VERSION 5.8 ;
BUSBITCHARS "[]" ;
DIVIDERCHAR "/" ;
UNITS
    DATABASE MICRONS 1000 ;
END UNITS

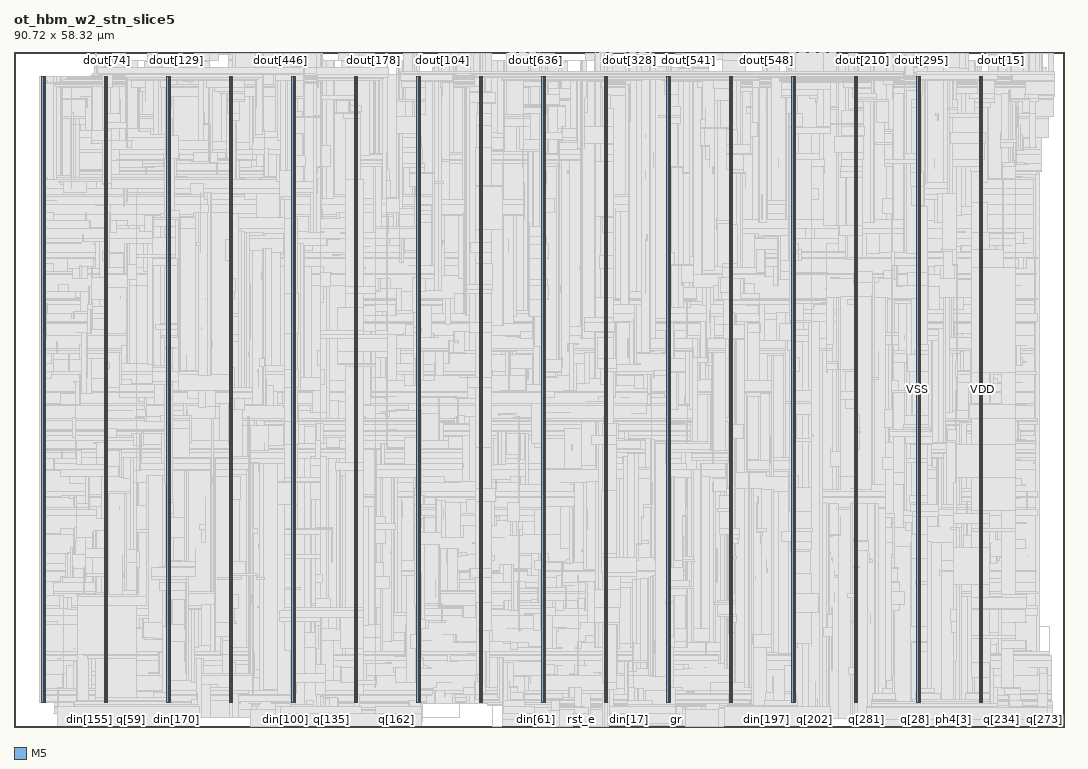
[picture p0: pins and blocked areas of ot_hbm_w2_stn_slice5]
MACRO ot_hbm_w2_stn_slice5
  FOREIGN ot_hbm_w2_stn_slice5 0 0 ;
  CLASS BLOCK ;
  SIZE 90.72 BY 58.32 ;
  PIN clk
    DIRECTION INPUT ;
    USE SIGNAL ;
    PORT
      LAYER M5 ;
        RECT  51.408 0 51.432 0.084 ;
    END
  END clk
  PIN din[0]
    DIRECTION INPUT ;
    USE SIGNAL ;
    PORT
      LAYER M5 ;
        RECT  51.504 0 51.528 0.084 ;
    END
  END din[0]
  PIN din[100]
    DIRECTION INPUT ;
    USE SIGNAL ;
    PORT
      LAYER M5 ;
        RECT  23.472 0 23.496 0.084 ;
    END
  END din[100]
  PIN din[101]
    DIRECTION INPUT ;
    USE SIGNAL ;
    PORT
      LAYER M5 ;
        RECT  23.568 0 23.592 0.084 ;
    END
  END din[101]
  PIN din[102]
    DIRECTION INPUT ;
    USE SIGNAL ;
    PORT
      LAYER M5 ;
        RECT  23.664 0 23.688 0.084 ;
    END
  END din[102]
  PIN din[103]
    DIRECTION INPUT ;
    USE SIGNAL ;
    PORT
      LAYER M5 ;
        RECT  23.76 0 23.784 0.084 ;
    END
  END din[103]
  PIN din[104]
    DIRECTION INPUT ;
    USE SIGNAL ;
    PORT
      LAYER M5 ;
        RECT  23.856 0 23.88 0.084 ;
    END
  END din[104]
  PIN din[105]
    DIRECTION INPUT ;
    USE SIGNAL ;
    PORT
      LAYER M5 ;
        RECT  23.952 0 23.976 0.084 ;
    END
  END din[105]
  PIN din[106]
    DIRECTION INPUT ;
    USE SIGNAL ;
    PORT
      LAYER M5 ;
        RECT  24.048 0 24.072 0.084 ;
    END
  END din[106]
  PIN din[107]
    DIRECTION INPUT ;
    USE SIGNAL ;
    PORT
      LAYER M5 ;
        RECT  24.144 0 24.168 0.084 ;
    END
  END din[107]
  PIN din[108]
    DIRECTION INPUT ;
    USE SIGNAL ;
    PORT
      LAYER M5 ;
        RECT  24.24 0 24.264 0.084 ;
    END
  END din[108]
  PIN din[109]
    DIRECTION INPUT ;
    USE SIGNAL ;
    PORT
      LAYER M5 ;
        RECT  24.336 0 24.36 0.084 ;
    END
  END din[109]
  PIN din[10]
    DIRECTION INPUT ;
    USE SIGNAL ;
    PORT
      LAYER M5 ;
        RECT  52.464 0 52.488 0.084 ;
    END
  END din[10]
  PIN din[110]
    DIRECTION INPUT ;
    USE SIGNAL ;
    PORT
      LAYER M5 ;
        RECT  24.432 0 24.456 0.084 ;
    END
  END din[110]
  PIN din[111]
    DIRECTION INPUT ;
    USE SIGNAL ;
    PORT
      LAYER M5 ;
        RECT  24.528 0 24.552 0.084 ;
    END
  END din[111]
  PIN din[112]
    DIRECTION INPUT ;
    USE SIGNAL ;
    PORT
      LAYER M5 ;
        RECT  24.624 0 24.648 0.084 ;
    END
  END din[112]
  PIN din[113]
    DIRECTION INPUT ;
    USE SIGNAL ;
    PORT
      LAYER M5 ;
        RECT  24.72 0 24.744 0.084 ;
    END
  END din[113]
  PIN din[114]
    DIRECTION INPUT ;
    USE SIGNAL ;
    PORT
      LAYER M5 ;
        RECT  24.816 0 24.84 0.084 ;
    END
  END din[114]
  PIN din[115]
    DIRECTION INPUT ;
    USE SIGNAL ;
    PORT
      LAYER M5 ;
        RECT  24.912 0 24.936 0.084 ;
    END
  END din[115]
  PIN din[116]
    DIRECTION INPUT ;
    USE SIGNAL ;
    PORT
      LAYER M5 ;
        RECT  25.008 0 25.032 0.084 ;
    END
  END din[116]
  PIN din[117]
    DIRECTION INPUT ;
    USE SIGNAL ;
    PORT
      LAYER M5 ;
        RECT  25.104 0 25.128 0.084 ;
    END
  END din[117]
  PIN din[118]
    DIRECTION INPUT ;
    USE SIGNAL ;
    PORT
      LAYER M5 ;
        RECT  25.2 0 25.224 0.084 ;
    END
  END din[118]
  PIN din[119]
    DIRECTION INPUT ;
    USE SIGNAL ;
    PORT
      LAYER M5 ;
        RECT  25.296 0 25.32 0.084 ;
    END
  END din[119]
  PIN din[11]
    DIRECTION INPUT ;
    USE SIGNAL ;
    PORT
      LAYER M5 ;
        RECT  52.56 0 52.584 0.084 ;
    END
  END din[11]
  PIN din[120]
    DIRECTION INPUT ;
    USE SIGNAL ;
    PORT
      LAYER M5 ;
        RECT  25.392 0 25.416 0.084 ;
    END
  END din[120]
  PIN din[121]
    DIRECTION INPUT ;
    USE SIGNAL ;
    PORT
      LAYER M5 ;
        RECT  25.488 0 25.512 0.084 ;
    END
  END din[121]
  PIN din[122]
    DIRECTION INPUT ;
    USE SIGNAL ;
    PORT
      LAYER M5 ;
        RECT  25.584 0 25.608 0.084 ;
    END
  END din[122]
  PIN din[123]
    DIRECTION INPUT ;
    USE SIGNAL ;
    PORT
      LAYER M5 ;
        RECT  25.68 0 25.704 0.084 ;
    END
  END din[123]
  PIN din[124]
    DIRECTION INPUT ;
    USE SIGNAL ;
    PORT
      LAYER M5 ;
        RECT  25.776 0 25.8 0.084 ;
    END
  END din[124]
  PIN din[125]
    DIRECTION INPUT ;
    USE SIGNAL ;
    PORT
      LAYER M5 ;
        RECT  25.872 0 25.896 0.084 ;
    END
  END din[125]
  PIN din[126]
    DIRECTION INPUT ;
    USE SIGNAL ;
    PORT
      LAYER M5 ;
        RECT  25.968 0 25.992 0.084 ;
    END
  END din[126]
  PIN din[127]
    DIRECTION INPUT ;
    USE SIGNAL ;
    PORT
      LAYER M5 ;
        RECT  3.792 0 3.816 0.084 ;
    END
  END din[127]
  PIN din[128]
    DIRECTION INPUT ;
    USE SIGNAL ;
    PORT
      LAYER M5 ;
        RECT  3.888 0 3.912 0.084 ;
    END
  END din[128]
  PIN din[129]
    DIRECTION INPUT ;
    USE SIGNAL ;
    PORT
      LAYER M5 ;
        RECT  3.984 0 4.008 0.084 ;
    END
  END din[129]
  PIN din[12]
    DIRECTION INPUT ;
    USE SIGNAL ;
    PORT
      LAYER M5 ;
        RECT  52.656 0 52.68 0.084 ;
    END
  END din[12]
  PIN din[130]
    DIRECTION INPUT ;
    USE SIGNAL ;
    PORT
      LAYER M5 ;
        RECT  4.08 0 4.104 0.084 ;
    END
  END din[130]
  PIN din[131]
    DIRECTION INPUT ;
    USE SIGNAL ;
    PORT
      LAYER M5 ;
        RECT  4.176 0 4.2 0.084 ;
    END
  END din[131]
  PIN din[132]
    DIRECTION INPUT ;
    USE SIGNAL ;
    PORT
      LAYER M5 ;
        RECT  4.272 0 4.296 0.084 ;
    END
  END din[132]
  PIN din[133]
    DIRECTION INPUT ;
    USE SIGNAL ;
    PORT
      LAYER M5 ;
        RECT  4.368 0 4.392 0.084 ;
    END
  END din[133]
  PIN din[134]
    DIRECTION INPUT ;
    USE SIGNAL ;
    PORT
      LAYER M5 ;
        RECT  4.464 0 4.488 0.084 ;
    END
  END din[134]
  PIN din[135]
    DIRECTION INPUT ;
    USE SIGNAL ;
    PORT
      LAYER M5 ;
        RECT  4.56 0 4.584 0.084 ;
    END
  END din[135]
  PIN din[136]
    DIRECTION INPUT ;
    USE SIGNAL ;
    PORT
      LAYER M5 ;
        RECT  4.656 0 4.68 0.084 ;
    END
  END din[136]
  PIN din[137]
    DIRECTION INPUT ;
    USE SIGNAL ;
    PORT
      LAYER M5 ;
        RECT  4.752 0 4.776 0.084 ;
    END
  END din[137]
  PIN din[138]
    DIRECTION INPUT ;
    USE SIGNAL ;
    PORT
      LAYER M5 ;
        RECT  4.848 0 4.872 0.084 ;
    END
  END din[138]
  PIN din[139]
    DIRECTION INPUT ;
    USE SIGNAL ;
    PORT
      LAYER M5 ;
        RECT  4.944 0 4.968 0.084 ;
    END
  END din[139]
  PIN din[13]
    DIRECTION INPUT ;
    USE SIGNAL ;
    PORT
      LAYER M5 ;
        RECT  52.752 0 52.776 0.084 ;
    END
  END din[13]
  PIN din[140]
    DIRECTION INPUT ;
    USE SIGNAL ;
    PORT
      LAYER M5 ;
        RECT  5.04 0 5.064 0.084 ;
    END
  END din[140]
  PIN din[141]
    DIRECTION INPUT ;
    USE SIGNAL ;
    PORT
      LAYER M5 ;
        RECT  5.136 0 5.16 0.084 ;
    END
  END din[141]
  PIN din[142]
    DIRECTION INPUT ;
    USE SIGNAL ;
    PORT
      LAYER M5 ;
        RECT  5.232 0 5.256 0.084 ;
    END
  END din[142]
  PIN din[143]
    DIRECTION INPUT ;
    USE SIGNAL ;
    PORT
      LAYER M5 ;
        RECT  5.328 0 5.352 0.084 ;
    END
  END din[143]
  PIN din[144]
    DIRECTION INPUT ;
    USE SIGNAL ;
    PORT
      LAYER M5 ;
        RECT  5.424 0 5.448 0.084 ;
    END
  END din[144]
  PIN din[145]
    DIRECTION INPUT ;
    USE SIGNAL ;
    PORT
      LAYER M5 ;
        RECT  5.52 0 5.544 0.084 ;
    END
  END din[145]
  PIN din[146]
    DIRECTION INPUT ;
    USE SIGNAL ;
    PORT
      LAYER M5 ;
        RECT  5.616 0 5.64 0.084 ;
    END
  END din[146]
  PIN din[147]
    DIRECTION INPUT ;
    USE SIGNAL ;
    PORT
      LAYER M5 ;
        RECT  5.712 0 5.736 0.084 ;
    END
  END din[147]
  PIN din[148]
    DIRECTION INPUT ;
    USE SIGNAL ;
    PORT
      LAYER M5 ;
        RECT  5.808 0 5.832 0.084 ;
    END
  END din[148]
  PIN din[149]
    DIRECTION INPUT ;
    USE SIGNAL ;
    PORT
      LAYER M5 ;
        RECT  5.904 0 5.928 0.084 ;
    END
  END din[149]
  PIN din[14]
    DIRECTION INPUT ;
    USE SIGNAL ;
    PORT
      LAYER M5 ;
        RECT  52.848 0 52.872 0.084 ;
    END
  END din[14]
  PIN din[150]
    DIRECTION INPUT ;
    USE SIGNAL ;
    PORT
      LAYER M5 ;
        RECT  6 0 6.024 0.084 ;
    END
  END din[150]
  PIN din[151]
    DIRECTION INPUT ;
    USE SIGNAL ;
    PORT
      LAYER M5 ;
        RECT  6.096 0 6.12 0.084 ;
    END
  END din[151]
  PIN din[152]
    DIRECTION INPUT ;
    USE SIGNAL ;
    PORT
      LAYER M5 ;
        RECT  6.192 0 6.216 0.084 ;
    END
  END din[152]
  PIN din[153]
    DIRECTION INPUT ;
    USE SIGNAL ;
    PORT
      LAYER M5 ;
        RECT  6.288 0 6.312 0.084 ;
    END
  END din[153]
  PIN din[154]
    DIRECTION INPUT ;
    USE SIGNAL ;
    PORT
      LAYER M5 ;
        RECT  6.384 0 6.408 0.084 ;
    END
  END din[154]
  PIN din[155]
    DIRECTION INPUT ;
    USE SIGNAL ;
    PORT
      LAYER M5 ;
        RECT  6.48 0 6.504 0.084 ;
    END
  END din[155]
  PIN din[156]
    DIRECTION INPUT ;
    USE SIGNAL ;
    PORT
      LAYER M5 ;
        RECT  6.576 0 6.6 0.084 ;
    END
  END din[156]
  PIN din[157]
    DIRECTION INPUT ;
    USE SIGNAL ;
    PORT
      LAYER M5 ;
        RECT  6.672 0 6.696 0.084 ;
    END
  END din[157]
  PIN din[158]
    DIRECTION INPUT ;
    USE SIGNAL ;
    PORT
      LAYER M5 ;
        RECT  6.768 0 6.792 0.084 ;
    END
  END din[158]
  PIN din[159]
    DIRECTION INPUT ;
    USE SIGNAL ;
    PORT
      LAYER M5 ;
        RECT  13.008 0 13.032 0.084 ;
    END
  END din[159]
  PIN din[15]
    DIRECTION INPUT ;
    USE SIGNAL ;
    PORT
      LAYER M5 ;
        RECT  52.944 0 52.968 0.084 ;
    END
  END din[15]
  PIN din[160]
    DIRECTION INPUT ;
    USE SIGNAL ;
    PORT
      LAYER M5 ;
        RECT  13.104 0 13.128 0.084 ;
    END
  END din[160]
  PIN din[161]
    DIRECTION INPUT ;
    USE SIGNAL ;
    PORT
      LAYER M5 ;
        RECT  13.2 0 13.224 0.084 ;
    END
  END din[161]
  PIN din[162]
    DIRECTION INPUT ;
    USE SIGNAL ;
    PORT
      LAYER M5 ;
        RECT  13.296 0 13.32 0.084 ;
    END
  END din[162]
  PIN din[163]
    DIRECTION INPUT ;
    USE SIGNAL ;
    PORT
      LAYER M5 ;
        RECT  13.392 0 13.416 0.084 ;
    END
  END din[163]
  PIN din[164]
    DIRECTION INPUT ;
    USE SIGNAL ;
    PORT
      LAYER M5 ;
        RECT  13.488 0 13.512 0.084 ;
    END
  END din[164]
  PIN din[165]
    DIRECTION INPUT ;
    USE SIGNAL ;
    PORT
      LAYER M5 ;
        RECT  13.584 0 13.608 0.084 ;
    END
  END din[165]
  PIN din[166]
    DIRECTION INPUT ;
    USE SIGNAL ;
    PORT
      LAYER M5 ;
        RECT  13.68 0 13.704 0.084 ;
    END
  END din[166]
  PIN din[167]
    DIRECTION INPUT ;
    USE SIGNAL ;
    PORT
      LAYER M5 ;
        RECT  13.776 0 13.8 0.084 ;
    END
  END din[167]
  PIN din[168]
    DIRECTION INPUT ;
    USE SIGNAL ;
    PORT
      LAYER M5 ;
        RECT  13.872 0 13.896 0.084 ;
    END
  END din[168]
  PIN din[169]
    DIRECTION INPUT ;
    USE SIGNAL ;
    PORT
      LAYER M5 ;
        RECT  13.968 0 13.992 0.084 ;
    END
  END din[169]
  PIN din[16]
    DIRECTION INPUT ;
    USE SIGNAL ;
    PORT
      LAYER M5 ;
        RECT  53.04 0 53.064 0.084 ;
    END
  END din[16]
  PIN din[170]
    DIRECTION INPUT ;
    USE SIGNAL ;
    PORT
      LAYER M5 ;
        RECT  14.064 0 14.088 0.084 ;
    END
  END din[170]
  PIN din[171]
    DIRECTION INPUT ;
    USE SIGNAL ;
    PORT
      LAYER M5 ;
        RECT  14.16 0 14.184 0.084 ;
    END
  END din[171]
  PIN din[172]
    DIRECTION INPUT ;
    USE SIGNAL ;
    PORT
      LAYER M5 ;
        RECT  14.256 0 14.28 0.084 ;
    END
  END din[172]
  PIN din[173]
    DIRECTION INPUT ;
    USE SIGNAL ;
    PORT
      LAYER M5 ;
        RECT  14.352 0 14.376 0.084 ;
    END
  END din[173]
  PIN din[174]
    DIRECTION INPUT ;
    USE SIGNAL ;
    PORT
      LAYER M5 ;
        RECT  14.448 0 14.472 0.084 ;
    END
  END din[174]
  PIN din[175]
    DIRECTION INPUT ;
    USE SIGNAL ;
    PORT
      LAYER M5 ;
        RECT  14.544 0 14.568 0.084 ;
    END
  END din[175]
  PIN din[176]
    DIRECTION INPUT ;
    USE SIGNAL ;
    PORT
      LAYER M5 ;
        RECT  14.64 0 14.664 0.084 ;
    END
  END din[176]
  PIN din[177]
    DIRECTION INPUT ;
    USE SIGNAL ;
    PORT
      LAYER M5 ;
        RECT  14.736 0 14.76 0.084 ;
    END
  END din[177]
  PIN din[178]
    DIRECTION INPUT ;
    USE SIGNAL ;
    PORT
      LAYER M5 ;
        RECT  14.832 0 14.856 0.084 ;
    END
  END din[178]
  PIN din[179]
    DIRECTION INPUT ;
    USE SIGNAL ;
    PORT
      LAYER M5 ;
        RECT  14.928 0 14.952 0.084 ;
    END
  END din[179]
  PIN din[17]
    DIRECTION INPUT ;
    USE SIGNAL ;
    PORT
      LAYER M5 ;
        RECT  53.136 0 53.16 0.084 ;
    END
  END din[17]
  PIN din[180]
    DIRECTION INPUT ;
    USE SIGNAL ;
    PORT
      LAYER M5 ;
        RECT  15.024 0 15.048 0.084 ;
    END
  END din[180]
  PIN din[181]
    DIRECTION INPUT ;
    USE SIGNAL ;
    PORT
      LAYER M5 ;
        RECT  15.12 0 15.144 0.084 ;
    END
  END din[181]
  PIN din[182]
    DIRECTION INPUT ;
    USE SIGNAL ;
    PORT
      LAYER M5 ;
        RECT  15.216 0 15.24 0.084 ;
    END
  END din[182]
  PIN din[183]
    DIRECTION INPUT ;
    USE SIGNAL ;
    PORT
      LAYER M5 ;
        RECT  15.312 0 15.336 0.084 ;
    END
  END din[183]
  PIN din[184]
    DIRECTION INPUT ;
    USE SIGNAL ;
    PORT
      LAYER M5 ;
        RECT  15.408 0 15.432 0.084 ;
    END
  END din[184]
  PIN din[185]
    DIRECTION INPUT ;
    USE SIGNAL ;
    PORT
      LAYER M5 ;
        RECT  15.504 0 15.528 0.084 ;
    END
  END din[185]
  PIN din[186]
    DIRECTION INPUT ;
    USE SIGNAL ;
    PORT
      LAYER M5 ;
        RECT  15.6 0 15.624 0.084 ;
    END
  END din[186]
  PIN din[187]
    DIRECTION INPUT ;
    USE SIGNAL ;
    PORT
      LAYER M5 ;
        RECT  15.696 0 15.72 0.084 ;
    END
  END din[187]
  PIN din[188]
    DIRECTION INPUT ;
    USE SIGNAL ;
    PORT
      LAYER M5 ;
        RECT  15.792 0 15.816 0.084 ;
    END
  END din[188]
  PIN din[189]
    DIRECTION INPUT ;
    USE SIGNAL ;
    PORT
      LAYER M5 ;
        RECT  15.888 0 15.912 0.084 ;
    END
  END din[189]
  PIN din[18]
    DIRECTION INPUT ;
    USE SIGNAL ;
    PORT
      LAYER M5 ;
        RECT  53.232 0 53.256 0.084 ;
    END
  END din[18]
  PIN din[190]
    DIRECTION INPUT ;
    USE SIGNAL ;
    PORT
      LAYER M5 ;
        RECT  15.984 0 16.008 0.084 ;
    END
  END din[190]
  PIN din[191]
    DIRECTION INPUT ;
    USE SIGNAL ;
    PORT
      LAYER M5 ;
        RECT  64.464 0 64.488 0.084 ;
    END
  END din[191]
  PIN din[192]
    DIRECTION INPUT ;
    USE SIGNAL ;
    PORT
      LAYER M5 ;
        RECT  64.56 0 64.584 0.084 ;
    END
  END din[192]
  PIN din[193]
    DIRECTION INPUT ;
    USE SIGNAL ;
    PORT
      LAYER M5 ;
        RECT  64.656 0 64.68 0.084 ;
    END
  END din[193]
  PIN din[194]
    DIRECTION INPUT ;
    USE SIGNAL ;
    PORT
      LAYER M5 ;
        RECT  64.752 0 64.776 0.084 ;
    END
  END din[194]
  PIN din[195]
    DIRECTION INPUT ;
    USE SIGNAL ;
    PORT
      LAYER M5 ;
        RECT  64.848 0 64.872 0.084 ;
    END
  END din[195]
  PIN din[196]
    DIRECTION INPUT ;
    USE SIGNAL ;
    PORT
      LAYER M5 ;
        RECT  64.944 0 64.968 0.084 ;
    END
  END din[196]
  PIN din[197]
    DIRECTION INPUT ;
    USE SIGNAL ;
    PORT
      LAYER M5 ;
        RECT  65.04 0 65.064 0.084 ;
    END
  END din[197]
  PIN din[198]
    DIRECTION INPUT ;
    USE SIGNAL ;
    PORT
      LAYER M5 ;
        RECT  65.136 0 65.16 0.084 ;
    END
  END din[198]
  PIN din[199]
    DIRECTION INPUT ;
    USE SIGNAL ;
    PORT
      LAYER M5 ;
        RECT  65.232 0 65.256 0.084 ;
    END
  END din[199]
  PIN din[19]
    DIRECTION INPUT ;
    USE SIGNAL ;
    PORT
      LAYER M5 ;
        RECT  53.328 0 53.352 0.084 ;
    END
  END din[19]
  PIN din[1]
    DIRECTION INPUT ;
    USE SIGNAL ;
    PORT
      LAYER M5 ;
        RECT  51.6 0 51.624 0.084 ;
    END
  END din[1]
  PIN din[200]
    DIRECTION INPUT ;
    USE SIGNAL ;
    PORT
      LAYER M5 ;
        RECT  65.328 0 65.352 0.084 ;
    END
  END din[200]
  PIN din[201]
    DIRECTION INPUT ;
    USE SIGNAL ;
    PORT
      LAYER M5 ;
        RECT  65.424 0 65.448 0.084 ;
    END
  END din[201]
  PIN din[202]
    DIRECTION INPUT ;
    USE SIGNAL ;
    PORT
      LAYER M5 ;
        RECT  65.52 0 65.544 0.084 ;
    END
  END din[202]
  PIN din[203]
    DIRECTION INPUT ;
    USE SIGNAL ;
    PORT
      LAYER M5 ;
        RECT  65.616 0 65.64 0.084 ;
    END
  END din[203]
  PIN din[204]
    DIRECTION INPUT ;
    USE SIGNAL ;
    PORT
      LAYER M5 ;
        RECT  65.712 0 65.736 0.084 ;
    END
  END din[204]
  PIN din[205]
    DIRECTION INPUT ;
    USE SIGNAL ;
    PORT
      LAYER M5 ;
        RECT  65.808 0 65.832 0.084 ;
    END
  END din[205]
  PIN din[206]
    DIRECTION INPUT ;
    USE SIGNAL ;
    PORT
      LAYER M5 ;
        RECT  65.904 0 65.928 0.084 ;
    END
  END din[206]
  PIN din[207]
    DIRECTION INPUT ;
    USE SIGNAL ;
    PORT
      LAYER M5 ;
        RECT  66 0 66.024 0.084 ;
    END
  END din[207]
  PIN din[208]
    DIRECTION INPUT ;
    USE SIGNAL ;
    PORT
      LAYER M5 ;
        RECT  66.096 0 66.12 0.084 ;
    END
  END din[208]
  PIN din[209]
    DIRECTION INPUT ;
    USE SIGNAL ;
    PORT
      LAYER M5 ;
        RECT  66.192 0 66.216 0.084 ;
    END
  END din[209]
  PIN din[20]
    DIRECTION INPUT ;
    USE SIGNAL ;
    PORT
      LAYER M5 ;
        RECT  53.424 0 53.448 0.084 ;
    END
  END din[20]
  PIN din[210]
    DIRECTION INPUT ;
    USE SIGNAL ;
    PORT
      LAYER M5 ;
        RECT  66.288 0 66.312 0.084 ;
    END
  END din[210]
  PIN din[211]
    DIRECTION INPUT ;
    USE SIGNAL ;
    PORT
      LAYER M5 ;
        RECT  66.384 0 66.408 0.084 ;
    END
  END din[211]
  PIN din[212]
    DIRECTION INPUT ;
    USE SIGNAL ;
    PORT
      LAYER M5 ;
        RECT  66.48 0 66.504 0.084 ;
    END
  END din[212]
  PIN din[213]
    DIRECTION INPUT ;
    USE SIGNAL ;
    PORT
      LAYER M5 ;
        RECT  66.576 0 66.6 0.084 ;
    END
  END din[213]
  PIN din[214]
    DIRECTION INPUT ;
    USE SIGNAL ;
    PORT
      LAYER M5 ;
        RECT  66.672 0 66.696 0.084 ;
    END
  END din[214]
  PIN din[215]
    DIRECTION INPUT ;
    USE SIGNAL ;
    PORT
      LAYER M5 ;
        RECT  66.768 0 66.792 0.084 ;
    END
  END din[215]
  PIN din[216]
    DIRECTION INPUT ;
    USE SIGNAL ;
    PORT
      LAYER M5 ;
        RECT  66.864 0 66.888 0.084 ;
    END
  END din[216]
  PIN din[217]
    DIRECTION INPUT ;
    USE SIGNAL ;
    PORT
      LAYER M5 ;
        RECT  66.96 0 66.984 0.084 ;
    END
  END din[217]
  PIN din[218]
    DIRECTION INPUT ;
    USE SIGNAL ;
    PORT
      LAYER M5 ;
        RECT  67.056 0 67.08 0.084 ;
    END
  END din[218]
  PIN din[219]
    DIRECTION INPUT ;
    USE SIGNAL ;
    PORT
      LAYER M5 ;
        RECT  67.152 0 67.176 0.084 ;
    END
  END din[219]
  PIN din[21]
    DIRECTION INPUT ;
    USE SIGNAL ;
    PORT
      LAYER M5 ;
        RECT  53.52 0 53.544 0.084 ;
    END
  END din[21]
  PIN din[220]
    DIRECTION INPUT ;
    USE SIGNAL ;
    PORT
      LAYER M5 ;
        RECT  67.248 0 67.272 0.084 ;
    END
  END din[220]
  PIN din[221]
    DIRECTION INPUT ;
    USE SIGNAL ;
    PORT
      LAYER M5 ;
        RECT  67.344 0 67.368 0.084 ;
    END
  END din[221]
  PIN din[222]
    DIRECTION INPUT ;
    USE SIGNAL ;
    PORT
      LAYER M5 ;
        RECT  67.44 0 67.464 0.084 ;
    END
  END din[222]
  PIN din[223]
    DIRECTION INPUT ;
    USE SIGNAL ;
    PORT
      LAYER M5 ;
        RECT  61.392 0 61.416 0.084 ;
    END
  END din[223]
  PIN din[224]
    DIRECTION INPUT ;
    USE SIGNAL ;
    PORT
      LAYER M5 ;
        RECT  61.488 0 61.512 0.084 ;
    END
  END din[224]
  PIN din[225]
    DIRECTION INPUT ;
    USE SIGNAL ;
    PORT
      LAYER M5 ;
        RECT  61.584 0 61.608 0.084 ;
    END
  END din[225]
  PIN din[226]
    DIRECTION INPUT ;
    USE SIGNAL ;
    PORT
      LAYER M5 ;
        RECT  61.68 0 61.704 0.084 ;
    END
  END din[226]
  PIN din[227]
    DIRECTION INPUT ;
    USE SIGNAL ;
    PORT
      LAYER M5 ;
        RECT  61.776 0 61.8 0.084 ;
    END
  END din[227]
  PIN din[228]
    DIRECTION INPUT ;
    USE SIGNAL ;
    PORT
      LAYER M5 ;
        RECT  61.872 0 61.896 0.084 ;
    END
  END din[228]
  PIN din[229]
    DIRECTION INPUT ;
    USE SIGNAL ;
    PORT
      LAYER M5 ;
        RECT  61.968 0 61.992 0.084 ;
    END
  END din[229]
  PIN din[22]
    DIRECTION INPUT ;
    USE SIGNAL ;
    PORT
      LAYER M5 ;
        RECT  53.616 0 53.64 0.084 ;
    END
  END din[22]
  PIN din[230]
    DIRECTION INPUT ;
    USE SIGNAL ;
    PORT
      LAYER M5 ;
        RECT  62.064 0 62.088 0.084 ;
    END
  END din[230]
  PIN din[231]
    DIRECTION INPUT ;
    USE SIGNAL ;
    PORT
      LAYER M5 ;
        RECT  62.16 0 62.184 0.084 ;
    END
  END din[231]
  PIN din[232]
    DIRECTION INPUT ;
    USE SIGNAL ;
    PORT
      LAYER M5 ;
        RECT  62.256 0 62.28 0.084 ;
    END
  END din[232]
  PIN din[233]
    DIRECTION INPUT ;
    USE SIGNAL ;
    PORT
      LAYER M5 ;
        RECT  62.352 0 62.376 0.084 ;
    END
  END din[233]
  PIN din[234]
    DIRECTION INPUT ;
    USE SIGNAL ;
    PORT
      LAYER M5 ;
        RECT  62.448 0 62.472 0.084 ;
    END
  END din[234]
  PIN din[235]
    DIRECTION INPUT ;
    USE SIGNAL ;
    PORT
      LAYER M5 ;
        RECT  62.544 0 62.568 0.084 ;
    END
  END din[235]
  PIN din[236]
    DIRECTION INPUT ;
    USE SIGNAL ;
    PORT
      LAYER M5 ;
        RECT  62.64 0 62.664 0.084 ;
    END
  END din[236]
  PIN din[237]
    DIRECTION INPUT ;
    USE SIGNAL ;
    PORT
      LAYER M5 ;
        RECT  62.736 0 62.76 0.084 ;
    END
  END din[237]
  PIN din[238]
    DIRECTION INPUT ;
    USE SIGNAL ;
    PORT
      LAYER M5 ;
        RECT  62.832 0 62.856 0.084 ;
    END
  END din[238]
  PIN din[239]
    DIRECTION INPUT ;
    USE SIGNAL ;
    PORT
      LAYER M5 ;
        RECT  62.928 0 62.952 0.084 ;
    END
  END din[239]
  PIN din[23]
    DIRECTION INPUT ;
    USE SIGNAL ;
    PORT
      LAYER M5 ;
        RECT  53.712 0 53.736 0.084 ;
    END
  END din[23]
  PIN din[240]
    DIRECTION INPUT ;
    USE SIGNAL ;
    PORT
      LAYER M5 ;
        RECT  63.024 0 63.048 0.084 ;
    END
  END din[240]
  PIN din[241]
    DIRECTION INPUT ;
    USE SIGNAL ;
    PORT
      LAYER M5 ;
        RECT  63.12 0 63.144 0.084 ;
    END
  END din[241]
  PIN din[242]
    DIRECTION INPUT ;
    USE SIGNAL ;
    PORT
      LAYER M5 ;
        RECT  63.216 0 63.24 0.084 ;
    END
  END din[242]
  PIN din[243]
    DIRECTION INPUT ;
    USE SIGNAL ;
    PORT
      LAYER M5 ;
        RECT  63.312 0 63.336 0.084 ;
    END
  END din[243]
  PIN din[244]
    DIRECTION INPUT ;
    USE SIGNAL ;
    PORT
      LAYER M5 ;
        RECT  63.408 0 63.432 0.084 ;
    END
  END din[244]
  PIN din[245]
    DIRECTION INPUT ;
    USE SIGNAL ;
    PORT
      LAYER M5 ;
        RECT  63.504 0 63.528 0.084 ;
    END
  END din[245]
  PIN din[246]
    DIRECTION INPUT ;
    USE SIGNAL ;
    PORT
      LAYER M5 ;
        RECT  63.6 0 63.624 0.084 ;
    END
  END din[246]
  PIN din[247]
    DIRECTION INPUT ;
    USE SIGNAL ;
    PORT
      LAYER M5 ;
        RECT  63.696 0 63.72 0.084 ;
    END
  END din[247]
  PIN din[248]
    DIRECTION INPUT ;
    USE SIGNAL ;
    PORT
      LAYER M5 ;
        RECT  63.792 0 63.816 0.084 ;
    END
  END din[248]
  PIN din[249]
    DIRECTION INPUT ;
    USE SIGNAL ;
    PORT
      LAYER M5 ;
        RECT  63.888 0 63.912 0.084 ;
    END
  END din[249]
  PIN din[24]
    DIRECTION INPUT ;
    USE SIGNAL ;
    PORT
      LAYER M5 ;
        RECT  53.808 0 53.832 0.084 ;
    END
  END din[24]
  PIN din[250]
    DIRECTION INPUT ;
    USE SIGNAL ;
    PORT
      LAYER M5 ;
        RECT  63.984 0 64.008 0.084 ;
    END
  END din[250]
  PIN din[251]
    DIRECTION INPUT ;
    USE SIGNAL ;
    PORT
      LAYER M5 ;
        RECT  64.08 0 64.104 0.084 ;
    END
  END din[251]
  PIN din[252]
    DIRECTION INPUT ;
    USE SIGNAL ;
    PORT
      LAYER M5 ;
        RECT  64.176 0 64.2 0.084 ;
    END
  END din[252]
  PIN din[253]
    DIRECTION INPUT ;
    USE SIGNAL ;
    PORT
      LAYER M5 ;
        RECT  64.272 0 64.296 0.084 ;
    END
  END din[253]
  PIN din[254]
    DIRECTION INPUT ;
    USE SIGNAL ;
    PORT
      LAYER M5 ;
        RECT  64.368 0 64.392 0.084 ;
    END
  END din[254]
  PIN din[255]
    DIRECTION INPUT ;
    USE SIGNAL ;
    PORT
      LAYER M5 ;
        RECT  54.48 0 54.504 0.084 ;
    END
  END din[255]
  PIN din[256]
    DIRECTION INPUT ;
    USE SIGNAL ;
    PORT
      LAYER M5 ;
        RECT  54.576 0 54.6 0.084 ;
    END
  END din[256]
  PIN din[257]
    DIRECTION INPUT ;
    USE SIGNAL ;
    PORT
      LAYER M5 ;
        RECT  54.672 0 54.696 0.084 ;
    END
  END din[257]
  PIN din[258]
    DIRECTION INPUT ;
    USE SIGNAL ;
    PORT
      LAYER M5 ;
        RECT  54.768 0 54.792 0.084 ;
    END
  END din[258]
  PIN din[259]
    DIRECTION INPUT ;
    USE SIGNAL ;
    PORT
      LAYER M5 ;
        RECT  54.864 0 54.888 0.084 ;
    END
  END din[259]
  PIN din[25]
    DIRECTION INPUT ;
    USE SIGNAL ;
    PORT
      LAYER M5 ;
        RECT  53.904 0 53.928 0.084 ;
    END
  END din[25]
  PIN din[260]
    DIRECTION INPUT ;
    USE SIGNAL ;
    PORT
      LAYER M5 ;
        RECT  54.96 0 54.984 0.084 ;
    END
  END din[260]
  PIN din[261]
    DIRECTION INPUT ;
    USE SIGNAL ;
    PORT
      LAYER M5 ;
        RECT  55.056 0 55.08 0.084 ;
    END
  END din[261]
  PIN din[262]
    DIRECTION INPUT ;
    USE SIGNAL ;
    PORT
      LAYER M5 ;
        RECT  55.152 0 55.176 0.084 ;
    END
  END din[262]
  PIN din[263]
    DIRECTION INPUT ;
    USE SIGNAL ;
    PORT
      LAYER M5 ;
        RECT  55.248 0 55.272 0.084 ;
    END
  END din[263]
  PIN din[264]
    DIRECTION INPUT ;
    USE SIGNAL ;
    PORT
      LAYER M5 ;
        RECT  55.344 0 55.368 0.084 ;
    END
  END din[264]
  PIN din[265]
    DIRECTION INPUT ;
    USE SIGNAL ;
    PORT
      LAYER M5 ;
        RECT  55.44 0 55.464 0.084 ;
    END
  END din[265]
  PIN din[266]
    DIRECTION INPUT ;
    USE SIGNAL ;
    PORT
      LAYER M5 ;
        RECT  55.536 0 55.56 0.084 ;
    END
  END din[266]
  PIN din[267]
    DIRECTION INPUT ;
    USE SIGNAL ;
    PORT
      LAYER M5 ;
        RECT  55.632 0 55.656 0.084 ;
    END
  END din[267]
  PIN din[268]
    DIRECTION INPUT ;
    USE SIGNAL ;
    PORT
      LAYER M5 ;
        RECT  55.728 0 55.752 0.084 ;
    END
  END din[268]
  PIN din[269]
    DIRECTION INPUT ;
    USE SIGNAL ;
    PORT
      LAYER M5 ;
        RECT  55.824 0 55.848 0.084 ;
    END
  END din[269]
  PIN din[26]
    DIRECTION INPUT ;
    USE SIGNAL ;
    PORT
      LAYER M5 ;
        RECT  54 0 54.024 0.084 ;
    END
  END din[26]
  PIN din[270]
    DIRECTION INPUT ;
    USE SIGNAL ;
    PORT
      LAYER M5 ;
        RECT  55.92 0 55.944 0.084 ;
    END
  END din[270]
  PIN din[271]
    DIRECTION INPUT ;
    USE SIGNAL ;
    PORT
      LAYER M5 ;
        RECT  56.016 0 56.04 0.084 ;
    END
  END din[271]
  PIN din[272]
    DIRECTION INPUT ;
    USE SIGNAL ;
    PORT
      LAYER M5 ;
        RECT  56.112 0 56.136 0.084 ;
    END
  END din[272]
  PIN din[273]
    DIRECTION INPUT ;
    USE SIGNAL ;
    PORT
      LAYER M5 ;
        RECT  56.208 0 56.232 0.084 ;
    END
  END din[273]
  PIN din[274]
    DIRECTION INPUT ;
    USE SIGNAL ;
    PORT
      LAYER M5 ;
        RECT  56.304 0 56.328 0.084 ;
    END
  END din[274]
  PIN din[275]
    DIRECTION INPUT ;
    USE SIGNAL ;
    PORT
      LAYER M5 ;
        RECT  56.4 0 56.424 0.084 ;
    END
  END din[275]
  PIN din[276]
    DIRECTION INPUT ;
    USE SIGNAL ;
    PORT
      LAYER M5 ;
        RECT  56.496 0 56.52 0.084 ;
    END
  END din[276]
  PIN din[277]
    DIRECTION INPUT ;
    USE SIGNAL ;
    PORT
      LAYER M5 ;
        RECT  56.592 0 56.616 0.084 ;
    END
  END din[277]
  PIN din[278]
    DIRECTION INPUT ;
    USE SIGNAL ;
    PORT
      LAYER M5 ;
        RECT  56.688 0 56.712 0.084 ;
    END
  END din[278]
  PIN din[279]
    DIRECTION INPUT ;
    USE SIGNAL ;
    PORT
      LAYER M5 ;
        RECT  56.784 0 56.808 0.084 ;
    END
  END din[279]
  PIN din[27]
    DIRECTION INPUT ;
    USE SIGNAL ;
    PORT
      LAYER M5 ;
        RECT  54.096 0 54.12 0.084 ;
    END
  END din[27]
  PIN din[28]
    DIRECTION INPUT ;
    USE SIGNAL ;
    PORT
      LAYER M5 ;
        RECT  54.192 0 54.216 0.084 ;
    END
  END din[28]
  PIN din[29]
    DIRECTION INPUT ;
    USE SIGNAL ;
    PORT
      LAYER M5 ;
        RECT  54.288 0 54.312 0.084 ;
    END
  END din[29]
  PIN din[2]
    DIRECTION INPUT ;
    USE SIGNAL ;
    PORT
      LAYER M5 ;
        RECT  51.696 0 51.72 0.084 ;
    END
  END din[2]
  PIN din[30]
    DIRECTION INPUT ;
    USE SIGNAL ;
    PORT
      LAYER M5 ;
        RECT  54.384 0 54.408 0.084 ;
    END
  END din[30]
  PIN din[31]
    DIRECTION INPUT ;
    USE SIGNAL ;
    PORT
      LAYER M5 ;
        RECT  42.192 0 42.216 0.084 ;
    END
  END din[31]
  PIN din[32]
    DIRECTION INPUT ;
    USE SIGNAL ;
    PORT
      LAYER M5 ;
        RECT  42.288 0 42.312 0.084 ;
    END
  END din[32]
  PIN din[33]
    DIRECTION INPUT ;
    USE SIGNAL ;
    PORT
      LAYER M5 ;
        RECT  42.384 0 42.408 0.084 ;
    END
  END din[33]
  PIN din[34]
    DIRECTION INPUT ;
    USE SIGNAL ;
    PORT
      LAYER M5 ;
        RECT  42.48 0 42.504 0.084 ;
    END
  END din[34]
  PIN din[35]
    DIRECTION INPUT ;
    USE SIGNAL ;
    PORT
      LAYER M5 ;
        RECT  42.576 0 42.6 0.084 ;
    END
  END din[35]
  PIN din[36]
    DIRECTION INPUT ;
    USE SIGNAL ;
    PORT
      LAYER M5 ;
        RECT  42.672 0 42.696 0.084 ;
    END
  END din[36]
  PIN din[37]
    DIRECTION INPUT ;
    USE SIGNAL ;
    PORT
      LAYER M5 ;
        RECT  42.768 0 42.792 0.084 ;
    END
  END din[37]
  PIN din[38]
    DIRECTION INPUT ;
    USE SIGNAL ;
    PORT
      LAYER M5 ;
        RECT  42.864 0 42.888 0.084 ;
    END
  END din[38]
  PIN din[39]
    DIRECTION INPUT ;
    USE SIGNAL ;
    PORT
      LAYER M5 ;
        RECT  42.96 0 42.984 0.084 ;
    END
  END din[39]
  PIN din[3]
    DIRECTION INPUT ;
    USE SIGNAL ;
    PORT
      LAYER M5 ;
        RECT  51.792 0 51.816 0.084 ;
    END
  END din[3]
  PIN din[40]
    DIRECTION INPUT ;
    USE SIGNAL ;
    PORT
      LAYER M5 ;
        RECT  43.056 0 43.08 0.084 ;
    END
  END din[40]
  PIN din[41]
    DIRECTION INPUT ;
    USE SIGNAL ;
    PORT
      LAYER M5 ;
        RECT  43.152 0 43.176 0.084 ;
    END
  END din[41]
  PIN din[42]
    DIRECTION INPUT ;
    USE SIGNAL ;
    PORT
      LAYER M5 ;
        RECT  43.248 0 43.272 0.084 ;
    END
  END din[42]
  PIN din[43]
    DIRECTION INPUT ;
    USE SIGNAL ;
    PORT
      LAYER M5 ;
        RECT  43.344 0 43.368 0.084 ;
    END
  END din[43]
  PIN din[44]
    DIRECTION INPUT ;
    USE SIGNAL ;
    PORT
      LAYER M5 ;
        RECT  43.44 0 43.464 0.084 ;
    END
  END din[44]
  PIN din[45]
    DIRECTION INPUT ;
    USE SIGNAL ;
    PORT
      LAYER M5 ;
        RECT  43.536 0 43.56 0.084 ;
    END
  END din[45]
  PIN din[46]
    DIRECTION INPUT ;
    USE SIGNAL ;
    PORT
      LAYER M5 ;
        RECT  43.632 0 43.656 0.084 ;
    END
  END din[46]
  PIN din[47]
    DIRECTION INPUT ;
    USE SIGNAL ;
    PORT
      LAYER M5 ;
        RECT  43.728 0 43.752 0.084 ;
    END
  END din[47]
  PIN din[48]
    DIRECTION INPUT ;
    USE SIGNAL ;
    PORT
      LAYER M5 ;
        RECT  43.824 0 43.848 0.084 ;
    END
  END din[48]
  PIN din[49]
    DIRECTION INPUT ;
    USE SIGNAL ;
    PORT
      LAYER M5 ;
        RECT  43.92 0 43.944 0.084 ;
    END
  END din[49]
  PIN din[4]
    DIRECTION INPUT ;
    USE SIGNAL ;
    PORT
      LAYER M5 ;
        RECT  51.888 0 51.912 0.084 ;
    END
  END din[4]
  PIN din[50]
    DIRECTION INPUT ;
    USE SIGNAL ;
    PORT
      LAYER M5 ;
        RECT  44.016 0 44.04 0.084 ;
    END
  END din[50]
  PIN din[51]
    DIRECTION INPUT ;
    USE SIGNAL ;
    PORT
      LAYER M5 ;
        RECT  44.112 0 44.136 0.084 ;
    END
  END din[51]
  PIN din[52]
    DIRECTION INPUT ;
    USE SIGNAL ;
    PORT
      LAYER M5 ;
        RECT  44.208 0 44.232 0.084 ;
    END
  END din[52]
  PIN din[53]
    DIRECTION INPUT ;
    USE SIGNAL ;
    PORT
      LAYER M5 ;
        RECT  44.304 0 44.328 0.084 ;
    END
  END din[53]
  PIN din[54]
    DIRECTION INPUT ;
    USE SIGNAL ;
    PORT
      LAYER M5 ;
        RECT  44.4 0 44.424 0.084 ;
    END
  END din[54]
  PIN din[55]
    DIRECTION INPUT ;
    USE SIGNAL ;
    PORT
      LAYER M5 ;
        RECT  44.496 0 44.52 0.084 ;
    END
  END din[55]
  PIN din[56]
    DIRECTION INPUT ;
    USE SIGNAL ;
    PORT
      LAYER M5 ;
        RECT  44.592 0 44.616 0.084 ;
    END
  END din[56]
  PIN din[57]
    DIRECTION INPUT ;
    USE SIGNAL ;
    PORT
      LAYER M5 ;
        RECT  44.688 0 44.712 0.084 ;
    END
  END din[57]
  PIN din[58]
    DIRECTION INPUT ;
    USE SIGNAL ;
    PORT
      LAYER M5 ;
        RECT  44.784 0 44.808 0.084 ;
    END
  END din[58]
  PIN din[59]
    DIRECTION INPUT ;
    USE SIGNAL ;
    PORT
      LAYER M5 ;
        RECT  44.88 0 44.904 0.084 ;
    END
  END din[59]
  PIN din[5]
    DIRECTION INPUT ;
    USE SIGNAL ;
    PORT
      LAYER M5 ;
        RECT  51.984 0 52.008 0.084 ;
    END
  END din[5]
  PIN din[60]
    DIRECTION INPUT ;
    USE SIGNAL ;
    PORT
      LAYER M5 ;
        RECT  44.976 0 45 0.084 ;
    END
  END din[60]
  PIN din[61]
    DIRECTION INPUT ;
    USE SIGNAL ;
    PORT
      LAYER M5 ;
        RECT  45.072 0 45.096 0.084 ;
    END
  END din[61]
  PIN din[62]
    DIRECTION INPUT ;
    USE SIGNAL ;
    PORT
      LAYER M5 ;
        RECT  45.168 0 45.192 0.084 ;
    END
  END din[62]
  PIN din[63]
    DIRECTION INPUT ;
    USE SIGNAL ;
    PORT
      LAYER M5 ;
        RECT  6.864 0 6.888 0.084 ;
    END
  END din[63]
  PIN din[64]
    DIRECTION INPUT ;
    USE SIGNAL ;
    PORT
      LAYER M5 ;
        RECT  6.96 0 6.984 0.084 ;
    END
  END din[64]
  PIN din[65]
    DIRECTION INPUT ;
    USE SIGNAL ;
    PORT
      LAYER M5 ;
        RECT  7.056 0 7.08 0.084 ;
    END
  END din[65]
  PIN din[66]
    DIRECTION INPUT ;
    USE SIGNAL ;
    PORT
      LAYER M5 ;
        RECT  7.152 0 7.176 0.084 ;
    END
  END din[66]
  PIN din[67]
    DIRECTION INPUT ;
    USE SIGNAL ;
    PORT
      LAYER M5 ;
        RECT  7.248 0 7.272 0.084 ;
    END
  END din[67]
  PIN din[68]
    DIRECTION INPUT ;
    USE SIGNAL ;
    PORT
      LAYER M5 ;
        RECT  7.344 0 7.368 0.084 ;
    END
  END din[68]
  PIN din[69]
    DIRECTION INPUT ;
    USE SIGNAL ;
    PORT
      LAYER M5 ;
        RECT  7.44 0 7.464 0.084 ;
    END
  END din[69]
  PIN din[6]
    DIRECTION INPUT ;
    USE SIGNAL ;
    PORT
      LAYER M5 ;
        RECT  52.08 0 52.104 0.084 ;
    END
  END din[6]
  PIN din[70]
    DIRECTION INPUT ;
    USE SIGNAL ;
    PORT
      LAYER M5 ;
        RECT  7.536 0 7.56 0.084 ;
    END
  END din[70]
  PIN din[71]
    DIRECTION INPUT ;
    USE SIGNAL ;
    PORT
      LAYER M5 ;
        RECT  7.632 0 7.656 0.084 ;
    END
  END din[71]
  PIN din[72]
    DIRECTION INPUT ;
    USE SIGNAL ;
    PORT
      LAYER M5 ;
        RECT  7.728 0 7.752 0.084 ;
    END
  END din[72]
  PIN din[73]
    DIRECTION INPUT ;
    USE SIGNAL ;
    PORT
      LAYER M5 ;
        RECT  7.824 0 7.848 0.084 ;
    END
  END din[73]
  PIN din[74]
    DIRECTION INPUT ;
    USE SIGNAL ;
    PORT
      LAYER M5 ;
        RECT  7.92 0 7.944 0.084 ;
    END
  END din[74]
  PIN din[75]
    DIRECTION INPUT ;
    USE SIGNAL ;
    PORT
      LAYER M5 ;
        RECT  8.016 0 8.04 0.084 ;
    END
  END din[75]
  PIN din[76]
    DIRECTION INPUT ;
    USE SIGNAL ;
    PORT
      LAYER M5 ;
        RECT  8.112 0 8.136 0.084 ;
    END
  END din[76]
  PIN din[77]
    DIRECTION INPUT ;
    USE SIGNAL ;
    PORT
      LAYER M5 ;
        RECT  8.208 0 8.232 0.084 ;
    END
  END din[77]
  PIN din[78]
    DIRECTION INPUT ;
    USE SIGNAL ;
    PORT
      LAYER M5 ;
        RECT  8.304 0 8.328 0.084 ;
    END
  END din[78]
  PIN din[79]
    DIRECTION INPUT ;
    USE SIGNAL ;
    PORT
      LAYER M5 ;
        RECT  8.4 0 8.424 0.084 ;
    END
  END din[79]
  PIN din[7]
    DIRECTION INPUT ;
    USE SIGNAL ;
    PORT
      LAYER M5 ;
        RECT  52.176 0 52.2 0.084 ;
    END
  END din[7]
  PIN din[80]
    DIRECTION INPUT ;
    USE SIGNAL ;
    PORT
      LAYER M5 ;
        RECT  8.496 0 8.52 0.084 ;
    END
  END din[80]
  PIN din[81]
    DIRECTION INPUT ;
    USE SIGNAL ;
    PORT
      LAYER M5 ;
        RECT  8.592 0 8.616 0.084 ;
    END
  END din[81]
  PIN din[82]
    DIRECTION INPUT ;
    USE SIGNAL ;
    PORT
      LAYER M5 ;
        RECT  8.688 0 8.712 0.084 ;
    END
  END din[82]
  PIN din[83]
    DIRECTION INPUT ;
    USE SIGNAL ;
    PORT
      LAYER M5 ;
        RECT  8.784 0 8.808 0.084 ;
    END
  END din[83]
  PIN din[84]
    DIRECTION INPUT ;
    USE SIGNAL ;
    PORT
      LAYER M5 ;
        RECT  8.88 0 8.904 0.084 ;
    END
  END din[84]
  PIN din[85]
    DIRECTION INPUT ;
    USE SIGNAL ;
    PORT
      LAYER M5 ;
        RECT  8.976 0 9 0.084 ;
    END
  END din[85]
  PIN din[86]
    DIRECTION INPUT ;
    USE SIGNAL ;
    PORT
      LAYER M5 ;
        RECT  9.072 0 9.096 0.084 ;
    END
  END din[86]
  PIN din[87]
    DIRECTION INPUT ;
    USE SIGNAL ;
    PORT
      LAYER M5 ;
        RECT  9.168 0 9.192 0.084 ;
    END
  END din[87]
  PIN din[88]
    DIRECTION INPUT ;
    USE SIGNAL ;
    PORT
      LAYER M5 ;
        RECT  9.264 0 9.288 0.084 ;
    END
  END din[88]
  PIN din[89]
    DIRECTION INPUT ;
    USE SIGNAL ;
    PORT
      LAYER M5 ;
        RECT  9.36 0 9.384 0.084 ;
    END
  END din[89]
  PIN din[8]
    DIRECTION INPUT ;
    USE SIGNAL ;
    PORT
      LAYER M5 ;
        RECT  52.272 0 52.296 0.084 ;
    END
  END din[8]
  PIN din[90]
    DIRECTION INPUT ;
    USE SIGNAL ;
    PORT
      LAYER M5 ;
        RECT  9.456 0 9.48 0.084 ;
    END
  END din[90]
  PIN din[91]
    DIRECTION INPUT ;
    USE SIGNAL ;
    PORT
      LAYER M5 ;
        RECT  9.552 0 9.576 0.084 ;
    END
  END din[91]
  PIN din[92]
    DIRECTION INPUT ;
    USE SIGNAL ;
    PORT
      LAYER M5 ;
        RECT  9.648 0 9.672 0.084 ;
    END
  END din[92]
  PIN din[93]
    DIRECTION INPUT ;
    USE SIGNAL ;
    PORT
      LAYER M5 ;
        RECT  9.744 0 9.768 0.084 ;
    END
  END din[93]
  PIN din[94]
    DIRECTION INPUT ;
    USE SIGNAL ;
    PORT
      LAYER M5 ;
        RECT  9.84 0 9.864 0.084 ;
    END
  END din[94]
  PIN din[95]
    DIRECTION INPUT ;
    USE SIGNAL ;
    PORT
      LAYER M5 ;
        RECT  22.992 0 23.016 0.084 ;
    END
  END din[95]
  PIN din[96]
    DIRECTION INPUT ;
    USE SIGNAL ;
    PORT
      LAYER M5 ;
        RECT  23.088 0 23.112 0.084 ;
    END
  END din[96]
  PIN din[97]
    DIRECTION INPUT ;
    USE SIGNAL ;
    PORT
      LAYER M5 ;
        RECT  23.184 0 23.208 0.084 ;
    END
  END din[97]
  PIN din[98]
    DIRECTION INPUT ;
    USE SIGNAL ;
    PORT
      LAYER M5 ;
        RECT  23.28 0 23.304 0.084 ;
    END
  END din[98]
  PIN din[99]
    DIRECTION INPUT ;
    USE SIGNAL ;
    PORT
      LAYER M5 ;
        RECT  23.376 0 23.4 0.084 ;
    END
  END din[99]
  PIN din[9]
    DIRECTION INPUT ;
    USE SIGNAL ;
    PORT
      LAYER M5 ;
        RECT  52.368 0 52.392 0.084 ;
    END
  END din[9]
  PIN dout[0]
    DIRECTION OUTPUT ;
    USE SIGNAL ;
    PORT
      LAYER M5 ;
        RECT  83.856 58.236 83.88 58.32 ;
    END
  END dout[0]
  PIN dout[100]
    DIRECTION OUTPUT ;
    USE SIGNAL ;
    PORT
      LAYER M5 ;
        RECT  36.624 58.236 36.648 58.32 ;
    END
  END dout[100]
  PIN dout[101]
    DIRECTION OUTPUT ;
    USE SIGNAL ;
    PORT
      LAYER M5 ;
        RECT  36.72 58.236 36.744 58.32 ;
    END
  END dout[101]
  PIN dout[102]
    DIRECTION OUTPUT ;
    USE SIGNAL ;
    PORT
      LAYER M5 ;
        RECT  36.816 58.236 36.84 58.32 ;
    END
  END dout[102]
  PIN dout[103]
    DIRECTION OUTPUT ;
    USE SIGNAL ;
    PORT
      LAYER M5 ;
        RECT  36.912 58.236 36.936 58.32 ;
    END
  END dout[103]
  PIN dout[104]
    DIRECTION OUTPUT ;
    USE SIGNAL ;
    PORT
      LAYER M5 ;
        RECT  37.008 58.236 37.032 58.32 ;
    END
  END dout[104]
  PIN dout[105]
    DIRECTION OUTPUT ;
    USE SIGNAL ;
    PORT
      LAYER M5 ;
        RECT  37.104 58.236 37.128 58.32 ;
    END
  END dout[105]
  PIN dout[106]
    DIRECTION OUTPUT ;
    USE SIGNAL ;
    PORT
      LAYER M5 ;
        RECT  37.2 58.236 37.224 58.32 ;
    END
  END dout[106]
  PIN dout[107]
    DIRECTION OUTPUT ;
    USE SIGNAL ;
    PORT
      LAYER M5 ;
        RECT  37.296 58.236 37.32 58.32 ;
    END
  END dout[107]
  PIN dout[108]
    DIRECTION OUTPUT ;
    USE SIGNAL ;
    PORT
      LAYER M5 ;
        RECT  37.392 58.236 37.416 58.32 ;
    END
  END dout[108]
  PIN dout[109]
    DIRECTION OUTPUT ;
    USE SIGNAL ;
    PORT
      LAYER M5 ;
        RECT  37.488 58.236 37.512 58.32 ;
    END
  END dout[109]
  PIN dout[10]
    DIRECTION OUTPUT ;
    USE SIGNAL ;
    PORT
      LAYER M5 ;
        RECT  84.816 58.236 84.84 58.32 ;
    END
  END dout[10]
  PIN dout[110]
    DIRECTION OUTPUT ;
    USE SIGNAL ;
    PORT
      LAYER M5 ;
        RECT  37.584 58.236 37.608 58.32 ;
    END
  END dout[110]
  PIN dout[111]
    DIRECTION OUTPUT ;
    USE SIGNAL ;
    PORT
      LAYER M5 ;
        RECT  37.68 58.236 37.704 58.32 ;
    END
  END dout[111]
  PIN dout[112]
    DIRECTION OUTPUT ;
    USE SIGNAL ;
    PORT
      LAYER M5 ;
        RECT  37.776 58.236 37.8 58.32 ;
    END
  END dout[112]
  PIN dout[113]
    DIRECTION OUTPUT ;
    USE SIGNAL ;
    PORT
      LAYER M5 ;
        RECT  37.872 58.236 37.896 58.32 ;
    END
  END dout[113]
  PIN dout[114]
    DIRECTION OUTPUT ;
    USE SIGNAL ;
    PORT
      LAYER M5 ;
        RECT  37.968 58.236 37.992 58.32 ;
    END
  END dout[114]
  PIN dout[115]
    DIRECTION OUTPUT ;
    USE SIGNAL ;
    PORT
      LAYER M5 ;
        RECT  38.064 58.236 38.088 58.32 ;
    END
  END dout[115]
  PIN dout[116]
    DIRECTION OUTPUT ;
    USE SIGNAL ;
    PORT
      LAYER M5 ;
        RECT  38.16 58.236 38.184 58.32 ;
    END
  END dout[116]
  PIN dout[117]
    DIRECTION OUTPUT ;
    USE SIGNAL ;
    PORT
      LAYER M5 ;
        RECT  38.256 58.236 38.28 58.32 ;
    END
  END dout[117]
  PIN dout[118]
    DIRECTION OUTPUT ;
    USE SIGNAL ;
    PORT
      LAYER M5 ;
        RECT  38.352 58.236 38.376 58.32 ;
    END
  END dout[118]
  PIN dout[119]
    DIRECTION OUTPUT ;
    USE SIGNAL ;
    PORT
      LAYER M5 ;
        RECT  38.448 58.236 38.472 58.32 ;
    END
  END dout[119]
  PIN dout[11]
    DIRECTION OUTPUT ;
    USE SIGNAL ;
    PORT
      LAYER M5 ;
        RECT  84.912 58.236 84.936 58.32 ;
    END
  END dout[11]
  PIN dout[120]
    DIRECTION OUTPUT ;
    USE SIGNAL ;
    PORT
      LAYER M5 ;
        RECT  38.544 58.236 38.568 58.32 ;
    END
  END dout[120]
  PIN dout[121]
    DIRECTION OUTPUT ;
    USE SIGNAL ;
    PORT
      LAYER M5 ;
        RECT  38.64 58.236 38.664 58.32 ;
    END
  END dout[121]
  PIN dout[122]
    DIRECTION OUTPUT ;
    USE SIGNAL ;
    PORT
      LAYER M5 ;
        RECT  38.736 58.236 38.76 58.32 ;
    END
  END dout[122]
  PIN dout[123]
    DIRECTION OUTPUT ;
    USE SIGNAL ;
    PORT
      LAYER M5 ;
        RECT  38.832 58.236 38.856 58.32 ;
    END
  END dout[123]
  PIN dout[124]
    DIRECTION OUTPUT ;
    USE SIGNAL ;
    PORT
      LAYER M5 ;
        RECT  38.928 58.236 38.952 58.32 ;
    END
  END dout[124]
  PIN dout[125]
    DIRECTION OUTPUT ;
    USE SIGNAL ;
    PORT
      LAYER M5 ;
        RECT  39.024 58.236 39.048 58.32 ;
    END
  END dout[125]
  PIN dout[126]
    DIRECTION OUTPUT ;
    USE SIGNAL ;
    PORT
      LAYER M5 ;
        RECT  39.12 58.236 39.144 58.32 ;
    END
  END dout[126]
  PIN dout[127]
    DIRECTION OUTPUT ;
    USE SIGNAL ;
    PORT
      LAYER M5 ;
        RECT  39.216 58.236 39.24 58.32 ;
    END
  END dout[127]
  PIN dout[128]
    DIRECTION OUTPUT ;
    USE SIGNAL ;
    PORT
      LAYER M5 ;
        RECT  13.968 58.236 13.992 58.32 ;
    END
  END dout[128]
  PIN dout[129]
    DIRECTION OUTPUT ;
    USE SIGNAL ;
    PORT
      LAYER M5 ;
        RECT  14.064 58.236 14.088 58.32 ;
    END
  END dout[129]
  PIN dout[12]
    DIRECTION OUTPUT ;
    USE SIGNAL ;
    PORT
      LAYER M5 ;
        RECT  85.008 58.236 85.032 58.32 ;
    END
  END dout[12]
  PIN dout[130]
    DIRECTION OUTPUT ;
    USE SIGNAL ;
    PORT
      LAYER M5 ;
        RECT  14.16 58.236 14.184 58.32 ;
    END
  END dout[130]
  PIN dout[131]
    DIRECTION OUTPUT ;
    USE SIGNAL ;
    PORT
      LAYER M5 ;
        RECT  14.256 58.236 14.28 58.32 ;
    END
  END dout[131]
  PIN dout[132]
    DIRECTION OUTPUT ;
    USE SIGNAL ;
    PORT
      LAYER M5 ;
        RECT  14.352 58.236 14.376 58.32 ;
    END
  END dout[132]
  PIN dout[133]
    DIRECTION OUTPUT ;
    USE SIGNAL ;
    PORT
      LAYER M5 ;
        RECT  14.448 58.236 14.472 58.32 ;
    END
  END dout[133]
  PIN dout[134]
    DIRECTION OUTPUT ;
    USE SIGNAL ;
    PORT
      LAYER M5 ;
        RECT  14.544 58.236 14.568 58.32 ;
    END
  END dout[134]
  PIN dout[135]
    DIRECTION OUTPUT ;
    USE SIGNAL ;
    PORT
      LAYER M5 ;
        RECT  14.64 58.236 14.664 58.32 ;
    END
  END dout[135]
  PIN dout[136]
    DIRECTION OUTPUT ;
    USE SIGNAL ;
    PORT
      LAYER M5 ;
        RECT  14.736 58.236 14.76 58.32 ;
    END
  END dout[136]
  PIN dout[137]
    DIRECTION OUTPUT ;
    USE SIGNAL ;
    PORT
      LAYER M5 ;
        RECT  14.832 58.236 14.856 58.32 ;
    END
  END dout[137]
  PIN dout[138]
    DIRECTION OUTPUT ;
    USE SIGNAL ;
    PORT
      LAYER M5 ;
        RECT  14.928 58.236 14.952 58.32 ;
    END
  END dout[138]
  PIN dout[139]
    DIRECTION OUTPUT ;
    USE SIGNAL ;
    PORT
      LAYER M5 ;
        RECT  15.024 58.236 15.048 58.32 ;
    END
  END dout[139]
  PIN dout[13]
    DIRECTION OUTPUT ;
    USE SIGNAL ;
    PORT
      LAYER M5 ;
        RECT  85.104 58.236 85.128 58.32 ;
    END
  END dout[13]
  PIN dout[140]
    DIRECTION OUTPUT ;
    USE SIGNAL ;
    PORT
      LAYER M5 ;
        RECT  15.12 58.236 15.144 58.32 ;
    END
  END dout[140]
  PIN dout[141]
    DIRECTION OUTPUT ;
    USE SIGNAL ;
    PORT
      LAYER M5 ;
        RECT  15.216 58.236 15.24 58.32 ;
    END
  END dout[141]
  PIN dout[142]
    DIRECTION OUTPUT ;
    USE SIGNAL ;
    PORT
      LAYER M5 ;
        RECT  15.312 58.236 15.336 58.32 ;
    END
  END dout[142]
  PIN dout[143]
    DIRECTION OUTPUT ;
    USE SIGNAL ;
    PORT
      LAYER M5 ;
        RECT  15.408 58.236 15.432 58.32 ;
    END
  END dout[143]
  PIN dout[144]
    DIRECTION OUTPUT ;
    USE SIGNAL ;
    PORT
      LAYER M5 ;
        RECT  15.504 58.236 15.528 58.32 ;
    END
  END dout[144]
  PIN dout[145]
    DIRECTION OUTPUT ;
    USE SIGNAL ;
    PORT
      LAYER M5 ;
        RECT  15.6 58.236 15.624 58.32 ;
    END
  END dout[145]
  PIN dout[146]
    DIRECTION OUTPUT ;
    USE SIGNAL ;
    PORT
      LAYER M5 ;
        RECT  15.696 58.236 15.72 58.32 ;
    END
  END dout[146]
  PIN dout[147]
    DIRECTION OUTPUT ;
    USE SIGNAL ;
    PORT
      LAYER M5 ;
        RECT  15.792 58.236 15.816 58.32 ;
    END
  END dout[147]
  PIN dout[148]
    DIRECTION OUTPUT ;
    USE SIGNAL ;
    PORT
      LAYER M5 ;
        RECT  15.888 58.236 15.912 58.32 ;
    END
  END dout[148]
  PIN dout[149]
    DIRECTION OUTPUT ;
    USE SIGNAL ;
    PORT
      LAYER M5 ;
        RECT  15.984 58.236 16.008 58.32 ;
    END
  END dout[149]
  PIN dout[14]
    DIRECTION OUTPUT ;
    USE SIGNAL ;
    PORT
      LAYER M5 ;
        RECT  85.2 58.236 85.224 58.32 ;
    END
  END dout[14]
  PIN dout[150]
    DIRECTION OUTPUT ;
    USE SIGNAL ;
    PORT
      LAYER M5 ;
        RECT  16.08 58.236 16.104 58.32 ;
    END
  END dout[150]
  PIN dout[151]
    DIRECTION OUTPUT ;
    USE SIGNAL ;
    PORT
      LAYER M5 ;
        RECT  16.176 58.236 16.2 58.32 ;
    END
  END dout[151]
  PIN dout[152]
    DIRECTION OUTPUT ;
    USE SIGNAL ;
    PORT
      LAYER M5 ;
        RECT  16.272 58.236 16.296 58.32 ;
    END
  END dout[152]
  PIN dout[153]
    DIRECTION OUTPUT ;
    USE SIGNAL ;
    PORT
      LAYER M5 ;
        RECT  16.368 58.236 16.392 58.32 ;
    END
  END dout[153]
  PIN dout[154]
    DIRECTION OUTPUT ;
    USE SIGNAL ;
    PORT
      LAYER M5 ;
        RECT  16.464 58.236 16.488 58.32 ;
    END
  END dout[154]
  PIN dout[155]
    DIRECTION OUTPUT ;
    USE SIGNAL ;
    PORT
      LAYER M5 ;
        RECT  16.56 58.236 16.584 58.32 ;
    END
  END dout[155]
  PIN dout[156]
    DIRECTION OUTPUT ;
    USE SIGNAL ;
    PORT
      LAYER M5 ;
        RECT  16.656 58.236 16.68 58.32 ;
    END
  END dout[156]
  PIN dout[157]
    DIRECTION OUTPUT ;
    USE SIGNAL ;
    PORT
      LAYER M5 ;
        RECT  16.752 58.236 16.776 58.32 ;
    END
  END dout[157]
  PIN dout[158]
    DIRECTION OUTPUT ;
    USE SIGNAL ;
    PORT
      LAYER M5 ;
        RECT  16.848 58.236 16.872 58.32 ;
    END
  END dout[158]
  PIN dout[159]
    DIRECTION OUTPUT ;
    USE SIGNAL ;
    PORT
      LAYER M5 ;
        RECT  16.944 58.236 16.968 58.32 ;
    END
  END dout[159]
  PIN dout[15]
    DIRECTION OUTPUT ;
    USE SIGNAL ;
    PORT
      LAYER M5 ;
        RECT  85.296 58.236 85.32 58.32 ;
    END
  END dout[15]
  PIN dout[160]
    DIRECTION OUTPUT ;
    USE SIGNAL ;
    PORT
      LAYER M5 ;
        RECT  29.328 58.236 29.352 58.32 ;
    END
  END dout[160]
  PIN dout[161]
    DIRECTION OUTPUT ;
    USE SIGNAL ;
    PORT
      LAYER M5 ;
        RECT  29.424 58.236 29.448 58.32 ;
    END
  END dout[161]
  PIN dout[162]
    DIRECTION OUTPUT ;
    USE SIGNAL ;
    PORT
      LAYER M5 ;
        RECT  29.52 58.236 29.544 58.32 ;
    END
  END dout[162]
  PIN dout[163]
    DIRECTION OUTPUT ;
    USE SIGNAL ;
    PORT
      LAYER M5 ;
        RECT  29.616 58.236 29.64 58.32 ;
    END
  END dout[163]
  PIN dout[164]
    DIRECTION OUTPUT ;
    USE SIGNAL ;
    PORT
      LAYER M5 ;
        RECT  29.712 58.236 29.736 58.32 ;
    END
  END dout[164]
  PIN dout[165]
    DIRECTION OUTPUT ;
    USE SIGNAL ;
    PORT
      LAYER M5 ;
        RECT  29.808 58.236 29.832 58.32 ;
    END
  END dout[165]
  PIN dout[166]
    DIRECTION OUTPUT ;
    USE SIGNAL ;
    PORT
      LAYER M5 ;
        RECT  29.904 58.236 29.928 58.32 ;
    END
  END dout[166]
  PIN dout[167]
    DIRECTION OUTPUT ;
    USE SIGNAL ;
    PORT
      LAYER M5 ;
        RECT  30 58.236 30.024 58.32 ;
    END
  END dout[167]
  PIN dout[168]
    DIRECTION OUTPUT ;
    USE SIGNAL ;
    PORT
      LAYER M5 ;
        RECT  30.096 58.236 30.12 58.32 ;
    END
  END dout[168]
  PIN dout[169]
    DIRECTION OUTPUT ;
    USE SIGNAL ;
    PORT
      LAYER M5 ;
        RECT  30.192 58.236 30.216 58.32 ;
    END
  END dout[169]
  PIN dout[16]
    DIRECTION OUTPUT ;
    USE SIGNAL ;
    PORT
      LAYER M5 ;
        RECT  85.392 58.236 85.416 58.32 ;
    END
  END dout[16]
  PIN dout[170]
    DIRECTION OUTPUT ;
    USE SIGNAL ;
    PORT
      LAYER M5 ;
        RECT  30.288 58.236 30.312 58.32 ;
    END
  END dout[170]
  PIN dout[171]
    DIRECTION OUTPUT ;
    USE SIGNAL ;
    PORT
      LAYER M5 ;
        RECT  30.384 58.236 30.408 58.32 ;
    END
  END dout[171]
  PIN dout[172]
    DIRECTION OUTPUT ;
    USE SIGNAL ;
    PORT
      LAYER M5 ;
        RECT  30.48 58.236 30.504 58.32 ;
    END
  END dout[172]
  PIN dout[173]
    DIRECTION OUTPUT ;
    USE SIGNAL ;
    PORT
      LAYER M5 ;
        RECT  30.576 58.236 30.6 58.32 ;
    END
  END dout[173]
  PIN dout[174]
    DIRECTION OUTPUT ;
    USE SIGNAL ;
    PORT
      LAYER M5 ;
        RECT  30.672 58.236 30.696 58.32 ;
    END
  END dout[174]
  PIN dout[175]
    DIRECTION OUTPUT ;
    USE SIGNAL ;
    PORT
      LAYER M5 ;
        RECT  30.768 58.236 30.792 58.32 ;
    END
  END dout[175]
  PIN dout[176]
    DIRECTION OUTPUT ;
    USE SIGNAL ;
    PORT
      LAYER M5 ;
        RECT  30.864 58.236 30.888 58.32 ;
    END
  END dout[176]
  PIN dout[177]
    DIRECTION OUTPUT ;
    USE SIGNAL ;
    PORT
      LAYER M5 ;
        RECT  30.96 58.236 30.984 58.32 ;
    END
  END dout[177]
  PIN dout[178]
    DIRECTION OUTPUT ;
    USE SIGNAL ;
    PORT
      LAYER M5 ;
        RECT  31.056 58.236 31.08 58.32 ;
    END
  END dout[178]
  PIN dout[179]
    DIRECTION OUTPUT ;
    USE SIGNAL ;
    PORT
      LAYER M5 ;
        RECT  31.152 58.236 31.176 58.32 ;
    END
  END dout[179]
  PIN dout[17]
    DIRECTION OUTPUT ;
    USE SIGNAL ;
    PORT
      LAYER M5 ;
        RECT  85.488 58.236 85.512 58.32 ;
    END
  END dout[17]
  PIN dout[180]
    DIRECTION OUTPUT ;
    USE SIGNAL ;
    PORT
      LAYER M5 ;
        RECT  31.248 58.236 31.272 58.32 ;
    END
  END dout[180]
  PIN dout[181]
    DIRECTION OUTPUT ;
    USE SIGNAL ;
    PORT
      LAYER M5 ;
        RECT  31.344 58.236 31.368 58.32 ;
    END
  END dout[181]
  PIN dout[182]
    DIRECTION OUTPUT ;
    USE SIGNAL ;
    PORT
      LAYER M5 ;
        RECT  31.44 58.236 31.464 58.32 ;
    END
  END dout[182]
  PIN dout[183]
    DIRECTION OUTPUT ;
    USE SIGNAL ;
    PORT
      LAYER M5 ;
        RECT  31.536 58.236 31.56 58.32 ;
    END
  END dout[183]
  PIN dout[184]
    DIRECTION OUTPUT ;
    USE SIGNAL ;
    PORT
      LAYER M5 ;
        RECT  31.632 58.236 31.656 58.32 ;
    END
  END dout[184]
  PIN dout[185]
    DIRECTION OUTPUT ;
    USE SIGNAL ;
    PORT
      LAYER M5 ;
        RECT  31.728 58.236 31.752 58.32 ;
    END
  END dout[185]
  PIN dout[186]
    DIRECTION OUTPUT ;
    USE SIGNAL ;
    PORT
      LAYER M5 ;
        RECT  31.824 58.236 31.848 58.32 ;
    END
  END dout[186]
  PIN dout[187]
    DIRECTION OUTPUT ;
    USE SIGNAL ;
    PORT
      LAYER M5 ;
        RECT  31.92 58.236 31.944 58.32 ;
    END
  END dout[187]
  PIN dout[188]
    DIRECTION OUTPUT ;
    USE SIGNAL ;
    PORT
      LAYER M5 ;
        RECT  32.016 58.236 32.04 58.32 ;
    END
  END dout[188]
  PIN dout[189]
    DIRECTION OUTPUT ;
    USE SIGNAL ;
    PORT
      LAYER M5 ;
        RECT  32.112 58.236 32.136 58.32 ;
    END
  END dout[189]
  PIN dout[18]
    DIRECTION OUTPUT ;
    USE SIGNAL ;
    PORT
      LAYER M5 ;
        RECT  85.584 58.236 85.608 58.32 ;
    END
  END dout[18]
  PIN dout[190]
    DIRECTION OUTPUT ;
    USE SIGNAL ;
    PORT
      LAYER M5 ;
        RECT  32.208 58.236 32.232 58.32 ;
    END
  END dout[190]
  PIN dout[191]
    DIRECTION OUTPUT ;
    USE SIGNAL ;
    PORT
      LAYER M5 ;
        RECT  32.304 58.236 32.328 58.32 ;
    END
  END dout[191]
  PIN dout[192]
    DIRECTION OUTPUT ;
    USE SIGNAL ;
    PORT
      LAYER M5 ;
        RECT  71.568 58.236 71.592 58.32 ;
    END
  END dout[192]
  PIN dout[193]
    DIRECTION OUTPUT ;
    USE SIGNAL ;
    PORT
      LAYER M5 ;
        RECT  71.664 58.236 71.688 58.32 ;
    END
  END dout[193]
  PIN dout[194]
    DIRECTION OUTPUT ;
    USE SIGNAL ;
    PORT
      LAYER M5 ;
        RECT  71.76 58.236 71.784 58.32 ;
    END
  END dout[194]
  PIN dout[195]
    DIRECTION OUTPUT ;
    USE SIGNAL ;
    PORT
      LAYER M5 ;
        RECT  71.856 58.236 71.88 58.32 ;
    END
  END dout[195]
  PIN dout[196]
    DIRECTION OUTPUT ;
    USE SIGNAL ;
    PORT
      LAYER M5 ;
        RECT  71.952 58.236 71.976 58.32 ;
    END
  END dout[196]
  PIN dout[197]
    DIRECTION OUTPUT ;
    USE SIGNAL ;
    PORT
      LAYER M5 ;
        RECT  72.048 58.236 72.072 58.32 ;
    END
  END dout[197]
  PIN dout[198]
    DIRECTION OUTPUT ;
    USE SIGNAL ;
    PORT
      LAYER M5 ;
        RECT  72.144 58.236 72.168 58.32 ;
    END
  END dout[198]
  PIN dout[199]
    DIRECTION OUTPUT ;
    USE SIGNAL ;
    PORT
      LAYER M5 ;
        RECT  72.24 58.236 72.264 58.32 ;
    END
  END dout[199]
  PIN dout[19]
    DIRECTION OUTPUT ;
    USE SIGNAL ;
    PORT
      LAYER M5 ;
        RECT  85.68 58.236 85.704 58.32 ;
    END
  END dout[19]
  PIN dout[1]
    DIRECTION OUTPUT ;
    USE SIGNAL ;
    PORT
      LAYER M5 ;
        RECT  83.952 58.236 83.976 58.32 ;
    END
  END dout[1]
  PIN dout[200]
    DIRECTION OUTPUT ;
    USE SIGNAL ;
    PORT
      LAYER M5 ;
        RECT  72.336 58.236 72.36 58.32 ;
    END
  END dout[200]
  PIN dout[201]
    DIRECTION OUTPUT ;
    USE SIGNAL ;
    PORT
      LAYER M5 ;
        RECT  72.432 58.236 72.456 58.32 ;
    END
  END dout[201]
  PIN dout[202]
    DIRECTION OUTPUT ;
    USE SIGNAL ;
    PORT
      LAYER M5 ;
        RECT  72.528 58.236 72.552 58.32 ;
    END
  END dout[202]
  PIN dout[203]
    DIRECTION OUTPUT ;
    USE SIGNAL ;
    PORT
      LAYER M5 ;
        RECT  72.624 58.236 72.648 58.32 ;
    END
  END dout[203]
  PIN dout[204]
    DIRECTION OUTPUT ;
    USE SIGNAL ;
    PORT
      LAYER M5 ;
        RECT  72.72 58.236 72.744 58.32 ;
    END
  END dout[204]
  PIN dout[205]
    DIRECTION OUTPUT ;
    USE SIGNAL ;
    PORT
      LAYER M5 ;
        RECT  72.816 58.236 72.84 58.32 ;
    END
  END dout[205]
  PIN dout[206]
    DIRECTION OUTPUT ;
    USE SIGNAL ;
    PORT
      LAYER M5 ;
        RECT  72.912 58.236 72.936 58.32 ;
    END
  END dout[206]
  PIN dout[207]
    DIRECTION OUTPUT ;
    USE SIGNAL ;
    PORT
      LAYER M5 ;
        RECT  73.008 58.236 73.032 58.32 ;
    END
  END dout[207]
  PIN dout[208]
    DIRECTION OUTPUT ;
    USE SIGNAL ;
    PORT
      LAYER M5 ;
        RECT  73.104 58.236 73.128 58.32 ;
    END
  END dout[208]
  PIN dout[209]
    DIRECTION OUTPUT ;
    USE SIGNAL ;
    PORT
      LAYER M5 ;
        RECT  73.2 58.236 73.224 58.32 ;
    END
  END dout[209]
  PIN dout[20]
    DIRECTION OUTPUT ;
    USE SIGNAL ;
    PORT
      LAYER M5 ;
        RECT  85.776 58.236 85.8 58.32 ;
    END
  END dout[20]
  PIN dout[210]
    DIRECTION OUTPUT ;
    USE SIGNAL ;
    PORT
      LAYER M5 ;
        RECT  73.296 58.236 73.32 58.32 ;
    END
  END dout[210]
  PIN dout[211]
    DIRECTION OUTPUT ;
    USE SIGNAL ;
    PORT
      LAYER M5 ;
        RECT  73.392 58.236 73.416 58.32 ;
    END
  END dout[211]
  PIN dout[212]
    DIRECTION OUTPUT ;
    USE SIGNAL ;
    PORT
      LAYER M5 ;
        RECT  73.488 58.236 73.512 58.32 ;
    END
  END dout[212]
  PIN dout[213]
    DIRECTION OUTPUT ;
    USE SIGNAL ;
    PORT
      LAYER M5 ;
        RECT  73.584 58.236 73.608 58.32 ;
    END
  END dout[213]
  PIN dout[214]
    DIRECTION OUTPUT ;
    USE SIGNAL ;
    PORT
      LAYER M5 ;
        RECT  73.68 58.236 73.704 58.32 ;
    END
  END dout[214]
  PIN dout[215]
    DIRECTION OUTPUT ;
    USE SIGNAL ;
    PORT
      LAYER M5 ;
        RECT  73.776 58.236 73.8 58.32 ;
    END
  END dout[215]
  PIN dout[216]
    DIRECTION OUTPUT ;
    USE SIGNAL ;
    PORT
      LAYER M5 ;
        RECT  73.872 58.236 73.896 58.32 ;
    END
  END dout[216]
  PIN dout[217]
    DIRECTION OUTPUT ;
    USE SIGNAL ;
    PORT
      LAYER M5 ;
        RECT  73.968 58.236 73.992 58.32 ;
    END
  END dout[217]
  PIN dout[218]
    DIRECTION OUTPUT ;
    USE SIGNAL ;
    PORT
      LAYER M5 ;
        RECT  74.064 58.236 74.088 58.32 ;
    END
  END dout[218]
  PIN dout[219]
    DIRECTION OUTPUT ;
    USE SIGNAL ;
    PORT
      LAYER M5 ;
        RECT  74.16 58.236 74.184 58.32 ;
    END
  END dout[219]
  PIN dout[21]
    DIRECTION OUTPUT ;
    USE SIGNAL ;
    PORT
      LAYER M5 ;
        RECT  85.872 58.236 85.896 58.32 ;
    END
  END dout[21]
  PIN dout[220]
    DIRECTION OUTPUT ;
    USE SIGNAL ;
    PORT
      LAYER M5 ;
        RECT  74.256 58.236 74.28 58.32 ;
    END
  END dout[220]
  PIN dout[221]
    DIRECTION OUTPUT ;
    USE SIGNAL ;
    PORT
      LAYER M5 ;
        RECT  74.352 58.236 74.376 58.32 ;
    END
  END dout[221]
  PIN dout[222]
    DIRECTION OUTPUT ;
    USE SIGNAL ;
    PORT
      LAYER M5 ;
        RECT  74.448 58.236 74.472 58.32 ;
    END
  END dout[222]
  PIN dout[223]
    DIRECTION OUTPUT ;
    USE SIGNAL ;
    PORT
      LAYER M5 ;
        RECT  74.544 58.236 74.568 58.32 ;
    END
  END dout[223]
  PIN dout[224]
    DIRECTION OUTPUT ;
    USE SIGNAL ;
    PORT
      LAYER M5 ;
        RECT  80.784 58.236 80.808 58.32 ;
    END
  END dout[224]
  PIN dout[225]
    DIRECTION OUTPUT ;
    USE SIGNAL ;
    PORT
      LAYER M5 ;
        RECT  80.88 58.236 80.904 58.32 ;
    END
  END dout[225]
  PIN dout[226]
    DIRECTION OUTPUT ;
    USE SIGNAL ;
    PORT
      LAYER M5 ;
        RECT  80.976 58.236 81 58.32 ;
    END
  END dout[226]
  PIN dout[227]
    DIRECTION OUTPUT ;
    USE SIGNAL ;
    PORT
      LAYER M5 ;
        RECT  81.072 58.236 81.096 58.32 ;
    END
  END dout[227]
  PIN dout[228]
    DIRECTION OUTPUT ;
    USE SIGNAL ;
    PORT
      LAYER M5 ;
        RECT  81.168 58.236 81.192 58.32 ;
    END
  END dout[228]
  PIN dout[229]
    DIRECTION OUTPUT ;
    USE SIGNAL ;
    PORT
      LAYER M5 ;
        RECT  81.264 58.236 81.288 58.32 ;
    END
  END dout[229]
  PIN dout[22]
    DIRECTION OUTPUT ;
    USE SIGNAL ;
    PORT
      LAYER M5 ;
        RECT  85.968 58.236 85.992 58.32 ;
    END
  END dout[22]
  PIN dout[230]
    DIRECTION OUTPUT ;
    USE SIGNAL ;
    PORT
      LAYER M5 ;
        RECT  81.36 58.236 81.384 58.32 ;
    END
  END dout[230]
  PIN dout[231]
    DIRECTION OUTPUT ;
    USE SIGNAL ;
    PORT
      LAYER M5 ;
        RECT  81.456 58.236 81.48 58.32 ;
    END
  END dout[231]
  PIN dout[232]
    DIRECTION OUTPUT ;
    USE SIGNAL ;
    PORT
      LAYER M5 ;
        RECT  81.552 58.236 81.576 58.32 ;
    END
  END dout[232]
  PIN dout[233]
    DIRECTION OUTPUT ;
    USE SIGNAL ;
    PORT
      LAYER M5 ;
        RECT  81.648 58.236 81.672 58.32 ;
    END
  END dout[233]
  PIN dout[234]
    DIRECTION OUTPUT ;
    USE SIGNAL ;
    PORT
      LAYER M5 ;
        RECT  81.744 58.236 81.768 58.32 ;
    END
  END dout[234]
  PIN dout[235]
    DIRECTION OUTPUT ;
    USE SIGNAL ;
    PORT
      LAYER M5 ;
        RECT  81.84 58.236 81.864 58.32 ;
    END
  END dout[235]
  PIN dout[236]
    DIRECTION OUTPUT ;
    USE SIGNAL ;
    PORT
      LAYER M5 ;
        RECT  81.936 58.236 81.96 58.32 ;
    END
  END dout[236]
  PIN dout[237]
    DIRECTION OUTPUT ;
    USE SIGNAL ;
    PORT
      LAYER M5 ;
        RECT  82.032 58.236 82.056 58.32 ;
    END
  END dout[237]
  PIN dout[238]
    DIRECTION OUTPUT ;
    USE SIGNAL ;
    PORT
      LAYER M5 ;
        RECT  82.128 58.236 82.152 58.32 ;
    END
  END dout[238]
  PIN dout[239]
    DIRECTION OUTPUT ;
    USE SIGNAL ;
    PORT
      LAYER M5 ;
        RECT  82.224 58.236 82.248 58.32 ;
    END
  END dout[239]
  PIN dout[23]
    DIRECTION OUTPUT ;
    USE SIGNAL ;
    PORT
      LAYER M5 ;
        RECT  86.064 58.236 86.088 58.32 ;
    END
  END dout[23]
  PIN dout[240]
    DIRECTION OUTPUT ;
    USE SIGNAL ;
    PORT
      LAYER M5 ;
        RECT  82.32 58.236 82.344 58.32 ;
    END
  END dout[240]
  PIN dout[241]
    DIRECTION OUTPUT ;
    USE SIGNAL ;
    PORT
      LAYER M5 ;
        RECT  82.416 58.236 82.44 58.32 ;
    END
  END dout[241]
  PIN dout[242]
    DIRECTION OUTPUT ;
    USE SIGNAL ;
    PORT
      LAYER M5 ;
        RECT  82.512 58.236 82.536 58.32 ;
    END
  END dout[242]
  PIN dout[243]
    DIRECTION OUTPUT ;
    USE SIGNAL ;
    PORT
      LAYER M5 ;
        RECT  82.608 58.236 82.632 58.32 ;
    END
  END dout[243]
  PIN dout[244]
    DIRECTION OUTPUT ;
    USE SIGNAL ;
    PORT
      LAYER M5 ;
        RECT  82.704 58.236 82.728 58.32 ;
    END
  END dout[244]
  PIN dout[245]
    DIRECTION OUTPUT ;
    USE SIGNAL ;
    PORT
      LAYER M5 ;
        RECT  82.8 58.236 82.824 58.32 ;
    END
  END dout[245]
  PIN dout[246]
    DIRECTION OUTPUT ;
    USE SIGNAL ;
    PORT
      LAYER M5 ;
        RECT  82.896 58.236 82.92 58.32 ;
    END
  END dout[246]
  PIN dout[247]
    DIRECTION OUTPUT ;
    USE SIGNAL ;
    PORT
      LAYER M5 ;
        RECT  82.992 58.236 83.016 58.32 ;
    END
  END dout[247]
  PIN dout[248]
    DIRECTION OUTPUT ;
    USE SIGNAL ;
    PORT
      LAYER M5 ;
        RECT  83.088 58.236 83.112 58.32 ;
    END
  END dout[248]
  PIN dout[249]
    DIRECTION OUTPUT ;
    USE SIGNAL ;
    PORT
      LAYER M5 ;
        RECT  83.184 58.236 83.208 58.32 ;
    END
  END dout[249]
  PIN dout[24]
    DIRECTION OUTPUT ;
    USE SIGNAL ;
    PORT
      LAYER M5 ;
        RECT  86.16 58.236 86.184 58.32 ;
    END
  END dout[24]
  PIN dout[250]
    DIRECTION OUTPUT ;
    USE SIGNAL ;
    PORT
      LAYER M5 ;
        RECT  83.28 58.236 83.304 58.32 ;
    END
  END dout[250]
  PIN dout[251]
    DIRECTION OUTPUT ;
    USE SIGNAL ;
    PORT
      LAYER M5 ;
        RECT  83.376 58.236 83.4 58.32 ;
    END
  END dout[251]
  PIN dout[252]
    DIRECTION OUTPUT ;
    USE SIGNAL ;
    PORT
      LAYER M5 ;
        RECT  83.472 58.236 83.496 58.32 ;
    END
  END dout[252]
  PIN dout[253]
    DIRECTION OUTPUT ;
    USE SIGNAL ;
    PORT
      LAYER M5 ;
        RECT  83.568 58.236 83.592 58.32 ;
    END
  END dout[253]
  PIN dout[254]
    DIRECTION OUTPUT ;
    USE SIGNAL ;
    PORT
      LAYER M5 ;
        RECT  83.664 58.236 83.688 58.32 ;
    END
  END dout[254]
  PIN dout[255]
    DIRECTION OUTPUT ;
    USE SIGNAL ;
    PORT
      LAYER M5 ;
        RECT  83.76 58.236 83.784 58.32 ;
    END
  END dout[255]
  PIN dout[256]
    DIRECTION OUTPUT ;
    USE SIGNAL ;
    PORT
      LAYER M5 ;
        RECT  86.928 58.236 86.952 58.32 ;
    END
  END dout[256]
  PIN dout[257]
    DIRECTION OUTPUT ;
    USE SIGNAL ;
    PORT
      LAYER M5 ;
        RECT  87.024 58.236 87.048 58.32 ;
    END
  END dout[257]
  PIN dout[258]
    DIRECTION OUTPUT ;
    USE SIGNAL ;
    PORT
      LAYER M5 ;
        RECT  87.12 58.236 87.144 58.32 ;
    END
  END dout[258]
  PIN dout[259]
    DIRECTION OUTPUT ;
    USE SIGNAL ;
    PORT
      LAYER M5 ;
        RECT  87.216 58.236 87.24 58.32 ;
    END
  END dout[259]
  PIN dout[25]
    DIRECTION OUTPUT ;
    USE SIGNAL ;
    PORT
      LAYER M5 ;
        RECT  86.256 58.236 86.28 58.32 ;
    END
  END dout[25]
  PIN dout[260]
    DIRECTION OUTPUT ;
    USE SIGNAL ;
    PORT
      LAYER M5 ;
        RECT  87.312 58.236 87.336 58.32 ;
    END
  END dout[260]
  PIN dout[261]
    DIRECTION OUTPUT ;
    USE SIGNAL ;
    PORT
      LAYER M5 ;
        RECT  87.408 58.236 87.432 58.32 ;
    END
  END dout[261]
  PIN dout[262]
    DIRECTION OUTPUT ;
    USE SIGNAL ;
    PORT
      LAYER M5 ;
        RECT  87.504 58.236 87.528 58.32 ;
    END
  END dout[262]
  PIN dout[263]
    DIRECTION OUTPUT ;
    USE SIGNAL ;
    PORT
      LAYER M5 ;
        RECT  87.6 58.236 87.624 58.32 ;
    END
  END dout[263]
  PIN dout[264]
    DIRECTION OUTPUT ;
    USE SIGNAL ;
    PORT
      LAYER M5 ;
        RECT  87.696 58.236 87.72 58.32 ;
    END
  END dout[264]
  PIN dout[265]
    DIRECTION OUTPUT ;
    USE SIGNAL ;
    PORT
      LAYER M5 ;
        RECT  87.792 58.236 87.816 58.32 ;
    END
  END dout[265]
  PIN dout[266]
    DIRECTION OUTPUT ;
    USE SIGNAL ;
    PORT
      LAYER M5 ;
        RECT  87.888 58.236 87.912 58.32 ;
    END
  END dout[266]
  PIN dout[267]
    DIRECTION OUTPUT ;
    USE SIGNAL ;
    PORT
      LAYER M5 ;
        RECT  87.984 58.236 88.008 58.32 ;
    END
  END dout[267]
  PIN dout[268]
    DIRECTION OUTPUT ;
    USE SIGNAL ;
    PORT
      LAYER M5 ;
        RECT  88.08 58.236 88.104 58.32 ;
    END
  END dout[268]
  PIN dout[269]
    DIRECTION OUTPUT ;
    USE SIGNAL ;
    PORT
      LAYER M5 ;
        RECT  88.176 58.236 88.2 58.32 ;
    END
  END dout[269]
  PIN dout[26]
    DIRECTION OUTPUT ;
    USE SIGNAL ;
    PORT
      LAYER M5 ;
        RECT  86.352 58.236 86.376 58.32 ;
    END
  END dout[26]
  PIN dout[270]
    DIRECTION OUTPUT ;
    USE SIGNAL ;
    PORT
      LAYER M5 ;
        RECT  88.272 58.236 88.296 58.32 ;
    END
  END dout[270]
  PIN dout[271]
    DIRECTION OUTPUT ;
    USE SIGNAL ;
    PORT
      LAYER M5 ;
        RECT  88.368 58.236 88.392 58.32 ;
    END
  END dout[271]
  PIN dout[272]
    DIRECTION OUTPUT ;
    USE SIGNAL ;
    PORT
      LAYER M5 ;
        RECT  88.464 58.236 88.488 58.32 ;
    END
  END dout[272]
  PIN dout[273]
    DIRECTION OUTPUT ;
    USE SIGNAL ;
    PORT
      LAYER M5 ;
        RECT  88.56 58.236 88.584 58.32 ;
    END
  END dout[273]
  PIN dout[274]
    DIRECTION OUTPUT ;
    USE SIGNAL ;
    PORT
      LAYER M5 ;
        RECT  88.656 58.236 88.68 58.32 ;
    END
  END dout[274]
  PIN dout[275]
    DIRECTION OUTPUT ;
    USE SIGNAL ;
    PORT
      LAYER M5 ;
        RECT  88.752 58.236 88.776 58.32 ;
    END
  END dout[275]
  PIN dout[276]
    DIRECTION OUTPUT ;
    USE SIGNAL ;
    PORT
      LAYER M5 ;
        RECT  88.848 58.236 88.872 58.32 ;
    END
  END dout[276]
  PIN dout[277]
    DIRECTION OUTPUT ;
    USE SIGNAL ;
    PORT
      LAYER M5 ;
        RECT  88.944 58.236 88.968 58.32 ;
    END
  END dout[277]
  PIN dout[278]
    DIRECTION OUTPUT ;
    USE SIGNAL ;
    PORT
      LAYER M5 ;
        RECT  89.04 58.236 89.064 58.32 ;
    END
  END dout[278]
  PIN dout[279]
    DIRECTION OUTPUT ;
    USE SIGNAL ;
    PORT
      LAYER M5 ;
        RECT  89.136 58.236 89.16 58.32 ;
    END
  END dout[279]
  PIN dout[27]
    DIRECTION OUTPUT ;
    USE SIGNAL ;
    PORT
      LAYER M5 ;
        RECT  86.448 58.236 86.472 58.32 ;
    END
  END dout[27]
  PIN dout[280]
    DIRECTION OUTPUT ;
    USE SIGNAL ;
    PORT
      LAYER M5 ;
        RECT  89.232 58.236 89.256 58.32 ;
    END
  END dout[280]
  PIN dout[281]
    DIRECTION OUTPUT ;
    USE SIGNAL ;
    PORT
      LAYER M5 ;
        RECT  89.328 58.236 89.352 58.32 ;
    END
  END dout[281]
  PIN dout[282]
    DIRECTION OUTPUT ;
    USE SIGNAL ;
    PORT
      LAYER M5 ;
        RECT  89.424 58.236 89.448 58.32 ;
    END
  END dout[282]
  PIN dout[283]
    DIRECTION OUTPUT ;
    USE SIGNAL ;
    PORT
      LAYER M5 ;
        RECT  89.52 58.236 89.544 58.32 ;
    END
  END dout[283]
  PIN dout[284]
    DIRECTION OUTPUT ;
    USE SIGNAL ;
    PORT
      LAYER M5 ;
        RECT  89.616 58.236 89.64 58.32 ;
    END
  END dout[284]
  PIN dout[285]
    DIRECTION OUTPUT ;
    USE SIGNAL ;
    PORT
      LAYER M5 ;
        RECT  89.712 58.236 89.736 58.32 ;
    END
  END dout[285]
  PIN dout[286]
    DIRECTION OUTPUT ;
    USE SIGNAL ;
    PORT
      LAYER M5 ;
        RECT  89.808 58.236 89.832 58.32 ;
    END
  END dout[286]
  PIN dout[287]
    DIRECTION OUTPUT ;
    USE SIGNAL ;
    PORT
      LAYER M5 ;
        RECT  89.904 58.236 89.928 58.32 ;
    END
  END dout[287]
  PIN dout[288]
    DIRECTION OUTPUT ;
    USE SIGNAL ;
    PORT
      LAYER M5 ;
        RECT  77.712 58.236 77.736 58.32 ;
    END
  END dout[288]
  PIN dout[289]
    DIRECTION OUTPUT ;
    USE SIGNAL ;
    PORT
      LAYER M5 ;
        RECT  77.808 58.236 77.832 58.32 ;
    END
  END dout[289]
  PIN dout[28]
    DIRECTION OUTPUT ;
    USE SIGNAL ;
    PORT
      LAYER M5 ;
        RECT  86.544 58.236 86.568 58.32 ;
    END
  END dout[28]
  PIN dout[290]
    DIRECTION OUTPUT ;
    USE SIGNAL ;
    PORT
      LAYER M5 ;
        RECT  77.904 58.236 77.928 58.32 ;
    END
  END dout[290]
  PIN dout[291]
    DIRECTION OUTPUT ;
    USE SIGNAL ;
    PORT
      LAYER M5 ;
        RECT  78 58.236 78.024 58.32 ;
    END
  END dout[291]
  PIN dout[292]
    DIRECTION OUTPUT ;
    USE SIGNAL ;
    PORT
      LAYER M5 ;
        RECT  78.096 58.236 78.12 58.32 ;
    END
  END dout[292]
  PIN dout[293]
    DIRECTION OUTPUT ;
    USE SIGNAL ;
    PORT
      LAYER M5 ;
        RECT  78.192 58.236 78.216 58.32 ;
    END
  END dout[293]
  PIN dout[294]
    DIRECTION OUTPUT ;
    USE SIGNAL ;
    PORT
      LAYER M5 ;
        RECT  78.288 58.236 78.312 58.32 ;
    END
  END dout[294]
  PIN dout[295]
    DIRECTION OUTPUT ;
    USE SIGNAL ;
    PORT
      LAYER M5 ;
        RECT  78.384 58.236 78.408 58.32 ;
    END
  END dout[295]
  PIN dout[296]
    DIRECTION OUTPUT ;
    USE SIGNAL ;
    PORT
      LAYER M5 ;
        RECT  78.48 58.236 78.504 58.32 ;
    END
  END dout[296]
  PIN dout[297]
    DIRECTION OUTPUT ;
    USE SIGNAL ;
    PORT
      LAYER M5 ;
        RECT  78.576 58.236 78.6 58.32 ;
    END
  END dout[297]
  PIN dout[298]
    DIRECTION OUTPUT ;
    USE SIGNAL ;
    PORT
      LAYER M5 ;
        RECT  78.672 58.236 78.696 58.32 ;
    END
  END dout[298]
  PIN dout[299]
    DIRECTION OUTPUT ;
    USE SIGNAL ;
    PORT
      LAYER M5 ;
        RECT  78.768 58.236 78.792 58.32 ;
    END
  END dout[299]
  PIN dout[29]
    DIRECTION OUTPUT ;
    USE SIGNAL ;
    PORT
      LAYER M5 ;
        RECT  86.64 58.236 86.664 58.32 ;
    END
  END dout[29]
  PIN dout[2]
    DIRECTION OUTPUT ;
    USE SIGNAL ;
    PORT
      LAYER M5 ;
        RECT  84.048 58.236 84.072 58.32 ;
    END
  END dout[2]
  PIN dout[300]
    DIRECTION OUTPUT ;
    USE SIGNAL ;
    PORT
      LAYER M5 ;
        RECT  78.864 58.236 78.888 58.32 ;
    END
  END dout[300]
  PIN dout[301]
    DIRECTION OUTPUT ;
    USE SIGNAL ;
    PORT
      LAYER M5 ;
        RECT  78.96 58.236 78.984 58.32 ;
    END
  END dout[301]
  PIN dout[302]
    DIRECTION OUTPUT ;
    USE SIGNAL ;
    PORT
      LAYER M5 ;
        RECT  79.056 58.236 79.08 58.32 ;
    END
  END dout[302]
  PIN dout[303]
    DIRECTION OUTPUT ;
    USE SIGNAL ;
    PORT
      LAYER M5 ;
        RECT  79.152 58.236 79.176 58.32 ;
    END
  END dout[303]
  PIN dout[304]
    DIRECTION OUTPUT ;
    USE SIGNAL ;
    PORT
      LAYER M5 ;
        RECT  79.248 58.236 79.272 58.32 ;
    END
  END dout[304]
  PIN dout[305]
    DIRECTION OUTPUT ;
    USE SIGNAL ;
    PORT
      LAYER M5 ;
        RECT  79.344 58.236 79.368 58.32 ;
    END
  END dout[305]
  PIN dout[306]
    DIRECTION OUTPUT ;
    USE SIGNAL ;
    PORT
      LAYER M5 ;
        RECT  79.44 58.236 79.464 58.32 ;
    END
  END dout[306]
  PIN dout[307]
    DIRECTION OUTPUT ;
    USE SIGNAL ;
    PORT
      LAYER M5 ;
        RECT  79.536 58.236 79.56 58.32 ;
    END
  END dout[307]
  PIN dout[308]
    DIRECTION OUTPUT ;
    USE SIGNAL ;
    PORT
      LAYER M5 ;
        RECT  79.632 58.236 79.656 58.32 ;
    END
  END dout[308]
  PIN dout[309]
    DIRECTION OUTPUT ;
    USE SIGNAL ;
    PORT
      LAYER M5 ;
        RECT  79.728 58.236 79.752 58.32 ;
    END
  END dout[309]
  PIN dout[30]
    DIRECTION OUTPUT ;
    USE SIGNAL ;
    PORT
      LAYER M5 ;
        RECT  86.736 58.236 86.76 58.32 ;
    END
  END dout[30]
  PIN dout[310]
    DIRECTION OUTPUT ;
    USE SIGNAL ;
    PORT
      LAYER M5 ;
        RECT  79.824 58.236 79.848 58.32 ;
    END
  END dout[310]
  PIN dout[311]
    DIRECTION OUTPUT ;
    USE SIGNAL ;
    PORT
      LAYER M5 ;
        RECT  79.92 58.236 79.944 58.32 ;
    END
  END dout[311]
  PIN dout[312]
    DIRECTION OUTPUT ;
    USE SIGNAL ;
    PORT
      LAYER M5 ;
        RECT  80.016 58.236 80.04 58.32 ;
    END
  END dout[312]
  PIN dout[313]
    DIRECTION OUTPUT ;
    USE SIGNAL ;
    PORT
      LAYER M5 ;
        RECT  80.112 58.236 80.136 58.32 ;
    END
  END dout[313]
  PIN dout[314]
    DIRECTION OUTPUT ;
    USE SIGNAL ;
    PORT
      LAYER M5 ;
        RECT  80.208 58.236 80.232 58.32 ;
    END
  END dout[314]
  PIN dout[315]
    DIRECTION OUTPUT ;
    USE SIGNAL ;
    PORT
      LAYER M5 ;
        RECT  80.304 58.236 80.328 58.32 ;
    END
  END dout[315]
  PIN dout[316]
    DIRECTION OUTPUT ;
    USE SIGNAL ;
    PORT
      LAYER M5 ;
        RECT  80.4 58.236 80.424 58.32 ;
    END
  END dout[316]
  PIN dout[317]
    DIRECTION OUTPUT ;
    USE SIGNAL ;
    PORT
      LAYER M5 ;
        RECT  80.496 58.236 80.52 58.32 ;
    END
  END dout[317]
  PIN dout[318]
    DIRECTION OUTPUT ;
    USE SIGNAL ;
    PORT
      LAYER M5 ;
        RECT  80.592 58.236 80.616 58.32 ;
    END
  END dout[318]
  PIN dout[319]
    DIRECTION OUTPUT ;
    USE SIGNAL ;
    PORT
      LAYER M5 ;
        RECT  80.688 58.236 80.712 58.32 ;
    END
  END dout[319]
  PIN dout[31]
    DIRECTION OUTPUT ;
    USE SIGNAL ;
    PORT
      LAYER M5 ;
        RECT  86.832 58.236 86.856 58.32 ;
    END
  END dout[31]
  PIN dout[320]
    DIRECTION OUTPUT ;
    USE SIGNAL ;
    PORT
      LAYER M5 ;
        RECT  52.368 58.236 52.392 58.32 ;
    END
  END dout[320]
  PIN dout[321]
    DIRECTION OUTPUT ;
    USE SIGNAL ;
    PORT
      LAYER M5 ;
        RECT  52.464 58.236 52.488 58.32 ;
    END
  END dout[321]
  PIN dout[322]
    DIRECTION OUTPUT ;
    USE SIGNAL ;
    PORT
      LAYER M5 ;
        RECT  52.56 58.236 52.584 58.32 ;
    END
  END dout[322]
  PIN dout[323]
    DIRECTION OUTPUT ;
    USE SIGNAL ;
    PORT
      LAYER M5 ;
        RECT  52.656 58.236 52.68 58.32 ;
    END
  END dout[323]
  PIN dout[324]
    DIRECTION OUTPUT ;
    USE SIGNAL ;
    PORT
      LAYER M5 ;
        RECT  52.752 58.236 52.776 58.32 ;
    END
  END dout[324]
  PIN dout[325]
    DIRECTION OUTPUT ;
    USE SIGNAL ;
    PORT
      LAYER M5 ;
        RECT  52.848 58.236 52.872 58.32 ;
    END
  END dout[325]
  PIN dout[326]
    DIRECTION OUTPUT ;
    USE SIGNAL ;
    PORT
      LAYER M5 ;
        RECT  52.944 58.236 52.968 58.32 ;
    END
  END dout[326]
  PIN dout[327]
    DIRECTION OUTPUT ;
    USE SIGNAL ;
    PORT
      LAYER M5 ;
        RECT  53.04 58.236 53.064 58.32 ;
    END
  END dout[327]
  PIN dout[328]
    DIRECTION OUTPUT ;
    USE SIGNAL ;
    PORT
      LAYER M5 ;
        RECT  53.136 58.236 53.16 58.32 ;
    END
  END dout[328]
  PIN dout[329]
    DIRECTION OUTPUT ;
    USE SIGNAL ;
    PORT
      LAYER M5 ;
        RECT  53.232 58.236 53.256 58.32 ;
    END
  END dout[329]
  PIN dout[32]
    DIRECTION OUTPUT ;
    USE SIGNAL ;
    PORT
      LAYER M5 ;
        RECT  74.64 58.236 74.664 58.32 ;
    END
  END dout[32]
  PIN dout[330]
    DIRECTION OUTPUT ;
    USE SIGNAL ;
    PORT
      LAYER M5 ;
        RECT  53.328 58.236 53.352 58.32 ;
    END
  END dout[330]
  PIN dout[331]
    DIRECTION OUTPUT ;
    USE SIGNAL ;
    PORT
      LAYER M5 ;
        RECT  53.424 58.236 53.448 58.32 ;
    END
  END dout[331]
  PIN dout[332]
    DIRECTION OUTPUT ;
    USE SIGNAL ;
    PORT
      LAYER M5 ;
        RECT  53.52 58.236 53.544 58.32 ;
    END
  END dout[332]
  PIN dout[333]
    DIRECTION OUTPUT ;
    USE SIGNAL ;
    PORT
      LAYER M5 ;
        RECT  53.616 58.236 53.64 58.32 ;
    END
  END dout[333]
  PIN dout[334]
    DIRECTION OUTPUT ;
    USE SIGNAL ;
    PORT
      LAYER M5 ;
        RECT  53.712 58.236 53.736 58.32 ;
    END
  END dout[334]
  PIN dout[335]
    DIRECTION OUTPUT ;
    USE SIGNAL ;
    PORT
      LAYER M5 ;
        RECT  53.808 58.236 53.832 58.32 ;
    END
  END dout[335]
  PIN dout[336]
    DIRECTION OUTPUT ;
    USE SIGNAL ;
    PORT
      LAYER M5 ;
        RECT  53.904 58.236 53.928 58.32 ;
    END
  END dout[336]
  PIN dout[337]
    DIRECTION OUTPUT ;
    USE SIGNAL ;
    PORT
      LAYER M5 ;
        RECT  54 58.236 54.024 58.32 ;
    END
  END dout[337]
  PIN dout[338]
    DIRECTION OUTPUT ;
    USE SIGNAL ;
    PORT
      LAYER M5 ;
        RECT  54.096 58.236 54.12 58.32 ;
    END
  END dout[338]
  PIN dout[339]
    DIRECTION OUTPUT ;
    USE SIGNAL ;
    PORT
      LAYER M5 ;
        RECT  54.192 58.236 54.216 58.32 ;
    END
  END dout[339]
  PIN dout[33]
    DIRECTION OUTPUT ;
    USE SIGNAL ;
    PORT
      LAYER M5 ;
        RECT  74.736 58.236 74.76 58.32 ;
    END
  END dout[33]
  PIN dout[340]
    DIRECTION OUTPUT ;
    USE SIGNAL ;
    PORT
      LAYER M5 ;
        RECT  54.288 58.236 54.312 58.32 ;
    END
  END dout[340]
  PIN dout[341]
    DIRECTION OUTPUT ;
    USE SIGNAL ;
    PORT
      LAYER M5 ;
        RECT  54.384 58.236 54.408 58.32 ;
    END
  END dout[341]
  PIN dout[342]
    DIRECTION OUTPUT ;
    USE SIGNAL ;
    PORT
      LAYER M5 ;
        RECT  54.48 58.236 54.504 58.32 ;
    END
  END dout[342]
  PIN dout[343]
    DIRECTION OUTPUT ;
    USE SIGNAL ;
    PORT
      LAYER M5 ;
        RECT  54.576 58.236 54.6 58.32 ;
    END
  END dout[343]
  PIN dout[344]
    DIRECTION OUTPUT ;
    USE SIGNAL ;
    PORT
      LAYER M5 ;
        RECT  54.672 58.236 54.696 58.32 ;
    END
  END dout[344]
  PIN dout[345]
    DIRECTION OUTPUT ;
    USE SIGNAL ;
    PORT
      LAYER M5 ;
        RECT  54.768 58.236 54.792 58.32 ;
    END
  END dout[345]
  PIN dout[346]
    DIRECTION OUTPUT ;
    USE SIGNAL ;
    PORT
      LAYER M5 ;
        RECT  54.864 58.236 54.888 58.32 ;
    END
  END dout[346]
  PIN dout[347]
    DIRECTION OUTPUT ;
    USE SIGNAL ;
    PORT
      LAYER M5 ;
        RECT  54.96 58.236 54.984 58.32 ;
    END
  END dout[347]
  PIN dout[348]
    DIRECTION OUTPUT ;
    USE SIGNAL ;
    PORT
      LAYER M5 ;
        RECT  55.056 58.236 55.08 58.32 ;
    END
  END dout[348]
  PIN dout[349]
    DIRECTION OUTPUT ;
    USE SIGNAL ;
    PORT
      LAYER M5 ;
        RECT  55.152 58.236 55.176 58.32 ;
    END
  END dout[349]
  PIN dout[34]
    DIRECTION OUTPUT ;
    USE SIGNAL ;
    PORT
      LAYER M5 ;
        RECT  74.832 58.236 74.856 58.32 ;
    END
  END dout[34]
  PIN dout[350]
    DIRECTION OUTPUT ;
    USE SIGNAL ;
    PORT
      LAYER M5 ;
        RECT  55.248 58.236 55.272 58.32 ;
    END
  END dout[350]
  PIN dout[351]
    DIRECTION OUTPUT ;
    USE SIGNAL ;
    PORT
      LAYER M5 ;
        RECT  55.344 58.236 55.368 58.32 ;
    END
  END dout[351]
  PIN dout[352]
    DIRECTION OUTPUT ;
    USE SIGNAL ;
    PORT
      LAYER M5 ;
        RECT  10.128 58.236 10.152 58.32 ;
    END
  END dout[352]
  PIN dout[353]
    DIRECTION OUTPUT ;
    USE SIGNAL ;
    PORT
      LAYER M5 ;
        RECT  10.224 58.236 10.248 58.32 ;
    END
  END dout[353]
  PIN dout[354]
    DIRECTION OUTPUT ;
    USE SIGNAL ;
    PORT
      LAYER M5 ;
        RECT  10.32 58.236 10.344 58.32 ;
    END
  END dout[354]
  PIN dout[355]
    DIRECTION OUTPUT ;
    USE SIGNAL ;
    PORT
      LAYER M5 ;
        RECT  10.416 58.236 10.44 58.32 ;
    END
  END dout[355]
  PIN dout[356]
    DIRECTION OUTPUT ;
    USE SIGNAL ;
    PORT
      LAYER M5 ;
        RECT  10.512 58.236 10.536 58.32 ;
    END
  END dout[356]
  PIN dout[357]
    DIRECTION OUTPUT ;
    USE SIGNAL ;
    PORT
      LAYER M5 ;
        RECT  10.608 58.236 10.632 58.32 ;
    END
  END dout[357]
  PIN dout[358]
    DIRECTION OUTPUT ;
    USE SIGNAL ;
    PORT
      LAYER M5 ;
        RECT  10.704 58.236 10.728 58.32 ;
    END
  END dout[358]
  PIN dout[359]
    DIRECTION OUTPUT ;
    USE SIGNAL ;
    PORT
      LAYER M5 ;
        RECT  10.8 58.236 10.824 58.32 ;
    END
  END dout[359]
  PIN dout[35]
    DIRECTION OUTPUT ;
    USE SIGNAL ;
    PORT
      LAYER M5 ;
        RECT  74.928 58.236 74.952 58.32 ;
    END
  END dout[35]
  PIN dout[360]
    DIRECTION OUTPUT ;
    USE SIGNAL ;
    PORT
      LAYER M5 ;
        RECT  10.896 58.236 10.92 58.32 ;
    END
  END dout[360]
  PIN dout[361]
    DIRECTION OUTPUT ;
    USE SIGNAL ;
    PORT
      LAYER M5 ;
        RECT  10.992 58.236 11.016 58.32 ;
    END
  END dout[361]
  PIN dout[362]
    DIRECTION OUTPUT ;
    USE SIGNAL ;
    PORT
      LAYER M5 ;
        RECT  11.088 58.236 11.112 58.32 ;
    END
  END dout[362]
  PIN dout[363]
    DIRECTION OUTPUT ;
    USE SIGNAL ;
    PORT
      LAYER M5 ;
        RECT  11.184 58.236 11.208 58.32 ;
    END
  END dout[363]
  PIN dout[364]
    DIRECTION OUTPUT ;
    USE SIGNAL ;
    PORT
      LAYER M5 ;
        RECT  11.28 58.236 11.304 58.32 ;
    END
  END dout[364]
  PIN dout[365]
    DIRECTION OUTPUT ;
    USE SIGNAL ;
    PORT
      LAYER M5 ;
        RECT  11.376 58.236 11.4 58.32 ;
    END
  END dout[365]
  PIN dout[366]
    DIRECTION OUTPUT ;
    USE SIGNAL ;
    PORT
      LAYER M5 ;
        RECT  11.472 58.236 11.496 58.32 ;
    END
  END dout[366]
  PIN dout[367]
    DIRECTION OUTPUT ;
    USE SIGNAL ;
    PORT
      LAYER M5 ;
        RECT  11.568 58.236 11.592 58.32 ;
    END
  END dout[367]
  PIN dout[368]
    DIRECTION OUTPUT ;
    USE SIGNAL ;
    PORT
      LAYER M5 ;
        RECT  11.664 58.236 11.688 58.32 ;
    END
  END dout[368]
  PIN dout[369]
    DIRECTION OUTPUT ;
    USE SIGNAL ;
    PORT
      LAYER M5 ;
        RECT  11.76 58.236 11.784 58.32 ;
    END
  END dout[369]
  PIN dout[36]
    DIRECTION OUTPUT ;
    USE SIGNAL ;
    PORT
      LAYER M5 ;
        RECT  75.024 58.236 75.048 58.32 ;
    END
  END dout[36]
  PIN dout[370]
    DIRECTION OUTPUT ;
    USE SIGNAL ;
    PORT
      LAYER M5 ;
        RECT  11.856 58.236 11.88 58.32 ;
    END
  END dout[370]
  PIN dout[371]
    DIRECTION OUTPUT ;
    USE SIGNAL ;
    PORT
      LAYER M5 ;
        RECT  11.952 58.236 11.976 58.32 ;
    END
  END dout[371]
  PIN dout[372]
    DIRECTION OUTPUT ;
    USE SIGNAL ;
    PORT
      LAYER M5 ;
        RECT  12.048 58.236 12.072 58.32 ;
    END
  END dout[372]
  PIN dout[373]
    DIRECTION OUTPUT ;
    USE SIGNAL ;
    PORT
      LAYER M5 ;
        RECT  12.144 58.236 12.168 58.32 ;
    END
  END dout[373]
  PIN dout[374]
    DIRECTION OUTPUT ;
    USE SIGNAL ;
    PORT
      LAYER M5 ;
        RECT  12.24 58.236 12.264 58.32 ;
    END
  END dout[374]
  PIN dout[375]
    DIRECTION OUTPUT ;
    USE SIGNAL ;
    PORT
      LAYER M5 ;
        RECT  12.336 58.236 12.36 58.32 ;
    END
  END dout[375]
  PIN dout[376]
    DIRECTION OUTPUT ;
    USE SIGNAL ;
    PORT
      LAYER M5 ;
        RECT  12.432 58.236 12.456 58.32 ;
    END
  END dout[376]
  PIN dout[377]
    DIRECTION OUTPUT ;
    USE SIGNAL ;
    PORT
      LAYER M5 ;
        RECT  12.528 58.236 12.552 58.32 ;
    END
  END dout[377]
  PIN dout[378]
    DIRECTION OUTPUT ;
    USE SIGNAL ;
    PORT
      LAYER M5 ;
        RECT  12.624 58.236 12.648 58.32 ;
    END
  END dout[378]
  PIN dout[379]
    DIRECTION OUTPUT ;
    USE SIGNAL ;
    PORT
      LAYER M5 ;
        RECT  12.72 58.236 12.744 58.32 ;
    END
  END dout[379]
  PIN dout[37]
    DIRECTION OUTPUT ;
    USE SIGNAL ;
    PORT
      LAYER M5 ;
        RECT  75.12 58.236 75.144 58.32 ;
    END
  END dout[37]
  PIN dout[380]
    DIRECTION OUTPUT ;
    USE SIGNAL ;
    PORT
      LAYER M5 ;
        RECT  12.816 58.236 12.84 58.32 ;
    END
  END dout[380]
  PIN dout[381]
    DIRECTION OUTPUT ;
    USE SIGNAL ;
    PORT
      LAYER M5 ;
        RECT  12.912 58.236 12.936 58.32 ;
    END
  END dout[381]
  PIN dout[382]
    DIRECTION OUTPUT ;
    USE SIGNAL ;
    PORT
      LAYER M5 ;
        RECT  13.008 58.236 13.032 58.32 ;
    END
  END dout[382]
  PIN dout[383]
    DIRECTION OUTPUT ;
    USE SIGNAL ;
    PORT
      LAYER M5 ;
        RECT  13.104 58.236 13.128 58.32 ;
    END
  END dout[383]
  PIN dout[384]
    DIRECTION OUTPUT ;
    USE SIGNAL ;
    PORT
      LAYER M5 ;
        RECT  26.256 58.236 26.28 58.32 ;
    END
  END dout[384]
  PIN dout[385]
    DIRECTION OUTPUT ;
    USE SIGNAL ;
    PORT
      LAYER M5 ;
        RECT  26.352 58.236 26.376 58.32 ;
    END
  END dout[385]
  PIN dout[386]
    DIRECTION OUTPUT ;
    USE SIGNAL ;
    PORT
      LAYER M5 ;
        RECT  26.448 58.236 26.472 58.32 ;
    END
  END dout[386]
  PIN dout[387]
    DIRECTION OUTPUT ;
    USE SIGNAL ;
    PORT
      LAYER M5 ;
        RECT  26.544 58.236 26.568 58.32 ;
    END
  END dout[387]
  PIN dout[388]
    DIRECTION OUTPUT ;
    USE SIGNAL ;
    PORT
      LAYER M5 ;
        RECT  26.64 58.236 26.664 58.32 ;
    END
  END dout[388]
  PIN dout[389]
    DIRECTION OUTPUT ;
    USE SIGNAL ;
    PORT
      LAYER M5 ;
        RECT  26.736 58.236 26.76 58.32 ;
    END
  END dout[389]
  PIN dout[38]
    DIRECTION OUTPUT ;
    USE SIGNAL ;
    PORT
      LAYER M5 ;
        RECT  75.216 58.236 75.24 58.32 ;
    END
  END dout[38]
  PIN dout[390]
    DIRECTION OUTPUT ;
    USE SIGNAL ;
    PORT
      LAYER M5 ;
        RECT  26.832 58.236 26.856 58.32 ;
    END
  END dout[390]
  PIN dout[391]
    DIRECTION OUTPUT ;
    USE SIGNAL ;
    PORT
      LAYER M5 ;
        RECT  26.928 58.236 26.952 58.32 ;
    END
  END dout[391]
  PIN dout[392]
    DIRECTION OUTPUT ;
    USE SIGNAL ;
    PORT
      LAYER M5 ;
        RECT  27.024 58.236 27.048 58.32 ;
    END
  END dout[392]
  PIN dout[393]
    DIRECTION OUTPUT ;
    USE SIGNAL ;
    PORT
      LAYER M5 ;
        RECT  27.12 58.236 27.144 58.32 ;
    END
  END dout[393]
  PIN dout[394]
    DIRECTION OUTPUT ;
    USE SIGNAL ;
    PORT
      LAYER M5 ;
        RECT  27.216 58.236 27.24 58.32 ;
    END
  END dout[394]
  PIN dout[395]
    DIRECTION OUTPUT ;
    USE SIGNAL ;
    PORT
      LAYER M5 ;
        RECT  27.312 58.236 27.336 58.32 ;
    END
  END dout[395]
  PIN dout[396]
    DIRECTION OUTPUT ;
    USE SIGNAL ;
    PORT
      LAYER M5 ;
        RECT  27.408 58.236 27.432 58.32 ;
    END
  END dout[396]
  PIN dout[397]
    DIRECTION OUTPUT ;
    USE SIGNAL ;
    PORT
      LAYER M5 ;
        RECT  27.504 58.236 27.528 58.32 ;
    END
  END dout[397]
  PIN dout[398]
    DIRECTION OUTPUT ;
    USE SIGNAL ;
    PORT
      LAYER M5 ;
        RECT  27.6 58.236 27.624 58.32 ;
    END
  END dout[398]
  PIN dout[399]
    DIRECTION OUTPUT ;
    USE SIGNAL ;
    PORT
      LAYER M5 ;
        RECT  27.696 58.236 27.72 58.32 ;
    END
  END dout[399]
  PIN dout[39]
    DIRECTION OUTPUT ;
    USE SIGNAL ;
    PORT
      LAYER M5 ;
        RECT  75.312 58.236 75.336 58.32 ;
    END
  END dout[39]
  PIN dout[3]
    DIRECTION OUTPUT ;
    USE SIGNAL ;
    PORT
      LAYER M5 ;
        RECT  84.144 58.236 84.168 58.32 ;
    END
  END dout[3]
  PIN dout[400]
    DIRECTION OUTPUT ;
    USE SIGNAL ;
    PORT
      LAYER M5 ;
        RECT  27.792 58.236 27.816 58.32 ;
    END
  END dout[400]
  PIN dout[401]
    DIRECTION OUTPUT ;
    USE SIGNAL ;
    PORT
      LAYER M5 ;
        RECT  27.888 58.236 27.912 58.32 ;
    END
  END dout[401]
  PIN dout[402]
    DIRECTION OUTPUT ;
    USE SIGNAL ;
    PORT
      LAYER M5 ;
        RECT  27.984 58.236 28.008 58.32 ;
    END
  END dout[402]
  PIN dout[403]
    DIRECTION OUTPUT ;
    USE SIGNAL ;
    PORT
      LAYER M5 ;
        RECT  28.08 58.236 28.104 58.32 ;
    END
  END dout[403]
  PIN dout[404]
    DIRECTION OUTPUT ;
    USE SIGNAL ;
    PORT
      LAYER M5 ;
        RECT  28.176 58.236 28.2 58.32 ;
    END
  END dout[404]
  PIN dout[405]
    DIRECTION OUTPUT ;
    USE SIGNAL ;
    PORT
      LAYER M5 ;
        RECT  28.272 58.236 28.296 58.32 ;
    END
  END dout[405]
  PIN dout[406]
    DIRECTION OUTPUT ;
    USE SIGNAL ;
    PORT
      LAYER M5 ;
        RECT  28.368 58.236 28.392 58.32 ;
    END
  END dout[406]
  PIN dout[407]
    DIRECTION OUTPUT ;
    USE SIGNAL ;
    PORT
      LAYER M5 ;
        RECT  28.464 58.236 28.488 58.32 ;
    END
  END dout[407]
  PIN dout[408]
    DIRECTION OUTPUT ;
    USE SIGNAL ;
    PORT
      LAYER M5 ;
        RECT  28.56 58.236 28.584 58.32 ;
    END
  END dout[408]
  PIN dout[409]
    DIRECTION OUTPUT ;
    USE SIGNAL ;
    PORT
      LAYER M5 ;
        RECT  28.656 58.236 28.68 58.32 ;
    END
  END dout[409]
  PIN dout[40]
    DIRECTION OUTPUT ;
    USE SIGNAL ;
    PORT
      LAYER M5 ;
        RECT  75.408 58.236 75.432 58.32 ;
    END
  END dout[40]
  PIN dout[410]
    DIRECTION OUTPUT ;
    USE SIGNAL ;
    PORT
      LAYER M5 ;
        RECT  28.752 58.236 28.776 58.32 ;
    END
  END dout[410]
  PIN dout[411]
    DIRECTION OUTPUT ;
    USE SIGNAL ;
    PORT
      LAYER M5 ;
        RECT  28.848 58.236 28.872 58.32 ;
    END
  END dout[411]
  PIN dout[412]
    DIRECTION OUTPUT ;
    USE SIGNAL ;
    PORT
      LAYER M5 ;
        RECT  28.944 58.236 28.968 58.32 ;
    END
  END dout[412]
  PIN dout[413]
    DIRECTION OUTPUT ;
    USE SIGNAL ;
    PORT
      LAYER M5 ;
        RECT  29.04 58.236 29.064 58.32 ;
    END
  END dout[413]
  PIN dout[414]
    DIRECTION OUTPUT ;
    USE SIGNAL ;
    PORT
      LAYER M5 ;
        RECT  29.136 58.236 29.16 58.32 ;
    END
  END dout[414]
  PIN dout[415]
    DIRECTION OUTPUT ;
    USE SIGNAL ;
    PORT
      LAYER M5 ;
        RECT  29.232 58.236 29.256 58.32 ;
    END
  END dout[415]
  PIN dout[416]
    DIRECTION OUTPUT ;
    USE SIGNAL ;
    PORT
      LAYER M5 ;
        RECT  20.112 58.236 20.136 58.32 ;
    END
  END dout[416]
  PIN dout[417]
    DIRECTION OUTPUT ;
    USE SIGNAL ;
    PORT
      LAYER M5 ;
        RECT  20.208 58.236 20.232 58.32 ;
    END
  END dout[417]
  PIN dout[418]
    DIRECTION OUTPUT ;
    USE SIGNAL ;
    PORT
      LAYER M5 ;
        RECT  20.304 58.236 20.328 58.32 ;
    END
  END dout[418]
  PIN dout[419]
    DIRECTION OUTPUT ;
    USE SIGNAL ;
    PORT
      LAYER M5 ;
        RECT  20.4 58.236 20.424 58.32 ;
    END
  END dout[419]
  PIN dout[41]
    DIRECTION OUTPUT ;
    USE SIGNAL ;
    PORT
      LAYER M5 ;
        RECT  75.504 58.236 75.528 58.32 ;
    END
  END dout[41]
  PIN dout[420]
    DIRECTION OUTPUT ;
    USE SIGNAL ;
    PORT
      LAYER M5 ;
        RECT  20.496 58.236 20.52 58.32 ;
    END
  END dout[420]
  PIN dout[421]
    DIRECTION OUTPUT ;
    USE SIGNAL ;
    PORT
      LAYER M5 ;
        RECT  20.592 58.236 20.616 58.32 ;
    END
  END dout[421]
  PIN dout[422]
    DIRECTION OUTPUT ;
    USE SIGNAL ;
    PORT
      LAYER M5 ;
        RECT  20.688 58.236 20.712 58.32 ;
    END
  END dout[422]
  PIN dout[423]
    DIRECTION OUTPUT ;
    USE SIGNAL ;
    PORT
      LAYER M5 ;
        RECT  20.784 58.236 20.808 58.32 ;
    END
  END dout[423]
  PIN dout[424]
    DIRECTION OUTPUT ;
    USE SIGNAL ;
    PORT
      LAYER M5 ;
        RECT  20.88 58.236 20.904 58.32 ;
    END
  END dout[424]
  PIN dout[425]
    DIRECTION OUTPUT ;
    USE SIGNAL ;
    PORT
      LAYER M5 ;
        RECT  20.976 58.236 21 58.32 ;
    END
  END dout[425]
  PIN dout[426]
    DIRECTION OUTPUT ;
    USE SIGNAL ;
    PORT
      LAYER M5 ;
        RECT  21.072 58.236 21.096 58.32 ;
    END
  END dout[426]
  PIN dout[427]
    DIRECTION OUTPUT ;
    USE SIGNAL ;
    PORT
      LAYER M5 ;
        RECT  21.168 58.236 21.192 58.32 ;
    END
  END dout[427]
  PIN dout[428]
    DIRECTION OUTPUT ;
    USE SIGNAL ;
    PORT
      LAYER M5 ;
        RECT  21.264 58.236 21.288 58.32 ;
    END
  END dout[428]
  PIN dout[429]
    DIRECTION OUTPUT ;
    USE SIGNAL ;
    PORT
      LAYER M5 ;
        RECT  21.36 58.236 21.384 58.32 ;
    END
  END dout[429]
  PIN dout[42]
    DIRECTION OUTPUT ;
    USE SIGNAL ;
    PORT
      LAYER M5 ;
        RECT  75.6 58.236 75.624 58.32 ;
    END
  END dout[42]
  PIN dout[430]
    DIRECTION OUTPUT ;
    USE SIGNAL ;
    PORT
      LAYER M5 ;
        RECT  21.456 58.236 21.48 58.32 ;
    END
  END dout[430]
  PIN dout[431]
    DIRECTION OUTPUT ;
    USE SIGNAL ;
    PORT
      LAYER M5 ;
        RECT  21.552 58.236 21.576 58.32 ;
    END
  END dout[431]
  PIN dout[432]
    DIRECTION OUTPUT ;
    USE SIGNAL ;
    PORT
      LAYER M5 ;
        RECT  21.648 58.236 21.672 58.32 ;
    END
  END dout[432]
  PIN dout[433]
    DIRECTION OUTPUT ;
    USE SIGNAL ;
    PORT
      LAYER M5 ;
        RECT  21.744 58.236 21.768 58.32 ;
    END
  END dout[433]
  PIN dout[434]
    DIRECTION OUTPUT ;
    USE SIGNAL ;
    PORT
      LAYER M5 ;
        RECT  21.84 58.236 21.864 58.32 ;
    END
  END dout[434]
  PIN dout[435]
    DIRECTION OUTPUT ;
    USE SIGNAL ;
    PORT
      LAYER M5 ;
        RECT  21.936 58.236 21.96 58.32 ;
    END
  END dout[435]
  PIN dout[436]
    DIRECTION OUTPUT ;
    USE SIGNAL ;
    PORT
      LAYER M5 ;
        RECT  22.032 58.236 22.056 58.32 ;
    END
  END dout[436]
  PIN dout[437]
    DIRECTION OUTPUT ;
    USE SIGNAL ;
    PORT
      LAYER M5 ;
        RECT  22.128 58.236 22.152 58.32 ;
    END
  END dout[437]
  PIN dout[438]
    DIRECTION OUTPUT ;
    USE SIGNAL ;
    PORT
      LAYER M5 ;
        RECT  22.224 58.236 22.248 58.32 ;
    END
  END dout[438]
  PIN dout[439]
    DIRECTION OUTPUT ;
    USE SIGNAL ;
    PORT
      LAYER M5 ;
        RECT  22.32 58.236 22.344 58.32 ;
    END
  END dout[439]
  PIN dout[43]
    DIRECTION OUTPUT ;
    USE SIGNAL ;
    PORT
      LAYER M5 ;
        RECT  75.696 58.236 75.72 58.32 ;
    END
  END dout[43]
  PIN dout[440]
    DIRECTION OUTPUT ;
    USE SIGNAL ;
    PORT
      LAYER M5 ;
        RECT  22.416 58.236 22.44 58.32 ;
    END
  END dout[440]
  PIN dout[441]
    DIRECTION OUTPUT ;
    USE SIGNAL ;
    PORT
      LAYER M5 ;
        RECT  22.512 58.236 22.536 58.32 ;
    END
  END dout[441]
  PIN dout[442]
    DIRECTION OUTPUT ;
    USE SIGNAL ;
    PORT
      LAYER M5 ;
        RECT  22.608 58.236 22.632 58.32 ;
    END
  END dout[442]
  PIN dout[443]
    DIRECTION OUTPUT ;
    USE SIGNAL ;
    PORT
      LAYER M5 ;
        RECT  22.704 58.236 22.728 58.32 ;
    END
  END dout[443]
  PIN dout[444]
    DIRECTION OUTPUT ;
    USE SIGNAL ;
    PORT
      LAYER M5 ;
        RECT  22.8 58.236 22.824 58.32 ;
    END
  END dout[444]
  PIN dout[445]
    DIRECTION OUTPUT ;
    USE SIGNAL ;
    PORT
      LAYER M5 ;
        RECT  22.896 58.236 22.92 58.32 ;
    END
  END dout[445]
  PIN dout[446]
    DIRECTION OUTPUT ;
    USE SIGNAL ;
    PORT
      LAYER M5 ;
        RECT  22.992 58.236 23.016 58.32 ;
    END
  END dout[446]
  PIN dout[447]
    DIRECTION OUTPUT ;
    USE SIGNAL ;
    PORT
      LAYER M5 ;
        RECT  23.088 58.236 23.112 58.32 ;
    END
  END dout[447]
  PIN dout[448]
    DIRECTION OUTPUT ;
    USE SIGNAL ;
    PORT
      LAYER M5 ;
        RECT  39.312 58.236 39.336 58.32 ;
    END
  END dout[448]
  PIN dout[449]
    DIRECTION OUTPUT ;
    USE SIGNAL ;
    PORT
      LAYER M5 ;
        RECT  39.408 58.236 39.432 58.32 ;
    END
  END dout[449]
  PIN dout[44]
    DIRECTION OUTPUT ;
    USE SIGNAL ;
    PORT
      LAYER M5 ;
        RECT  75.792 58.236 75.816 58.32 ;
    END
  END dout[44]
  PIN dout[450]
    DIRECTION OUTPUT ;
    USE SIGNAL ;
    PORT
      LAYER M5 ;
        RECT  39.504 58.236 39.528 58.32 ;
    END
  END dout[450]
  PIN dout[451]
    DIRECTION OUTPUT ;
    USE SIGNAL ;
    PORT
      LAYER M5 ;
        RECT  39.6 58.236 39.624 58.32 ;
    END
  END dout[451]
  PIN dout[452]
    DIRECTION OUTPUT ;
    USE SIGNAL ;
    PORT
      LAYER M5 ;
        RECT  39.696 58.236 39.72 58.32 ;
    END
  END dout[452]
  PIN dout[453]
    DIRECTION OUTPUT ;
    USE SIGNAL ;
    PORT
      LAYER M5 ;
        RECT  39.792 58.236 39.816 58.32 ;
    END
  END dout[453]
  PIN dout[454]
    DIRECTION OUTPUT ;
    USE SIGNAL ;
    PORT
      LAYER M5 ;
        RECT  39.888 58.236 39.912 58.32 ;
    END
  END dout[454]
  PIN dout[455]
    DIRECTION OUTPUT ;
    USE SIGNAL ;
    PORT
      LAYER M5 ;
        RECT  39.984 58.236 40.008 58.32 ;
    END
  END dout[455]
  PIN dout[456]
    DIRECTION OUTPUT ;
    USE SIGNAL ;
    PORT
      LAYER M5 ;
        RECT  40.08 58.236 40.104 58.32 ;
    END
  END dout[456]
  PIN dout[457]
    DIRECTION OUTPUT ;
    USE SIGNAL ;
    PORT
      LAYER M5 ;
        RECT  40.176 58.236 40.2 58.32 ;
    END
  END dout[457]
  PIN dout[458]
    DIRECTION OUTPUT ;
    USE SIGNAL ;
    PORT
      LAYER M5 ;
        RECT  40.272 58.236 40.296 58.32 ;
    END
  END dout[458]
  PIN dout[459]
    DIRECTION OUTPUT ;
    USE SIGNAL ;
    PORT
      LAYER M5 ;
        RECT  40.368 58.236 40.392 58.32 ;
    END
  END dout[459]
  PIN dout[45]
    DIRECTION OUTPUT ;
    USE SIGNAL ;
    PORT
      LAYER M5 ;
        RECT  75.888 58.236 75.912 58.32 ;
    END
  END dout[45]
  PIN dout[460]
    DIRECTION OUTPUT ;
    USE SIGNAL ;
    PORT
      LAYER M5 ;
        RECT  40.464 58.236 40.488 58.32 ;
    END
  END dout[460]
  PIN dout[461]
    DIRECTION OUTPUT ;
    USE SIGNAL ;
    PORT
      LAYER M5 ;
        RECT  40.56 58.236 40.584 58.32 ;
    END
  END dout[461]
  PIN dout[462]
    DIRECTION OUTPUT ;
    USE SIGNAL ;
    PORT
      LAYER M5 ;
        RECT  40.656 58.236 40.68 58.32 ;
    END
  END dout[462]
  PIN dout[463]
    DIRECTION OUTPUT ;
    USE SIGNAL ;
    PORT
      LAYER M5 ;
        RECT  40.752 58.236 40.776 58.32 ;
    END
  END dout[463]
  PIN dout[464]
    DIRECTION OUTPUT ;
    USE SIGNAL ;
    PORT
      LAYER M5 ;
        RECT  40.848 58.236 40.872 58.32 ;
    END
  END dout[464]
  PIN dout[465]
    DIRECTION OUTPUT ;
    USE SIGNAL ;
    PORT
      LAYER M5 ;
        RECT  40.944 58.236 40.968 58.32 ;
    END
  END dout[465]
  PIN dout[466]
    DIRECTION OUTPUT ;
    USE SIGNAL ;
    PORT
      LAYER M5 ;
        RECT  41.04 58.236 41.064 58.32 ;
    END
  END dout[466]
  PIN dout[467]
    DIRECTION OUTPUT ;
    USE SIGNAL ;
    PORT
      LAYER M5 ;
        RECT  41.136 58.236 41.16 58.32 ;
    END
  END dout[467]
  PIN dout[468]
    DIRECTION OUTPUT ;
    USE SIGNAL ;
    PORT
      LAYER M5 ;
        RECT  41.232 58.236 41.256 58.32 ;
    END
  END dout[468]
  PIN dout[469]
    DIRECTION OUTPUT ;
    USE SIGNAL ;
    PORT
      LAYER M5 ;
        RECT  41.328 58.236 41.352 58.32 ;
    END
  END dout[469]
  PIN dout[46]
    DIRECTION OUTPUT ;
    USE SIGNAL ;
    PORT
      LAYER M5 ;
        RECT  75.984 58.236 76.008 58.32 ;
    END
  END dout[46]
  PIN dout[470]
    DIRECTION OUTPUT ;
    USE SIGNAL ;
    PORT
      LAYER M5 ;
        RECT  41.424 58.236 41.448 58.32 ;
    END
  END dout[470]
  PIN dout[471]
    DIRECTION OUTPUT ;
    USE SIGNAL ;
    PORT
      LAYER M5 ;
        RECT  41.52 58.236 41.544 58.32 ;
    END
  END dout[471]
  PIN dout[472]
    DIRECTION OUTPUT ;
    USE SIGNAL ;
    PORT
      LAYER M5 ;
        RECT  41.616 58.236 41.64 58.32 ;
    END
  END dout[472]
  PIN dout[473]
    DIRECTION OUTPUT ;
    USE SIGNAL ;
    PORT
      LAYER M5 ;
        RECT  41.712 58.236 41.736 58.32 ;
    END
  END dout[473]
  PIN dout[474]
    DIRECTION OUTPUT ;
    USE SIGNAL ;
    PORT
      LAYER M5 ;
        RECT  41.808 58.236 41.832 58.32 ;
    END
  END dout[474]
  PIN dout[475]
    DIRECTION OUTPUT ;
    USE SIGNAL ;
    PORT
      LAYER M5 ;
        RECT  41.904 58.236 41.928 58.32 ;
    END
  END dout[475]
  PIN dout[476]
    DIRECTION OUTPUT ;
    USE SIGNAL ;
    PORT
      LAYER M5 ;
        RECT  42 58.236 42.024 58.32 ;
    END
  END dout[476]
  PIN dout[477]
    DIRECTION OUTPUT ;
    USE SIGNAL ;
    PORT
      LAYER M5 ;
        RECT  42.096 58.236 42.12 58.32 ;
    END
  END dout[477]
  PIN dout[478]
    DIRECTION OUTPUT ;
    USE SIGNAL ;
    PORT
      LAYER M5 ;
        RECT  42.192 58.236 42.216 58.32 ;
    END
  END dout[478]
  PIN dout[479]
    DIRECTION OUTPUT ;
    USE SIGNAL ;
    PORT
      LAYER M5 ;
        RECT  42.288 58.236 42.312 58.32 ;
    END
  END dout[479]
  PIN dout[47]
    DIRECTION OUTPUT ;
    USE SIGNAL ;
    PORT
      LAYER M5 ;
        RECT  76.08 58.236 76.104 58.32 ;
    END
  END dout[47]
  PIN dout[480]
    DIRECTION OUTPUT ;
    USE SIGNAL ;
    PORT
      LAYER M5 ;
        RECT  61.584 58.236 61.608 58.32 ;
    END
  END dout[480]
  PIN dout[481]
    DIRECTION OUTPUT ;
    USE SIGNAL ;
    PORT
      LAYER M5 ;
        RECT  61.68 58.236 61.704 58.32 ;
    END
  END dout[481]
  PIN dout[482]
    DIRECTION OUTPUT ;
    USE SIGNAL ;
    PORT
      LAYER M5 ;
        RECT  61.776 58.236 61.8 58.32 ;
    END
  END dout[482]
  PIN dout[483]
    DIRECTION OUTPUT ;
    USE SIGNAL ;
    PORT
      LAYER M5 ;
        RECT  61.872 58.236 61.896 58.32 ;
    END
  END dout[483]
  PIN dout[484]
    DIRECTION OUTPUT ;
    USE SIGNAL ;
    PORT
      LAYER M5 ;
        RECT  61.968 58.236 61.992 58.32 ;
    END
  END dout[484]
  PIN dout[485]
    DIRECTION OUTPUT ;
    USE SIGNAL ;
    PORT
      LAYER M5 ;
        RECT  62.064 58.236 62.088 58.32 ;
    END
  END dout[485]
  PIN dout[486]
    DIRECTION OUTPUT ;
    USE SIGNAL ;
    PORT
      LAYER M5 ;
        RECT  62.16 58.236 62.184 58.32 ;
    END
  END dout[486]
  PIN dout[487]
    DIRECTION OUTPUT ;
    USE SIGNAL ;
    PORT
      LAYER M5 ;
        RECT  62.256 58.236 62.28 58.32 ;
    END
  END dout[487]
  PIN dout[488]
    DIRECTION OUTPUT ;
    USE SIGNAL ;
    PORT
      LAYER M5 ;
        RECT  62.352 58.236 62.376 58.32 ;
    END
  END dout[488]
  PIN dout[489]
    DIRECTION OUTPUT ;
    USE SIGNAL ;
    PORT
      LAYER M5 ;
        RECT  62.448 58.236 62.472 58.32 ;
    END
  END dout[489]
  PIN dout[48]
    DIRECTION OUTPUT ;
    USE SIGNAL ;
    PORT
      LAYER M5 ;
        RECT  76.176 58.236 76.2 58.32 ;
    END
  END dout[48]
  PIN dout[490]
    DIRECTION OUTPUT ;
    USE SIGNAL ;
    PORT
      LAYER M5 ;
        RECT  62.544 58.236 62.568 58.32 ;
    END
  END dout[490]
  PIN dout[491]
    DIRECTION OUTPUT ;
    USE SIGNAL ;
    PORT
      LAYER M5 ;
        RECT  62.64 58.236 62.664 58.32 ;
    END
  END dout[491]
  PIN dout[492]
    DIRECTION OUTPUT ;
    USE SIGNAL ;
    PORT
      LAYER M5 ;
        RECT  62.736 58.236 62.76 58.32 ;
    END
  END dout[492]
  PIN dout[493]
    DIRECTION OUTPUT ;
    USE SIGNAL ;
    PORT
      LAYER M5 ;
        RECT  62.832 58.236 62.856 58.32 ;
    END
  END dout[493]
  PIN dout[494]
    DIRECTION OUTPUT ;
    USE SIGNAL ;
    PORT
      LAYER M5 ;
        RECT  62.928 58.236 62.952 58.32 ;
    END
  END dout[494]
  PIN dout[495]
    DIRECTION OUTPUT ;
    USE SIGNAL ;
    PORT
      LAYER M5 ;
        RECT  63.024 58.236 63.048 58.32 ;
    END
  END dout[495]
  PIN dout[496]
    DIRECTION OUTPUT ;
    USE SIGNAL ;
    PORT
      LAYER M5 ;
        RECT  63.12 58.236 63.144 58.32 ;
    END
  END dout[496]
  PIN dout[497]
    DIRECTION OUTPUT ;
    USE SIGNAL ;
    PORT
      LAYER M5 ;
        RECT  63.216 58.236 63.24 58.32 ;
    END
  END dout[497]
  PIN dout[498]
    DIRECTION OUTPUT ;
    USE SIGNAL ;
    PORT
      LAYER M5 ;
        RECT  63.312 58.236 63.336 58.32 ;
    END
  END dout[498]
  PIN dout[499]
    DIRECTION OUTPUT ;
    USE SIGNAL ;
    PORT
      LAYER M5 ;
        RECT  63.408 58.236 63.432 58.32 ;
    END
  END dout[499]
  PIN dout[49]
    DIRECTION OUTPUT ;
    USE SIGNAL ;
    PORT
      LAYER M5 ;
        RECT  76.272 58.236 76.296 58.32 ;
    END
  END dout[49]
  PIN dout[4]
    DIRECTION OUTPUT ;
    USE SIGNAL ;
    PORT
      LAYER M5 ;
        RECT  84.24 58.236 84.264 58.32 ;
    END
  END dout[4]
  PIN dout[500]
    DIRECTION OUTPUT ;
    USE SIGNAL ;
    PORT
      LAYER M5 ;
        RECT  63.504 58.236 63.528 58.32 ;
    END
  END dout[500]
  PIN dout[501]
    DIRECTION OUTPUT ;
    USE SIGNAL ;
    PORT
      LAYER M5 ;
        RECT  63.6 58.236 63.624 58.32 ;
    END
  END dout[501]
  PIN dout[502]
    DIRECTION OUTPUT ;
    USE SIGNAL ;
    PORT
      LAYER M5 ;
        RECT  63.696 58.236 63.72 58.32 ;
    END
  END dout[502]
  PIN dout[503]
    DIRECTION OUTPUT ;
    USE SIGNAL ;
    PORT
      LAYER M5 ;
        RECT  63.792 58.236 63.816 58.32 ;
    END
  END dout[503]
  PIN dout[504]
    DIRECTION OUTPUT ;
    USE SIGNAL ;
    PORT
      LAYER M5 ;
        RECT  63.888 58.236 63.912 58.32 ;
    END
  END dout[504]
  PIN dout[505]
    DIRECTION OUTPUT ;
    USE SIGNAL ;
    PORT
      LAYER M5 ;
        RECT  63.984 58.236 64.008 58.32 ;
    END
  END dout[505]
  PIN dout[506]
    DIRECTION OUTPUT ;
    USE SIGNAL ;
    PORT
      LAYER M5 ;
        RECT  64.08 58.236 64.104 58.32 ;
    END
  END dout[506]
  PIN dout[507]
    DIRECTION OUTPUT ;
    USE SIGNAL ;
    PORT
      LAYER M5 ;
        RECT  64.176 58.236 64.2 58.32 ;
    END
  END dout[507]
  PIN dout[508]
    DIRECTION OUTPUT ;
    USE SIGNAL ;
    PORT
      LAYER M5 ;
        RECT  64.272 58.236 64.296 58.32 ;
    END
  END dout[508]
  PIN dout[509]
    DIRECTION OUTPUT ;
    USE SIGNAL ;
    PORT
      LAYER M5 ;
        RECT  64.368 58.236 64.392 58.32 ;
    END
  END dout[509]
  PIN dout[50]
    DIRECTION OUTPUT ;
    USE SIGNAL ;
    PORT
      LAYER M5 ;
        RECT  76.368 58.236 76.392 58.32 ;
    END
  END dout[50]
  PIN dout[510]
    DIRECTION OUTPUT ;
    USE SIGNAL ;
    PORT
      LAYER M5 ;
        RECT  64.464 58.236 64.488 58.32 ;
    END
  END dout[510]
  PIN dout[511]
    DIRECTION OUTPUT ;
    USE SIGNAL ;
    PORT
      LAYER M5 ;
        RECT  64.56 58.236 64.584 58.32 ;
    END
  END dout[511]
  PIN dout[512]
    DIRECTION OUTPUT ;
    USE SIGNAL ;
    PORT
      LAYER M5 ;
        RECT  55.44 58.236 55.464 58.32 ;
    END
  END dout[512]
  PIN dout[513]
    DIRECTION OUTPUT ;
    USE SIGNAL ;
    PORT
      LAYER M5 ;
        RECT  55.536 58.236 55.56 58.32 ;
    END
  END dout[513]
  PIN dout[514]
    DIRECTION OUTPUT ;
    USE SIGNAL ;
    PORT
      LAYER M5 ;
        RECT  55.632 58.236 55.656 58.32 ;
    END
  END dout[514]
  PIN dout[515]
    DIRECTION OUTPUT ;
    USE SIGNAL ;
    PORT
      LAYER M5 ;
        RECT  55.728 58.236 55.752 58.32 ;
    END
  END dout[515]
  PIN dout[516]
    DIRECTION OUTPUT ;
    USE SIGNAL ;
    PORT
      LAYER M5 ;
        RECT  55.824 58.236 55.848 58.32 ;
    END
  END dout[516]
  PIN dout[517]
    DIRECTION OUTPUT ;
    USE SIGNAL ;
    PORT
      LAYER M5 ;
        RECT  55.92 58.236 55.944 58.32 ;
    END
  END dout[517]
  PIN dout[518]
    DIRECTION OUTPUT ;
    USE SIGNAL ;
    PORT
      LAYER M5 ;
        RECT  56.016 58.236 56.04 58.32 ;
    END
  END dout[518]
  PIN dout[519]
    DIRECTION OUTPUT ;
    USE SIGNAL ;
    PORT
      LAYER M5 ;
        RECT  56.112 58.236 56.136 58.32 ;
    END
  END dout[519]
  PIN dout[51]
    DIRECTION OUTPUT ;
    USE SIGNAL ;
    PORT
      LAYER M5 ;
        RECT  76.464 58.236 76.488 58.32 ;
    END
  END dout[51]
  PIN dout[520]
    DIRECTION OUTPUT ;
    USE SIGNAL ;
    PORT
      LAYER M5 ;
        RECT  56.208 58.236 56.232 58.32 ;
    END
  END dout[520]
  PIN dout[521]
    DIRECTION OUTPUT ;
    USE SIGNAL ;
    PORT
      LAYER M5 ;
        RECT  56.304 58.236 56.328 58.32 ;
    END
  END dout[521]
  PIN dout[522]
    DIRECTION OUTPUT ;
    USE SIGNAL ;
    PORT
      LAYER M5 ;
        RECT  56.4 58.236 56.424 58.32 ;
    END
  END dout[522]
  PIN dout[523]
    DIRECTION OUTPUT ;
    USE SIGNAL ;
    PORT
      LAYER M5 ;
        RECT  56.496 58.236 56.52 58.32 ;
    END
  END dout[523]
  PIN dout[524]
    DIRECTION OUTPUT ;
    USE SIGNAL ;
    PORT
      LAYER M5 ;
        RECT  56.592 58.236 56.616 58.32 ;
    END
  END dout[524]
  PIN dout[525]
    DIRECTION OUTPUT ;
    USE SIGNAL ;
    PORT
      LAYER M5 ;
        RECT  56.688 58.236 56.712 58.32 ;
    END
  END dout[525]
  PIN dout[526]
    DIRECTION OUTPUT ;
    USE SIGNAL ;
    PORT
      LAYER M5 ;
        RECT  56.784 58.236 56.808 58.32 ;
    END
  END dout[526]
  PIN dout[527]
    DIRECTION OUTPUT ;
    USE SIGNAL ;
    PORT
      LAYER M5 ;
        RECT  56.88 58.236 56.904 58.32 ;
    END
  END dout[527]
  PIN dout[528]
    DIRECTION OUTPUT ;
    USE SIGNAL ;
    PORT
      LAYER M5 ;
        RECT  56.976 58.236 57 58.32 ;
    END
  END dout[528]
  PIN dout[529]
    DIRECTION OUTPUT ;
    USE SIGNAL ;
    PORT
      LAYER M5 ;
        RECT  57.072 58.236 57.096 58.32 ;
    END
  END dout[529]
  PIN dout[52]
    DIRECTION OUTPUT ;
    USE SIGNAL ;
    PORT
      LAYER M5 ;
        RECT  76.56 58.236 76.584 58.32 ;
    END
  END dout[52]
  PIN dout[530]
    DIRECTION OUTPUT ;
    USE SIGNAL ;
    PORT
      LAYER M5 ;
        RECT  57.168 58.236 57.192 58.32 ;
    END
  END dout[530]
  PIN dout[531]
    DIRECTION OUTPUT ;
    USE SIGNAL ;
    PORT
      LAYER M5 ;
        RECT  57.264 58.236 57.288 58.32 ;
    END
  END dout[531]
  PIN dout[532]
    DIRECTION OUTPUT ;
    USE SIGNAL ;
    PORT
      LAYER M5 ;
        RECT  57.36 58.236 57.384 58.32 ;
    END
  END dout[532]
  PIN dout[533]
    DIRECTION OUTPUT ;
    USE SIGNAL ;
    PORT
      LAYER M5 ;
        RECT  57.456 58.236 57.48 58.32 ;
    END
  END dout[533]
  PIN dout[534]
    DIRECTION OUTPUT ;
    USE SIGNAL ;
    PORT
      LAYER M5 ;
        RECT  57.552 58.236 57.576 58.32 ;
    END
  END dout[534]
  PIN dout[535]
    DIRECTION OUTPUT ;
    USE SIGNAL ;
    PORT
      LAYER M5 ;
        RECT  57.648 58.236 57.672 58.32 ;
    END
  END dout[535]
  PIN dout[536]
    DIRECTION OUTPUT ;
    USE SIGNAL ;
    PORT
      LAYER M5 ;
        RECT  57.744 58.236 57.768 58.32 ;
    END
  END dout[536]
  PIN dout[537]
    DIRECTION OUTPUT ;
    USE SIGNAL ;
    PORT
      LAYER M5 ;
        RECT  57.84 58.236 57.864 58.32 ;
    END
  END dout[537]
  PIN dout[538]
    DIRECTION OUTPUT ;
    USE SIGNAL ;
    PORT
      LAYER M5 ;
        RECT  57.936 58.236 57.96 58.32 ;
    END
  END dout[538]
  PIN dout[539]
    DIRECTION OUTPUT ;
    USE SIGNAL ;
    PORT
      LAYER M5 ;
        RECT  58.032 58.236 58.056 58.32 ;
    END
  END dout[539]
  PIN dout[53]
    DIRECTION OUTPUT ;
    USE SIGNAL ;
    PORT
      LAYER M5 ;
        RECT  76.656 58.236 76.68 58.32 ;
    END
  END dout[53]
  PIN dout[540]
    DIRECTION OUTPUT ;
    USE SIGNAL ;
    PORT
      LAYER M5 ;
        RECT  58.128 58.236 58.152 58.32 ;
    END
  END dout[540]
  PIN dout[541]
    DIRECTION OUTPUT ;
    USE SIGNAL ;
    PORT
      LAYER M5 ;
        RECT  58.224 58.236 58.248 58.32 ;
    END
  END dout[541]
  PIN dout[542]
    DIRECTION OUTPUT ;
    USE SIGNAL ;
    PORT
      LAYER M5 ;
        RECT  58.32 58.236 58.344 58.32 ;
    END
  END dout[542]
  PIN dout[543]
    DIRECTION OUTPUT ;
    USE SIGNAL ;
    PORT
      LAYER M5 ;
        RECT  58.416 58.236 58.44 58.32 ;
    END
  END dout[543]
  PIN dout[544]
    DIRECTION OUTPUT ;
    USE SIGNAL ;
    PORT
      LAYER M5 ;
        RECT  64.656 58.236 64.68 58.32 ;
    END
  END dout[544]
  PIN dout[545]
    DIRECTION OUTPUT ;
    USE SIGNAL ;
    PORT
      LAYER M5 ;
        RECT  64.752 58.236 64.776 58.32 ;
    END
  END dout[545]
  PIN dout[546]
    DIRECTION OUTPUT ;
    USE SIGNAL ;
    PORT
      LAYER M5 ;
        RECT  64.848 58.236 64.872 58.32 ;
    END
  END dout[546]
  PIN dout[547]
    DIRECTION OUTPUT ;
    USE SIGNAL ;
    PORT
      LAYER M5 ;
        RECT  64.944 58.236 64.968 58.32 ;
    END
  END dout[547]
  PIN dout[548]
    DIRECTION OUTPUT ;
    USE SIGNAL ;
    PORT
      LAYER M5 ;
        RECT  65.04 58.236 65.064 58.32 ;
    END
  END dout[548]
  PIN dout[549]
    DIRECTION OUTPUT ;
    USE SIGNAL ;
    PORT
      LAYER M5 ;
        RECT  65.136 58.236 65.16 58.32 ;
    END
  END dout[549]
  PIN dout[54]
    DIRECTION OUTPUT ;
    USE SIGNAL ;
    PORT
      LAYER M5 ;
        RECT  76.752 58.236 76.776 58.32 ;
    END
  END dout[54]
  PIN dout[550]
    DIRECTION OUTPUT ;
    USE SIGNAL ;
    PORT
      LAYER M5 ;
        RECT  65.232 58.236 65.256 58.32 ;
    END
  END dout[550]
  PIN dout[551]
    DIRECTION OUTPUT ;
    USE SIGNAL ;
    PORT
      LAYER M5 ;
        RECT  65.328 58.236 65.352 58.32 ;
    END
  END dout[551]
  PIN dout[552]
    DIRECTION OUTPUT ;
    USE SIGNAL ;
    PORT
      LAYER M5 ;
        RECT  65.424 58.236 65.448 58.32 ;
    END
  END dout[552]
  PIN dout[553]
    DIRECTION OUTPUT ;
    USE SIGNAL ;
    PORT
      LAYER M5 ;
        RECT  65.52 58.236 65.544 58.32 ;
    END
  END dout[553]
  PIN dout[554]
    DIRECTION OUTPUT ;
    USE SIGNAL ;
    PORT
      LAYER M5 ;
        RECT  65.616 58.236 65.64 58.32 ;
    END
  END dout[554]
  PIN dout[555]
    DIRECTION OUTPUT ;
    USE SIGNAL ;
    PORT
      LAYER M5 ;
        RECT  65.712 58.236 65.736 58.32 ;
    END
  END dout[555]
  PIN dout[556]
    DIRECTION OUTPUT ;
    USE SIGNAL ;
    PORT
      LAYER M5 ;
        RECT  65.808 58.236 65.832 58.32 ;
    END
  END dout[556]
  PIN dout[557]
    DIRECTION OUTPUT ;
    USE SIGNAL ;
    PORT
      LAYER M5 ;
        RECT  65.904 58.236 65.928 58.32 ;
    END
  END dout[557]
  PIN dout[558]
    DIRECTION OUTPUT ;
    USE SIGNAL ;
    PORT
      LAYER M5 ;
        RECT  66 58.236 66.024 58.32 ;
    END
  END dout[558]
  PIN dout[559]
    DIRECTION OUTPUT ;
    USE SIGNAL ;
    PORT
      LAYER M5 ;
        RECT  66.096 58.236 66.12 58.32 ;
    END
  END dout[559]
  PIN dout[55]
    DIRECTION OUTPUT ;
    USE SIGNAL ;
    PORT
      LAYER M5 ;
        RECT  76.848 58.236 76.872 58.32 ;
    END
  END dout[55]
  PIN dout[560]
    DIRECTION OUTPUT ;
    USE SIGNAL ;
    PORT
      LAYER M5 ;
        RECT  66.192 58.236 66.216 58.32 ;
    END
  END dout[560]
  PIN dout[561]
    DIRECTION OUTPUT ;
    USE SIGNAL ;
    PORT
      LAYER M5 ;
        RECT  66.288 58.236 66.312 58.32 ;
    END
  END dout[561]
  PIN dout[562]
    DIRECTION OUTPUT ;
    USE SIGNAL ;
    PORT
      LAYER M5 ;
        RECT  66.384 58.236 66.408 58.32 ;
    END
  END dout[562]
  PIN dout[563]
    DIRECTION OUTPUT ;
    USE SIGNAL ;
    PORT
      LAYER M5 ;
        RECT  66.48 58.236 66.504 58.32 ;
    END
  END dout[563]
  PIN dout[564]
    DIRECTION OUTPUT ;
    USE SIGNAL ;
    PORT
      LAYER M5 ;
        RECT  66.576 58.236 66.6 58.32 ;
    END
  END dout[564]
  PIN dout[565]
    DIRECTION OUTPUT ;
    USE SIGNAL ;
    PORT
      LAYER M5 ;
        RECT  66.672 58.236 66.696 58.32 ;
    END
  END dout[565]
  PIN dout[566]
    DIRECTION OUTPUT ;
    USE SIGNAL ;
    PORT
      LAYER M5 ;
        RECT  66.768 58.236 66.792 58.32 ;
    END
  END dout[566]
  PIN dout[567]
    DIRECTION OUTPUT ;
    USE SIGNAL ;
    PORT
      LAYER M5 ;
        RECT  66.864 58.236 66.888 58.32 ;
    END
  END dout[567]
  PIN dout[568]
    DIRECTION OUTPUT ;
    USE SIGNAL ;
    PORT
      LAYER M5 ;
        RECT  66.96 58.236 66.984 58.32 ;
    END
  END dout[568]
  PIN dout[569]
    DIRECTION OUTPUT ;
    USE SIGNAL ;
    PORT
      LAYER M5 ;
        RECT  67.056 58.236 67.08 58.32 ;
    END
  END dout[569]
  PIN dout[56]
    DIRECTION OUTPUT ;
    USE SIGNAL ;
    PORT
      LAYER M5 ;
        RECT  76.944 58.236 76.968 58.32 ;
    END
  END dout[56]
  PIN dout[570]
    DIRECTION OUTPUT ;
    USE SIGNAL ;
    PORT
      LAYER M5 ;
        RECT  67.152 58.236 67.176 58.32 ;
    END
  END dout[570]
  PIN dout[571]
    DIRECTION OUTPUT ;
    USE SIGNAL ;
    PORT
      LAYER M5 ;
        RECT  67.248 58.236 67.272 58.32 ;
    END
  END dout[571]
  PIN dout[572]
    DIRECTION OUTPUT ;
    USE SIGNAL ;
    PORT
      LAYER M5 ;
        RECT  67.344 58.236 67.368 58.32 ;
    END
  END dout[572]
  PIN dout[573]
    DIRECTION OUTPUT ;
    USE SIGNAL ;
    PORT
      LAYER M5 ;
        RECT  67.44 58.236 67.464 58.32 ;
    END
  END dout[573]
  PIN dout[574]
    DIRECTION OUTPUT ;
    USE SIGNAL ;
    PORT
      LAYER M5 ;
        RECT  67.536 58.236 67.56 58.32 ;
    END
  END dout[574]
  PIN dout[575]
    DIRECTION OUTPUT ;
    USE SIGNAL ;
    PORT
      LAYER M5 ;
        RECT  67.632 58.236 67.656 58.32 ;
    END
  END dout[575]
  PIN dout[576]
    DIRECTION OUTPUT ;
    USE SIGNAL ;
    PORT
      LAYER M5 ;
        RECT  58.512 58.236 58.536 58.32 ;
    END
  END dout[576]
  PIN dout[577]
    DIRECTION OUTPUT ;
    USE SIGNAL ;
    PORT
      LAYER M5 ;
        RECT  58.608 58.236 58.632 58.32 ;
    END
  END dout[577]
  PIN dout[578]
    DIRECTION OUTPUT ;
    USE SIGNAL ;
    PORT
      LAYER M5 ;
        RECT  58.704 58.236 58.728 58.32 ;
    END
  END dout[578]
  PIN dout[579]
    DIRECTION OUTPUT ;
    USE SIGNAL ;
    PORT
      LAYER M5 ;
        RECT  58.8 58.236 58.824 58.32 ;
    END
  END dout[579]
  PIN dout[57]
    DIRECTION OUTPUT ;
    USE SIGNAL ;
    PORT
      LAYER M5 ;
        RECT  77.04 58.236 77.064 58.32 ;
    END
  END dout[57]
  PIN dout[580]
    DIRECTION OUTPUT ;
    USE SIGNAL ;
    PORT
      LAYER M5 ;
        RECT  58.896 58.236 58.92 58.32 ;
    END
  END dout[580]
  PIN dout[581]
    DIRECTION OUTPUT ;
    USE SIGNAL ;
    PORT
      LAYER M5 ;
        RECT  58.992 58.236 59.016 58.32 ;
    END
  END dout[581]
  PIN dout[582]
    DIRECTION OUTPUT ;
    USE SIGNAL ;
    PORT
      LAYER M5 ;
        RECT  59.088 58.236 59.112 58.32 ;
    END
  END dout[582]
  PIN dout[583]
    DIRECTION OUTPUT ;
    USE SIGNAL ;
    PORT
      LAYER M5 ;
        RECT  59.184 58.236 59.208 58.32 ;
    END
  END dout[583]
  PIN dout[584]
    DIRECTION OUTPUT ;
    USE SIGNAL ;
    PORT
      LAYER M5 ;
        RECT  59.28 58.236 59.304 58.32 ;
    END
  END dout[584]
  PIN dout[585]
    DIRECTION OUTPUT ;
    USE SIGNAL ;
    PORT
      LAYER M5 ;
        RECT  59.376 58.236 59.4 58.32 ;
    END
  END dout[585]
  PIN dout[586]
    DIRECTION OUTPUT ;
    USE SIGNAL ;
    PORT
      LAYER M5 ;
        RECT  59.472 58.236 59.496 58.32 ;
    END
  END dout[586]
  PIN dout[587]
    DIRECTION OUTPUT ;
    USE SIGNAL ;
    PORT
      LAYER M5 ;
        RECT  59.568 58.236 59.592 58.32 ;
    END
  END dout[587]
  PIN dout[588]
    DIRECTION OUTPUT ;
    USE SIGNAL ;
    PORT
      LAYER M5 ;
        RECT  59.664 58.236 59.688 58.32 ;
    END
  END dout[588]
  PIN dout[589]
    DIRECTION OUTPUT ;
    USE SIGNAL ;
    PORT
      LAYER M5 ;
        RECT  59.76 58.236 59.784 58.32 ;
    END
  END dout[589]
  PIN dout[58]
    DIRECTION OUTPUT ;
    USE SIGNAL ;
    PORT
      LAYER M5 ;
        RECT  77.136 58.236 77.16 58.32 ;
    END
  END dout[58]
  PIN dout[590]
    DIRECTION OUTPUT ;
    USE SIGNAL ;
    PORT
      LAYER M5 ;
        RECT  59.856 58.236 59.88 58.32 ;
    END
  END dout[590]
  PIN dout[591]
    DIRECTION OUTPUT ;
    USE SIGNAL ;
    PORT
      LAYER M5 ;
        RECT  59.952 58.236 59.976 58.32 ;
    END
  END dout[591]
  PIN dout[592]
    DIRECTION OUTPUT ;
    USE SIGNAL ;
    PORT
      LAYER M5 ;
        RECT  60.048 58.236 60.072 58.32 ;
    END
  END dout[592]
  PIN dout[593]
    DIRECTION OUTPUT ;
    USE SIGNAL ;
    PORT
      LAYER M5 ;
        RECT  60.144 58.236 60.168 58.32 ;
    END
  END dout[593]
  PIN dout[594]
    DIRECTION OUTPUT ;
    USE SIGNAL ;
    PORT
      LAYER M5 ;
        RECT  60.24 58.236 60.264 58.32 ;
    END
  END dout[594]
  PIN dout[595]
    DIRECTION OUTPUT ;
    USE SIGNAL ;
    PORT
      LAYER M5 ;
        RECT  60.336 58.236 60.36 58.32 ;
    END
  END dout[595]
  PIN dout[596]
    DIRECTION OUTPUT ;
    USE SIGNAL ;
    PORT
      LAYER M5 ;
        RECT  60.432 58.236 60.456 58.32 ;
    END
  END dout[596]
  PIN dout[597]
    DIRECTION OUTPUT ;
    USE SIGNAL ;
    PORT
      LAYER M5 ;
        RECT  60.528 58.236 60.552 58.32 ;
    END
  END dout[597]
  PIN dout[598]
    DIRECTION OUTPUT ;
    USE SIGNAL ;
    PORT
      LAYER M5 ;
        RECT  60.624 58.236 60.648 58.32 ;
    END
  END dout[598]
  PIN dout[599]
    DIRECTION OUTPUT ;
    USE SIGNAL ;
    PORT
      LAYER M5 ;
        RECT  60.72 58.236 60.744 58.32 ;
    END
  END dout[599]
  PIN dout[59]
    DIRECTION OUTPUT ;
    USE SIGNAL ;
    PORT
      LAYER M5 ;
        RECT  77.232 58.236 77.256 58.32 ;
    END
  END dout[59]
  PIN dout[5]
    DIRECTION OUTPUT ;
    USE SIGNAL ;
    PORT
      LAYER M5 ;
        RECT  84.336 58.236 84.36 58.32 ;
    END
  END dout[5]
  PIN dout[600]
    DIRECTION OUTPUT ;
    USE SIGNAL ;
    PORT
      LAYER M5 ;
        RECT  60.816 58.236 60.84 58.32 ;
    END
  END dout[600]
  PIN dout[601]
    DIRECTION OUTPUT ;
    USE SIGNAL ;
    PORT
      LAYER M5 ;
        RECT  60.912 58.236 60.936 58.32 ;
    END
  END dout[601]
  PIN dout[602]
    DIRECTION OUTPUT ;
    USE SIGNAL ;
    PORT
      LAYER M5 ;
        RECT  61.008 58.236 61.032 58.32 ;
    END
  END dout[602]
  PIN dout[603]
    DIRECTION OUTPUT ;
    USE SIGNAL ;
    PORT
      LAYER M5 ;
        RECT  61.104 58.236 61.128 58.32 ;
    END
  END dout[603]
  PIN dout[604]
    DIRECTION OUTPUT ;
    USE SIGNAL ;
    PORT
      LAYER M5 ;
        RECT  61.2 58.236 61.224 58.32 ;
    END
  END dout[604]
  PIN dout[605]
    DIRECTION OUTPUT ;
    USE SIGNAL ;
    PORT
      LAYER M5 ;
        RECT  61.296 58.236 61.32 58.32 ;
    END
  END dout[605]
  PIN dout[606]
    DIRECTION OUTPUT ;
    USE SIGNAL ;
    PORT
      LAYER M5 ;
        RECT  61.392 58.236 61.416 58.32 ;
    END
  END dout[606]
  PIN dout[607]
    DIRECTION OUTPUT ;
    USE SIGNAL ;
    PORT
      LAYER M5 ;
        RECT  61.488 58.236 61.512 58.32 ;
    END
  END dout[607]
  PIN dout[608]
    DIRECTION OUTPUT ;
    USE SIGNAL ;
    PORT
      LAYER M5 ;
        RECT  42.384 58.236 42.408 58.32 ;
    END
  END dout[608]
  PIN dout[609]
    DIRECTION OUTPUT ;
    USE SIGNAL ;
    PORT
      LAYER M5 ;
        RECT  42.48 58.236 42.504 58.32 ;
    END
  END dout[609]
  PIN dout[60]
    DIRECTION OUTPUT ;
    USE SIGNAL ;
    PORT
      LAYER M5 ;
        RECT  77.328 58.236 77.352 58.32 ;
    END
  END dout[60]
  PIN dout[610]
    DIRECTION OUTPUT ;
    USE SIGNAL ;
    PORT
      LAYER M5 ;
        RECT  42.576 58.236 42.6 58.32 ;
    END
  END dout[610]
  PIN dout[611]
    DIRECTION OUTPUT ;
    USE SIGNAL ;
    PORT
      LAYER M5 ;
        RECT  42.672 58.236 42.696 58.32 ;
    END
  END dout[611]
  PIN dout[612]
    DIRECTION OUTPUT ;
    USE SIGNAL ;
    PORT
      LAYER M5 ;
        RECT  42.768 58.236 42.792 58.32 ;
    END
  END dout[612]
  PIN dout[613]
    DIRECTION OUTPUT ;
    USE SIGNAL ;
    PORT
      LAYER M5 ;
        RECT  42.864 58.236 42.888 58.32 ;
    END
  END dout[613]
  PIN dout[614]
    DIRECTION OUTPUT ;
    USE SIGNAL ;
    PORT
      LAYER M5 ;
        RECT  42.96 58.236 42.984 58.32 ;
    END
  END dout[614]
  PIN dout[615]
    DIRECTION OUTPUT ;
    USE SIGNAL ;
    PORT
      LAYER M5 ;
        RECT  43.056 58.236 43.08 58.32 ;
    END
  END dout[615]
  PIN dout[616]
    DIRECTION OUTPUT ;
    USE SIGNAL ;
    PORT
      LAYER M5 ;
        RECT  43.152 58.236 43.176 58.32 ;
    END
  END dout[616]
  PIN dout[617]
    DIRECTION OUTPUT ;
    USE SIGNAL ;
    PORT
      LAYER M5 ;
        RECT  43.248 58.236 43.272 58.32 ;
    END
  END dout[617]
  PIN dout[618]
    DIRECTION OUTPUT ;
    USE SIGNAL ;
    PORT
      LAYER M5 ;
        RECT  43.344 58.236 43.368 58.32 ;
    END
  END dout[618]
  PIN dout[619]
    DIRECTION OUTPUT ;
    USE SIGNAL ;
    PORT
      LAYER M5 ;
        RECT  43.44 58.236 43.464 58.32 ;
    END
  END dout[619]
  PIN dout[61]
    DIRECTION OUTPUT ;
    USE SIGNAL ;
    PORT
      LAYER M5 ;
        RECT  77.424 58.236 77.448 58.32 ;
    END
  END dout[61]
  PIN dout[620]
    DIRECTION OUTPUT ;
    USE SIGNAL ;
    PORT
      LAYER M5 ;
        RECT  43.536 58.236 43.56 58.32 ;
    END
  END dout[620]
  PIN dout[621]
    DIRECTION OUTPUT ;
    USE SIGNAL ;
    PORT
      LAYER M5 ;
        RECT  43.632 58.236 43.656 58.32 ;
    END
  END dout[621]
  PIN dout[622]
    DIRECTION OUTPUT ;
    USE SIGNAL ;
    PORT
      LAYER M5 ;
        RECT  43.728 58.236 43.752 58.32 ;
    END
  END dout[622]
  PIN dout[623]
    DIRECTION OUTPUT ;
    USE SIGNAL ;
    PORT
      LAYER M5 ;
        RECT  43.824 58.236 43.848 58.32 ;
    END
  END dout[623]
  PIN dout[624]
    DIRECTION OUTPUT ;
    USE SIGNAL ;
    PORT
      LAYER M5 ;
        RECT  43.92 58.236 43.944 58.32 ;
    END
  END dout[624]
  PIN dout[625]
    DIRECTION OUTPUT ;
    USE SIGNAL ;
    PORT
      LAYER M5 ;
        RECT  44.016 58.236 44.04 58.32 ;
    END
  END dout[625]
  PIN dout[626]
    DIRECTION OUTPUT ;
    USE SIGNAL ;
    PORT
      LAYER M5 ;
        RECT  44.112 58.236 44.136 58.32 ;
    END
  END dout[626]
  PIN dout[627]
    DIRECTION OUTPUT ;
    USE SIGNAL ;
    PORT
      LAYER M5 ;
        RECT  44.208 58.236 44.232 58.32 ;
    END
  END dout[627]
  PIN dout[628]
    DIRECTION OUTPUT ;
    USE SIGNAL ;
    PORT
      LAYER M5 ;
        RECT  44.304 58.236 44.328 58.32 ;
    END
  END dout[628]
  PIN dout[629]
    DIRECTION OUTPUT ;
    USE SIGNAL ;
    PORT
      LAYER M5 ;
        RECT  44.4 58.236 44.424 58.32 ;
    END
  END dout[629]
  PIN dout[62]
    DIRECTION OUTPUT ;
    USE SIGNAL ;
    PORT
      LAYER M5 ;
        RECT  77.52 58.236 77.544 58.32 ;
    END
  END dout[62]
  PIN dout[630]
    DIRECTION OUTPUT ;
    USE SIGNAL ;
    PORT
      LAYER M5 ;
        RECT  44.496 58.236 44.52 58.32 ;
    END
  END dout[630]
  PIN dout[631]
    DIRECTION OUTPUT ;
    USE SIGNAL ;
    PORT
      LAYER M5 ;
        RECT  44.592 58.236 44.616 58.32 ;
    END
  END dout[631]
  PIN dout[632]
    DIRECTION OUTPUT ;
    USE SIGNAL ;
    PORT
      LAYER M5 ;
        RECT  44.688 58.236 44.712 58.32 ;
    END
  END dout[632]
  PIN dout[633]
    DIRECTION OUTPUT ;
    USE SIGNAL ;
    PORT
      LAYER M5 ;
        RECT  44.784 58.236 44.808 58.32 ;
    END
  END dout[633]
  PIN dout[634]
    DIRECTION OUTPUT ;
    USE SIGNAL ;
    PORT
      LAYER M5 ;
        RECT  44.88 58.236 44.904 58.32 ;
    END
  END dout[634]
  PIN dout[635]
    DIRECTION OUTPUT ;
    USE SIGNAL ;
    PORT
      LAYER M5 ;
        RECT  44.976 58.236 45 58.32 ;
    END
  END dout[635]
  PIN dout[636]
    DIRECTION OUTPUT ;
    USE SIGNAL ;
    PORT
      LAYER M5 ;
        RECT  45.072 58.236 45.096 58.32 ;
    END
  END dout[636]
  PIN dout[637]
    DIRECTION OUTPUT ;
    USE SIGNAL ;
    PORT
      LAYER M5 ;
        RECT  45.168 58.236 45.192 58.32 ;
    END
  END dout[637]
  PIN dout[638]
    DIRECTION OUTPUT ;
    USE SIGNAL ;
    PORT
      LAYER M5 ;
        RECT  45.264 58.236 45.288 58.32 ;
    END
  END dout[638]
  PIN dout[639]
    DIRECTION OUTPUT ;
    USE SIGNAL ;
    PORT
      LAYER M5 ;
        RECT  45.36 58.236 45.384 58.32 ;
    END
  END dout[639]
  PIN dout[63]
    DIRECTION OUTPUT ;
    USE SIGNAL ;
    PORT
      LAYER M5 ;
        RECT  77.616 58.236 77.64 58.32 ;
    END
  END dout[63]
  PIN dout[640]
    DIRECTION OUTPUT ;
    USE SIGNAL ;
    PORT
      LAYER M5 ;
        RECT  17.04 58.236 17.064 58.32 ;
    END
  END dout[640]
  PIN dout[641]
    DIRECTION OUTPUT ;
    USE SIGNAL ;
    PORT
      LAYER M5 ;
        RECT  17.136 58.236 17.16 58.32 ;
    END
  END dout[641]
  PIN dout[642]
    DIRECTION OUTPUT ;
    USE SIGNAL ;
    PORT
      LAYER M5 ;
        RECT  17.232 58.236 17.256 58.32 ;
    END
  END dout[642]
  PIN dout[643]
    DIRECTION OUTPUT ;
    USE SIGNAL ;
    PORT
      LAYER M5 ;
        RECT  17.328 58.236 17.352 58.32 ;
    END
  END dout[643]
  PIN dout[644]
    DIRECTION OUTPUT ;
    USE SIGNAL ;
    PORT
      LAYER M5 ;
        RECT  17.424 58.236 17.448 58.32 ;
    END
  END dout[644]
  PIN dout[645]
    DIRECTION OUTPUT ;
    USE SIGNAL ;
    PORT
      LAYER M5 ;
        RECT  17.52 58.236 17.544 58.32 ;
    END
  END dout[645]
  PIN dout[646]
    DIRECTION OUTPUT ;
    USE SIGNAL ;
    PORT
      LAYER M5 ;
        RECT  17.616 58.236 17.64 58.32 ;
    END
  END dout[646]
  PIN dout[647]
    DIRECTION OUTPUT ;
    USE SIGNAL ;
    PORT
      LAYER M5 ;
        RECT  17.712 58.236 17.736 58.32 ;
    END
  END dout[647]
  PIN dout[648]
    DIRECTION OUTPUT ;
    USE SIGNAL ;
    PORT
      LAYER M5 ;
        RECT  17.808 58.236 17.832 58.32 ;
    END
  END dout[648]
  PIN dout[649]
    DIRECTION OUTPUT ;
    USE SIGNAL ;
    PORT
      LAYER M5 ;
        RECT  17.904 58.236 17.928 58.32 ;
    END
  END dout[649]
  PIN dout[64]
    DIRECTION OUTPUT ;
    USE SIGNAL ;
    PORT
      LAYER M5 ;
        RECT  7.056 58.236 7.08 58.32 ;
    END
  END dout[64]
  PIN dout[650]
    DIRECTION OUTPUT ;
    USE SIGNAL ;
    PORT
      LAYER M5 ;
        RECT  18 58.236 18.024 58.32 ;
    END
  END dout[650]
  PIN dout[651]
    DIRECTION OUTPUT ;
    USE SIGNAL ;
    PORT
      LAYER M5 ;
        RECT  18.096 58.236 18.12 58.32 ;
    END
  END dout[651]
  PIN dout[652]
    DIRECTION OUTPUT ;
    USE SIGNAL ;
    PORT
      LAYER M5 ;
        RECT  18.192 58.236 18.216 58.32 ;
    END
  END dout[652]
  PIN dout[653]
    DIRECTION OUTPUT ;
    USE SIGNAL ;
    PORT
      LAYER M5 ;
        RECT  18.288 58.236 18.312 58.32 ;
    END
  END dout[653]
  PIN dout[654]
    DIRECTION OUTPUT ;
    USE SIGNAL ;
    PORT
      LAYER M5 ;
        RECT  18.384 58.236 18.408 58.32 ;
    END
  END dout[654]
  PIN dout[655]
    DIRECTION OUTPUT ;
    USE SIGNAL ;
    PORT
      LAYER M5 ;
        RECT  18.48 58.236 18.504 58.32 ;
    END
  END dout[655]
  PIN dout[656]
    DIRECTION OUTPUT ;
    USE SIGNAL ;
    PORT
      LAYER M5 ;
        RECT  18.576 58.236 18.6 58.32 ;
    END
  END dout[656]
  PIN dout[657]
    DIRECTION OUTPUT ;
    USE SIGNAL ;
    PORT
      LAYER M5 ;
        RECT  18.672 58.236 18.696 58.32 ;
    END
  END dout[657]
  PIN dout[658]
    DIRECTION OUTPUT ;
    USE SIGNAL ;
    PORT
      LAYER M5 ;
        RECT  18.768 58.236 18.792 58.32 ;
    END
  END dout[658]
  PIN dout[659]
    DIRECTION OUTPUT ;
    USE SIGNAL ;
    PORT
      LAYER M5 ;
        RECT  18.864 58.236 18.888 58.32 ;
    END
  END dout[659]
  PIN dout[65]
    DIRECTION OUTPUT ;
    USE SIGNAL ;
    PORT
      LAYER M5 ;
        RECT  7.152 58.236 7.176 58.32 ;
    END
  END dout[65]
  PIN dout[660]
    DIRECTION OUTPUT ;
    USE SIGNAL ;
    PORT
      LAYER M5 ;
        RECT  18.96 58.236 18.984 58.32 ;
    END
  END dout[660]
  PIN dout[661]
    DIRECTION OUTPUT ;
    USE SIGNAL ;
    PORT
      LAYER M5 ;
        RECT  19.056 58.236 19.08 58.32 ;
    END
  END dout[661]
  PIN dout[662]
    DIRECTION OUTPUT ;
    USE SIGNAL ;
    PORT
      LAYER M5 ;
        RECT  19.152 58.236 19.176 58.32 ;
    END
  END dout[662]
  PIN dout[663]
    DIRECTION OUTPUT ;
    USE SIGNAL ;
    PORT
      LAYER M5 ;
        RECT  19.248 58.236 19.272 58.32 ;
    END
  END dout[663]
  PIN dout[664]
    DIRECTION OUTPUT ;
    USE SIGNAL ;
    PORT
      LAYER M5 ;
        RECT  19.344 58.236 19.368 58.32 ;
    END
  END dout[664]
  PIN dout[665]
    DIRECTION OUTPUT ;
    USE SIGNAL ;
    PORT
      LAYER M5 ;
        RECT  19.44 58.236 19.464 58.32 ;
    END
  END dout[665]
  PIN dout[666]
    DIRECTION OUTPUT ;
    USE SIGNAL ;
    PORT
      LAYER M5 ;
        RECT  19.536 58.236 19.56 58.32 ;
    END
  END dout[666]
  PIN dout[667]
    DIRECTION OUTPUT ;
    USE SIGNAL ;
    PORT
      LAYER M5 ;
        RECT  19.632 58.236 19.656 58.32 ;
    END
  END dout[667]
  PIN dout[668]
    DIRECTION OUTPUT ;
    USE SIGNAL ;
    PORT
      LAYER M5 ;
        RECT  19.728 58.236 19.752 58.32 ;
    END
  END dout[668]
  PIN dout[669]
    DIRECTION OUTPUT ;
    USE SIGNAL ;
    PORT
      LAYER M5 ;
        RECT  19.824 58.236 19.848 58.32 ;
    END
  END dout[669]
  PIN dout[66]
    DIRECTION OUTPUT ;
    USE SIGNAL ;
    PORT
      LAYER M5 ;
        RECT  7.248 58.236 7.272 58.32 ;
    END
  END dout[66]
  PIN dout[670]
    DIRECTION OUTPUT ;
    USE SIGNAL ;
    PORT
      LAYER M5 ;
        RECT  19.92 58.236 19.944 58.32 ;
    END
  END dout[670]
  PIN dout[671]
    DIRECTION OUTPUT ;
    USE SIGNAL ;
    PORT
      LAYER M5 ;
        RECT  20.016 58.236 20.04 58.32 ;
    END
  END dout[671]
  PIN dout[672]
    DIRECTION OUTPUT ;
    USE SIGNAL ;
    PORT
      LAYER M5 ;
        RECT  23.184 58.236 23.208 58.32 ;
    END
  END dout[672]
  PIN dout[673]
    DIRECTION OUTPUT ;
    USE SIGNAL ;
    PORT
      LAYER M5 ;
        RECT  23.28 58.236 23.304 58.32 ;
    END
  END dout[673]
  PIN dout[674]
    DIRECTION OUTPUT ;
    USE SIGNAL ;
    PORT
      LAYER M5 ;
        RECT  23.376 58.236 23.4 58.32 ;
    END
  END dout[674]
  PIN dout[675]
    DIRECTION OUTPUT ;
    USE SIGNAL ;
    PORT
      LAYER M5 ;
        RECT  23.472 58.236 23.496 58.32 ;
    END
  END dout[675]
  PIN dout[676]
    DIRECTION OUTPUT ;
    USE SIGNAL ;
    PORT
      LAYER M5 ;
        RECT  23.568 58.236 23.592 58.32 ;
    END
  END dout[676]
  PIN dout[677]
    DIRECTION OUTPUT ;
    USE SIGNAL ;
    PORT
      LAYER M5 ;
        RECT  23.664 58.236 23.688 58.32 ;
    END
  END dout[677]
  PIN dout[678]
    DIRECTION OUTPUT ;
    USE SIGNAL ;
    PORT
      LAYER M5 ;
        RECT  23.76 58.236 23.784 58.32 ;
    END
  END dout[678]
  PIN dout[679]
    DIRECTION OUTPUT ;
    USE SIGNAL ;
    PORT
      LAYER M5 ;
        RECT  23.856 58.236 23.88 58.32 ;
    END
  END dout[679]
  PIN dout[67]
    DIRECTION OUTPUT ;
    USE SIGNAL ;
    PORT
      LAYER M5 ;
        RECT  7.344 58.236 7.368 58.32 ;
    END
  END dout[67]
  PIN dout[680]
    DIRECTION OUTPUT ;
    USE SIGNAL ;
    PORT
      LAYER M5 ;
        RECT  23.952 58.236 23.976 58.32 ;
    END
  END dout[680]
  PIN dout[681]
    DIRECTION OUTPUT ;
    USE SIGNAL ;
    PORT
      LAYER M5 ;
        RECT  24.048 58.236 24.072 58.32 ;
    END
  END dout[681]
  PIN dout[682]
    DIRECTION OUTPUT ;
    USE SIGNAL ;
    PORT
      LAYER M5 ;
        RECT  24.144 58.236 24.168 58.32 ;
    END
  END dout[682]
  PIN dout[683]
    DIRECTION OUTPUT ;
    USE SIGNAL ;
    PORT
      LAYER M5 ;
        RECT  24.24 58.236 24.264 58.32 ;
    END
  END dout[683]
  PIN dout[684]
    DIRECTION OUTPUT ;
    USE SIGNAL ;
    PORT
      LAYER M5 ;
        RECT  24.336 58.236 24.36 58.32 ;
    END
  END dout[684]
  PIN dout[685]
    DIRECTION OUTPUT ;
    USE SIGNAL ;
    PORT
      LAYER M5 ;
        RECT  24.432 58.236 24.456 58.32 ;
    END
  END dout[685]
  PIN dout[686]
    DIRECTION OUTPUT ;
    USE SIGNAL ;
    PORT
      LAYER M5 ;
        RECT  24.528 58.236 24.552 58.32 ;
    END
  END dout[686]
  PIN dout[687]
    DIRECTION OUTPUT ;
    USE SIGNAL ;
    PORT
      LAYER M5 ;
        RECT  24.624 58.236 24.648 58.32 ;
    END
  END dout[687]
  PIN dout[688]
    DIRECTION OUTPUT ;
    USE SIGNAL ;
    PORT
      LAYER M5 ;
        RECT  24.72 58.236 24.744 58.32 ;
    END
  END dout[688]
  PIN dout[689]
    DIRECTION OUTPUT ;
    USE SIGNAL ;
    PORT
      LAYER M5 ;
        RECT  24.816 58.236 24.84 58.32 ;
    END
  END dout[689]
  PIN dout[68]
    DIRECTION OUTPUT ;
    USE SIGNAL ;
    PORT
      LAYER M5 ;
        RECT  7.44 58.236 7.464 58.32 ;
    END
  END dout[68]
  PIN dout[690]
    DIRECTION OUTPUT ;
    USE SIGNAL ;
    PORT
      LAYER M5 ;
        RECT  24.912 58.236 24.936 58.32 ;
    END
  END dout[690]
  PIN dout[691]
    DIRECTION OUTPUT ;
    USE SIGNAL ;
    PORT
      LAYER M5 ;
        RECT  25.008 58.236 25.032 58.32 ;
    END
  END dout[691]
  PIN dout[692]
    DIRECTION OUTPUT ;
    USE SIGNAL ;
    PORT
      LAYER M5 ;
        RECT  25.104 58.236 25.128 58.32 ;
    END
  END dout[692]
  PIN dout[693]
    DIRECTION OUTPUT ;
    USE SIGNAL ;
    PORT
      LAYER M5 ;
        RECT  25.2 58.236 25.224 58.32 ;
    END
  END dout[693]
  PIN dout[694]
    DIRECTION OUTPUT ;
    USE SIGNAL ;
    PORT
      LAYER M5 ;
        RECT  25.296 58.236 25.32 58.32 ;
    END
  END dout[694]
  PIN dout[695]
    DIRECTION OUTPUT ;
    USE SIGNAL ;
    PORT
      LAYER M5 ;
        RECT  25.392 58.236 25.416 58.32 ;
    END
  END dout[695]
  PIN dout[696]
    DIRECTION OUTPUT ;
    USE SIGNAL ;
    PORT
      LAYER M5 ;
        RECT  25.488 58.236 25.512 58.32 ;
    END
  END dout[696]
  PIN dout[697]
    DIRECTION OUTPUT ;
    USE SIGNAL ;
    PORT
      LAYER M5 ;
        RECT  25.584 58.236 25.608 58.32 ;
    END
  END dout[697]
  PIN dout[698]
    DIRECTION OUTPUT ;
    USE SIGNAL ;
    PORT
      LAYER M5 ;
        RECT  25.68 58.236 25.704 58.32 ;
    END
  END dout[698]
  PIN dout[699]
    DIRECTION OUTPUT ;
    USE SIGNAL ;
    PORT
      LAYER M5 ;
        RECT  25.776 58.236 25.8 58.32 ;
    END
  END dout[699]
  PIN dout[69]
    DIRECTION OUTPUT ;
    USE SIGNAL ;
    PORT
      LAYER M5 ;
        RECT  7.536 58.236 7.56 58.32 ;
    END
  END dout[69]
  PIN dout[6]
    DIRECTION OUTPUT ;
    USE SIGNAL ;
    PORT
      LAYER M5 ;
        RECT  84.432 58.236 84.456 58.32 ;
    END
  END dout[6]
  PIN dout[700]
    DIRECTION OUTPUT ;
    USE SIGNAL ;
    PORT
      LAYER M5 ;
        RECT  25.872 58.236 25.896 58.32 ;
    END
  END dout[700]
  PIN dout[701]
    DIRECTION OUTPUT ;
    USE SIGNAL ;
    PORT
      LAYER M5 ;
        RECT  25.968 58.236 25.992 58.32 ;
    END
  END dout[701]
  PIN dout[702]
    DIRECTION OUTPUT ;
    USE SIGNAL ;
    PORT
      LAYER M5 ;
        RECT  26.064 58.236 26.088 58.32 ;
    END
  END dout[702]
  PIN dout[703]
    DIRECTION OUTPUT ;
    USE SIGNAL ;
    PORT
      LAYER M5 ;
        RECT  26.16 58.236 26.184 58.32 ;
    END
  END dout[703]
  PIN dout[704]
    DIRECTION OUTPUT ;
    USE SIGNAL ;
    PORT
      LAYER M5 ;
        RECT  33.168 58.236 33.192 58.32 ;
    END
  END dout[704]
  PIN dout[705]
    DIRECTION OUTPUT ;
    USE SIGNAL ;
    PORT
      LAYER M5 ;
        RECT  33.264 58.236 33.288 58.32 ;
    END
  END dout[705]
  PIN dout[706]
    DIRECTION OUTPUT ;
    USE SIGNAL ;
    PORT
      LAYER M5 ;
        RECT  33.36 58.236 33.384 58.32 ;
    END
  END dout[706]
  PIN dout[707]
    DIRECTION OUTPUT ;
    USE SIGNAL ;
    PORT
      LAYER M5 ;
        RECT  33.456 58.236 33.48 58.32 ;
    END
  END dout[707]
  PIN dout[708]
    DIRECTION OUTPUT ;
    USE SIGNAL ;
    PORT
      LAYER M5 ;
        RECT  33.552 58.236 33.576 58.32 ;
    END
  END dout[708]
  PIN dout[709]
    DIRECTION OUTPUT ;
    USE SIGNAL ;
    PORT
      LAYER M5 ;
        RECT  33.648 58.236 33.672 58.32 ;
    END
  END dout[709]
  PIN dout[70]
    DIRECTION OUTPUT ;
    USE SIGNAL ;
    PORT
      LAYER M5 ;
        RECT  7.632 58.236 7.656 58.32 ;
    END
  END dout[70]
  PIN dout[710]
    DIRECTION OUTPUT ;
    USE SIGNAL ;
    PORT
      LAYER M5 ;
        RECT  33.744 58.236 33.768 58.32 ;
    END
  END dout[710]
  PIN dout[711]
    DIRECTION OUTPUT ;
    USE SIGNAL ;
    PORT
      LAYER M5 ;
        RECT  33.84 58.236 33.864 58.32 ;
    END
  END dout[711]
  PIN dout[712]
    DIRECTION OUTPUT ;
    USE SIGNAL ;
    PORT
      LAYER M5 ;
        RECT  33.936 58.236 33.96 58.32 ;
    END
  END dout[712]
  PIN dout[713]
    DIRECTION OUTPUT ;
    USE SIGNAL ;
    PORT
      LAYER M5 ;
        RECT  34.032 58.236 34.056 58.32 ;
    END
  END dout[713]
  PIN dout[714]
    DIRECTION OUTPUT ;
    USE SIGNAL ;
    PORT
      LAYER M5 ;
        RECT  34.128 58.236 34.152 58.32 ;
    END
  END dout[714]
  PIN dout[715]
    DIRECTION OUTPUT ;
    USE SIGNAL ;
    PORT
      LAYER M5 ;
        RECT  34.224 58.236 34.248 58.32 ;
    END
  END dout[715]
  PIN dout[716]
    DIRECTION OUTPUT ;
    USE SIGNAL ;
    PORT
      LAYER M5 ;
        RECT  34.32 58.236 34.344 58.32 ;
    END
  END dout[716]
  PIN dout[717]
    DIRECTION OUTPUT ;
    USE SIGNAL ;
    PORT
      LAYER M5 ;
        RECT  34.416 58.236 34.44 58.32 ;
    END
  END dout[717]
  PIN dout[718]
    DIRECTION OUTPUT ;
    USE SIGNAL ;
    PORT
      LAYER M5 ;
        RECT  34.512 58.236 34.536 58.32 ;
    END
  END dout[718]
  PIN dout[719]
    DIRECTION OUTPUT ;
    USE SIGNAL ;
    PORT
      LAYER M5 ;
        RECT  34.608 58.236 34.632 58.32 ;
    END
  END dout[719]
  PIN dout[71]
    DIRECTION OUTPUT ;
    USE SIGNAL ;
    PORT
      LAYER M5 ;
        RECT  7.728 58.236 7.752 58.32 ;
    END
  END dout[71]
  PIN dout[720]
    DIRECTION OUTPUT ;
    USE SIGNAL ;
    PORT
      LAYER M5 ;
        RECT  34.704 58.236 34.728 58.32 ;
    END
  END dout[720]
  PIN dout[721]
    DIRECTION OUTPUT ;
    USE SIGNAL ;
    PORT
      LAYER M5 ;
        RECT  34.8 58.236 34.824 58.32 ;
    END
  END dout[721]
  PIN dout[722]
    DIRECTION OUTPUT ;
    USE SIGNAL ;
    PORT
      LAYER M5 ;
        RECT  34.896 58.236 34.92 58.32 ;
    END
  END dout[722]
  PIN dout[723]
    DIRECTION OUTPUT ;
    USE SIGNAL ;
    PORT
      LAYER M5 ;
        RECT  34.992 58.236 35.016 58.32 ;
    END
  END dout[723]
  PIN dout[724]
    DIRECTION OUTPUT ;
    USE SIGNAL ;
    PORT
      LAYER M5 ;
        RECT  35.088 58.236 35.112 58.32 ;
    END
  END dout[724]
  PIN dout[725]
    DIRECTION OUTPUT ;
    USE SIGNAL ;
    PORT
      LAYER M5 ;
        RECT  35.184 58.236 35.208 58.32 ;
    END
  END dout[725]
  PIN dout[726]
    DIRECTION OUTPUT ;
    USE SIGNAL ;
    PORT
      LAYER M5 ;
        RECT  35.28 58.236 35.304 58.32 ;
    END
  END dout[726]
  PIN dout[727]
    DIRECTION OUTPUT ;
    USE SIGNAL ;
    PORT
      LAYER M5 ;
        RECT  35.376 58.236 35.4 58.32 ;
    END
  END dout[727]
  PIN dout[728]
    DIRECTION OUTPUT ;
    USE SIGNAL ;
    PORT
      LAYER M5 ;
        RECT  35.472 58.236 35.496 58.32 ;
    END
  END dout[728]
  PIN dout[729]
    DIRECTION OUTPUT ;
    USE SIGNAL ;
    PORT
      LAYER M5 ;
        RECT  35.568 58.236 35.592 58.32 ;
    END
  END dout[729]
  PIN dout[72]
    DIRECTION OUTPUT ;
    USE SIGNAL ;
    PORT
      LAYER M5 ;
        RECT  7.824 58.236 7.848 58.32 ;
    END
  END dout[72]
  PIN dout[730]
    DIRECTION OUTPUT ;
    USE SIGNAL ;
    PORT
      LAYER M5 ;
        RECT  35.664 58.236 35.688 58.32 ;
    END
  END dout[730]
  PIN dout[731]
    DIRECTION OUTPUT ;
    USE SIGNAL ;
    PORT
      LAYER M5 ;
        RECT  35.76 58.236 35.784 58.32 ;
    END
  END dout[731]
  PIN dout[732]
    DIRECTION OUTPUT ;
    USE SIGNAL ;
    PORT
      LAYER M5 ;
        RECT  35.856 58.236 35.88 58.32 ;
    END
  END dout[732]
  PIN dout[733]
    DIRECTION OUTPUT ;
    USE SIGNAL ;
    PORT
      LAYER M5 ;
        RECT  35.952 58.236 35.976 58.32 ;
    END
  END dout[733]
  PIN dout[734]
    DIRECTION OUTPUT ;
    USE SIGNAL ;
    PORT
      LAYER M5 ;
        RECT  36.048 58.236 36.072 58.32 ;
    END
  END dout[734]
  PIN dout[735]
    DIRECTION OUTPUT ;
    USE SIGNAL ;
    PORT
      LAYER M5 ;
        RECT  36.144 58.236 36.168 58.32 ;
    END
  END dout[735]
  PIN dout[736]
    DIRECTION OUTPUT ;
    USE SIGNAL ;
    PORT
      LAYER M5 ;
        RECT  45.456 58.236 45.48 58.32 ;
    END
  END dout[736]
  PIN dout[737]
    DIRECTION OUTPUT ;
    USE SIGNAL ;
    PORT
      LAYER M5 ;
        RECT  45.552 58.236 45.576 58.32 ;
    END
  END dout[737]
  PIN dout[738]
    DIRECTION OUTPUT ;
    USE SIGNAL ;
    PORT
      LAYER M5 ;
        RECT  45.648 58.236 45.672 58.32 ;
    END
  END dout[738]
  PIN dout[739]
    DIRECTION OUTPUT ;
    USE SIGNAL ;
    PORT
      LAYER M5 ;
        RECT  45.744 58.236 45.768 58.32 ;
    END
  END dout[739]
  PIN dout[73]
    DIRECTION OUTPUT ;
    USE SIGNAL ;
    PORT
      LAYER M5 ;
        RECT  7.92 58.236 7.944 58.32 ;
    END
  END dout[73]
  PIN dout[740]
    DIRECTION OUTPUT ;
    USE SIGNAL ;
    PORT
      LAYER M5 ;
        RECT  45.84 58.236 45.864 58.32 ;
    END
  END dout[740]
  PIN dout[741]
    DIRECTION OUTPUT ;
    USE SIGNAL ;
    PORT
      LAYER M5 ;
        RECT  45.936 58.236 45.96 58.32 ;
    END
  END dout[741]
  PIN dout[742]
    DIRECTION OUTPUT ;
    USE SIGNAL ;
    PORT
      LAYER M5 ;
        RECT  46.032 58.236 46.056 58.32 ;
    END
  END dout[742]
  PIN dout[743]
    DIRECTION OUTPUT ;
    USE SIGNAL ;
    PORT
      LAYER M5 ;
        RECT  46.128 58.236 46.152 58.32 ;
    END
  END dout[743]
  PIN dout[744]
    DIRECTION OUTPUT ;
    USE SIGNAL ;
    PORT
      LAYER M5 ;
        RECT  46.224 58.236 46.248 58.32 ;
    END
  END dout[744]
  PIN dout[745]
    DIRECTION OUTPUT ;
    USE SIGNAL ;
    PORT
      LAYER M5 ;
        RECT  46.32 58.236 46.344 58.32 ;
    END
  END dout[745]
  PIN dout[746]
    DIRECTION OUTPUT ;
    USE SIGNAL ;
    PORT
      LAYER M5 ;
        RECT  46.416 58.236 46.44 58.32 ;
    END
  END dout[746]
  PIN dout[747]
    DIRECTION OUTPUT ;
    USE SIGNAL ;
    PORT
      LAYER M5 ;
        RECT  46.512 58.236 46.536 58.32 ;
    END
  END dout[747]
  PIN dout[748]
    DIRECTION OUTPUT ;
    USE SIGNAL ;
    PORT
      LAYER M5 ;
        RECT  46.608 58.236 46.632 58.32 ;
    END
  END dout[748]
  PIN dout[749]
    DIRECTION OUTPUT ;
    USE SIGNAL ;
    PORT
      LAYER M5 ;
        RECT  46.704 58.236 46.728 58.32 ;
    END
  END dout[749]
  PIN dout[74]
    DIRECTION OUTPUT ;
    USE SIGNAL ;
    PORT
      LAYER M5 ;
        RECT  8.016 58.236 8.04 58.32 ;
    END
  END dout[74]
  PIN dout[750]
    DIRECTION OUTPUT ;
    USE SIGNAL ;
    PORT
      LAYER M5 ;
        RECT  46.8 58.236 46.824 58.32 ;
    END
  END dout[750]
  PIN dout[751]
    DIRECTION OUTPUT ;
    USE SIGNAL ;
    PORT
      LAYER M5 ;
        RECT  46.896 58.236 46.92 58.32 ;
    END
  END dout[751]
  PIN dout[752]
    DIRECTION OUTPUT ;
    USE SIGNAL ;
    PORT
      LAYER M5 ;
        RECT  46.992 58.236 47.016 58.32 ;
    END
  END dout[752]
  PIN dout[753]
    DIRECTION OUTPUT ;
    USE SIGNAL ;
    PORT
      LAYER M5 ;
        RECT  47.088 58.236 47.112 58.32 ;
    END
  END dout[753]
  PIN dout[754]
    DIRECTION OUTPUT ;
    USE SIGNAL ;
    PORT
      LAYER M5 ;
        RECT  47.184 58.236 47.208 58.32 ;
    END
  END dout[754]
  PIN dout[755]
    DIRECTION OUTPUT ;
    USE SIGNAL ;
    PORT
      LAYER M5 ;
        RECT  47.28 58.236 47.304 58.32 ;
    END
  END dout[755]
  PIN dout[756]
    DIRECTION OUTPUT ;
    USE SIGNAL ;
    PORT
      LAYER M5 ;
        RECT  47.376 58.236 47.4 58.32 ;
    END
  END dout[756]
  PIN dout[757]
    DIRECTION OUTPUT ;
    USE SIGNAL ;
    PORT
      LAYER M5 ;
        RECT  47.472 58.236 47.496 58.32 ;
    END
  END dout[757]
  PIN dout[758]
    DIRECTION OUTPUT ;
    USE SIGNAL ;
    PORT
      LAYER M5 ;
        RECT  47.568 58.236 47.592 58.32 ;
    END
  END dout[758]
  PIN dout[759]
    DIRECTION OUTPUT ;
    USE SIGNAL ;
    PORT
      LAYER M5 ;
        RECT  47.664 58.236 47.688 58.32 ;
    END
  END dout[759]
  PIN dout[75]
    DIRECTION OUTPUT ;
    USE SIGNAL ;
    PORT
      LAYER M5 ;
        RECT  8.112 58.236 8.136 58.32 ;
    END
  END dout[75]
  PIN dout[760]
    DIRECTION OUTPUT ;
    USE SIGNAL ;
    PORT
      LAYER M5 ;
        RECT  47.76 58.236 47.784 58.32 ;
    END
  END dout[760]
  PIN dout[761]
    DIRECTION OUTPUT ;
    USE SIGNAL ;
    PORT
      LAYER M5 ;
        RECT  47.856 58.236 47.88 58.32 ;
    END
  END dout[761]
  PIN dout[762]
    DIRECTION OUTPUT ;
    USE SIGNAL ;
    PORT
      LAYER M5 ;
        RECT  47.952 58.236 47.976 58.32 ;
    END
  END dout[762]
  PIN dout[763]
    DIRECTION OUTPUT ;
    USE SIGNAL ;
    PORT
      LAYER M5 ;
        RECT  48.048 58.236 48.072 58.32 ;
    END
  END dout[763]
  PIN dout[764]
    DIRECTION OUTPUT ;
    USE SIGNAL ;
    PORT
      LAYER M5 ;
        RECT  48.144 58.236 48.168 58.32 ;
    END
  END dout[764]
  PIN dout[765]
    DIRECTION OUTPUT ;
    USE SIGNAL ;
    PORT
      LAYER M5 ;
        RECT  48.24 58.236 48.264 58.32 ;
    END
  END dout[765]
  PIN dout[766]
    DIRECTION OUTPUT ;
    USE SIGNAL ;
    PORT
      LAYER M5 ;
        RECT  48.336 58.236 48.36 58.32 ;
    END
  END dout[766]
  PIN dout[767]
    DIRECTION OUTPUT ;
    USE SIGNAL ;
    PORT
      LAYER M5 ;
        RECT  48.432 58.236 48.456 58.32 ;
    END
  END dout[767]
  PIN dout[768]
    DIRECTION OUTPUT ;
    USE SIGNAL ;
    PORT
      LAYER M5 ;
        RECT  67.728 58.236 67.752 58.32 ;
    END
  END dout[768]
  PIN dout[769]
    DIRECTION OUTPUT ;
    USE SIGNAL ;
    PORT
      LAYER M5 ;
        RECT  67.824 58.236 67.848 58.32 ;
    END
  END dout[769]
  PIN dout[76]
    DIRECTION OUTPUT ;
    USE SIGNAL ;
    PORT
      LAYER M5 ;
        RECT  8.208 58.236 8.232 58.32 ;
    END
  END dout[76]
  PIN dout[770]
    DIRECTION OUTPUT ;
    USE SIGNAL ;
    PORT
      LAYER M5 ;
        RECT  67.92 58.236 67.944 58.32 ;
    END
  END dout[770]
  PIN dout[771]
    DIRECTION OUTPUT ;
    USE SIGNAL ;
    PORT
      LAYER M5 ;
        RECT  68.016 58.236 68.04 58.32 ;
    END
  END dout[771]
  PIN dout[772]
    DIRECTION OUTPUT ;
    USE SIGNAL ;
    PORT
      LAYER M5 ;
        RECT  68.112 58.236 68.136 58.32 ;
    END
  END dout[772]
  PIN dout[773]
    DIRECTION OUTPUT ;
    USE SIGNAL ;
    PORT
      LAYER M5 ;
        RECT  68.208 58.236 68.232 58.32 ;
    END
  END dout[773]
  PIN dout[774]
    DIRECTION OUTPUT ;
    USE SIGNAL ;
    PORT
      LAYER M5 ;
        RECT  68.304 58.236 68.328 58.32 ;
    END
  END dout[774]
  PIN dout[775]
    DIRECTION OUTPUT ;
    USE SIGNAL ;
    PORT
      LAYER M5 ;
        RECT  68.4 58.236 68.424 58.32 ;
    END
  END dout[775]
  PIN dout[776]
    DIRECTION OUTPUT ;
    USE SIGNAL ;
    PORT
      LAYER M5 ;
        RECT  68.496 58.236 68.52 58.32 ;
    END
  END dout[776]
  PIN dout[777]
    DIRECTION OUTPUT ;
    USE SIGNAL ;
    PORT
      LAYER M5 ;
        RECT  68.592 58.236 68.616 58.32 ;
    END
  END dout[777]
  PIN dout[778]
    DIRECTION OUTPUT ;
    USE SIGNAL ;
    PORT
      LAYER M5 ;
        RECT  68.688 58.236 68.712 58.32 ;
    END
  END dout[778]
  PIN dout[779]
    DIRECTION OUTPUT ;
    USE SIGNAL ;
    PORT
      LAYER M5 ;
        RECT  68.784 58.236 68.808 58.32 ;
    END
  END dout[779]
  PIN dout[77]
    DIRECTION OUTPUT ;
    USE SIGNAL ;
    PORT
      LAYER M5 ;
        RECT  8.304 58.236 8.328 58.32 ;
    END
  END dout[77]
  PIN dout[780]
    DIRECTION OUTPUT ;
    USE SIGNAL ;
    PORT
      LAYER M5 ;
        RECT  68.88 58.236 68.904 58.32 ;
    END
  END dout[780]
  PIN dout[781]
    DIRECTION OUTPUT ;
    USE SIGNAL ;
    PORT
      LAYER M5 ;
        RECT  68.976 58.236 69 58.32 ;
    END
  END dout[781]
  PIN dout[782]
    DIRECTION OUTPUT ;
    USE SIGNAL ;
    PORT
      LAYER M5 ;
        RECT  69.072 58.236 69.096 58.32 ;
    END
  END dout[782]
  PIN dout[783]
    DIRECTION OUTPUT ;
    USE SIGNAL ;
    PORT
      LAYER M5 ;
        RECT  69.168 58.236 69.192 58.32 ;
    END
  END dout[783]
  PIN dout[784]
    DIRECTION OUTPUT ;
    USE SIGNAL ;
    PORT
      LAYER M5 ;
        RECT  69.264 58.236 69.288 58.32 ;
    END
  END dout[784]
  PIN dout[785]
    DIRECTION OUTPUT ;
    USE SIGNAL ;
    PORT
      LAYER M5 ;
        RECT  69.36 58.236 69.384 58.32 ;
    END
  END dout[785]
  PIN dout[786]
    DIRECTION OUTPUT ;
    USE SIGNAL ;
    PORT
      LAYER M5 ;
        RECT  69.456 58.236 69.48 58.32 ;
    END
  END dout[786]
  PIN dout[787]
    DIRECTION OUTPUT ;
    USE SIGNAL ;
    PORT
      LAYER M5 ;
        RECT  69.552 58.236 69.576 58.32 ;
    END
  END dout[787]
  PIN dout[788]
    DIRECTION OUTPUT ;
    USE SIGNAL ;
    PORT
      LAYER M5 ;
        RECT  69.648 58.236 69.672 58.32 ;
    END
  END dout[788]
  PIN dout[789]
    DIRECTION OUTPUT ;
    USE SIGNAL ;
    PORT
      LAYER M5 ;
        RECT  69.744 58.236 69.768 58.32 ;
    END
  END dout[789]
  PIN dout[78]
    DIRECTION OUTPUT ;
    USE SIGNAL ;
    PORT
      LAYER M5 ;
        RECT  8.4 58.236 8.424 58.32 ;
    END
  END dout[78]
  PIN dout[790]
    DIRECTION OUTPUT ;
    USE SIGNAL ;
    PORT
      LAYER M5 ;
        RECT  69.84 58.236 69.864 58.32 ;
    END
  END dout[790]
  PIN dout[791]
    DIRECTION OUTPUT ;
    USE SIGNAL ;
    PORT
      LAYER M5 ;
        RECT  69.936 58.236 69.96 58.32 ;
    END
  END dout[791]
  PIN dout[792]
    DIRECTION OUTPUT ;
    USE SIGNAL ;
    PORT
      LAYER M5 ;
        RECT  70.032 58.236 70.056 58.32 ;
    END
  END dout[792]
  PIN dout[793]
    DIRECTION OUTPUT ;
    USE SIGNAL ;
    PORT
      LAYER M5 ;
        RECT  70.128 58.236 70.152 58.32 ;
    END
  END dout[793]
  PIN dout[794]
    DIRECTION OUTPUT ;
    USE SIGNAL ;
    PORT
      LAYER M5 ;
        RECT  70.224 58.236 70.248 58.32 ;
    END
  END dout[794]
  PIN dout[795]
    DIRECTION OUTPUT ;
    USE SIGNAL ;
    PORT
      LAYER M5 ;
        RECT  70.32 58.236 70.344 58.32 ;
    END
  END dout[795]
  PIN dout[796]
    DIRECTION OUTPUT ;
    USE SIGNAL ;
    PORT
      LAYER M5 ;
        RECT  70.416 58.236 70.44 58.32 ;
    END
  END dout[796]
  PIN dout[797]
    DIRECTION OUTPUT ;
    USE SIGNAL ;
    PORT
      LAYER M5 ;
        RECT  70.512 58.236 70.536 58.32 ;
    END
  END dout[797]
  PIN dout[798]
    DIRECTION OUTPUT ;
    USE SIGNAL ;
    PORT
      LAYER M5 ;
        RECT  70.608 58.236 70.632 58.32 ;
    END
  END dout[798]
  PIN dout[799]
    DIRECTION OUTPUT ;
    USE SIGNAL ;
    PORT
      LAYER M5 ;
        RECT  70.704 58.236 70.728 58.32 ;
    END
  END dout[799]
  PIN dout[79]
    DIRECTION OUTPUT ;
    USE SIGNAL ;
    PORT
      LAYER M5 ;
        RECT  8.496 58.236 8.52 58.32 ;
    END
  END dout[79]
  PIN dout[7]
    DIRECTION OUTPUT ;
    USE SIGNAL ;
    PORT
      LAYER M5 ;
        RECT  84.528 58.236 84.552 58.32 ;
    END
  END dout[7]
  PIN dout[800]
    DIRECTION OUTPUT ;
    USE SIGNAL ;
    PORT
      LAYER M5 ;
        RECT  48.528 58.236 48.552 58.32 ;
    END
  END dout[800]
  PIN dout[801]
    DIRECTION OUTPUT ;
    USE SIGNAL ;
    PORT
      LAYER M5 ;
        RECT  48.624 58.236 48.648 58.32 ;
    END
  END dout[801]
  PIN dout[802]
    DIRECTION OUTPUT ;
    USE SIGNAL ;
    PORT
      LAYER M5 ;
        RECT  48.72 58.236 48.744 58.32 ;
    END
  END dout[802]
  PIN dout[803]
    DIRECTION OUTPUT ;
    USE SIGNAL ;
    PORT
      LAYER M5 ;
        RECT  48.816 58.236 48.84 58.32 ;
    END
  END dout[803]
  PIN dout[804]
    DIRECTION OUTPUT ;
    USE SIGNAL ;
    PORT
      LAYER M5 ;
        RECT  48.912 58.236 48.936 58.32 ;
    END
  END dout[804]
  PIN dout[805]
    DIRECTION OUTPUT ;
    USE SIGNAL ;
    PORT
      LAYER M5 ;
        RECT  49.008 58.236 49.032 58.32 ;
    END
  END dout[805]
  PIN dout[806]
    DIRECTION OUTPUT ;
    USE SIGNAL ;
    PORT
      LAYER M5 ;
        RECT  49.104 58.236 49.128 58.32 ;
    END
  END dout[806]
  PIN dout[807]
    DIRECTION OUTPUT ;
    USE SIGNAL ;
    PORT
      LAYER M5 ;
        RECT  49.2 58.236 49.224 58.32 ;
    END
  END dout[807]
  PIN dout[808]
    DIRECTION OUTPUT ;
    USE SIGNAL ;
    PORT
      LAYER M5 ;
        RECT  49.296 58.236 49.32 58.32 ;
    END
  END dout[808]
  PIN dout[809]
    DIRECTION OUTPUT ;
    USE SIGNAL ;
    PORT
      LAYER M5 ;
        RECT  49.392 58.236 49.416 58.32 ;
    END
  END dout[809]
  PIN dout[80]
    DIRECTION OUTPUT ;
    USE SIGNAL ;
    PORT
      LAYER M5 ;
        RECT  8.592 58.236 8.616 58.32 ;
    END
  END dout[80]
  PIN dout[810]
    DIRECTION OUTPUT ;
    USE SIGNAL ;
    PORT
      LAYER M5 ;
        RECT  49.488 58.236 49.512 58.32 ;
    END
  END dout[810]
  PIN dout[811]
    DIRECTION OUTPUT ;
    USE SIGNAL ;
    PORT
      LAYER M5 ;
        RECT  49.584 58.236 49.608 58.32 ;
    END
  END dout[811]
  PIN dout[812]
    DIRECTION OUTPUT ;
    USE SIGNAL ;
    PORT
      LAYER M5 ;
        RECT  49.68 58.236 49.704 58.32 ;
    END
  END dout[812]
  PIN dout[813]
    DIRECTION OUTPUT ;
    USE SIGNAL ;
    PORT
      LAYER M5 ;
        RECT  49.776 58.236 49.8 58.32 ;
    END
  END dout[813]
  PIN dout[814]
    DIRECTION OUTPUT ;
    USE SIGNAL ;
    PORT
      LAYER M5 ;
        RECT  49.872 58.236 49.896 58.32 ;
    END
  END dout[814]
  PIN dout[815]
    DIRECTION OUTPUT ;
    USE SIGNAL ;
    PORT
      LAYER M5 ;
        RECT  49.968 58.236 49.992 58.32 ;
    END
  END dout[815]
  PIN dout[816]
    DIRECTION OUTPUT ;
    USE SIGNAL ;
    PORT
      LAYER M5 ;
        RECT  50.064 58.236 50.088 58.32 ;
    END
  END dout[816]
  PIN dout[817]
    DIRECTION OUTPUT ;
    USE SIGNAL ;
    PORT
      LAYER M5 ;
        RECT  50.16 58.236 50.184 58.32 ;
    END
  END dout[817]
  PIN dout[818]
    DIRECTION OUTPUT ;
    USE SIGNAL ;
    PORT
      LAYER M5 ;
        RECT  50.256 58.236 50.28 58.32 ;
    END
  END dout[818]
  PIN dout[819]
    DIRECTION OUTPUT ;
    USE SIGNAL ;
    PORT
      LAYER M5 ;
        RECT  50.352 58.236 50.376 58.32 ;
    END
  END dout[819]
  PIN dout[81]
    DIRECTION OUTPUT ;
    USE SIGNAL ;
    PORT
      LAYER M5 ;
        RECT  8.688 58.236 8.712 58.32 ;
    END
  END dout[81]
  PIN dout[820]
    DIRECTION OUTPUT ;
    USE SIGNAL ;
    PORT
      LAYER M5 ;
        RECT  50.448 58.236 50.472 58.32 ;
    END
  END dout[820]
  PIN dout[821]
    DIRECTION OUTPUT ;
    USE SIGNAL ;
    PORT
      LAYER M5 ;
        RECT  50.544 58.236 50.568 58.32 ;
    END
  END dout[821]
  PIN dout[822]
    DIRECTION OUTPUT ;
    USE SIGNAL ;
    PORT
      LAYER M5 ;
        RECT  50.64 58.236 50.664 58.32 ;
    END
  END dout[822]
  PIN dout[823]
    DIRECTION OUTPUT ;
    USE SIGNAL ;
    PORT
      LAYER M5 ;
        RECT  50.736 58.236 50.76 58.32 ;
    END
  END dout[823]
  PIN dout[824]
    DIRECTION OUTPUT ;
    USE SIGNAL ;
    PORT
      LAYER M5 ;
        RECT  50.832 58.236 50.856 58.32 ;
    END
  END dout[824]
  PIN dout[825]
    DIRECTION OUTPUT ;
    USE SIGNAL ;
    PORT
      LAYER M5 ;
        RECT  50.928 58.236 50.952 58.32 ;
    END
  END dout[825]
  PIN dout[826]
    DIRECTION OUTPUT ;
    USE SIGNAL ;
    PORT
      LAYER M5 ;
        RECT  51.024 58.236 51.048 58.32 ;
    END
  END dout[826]
  PIN dout[827]
    DIRECTION OUTPUT ;
    USE SIGNAL ;
    PORT
      LAYER M5 ;
        RECT  51.12 58.236 51.144 58.32 ;
    END
  END dout[827]
  PIN dout[828]
    DIRECTION OUTPUT ;
    USE SIGNAL ;
    PORT
      LAYER M5 ;
        RECT  51.216 58.236 51.24 58.32 ;
    END
  END dout[828]
  PIN dout[829]
    DIRECTION OUTPUT ;
    USE SIGNAL ;
    PORT
      LAYER M5 ;
        RECT  51.312 58.236 51.336 58.32 ;
    END
  END dout[829]
  PIN dout[82]
    DIRECTION OUTPUT ;
    USE SIGNAL ;
    PORT
      LAYER M5 ;
        RECT  8.784 58.236 8.808 58.32 ;
    END
  END dout[82]
  PIN dout[830]
    DIRECTION OUTPUT ;
    USE SIGNAL ;
    PORT
      LAYER M5 ;
        RECT  51.408 58.236 51.432 58.32 ;
    END
  END dout[830]
  PIN dout[831]
    DIRECTION OUTPUT ;
    USE SIGNAL ;
    PORT
      LAYER M5 ;
        RECT  51.504 58.236 51.528 58.32 ;
    END
  END dout[831]
  PIN dout[832]
    DIRECTION OUTPUT ;
    USE SIGNAL ;
    PORT
      LAYER M5 ;
        RECT  70.8 58.236 70.824 58.32 ;
    END
  END dout[832]
  PIN dout[833]
    DIRECTION OUTPUT ;
    USE SIGNAL ;
    PORT
      LAYER M5 ;
        RECT  70.896 58.236 70.92 58.32 ;
    END
  END dout[833]
  PIN dout[834]
    DIRECTION OUTPUT ;
    USE SIGNAL ;
    PORT
      LAYER M5 ;
        RECT  70.992 58.236 71.016 58.32 ;
    END
  END dout[834]
  PIN dout[835]
    DIRECTION OUTPUT ;
    USE SIGNAL ;
    PORT
      LAYER M5 ;
        RECT  71.088 58.236 71.112 58.32 ;
    END
  END dout[835]
  PIN dout[836]
    DIRECTION OUTPUT ;
    USE SIGNAL ;
    PORT
      LAYER M5 ;
        RECT  71.184 58.236 71.208 58.32 ;
    END
  END dout[836]
  PIN dout[837]
    DIRECTION OUTPUT ;
    USE SIGNAL ;
    PORT
      LAYER M5 ;
        RECT  71.28 58.236 71.304 58.32 ;
    END
  END dout[837]
  PIN dout[838]
    DIRECTION OUTPUT ;
    USE SIGNAL ;
    PORT
      LAYER M5 ;
        RECT  71.376 58.236 71.4 58.32 ;
    END
  END dout[838]
  PIN dout[839]
    DIRECTION OUTPUT ;
    USE SIGNAL ;
    PORT
      LAYER M5 ;
        RECT  71.472 58.236 71.496 58.32 ;
    END
  END dout[839]
  PIN dout[83]
    DIRECTION OUTPUT ;
    USE SIGNAL ;
    PORT
      LAYER M5 ;
        RECT  8.88 58.236 8.904 58.32 ;
    END
  END dout[83]
  PIN dout[84]
    DIRECTION OUTPUT ;
    USE SIGNAL ;
    PORT
      LAYER M5 ;
        RECT  8.976 58.236 9 58.32 ;
    END
  END dout[84]
  PIN dout[85]
    DIRECTION OUTPUT ;
    USE SIGNAL ;
    PORT
      LAYER M5 ;
        RECT  9.072 58.236 9.096 58.32 ;
    END
  END dout[85]
  PIN dout[86]
    DIRECTION OUTPUT ;
    USE SIGNAL ;
    PORT
      LAYER M5 ;
        RECT  9.168 58.236 9.192 58.32 ;
    END
  END dout[86]
  PIN dout[87]
    DIRECTION OUTPUT ;
    USE SIGNAL ;
    PORT
      LAYER M5 ;
        RECT  9.264 58.236 9.288 58.32 ;
    END
  END dout[87]
  PIN dout[88]
    DIRECTION OUTPUT ;
    USE SIGNAL ;
    PORT
      LAYER M5 ;
        RECT  9.36 58.236 9.384 58.32 ;
    END
  END dout[88]
  PIN dout[89]
    DIRECTION OUTPUT ;
    USE SIGNAL ;
    PORT
      LAYER M5 ;
        RECT  9.456 58.236 9.48 58.32 ;
    END
  END dout[89]
  PIN dout[8]
    DIRECTION OUTPUT ;
    USE SIGNAL ;
    PORT
      LAYER M5 ;
        RECT  84.624 58.236 84.648 58.32 ;
    END
  END dout[8]
  PIN dout[90]
    DIRECTION OUTPUT ;
    USE SIGNAL ;
    PORT
      LAYER M5 ;
        RECT  9.552 58.236 9.576 58.32 ;
    END
  END dout[90]
  PIN dout[91]
    DIRECTION OUTPUT ;
    USE SIGNAL ;
    PORT
      LAYER M5 ;
        RECT  9.648 58.236 9.672 58.32 ;
    END
  END dout[91]
  PIN dout[92]
    DIRECTION OUTPUT ;
    USE SIGNAL ;
    PORT
      LAYER M5 ;
        RECT  9.744 58.236 9.768 58.32 ;
    END
  END dout[92]
  PIN dout[93]
    DIRECTION OUTPUT ;
    USE SIGNAL ;
    PORT
      LAYER M5 ;
        RECT  9.84 58.236 9.864 58.32 ;
    END
  END dout[93]
  PIN dout[94]
    DIRECTION OUTPUT ;
    USE SIGNAL ;
    PORT
      LAYER M5 ;
        RECT  9.936 58.236 9.96 58.32 ;
    END
  END dout[94]
  PIN dout[95]
    DIRECTION OUTPUT ;
    USE SIGNAL ;
    PORT
      LAYER M5 ;
        RECT  10.032 58.236 10.056 58.32 ;
    END
  END dout[95]
  PIN dout[96]
    DIRECTION OUTPUT ;
    USE SIGNAL ;
    PORT
      LAYER M5 ;
        RECT  36.24 58.236 36.264 58.32 ;
    END
  END dout[96]
  PIN dout[97]
    DIRECTION OUTPUT ;
    USE SIGNAL ;
    PORT
      LAYER M5 ;
        RECT  36.336 58.236 36.36 58.32 ;
    END
  END dout[97]
  PIN dout[98]
    DIRECTION OUTPUT ;
    USE SIGNAL ;
    PORT
      LAYER M5 ;
        RECT  36.432 58.236 36.456 58.32 ;
    END
  END dout[98]
  PIN dout[99]
    DIRECTION OUTPUT ;
    USE SIGNAL ;
    PORT
      LAYER M5 ;
        RECT  36.528 58.236 36.552 58.32 ;
    END
  END dout[99]
  PIN dout[9]
    DIRECTION OUTPUT ;
    USE SIGNAL ;
    PORT
      LAYER M5 ;
        RECT  84.72 58.236 84.744 58.32 ;
    END
  END dout[9]
  PIN go_check
    DIRECTION INPUT ;
    USE SIGNAL ;
    PORT
      LAYER M5 ;
        RECT  56.88 0 56.904 0.084 ;
    END
  END go_check
  PIN go_commit
    DIRECTION INPUT ;
    USE SIGNAL ;
    PORT
      LAYER M5 ;
        RECT  56.976 0 57 0.084 ;
    END
  END go_commit
  PIN go_repair
    DIRECTION INPUT ;
    USE SIGNAL ;
    PORT
      LAYER M5 ;
        RECT  57.072 0 57.096 0.084 ;
    END
  END go_repair
  PIN go_sel
    DIRECTION INPUT ;
    USE SIGNAL ;
    PORT
      LAYER M5 ;
        RECT  57.168 0 57.192 0.084 ;
    END
  END go_sel
  PIN gr
    DIRECTION INPUT ;
    USE SIGNAL ;
    PORT
      LAYER M5 ;
        RECT  57.264 0 57.288 0.084 ;
    END
  END gr
  PIN grc_o[0]
    DIRECTION OUTPUT ;
    USE SIGNAL ;
    PORT
      LAYER M5 ;
        RECT  57.36 0 57.384 0.084 ;
    END
  END grc_o[0]
  PIN grc_o[1]
    DIRECTION OUTPUT ;
    USE SIGNAL ;
    PORT
      LAYER M5 ;
        RECT  57.456 0 57.48 0.084 ;
    END
  END grc_o[1]
  PIN grc_o[2]
    DIRECTION OUTPUT ;
    USE SIGNAL ;
    PORT
      LAYER M5 ;
        RECT  80.592 0 80.616 0.084 ;
    END
  END grc_o[2]
  PIN grc_o[3]
    DIRECTION OUTPUT ;
    USE SIGNAL ;
    PORT
      LAYER M5 ;
        RECT  80.688 0 80.712 0.084 ;
    END
  END grc_o[3]
  PIN grc_o[4]
    DIRECTION OUTPUT ;
    USE SIGNAL ;
    PORT
      LAYER M5 ;
        RECT  80.784 0 80.808 0.084 ;
    END
  END grc_o[4]
  PIN ph4[0]
    DIRECTION INPUT ;
    USE SIGNAL ;
    PORT
      LAYER M5 ;
        RECT  80.88 0 80.904 0.084 ;
    END
  END ph4[0]
  PIN ph4[1]
    DIRECTION INPUT ;
    USE SIGNAL ;
    PORT
      LAYER M5 ;
        RECT  80.976 0 81 0.084 ;
    END
  END ph4[1]
  PIN ph4[2]
    DIRECTION INPUT ;
    USE SIGNAL ;
    PORT
      LAYER M5 ;
        RECT  81.072 0 81.096 0.084 ;
    END
  END ph4[2]
  PIN ph4[3]
    DIRECTION INPUT ;
    USE SIGNAL ;
    PORT
      LAYER M5 ;
        RECT  81.168 0 81.192 0.084 ;
    END
  END ph4[3]
  PIN q[0]
    DIRECTION OUTPUT ;
    USE SIGNAL ;
    PORT
      LAYER M5 ;
        RECT  81.264 0 81.288 0.084 ;
    END
  END q[0]
  PIN q[100]
    DIRECTION OUTPUT ;
    USE SIGNAL ;
    PORT
      LAYER M5 ;
        RECT  30.192 0 30.216 0.084 ;
    END
  END q[100]
  PIN q[101]
    DIRECTION OUTPUT ;
    USE SIGNAL ;
    PORT
      LAYER M5 ;
        RECT  30.288 0 30.312 0.084 ;
    END
  END q[101]
  PIN q[102]
    DIRECTION OUTPUT ;
    USE SIGNAL ;
    PORT
      LAYER M5 ;
        RECT  30.384 0 30.408 0.084 ;
    END
  END q[102]
  PIN q[103]
    DIRECTION OUTPUT ;
    USE SIGNAL ;
    PORT
      LAYER M5 ;
        RECT  30.48 0 30.504 0.084 ;
    END
  END q[103]
  PIN q[104]
    DIRECTION OUTPUT ;
    USE SIGNAL ;
    PORT
      LAYER M5 ;
        RECT  30.576 0 30.6 0.084 ;
    END
  END q[104]
  PIN q[105]
    DIRECTION OUTPUT ;
    USE SIGNAL ;
    PORT
      LAYER M5 ;
        RECT  30.672 0 30.696 0.084 ;
    END
  END q[105]
  PIN q[106]
    DIRECTION OUTPUT ;
    USE SIGNAL ;
    PORT
      LAYER M5 ;
        RECT  30.768 0 30.792 0.084 ;
    END
  END q[106]
  PIN q[107]
    DIRECTION OUTPUT ;
    USE SIGNAL ;
    PORT
      LAYER M5 ;
        RECT  30.864 0 30.888 0.084 ;
    END
  END q[107]
  PIN q[108]
    DIRECTION OUTPUT ;
    USE SIGNAL ;
    PORT
      LAYER M5 ;
        RECT  30.96 0 30.984 0.084 ;
    END
  END q[108]
  PIN q[109]
    DIRECTION OUTPUT ;
    USE SIGNAL ;
    PORT
      LAYER M5 ;
        RECT  31.056 0 31.08 0.084 ;
    END
  END q[109]
  PIN q[10]
    DIRECTION OUTPUT ;
    USE SIGNAL ;
    PORT
      LAYER M5 ;
        RECT  82.224 0 82.248 0.084 ;
    END
  END q[10]
  PIN q[110]
    DIRECTION OUTPUT ;
    USE SIGNAL ;
    PORT
      LAYER M5 ;
        RECT  31.152 0 31.176 0.084 ;
    END
  END q[110]
  PIN q[111]
    DIRECTION OUTPUT ;
    USE SIGNAL ;
    PORT
      LAYER M5 ;
        RECT  31.248 0 31.272 0.084 ;
    END
  END q[111]
  PIN q[112]
    DIRECTION OUTPUT ;
    USE SIGNAL ;
    PORT
      LAYER M5 ;
        RECT  31.344 0 31.368 0.084 ;
    END
  END q[112]
  PIN q[113]
    DIRECTION OUTPUT ;
    USE SIGNAL ;
    PORT
      LAYER M5 ;
        RECT  31.44 0 31.464 0.084 ;
    END
  END q[113]
  PIN q[114]
    DIRECTION OUTPUT ;
    USE SIGNAL ;
    PORT
      LAYER M5 ;
        RECT  31.536 0 31.56 0.084 ;
    END
  END q[114]
  PIN q[115]
    DIRECTION OUTPUT ;
    USE SIGNAL ;
    PORT
      LAYER M5 ;
        RECT  31.632 0 31.656 0.084 ;
    END
  END q[115]
  PIN q[116]
    DIRECTION OUTPUT ;
    USE SIGNAL ;
    PORT
      LAYER M5 ;
        RECT  31.728 0 31.752 0.084 ;
    END
  END q[116]
  PIN q[117]
    DIRECTION OUTPUT ;
    USE SIGNAL ;
    PORT
      LAYER M5 ;
        RECT  31.824 0 31.848 0.084 ;
    END
  END q[117]
  PIN q[118]
    DIRECTION OUTPUT ;
    USE SIGNAL ;
    PORT
      LAYER M5 ;
        RECT  31.92 0 31.944 0.084 ;
    END
  END q[118]
  PIN q[119]
    DIRECTION OUTPUT ;
    USE SIGNAL ;
    PORT
      LAYER M5 ;
        RECT  32.016 0 32.04 0.084 ;
    END
  END q[119]
  PIN q[11]
    DIRECTION OUTPUT ;
    USE SIGNAL ;
    PORT
      LAYER M5 ;
        RECT  82.32 0 82.344 0.084 ;
    END
  END q[11]
  PIN q[120]
    DIRECTION OUTPUT ;
    USE SIGNAL ;
    PORT
      LAYER M5 ;
        RECT  32.112 0 32.136 0.084 ;
    END
  END q[120]
  PIN q[121]
    DIRECTION OUTPUT ;
    USE SIGNAL ;
    PORT
      LAYER M5 ;
        RECT  26.064 0 26.088 0.084 ;
    END
  END q[121]
  PIN q[122]
    DIRECTION OUTPUT ;
    USE SIGNAL ;
    PORT
      LAYER M5 ;
        RECT  26.16 0 26.184 0.084 ;
    END
  END q[122]
  PIN q[123]
    DIRECTION OUTPUT ;
    USE SIGNAL ;
    PORT
      LAYER M5 ;
        RECT  26.256 0 26.28 0.084 ;
    END
  END q[123]
  PIN q[124]
    DIRECTION OUTPUT ;
    USE SIGNAL ;
    PORT
      LAYER M5 ;
        RECT  26.352 0 26.376 0.084 ;
    END
  END q[124]
  PIN q[125]
    DIRECTION OUTPUT ;
    USE SIGNAL ;
    PORT
      LAYER M5 ;
        RECT  26.448 0 26.472 0.084 ;
    END
  END q[125]
  PIN q[126]
    DIRECTION OUTPUT ;
    USE SIGNAL ;
    PORT
      LAYER M5 ;
        RECT  26.544 0 26.568 0.084 ;
    END
  END q[126]
  PIN q[127]
    DIRECTION OUTPUT ;
    USE SIGNAL ;
    PORT
      LAYER M5 ;
        RECT  26.64 0 26.664 0.084 ;
    END
  END q[127]
  PIN q[128]
    DIRECTION OUTPUT ;
    USE SIGNAL ;
    PORT
      LAYER M5 ;
        RECT  26.736 0 26.76 0.084 ;
    END
  END q[128]
  PIN q[129]
    DIRECTION OUTPUT ;
    USE SIGNAL ;
    PORT
      LAYER M5 ;
        RECT  26.832 0 26.856 0.084 ;
    END
  END q[129]
  PIN q[12]
    DIRECTION OUTPUT ;
    USE SIGNAL ;
    PORT
      LAYER M5 ;
        RECT  82.416 0 82.44 0.084 ;
    END
  END q[12]
  PIN q[130]
    DIRECTION OUTPUT ;
    USE SIGNAL ;
    PORT
      LAYER M5 ;
        RECT  26.928 0 26.952 0.084 ;
    END
  END q[130]
  PIN q[131]
    DIRECTION OUTPUT ;
    USE SIGNAL ;
    PORT
      LAYER M5 ;
        RECT  27.024 0 27.048 0.084 ;
    END
  END q[131]
  PIN q[132]
    DIRECTION OUTPUT ;
    USE SIGNAL ;
    PORT
      LAYER M5 ;
        RECT  27.12 0 27.144 0.084 ;
    END
  END q[132]
  PIN q[133]
    DIRECTION OUTPUT ;
    USE SIGNAL ;
    PORT
      LAYER M5 ;
        RECT  27.216 0 27.24 0.084 ;
    END
  END q[133]
  PIN q[134]
    DIRECTION OUTPUT ;
    USE SIGNAL ;
    PORT
      LAYER M5 ;
        RECT  27.312 0 27.336 0.084 ;
    END
  END q[134]
  PIN q[135]
    DIRECTION OUTPUT ;
    USE SIGNAL ;
    PORT
      LAYER M5 ;
        RECT  27.408 0 27.432 0.084 ;
    END
  END q[135]
  PIN q[136]
    DIRECTION OUTPUT ;
    USE SIGNAL ;
    PORT
      LAYER M5 ;
        RECT  27.504 0 27.528 0.084 ;
    END
  END q[136]
  PIN q[137]
    DIRECTION OUTPUT ;
    USE SIGNAL ;
    PORT
      LAYER M5 ;
        RECT  27.6 0 27.624 0.084 ;
    END
  END q[137]
  PIN q[138]
    DIRECTION OUTPUT ;
    USE SIGNAL ;
    PORT
      LAYER M5 ;
        RECT  27.696 0 27.72 0.084 ;
    END
  END q[138]
  PIN q[139]
    DIRECTION OUTPUT ;
    USE SIGNAL ;
    PORT
      LAYER M5 ;
        RECT  27.792 0 27.816 0.084 ;
    END
  END q[139]
  PIN q[13]
    DIRECTION OUTPUT ;
    USE SIGNAL ;
    PORT
      LAYER M5 ;
        RECT  82.512 0 82.536 0.084 ;
    END
  END q[13]
  PIN q[140]
    DIRECTION OUTPUT ;
    USE SIGNAL ;
    PORT
      LAYER M5 ;
        RECT  27.888 0 27.912 0.084 ;
    END
  END q[140]
  PIN q[141]
    DIRECTION OUTPUT ;
    USE SIGNAL ;
    PORT
      LAYER M5 ;
        RECT  27.984 0 28.008 0.084 ;
    END
  END q[141]
  PIN q[142]
    DIRECTION OUTPUT ;
    USE SIGNAL ;
    PORT
      LAYER M5 ;
        RECT  28.08 0 28.104 0.084 ;
    END
  END q[142]
  PIN q[143]
    DIRECTION OUTPUT ;
    USE SIGNAL ;
    PORT
      LAYER M5 ;
        RECT  28.176 0 28.2 0.084 ;
    END
  END q[143]
  PIN q[144]
    DIRECTION OUTPUT ;
    USE SIGNAL ;
    PORT
      LAYER M5 ;
        RECT  28.272 0 28.296 0.084 ;
    END
  END q[144]
  PIN q[145]
    DIRECTION OUTPUT ;
    USE SIGNAL ;
    PORT
      LAYER M5 ;
        RECT  28.368 0 28.392 0.084 ;
    END
  END q[145]
  PIN q[146]
    DIRECTION OUTPUT ;
    USE SIGNAL ;
    PORT
      LAYER M5 ;
        RECT  28.464 0 28.488 0.084 ;
    END
  END q[146]
  PIN q[147]
    DIRECTION OUTPUT ;
    USE SIGNAL ;
    PORT
      LAYER M5 ;
        RECT  28.56 0 28.584 0.084 ;
    END
  END q[147]
  PIN q[148]
    DIRECTION OUTPUT ;
    USE SIGNAL ;
    PORT
      LAYER M5 ;
        RECT  28.656 0 28.68 0.084 ;
    END
  END q[148]
  PIN q[149]
    DIRECTION OUTPUT ;
    USE SIGNAL ;
    PORT
      LAYER M5 ;
        RECT  28.752 0 28.776 0.084 ;
    END
  END q[149]
  PIN q[14]
    DIRECTION OUTPUT ;
    USE SIGNAL ;
    PORT
      LAYER M5 ;
        RECT  82.608 0 82.632 0.084 ;
    END
  END q[14]
  PIN q[150]
    DIRECTION OUTPUT ;
    USE SIGNAL ;
    PORT
      LAYER M5 ;
        RECT  28.848 0 28.872 0.084 ;
    END
  END q[150]
  PIN q[151]
    DIRECTION OUTPUT ;
    USE SIGNAL ;
    PORT
      LAYER M5 ;
        RECT  28.944 0 28.968 0.084 ;
    END
  END q[151]
  PIN q[152]
    DIRECTION OUTPUT ;
    USE SIGNAL ;
    PORT
      LAYER M5 ;
        RECT  29.04 0 29.064 0.084 ;
    END
  END q[152]
  PIN q[153]
    DIRECTION OUTPUT ;
    USE SIGNAL ;
    PORT
      LAYER M5 ;
        RECT  32.208 0 32.232 0.084 ;
    END
  END q[153]
  PIN q[154]
    DIRECTION OUTPUT ;
    USE SIGNAL ;
    PORT
      LAYER M5 ;
        RECT  32.304 0 32.328 0.084 ;
    END
  END q[154]
  PIN q[155]
    DIRECTION OUTPUT ;
    USE SIGNAL ;
    PORT
      LAYER M5 ;
        RECT  32.4 0 32.424 0.084 ;
    END
  END q[155]
  PIN q[156]
    DIRECTION OUTPUT ;
    USE SIGNAL ;
    PORT
      LAYER M5 ;
        RECT  32.496 0 32.52 0.084 ;
    END
  END q[156]
  PIN q[157]
    DIRECTION OUTPUT ;
    USE SIGNAL ;
    PORT
      LAYER M5 ;
        RECT  32.592 0 32.616 0.084 ;
    END
  END q[157]
  PIN q[158]
    DIRECTION OUTPUT ;
    USE SIGNAL ;
    PORT
      LAYER M5 ;
        RECT  32.688 0 32.712 0.084 ;
    END
  END q[158]
  PIN q[159]
    DIRECTION OUTPUT ;
    USE SIGNAL ;
    PORT
      LAYER M5 ;
        RECT  32.784 0 32.808 0.084 ;
    END
  END q[159]
  PIN q[15]
    DIRECTION OUTPUT ;
    USE SIGNAL ;
    PORT
      LAYER M5 ;
        RECT  82.704 0 82.728 0.084 ;
    END
  END q[15]
  PIN q[160]
    DIRECTION OUTPUT ;
    USE SIGNAL ;
    PORT
      LAYER M5 ;
        RECT  32.88 0 32.904 0.084 ;
    END
  END q[160]
  PIN q[161]
    DIRECTION OUTPUT ;
    USE SIGNAL ;
    PORT
      LAYER M5 ;
        RECT  32.976 0 33 0.084 ;
    END
  END q[161]
  PIN q[162]
    DIRECTION OUTPUT ;
    USE SIGNAL ;
    PORT
      LAYER M5 ;
        RECT  33.072 0 33.096 0.084 ;
    END
  END q[162]
  PIN q[163]
    DIRECTION OUTPUT ;
    USE SIGNAL ;
    PORT
      LAYER M5 ;
        RECT  33.168 0 33.192 0.084 ;
    END
  END q[163]
  PIN q[164]
    DIRECTION OUTPUT ;
    USE SIGNAL ;
    PORT
      LAYER M5 ;
        RECT  33.264 0 33.288 0.084 ;
    END
  END q[164]
  PIN q[165]
    DIRECTION OUTPUT ;
    USE SIGNAL ;
    PORT
      LAYER M5 ;
        RECT  33.36 0 33.384 0.084 ;
    END
  END q[165]
  PIN q[166]
    DIRECTION OUTPUT ;
    USE SIGNAL ;
    PORT
      LAYER M5 ;
        RECT  33.456 0 33.48 0.084 ;
    END
  END q[166]
  PIN q[167]
    DIRECTION OUTPUT ;
    USE SIGNAL ;
    PORT
      LAYER M5 ;
        RECT  33.552 0 33.576 0.084 ;
    END
  END q[167]
  PIN q[168]
    DIRECTION OUTPUT ;
    USE SIGNAL ;
    PORT
      LAYER M5 ;
        RECT  33.648 0 33.672 0.084 ;
    END
  END q[168]
  PIN q[169]
    DIRECTION OUTPUT ;
    USE SIGNAL ;
    PORT
      LAYER M5 ;
        RECT  33.744 0 33.768 0.084 ;
    END
  END q[169]
  PIN q[16]
    DIRECTION OUTPUT ;
    USE SIGNAL ;
    PORT
      LAYER M5 ;
        RECT  82.8 0 82.824 0.084 ;
    END
  END q[16]
  PIN q[170]
    DIRECTION OUTPUT ;
    USE SIGNAL ;
    PORT
      LAYER M5 ;
        RECT  33.84 0 33.864 0.084 ;
    END
  END q[170]
  PIN q[171]
    DIRECTION OUTPUT ;
    USE SIGNAL ;
    PORT
      LAYER M5 ;
        RECT  33.936 0 33.96 0.084 ;
    END
  END q[171]
  PIN q[172]
    DIRECTION OUTPUT ;
    USE SIGNAL ;
    PORT
      LAYER M5 ;
        RECT  34.032 0 34.056 0.084 ;
    END
  END q[172]
  PIN q[173]
    DIRECTION OUTPUT ;
    USE SIGNAL ;
    PORT
      LAYER M5 ;
        RECT  34.128 0 34.152 0.084 ;
    END
  END q[173]
  PIN q[174]
    DIRECTION OUTPUT ;
    USE SIGNAL ;
    PORT
      LAYER M5 ;
        RECT  34.224 0 34.248 0.084 ;
    END
  END q[174]
  PIN q[175]
    DIRECTION OUTPUT ;
    USE SIGNAL ;
    PORT
      LAYER M5 ;
        RECT  34.32 0 34.344 0.084 ;
    END
  END q[175]
  PIN q[176]
    DIRECTION OUTPUT ;
    USE SIGNAL ;
    PORT
      LAYER M5 ;
        RECT  34.416 0 34.44 0.084 ;
    END
  END q[176]
  PIN q[177]
    DIRECTION OUTPUT ;
    USE SIGNAL ;
    PORT
      LAYER M5 ;
        RECT  34.512 0 34.536 0.084 ;
    END
  END q[177]
  PIN q[178]
    DIRECTION OUTPUT ;
    USE SIGNAL ;
    PORT
      LAYER M5 ;
        RECT  34.608 0 34.632 0.084 ;
    END
  END q[178]
  PIN q[179]
    DIRECTION OUTPUT ;
    USE SIGNAL ;
    PORT
      LAYER M5 ;
        RECT  34.704 0 34.728 0.084 ;
    END
  END q[179]
  PIN q[17]
    DIRECTION OUTPUT ;
    USE SIGNAL ;
    PORT
      LAYER M5 ;
        RECT  82.896 0 82.92 0.084 ;
    END
  END q[17]
  PIN q[180]
    DIRECTION OUTPUT ;
    USE SIGNAL ;
    PORT
      LAYER M5 ;
        RECT  34.8 0 34.824 0.084 ;
    END
  END q[180]
  PIN q[181]
    DIRECTION OUTPUT ;
    USE SIGNAL ;
    PORT
      LAYER M5 ;
        RECT  34.896 0 34.92 0.084 ;
    END
  END q[181]
  PIN q[182]
    DIRECTION OUTPUT ;
    USE SIGNAL ;
    PORT
      LAYER M5 ;
        RECT  34.992 0 35.016 0.084 ;
    END
  END q[182]
  PIN q[183]
    DIRECTION OUTPUT ;
    USE SIGNAL ;
    PORT
      LAYER M5 ;
        RECT  35.088 0 35.112 0.084 ;
    END
  END q[183]
  PIN q[184]
    DIRECTION OUTPUT ;
    USE SIGNAL ;
    PORT
      LAYER M5 ;
        RECT  35.184 0 35.208 0.084 ;
    END
  END q[184]
  PIN q[185]
    DIRECTION OUTPUT ;
    USE SIGNAL ;
    PORT
      LAYER M5 ;
        RECT  67.536 0 67.56 0.084 ;
    END
  END q[185]
  PIN q[186]
    DIRECTION OUTPUT ;
    USE SIGNAL ;
    PORT
      LAYER M5 ;
        RECT  67.632 0 67.656 0.084 ;
    END
  END q[186]
  PIN q[187]
    DIRECTION OUTPUT ;
    USE SIGNAL ;
    PORT
      LAYER M5 ;
        RECT  67.728 0 67.752 0.084 ;
    END
  END q[187]
  PIN q[188]
    DIRECTION OUTPUT ;
    USE SIGNAL ;
    PORT
      LAYER M5 ;
        RECT  67.824 0 67.848 0.084 ;
    END
  END q[188]
  PIN q[189]
    DIRECTION OUTPUT ;
    USE SIGNAL ;
    PORT
      LAYER M5 ;
        RECT  67.92 0 67.944 0.084 ;
    END
  END q[189]
  PIN q[18]
    DIRECTION OUTPUT ;
    USE SIGNAL ;
    PORT
      LAYER M5 ;
        RECT  82.992 0 83.016 0.084 ;
    END
  END q[18]
  PIN q[190]
    DIRECTION OUTPUT ;
    USE SIGNAL ;
    PORT
      LAYER M5 ;
        RECT  68.016 0 68.04 0.084 ;
    END
  END q[190]
  PIN q[191]
    DIRECTION OUTPUT ;
    USE SIGNAL ;
    PORT
      LAYER M5 ;
        RECT  68.112 0 68.136 0.084 ;
    END
  END q[191]
  PIN q[192]
    DIRECTION OUTPUT ;
    USE SIGNAL ;
    PORT
      LAYER M5 ;
        RECT  68.208 0 68.232 0.084 ;
    END
  END q[192]
  PIN q[193]
    DIRECTION OUTPUT ;
    USE SIGNAL ;
    PORT
      LAYER M5 ;
        RECT  68.304 0 68.328 0.084 ;
    END
  END q[193]
  PIN q[194]
    DIRECTION OUTPUT ;
    USE SIGNAL ;
    PORT
      LAYER M5 ;
        RECT  68.4 0 68.424 0.084 ;
    END
  END q[194]
  PIN q[195]
    DIRECTION OUTPUT ;
    USE SIGNAL ;
    PORT
      LAYER M5 ;
        RECT  68.496 0 68.52 0.084 ;
    END
  END q[195]
  PIN q[196]
    DIRECTION OUTPUT ;
    USE SIGNAL ;
    PORT
      LAYER M5 ;
        RECT  68.592 0 68.616 0.084 ;
    END
  END q[196]
  PIN q[197]
    DIRECTION OUTPUT ;
    USE SIGNAL ;
    PORT
      LAYER M5 ;
        RECT  68.688 0 68.712 0.084 ;
    END
  END q[197]
  PIN q[198]
    DIRECTION OUTPUT ;
    USE SIGNAL ;
    PORT
      LAYER M5 ;
        RECT  68.784 0 68.808 0.084 ;
    END
  END q[198]
  PIN q[199]
    DIRECTION OUTPUT ;
    USE SIGNAL ;
    PORT
      LAYER M5 ;
        RECT  68.88 0 68.904 0.084 ;
    END
  END q[199]
  PIN q[19]
    DIRECTION OUTPUT ;
    USE SIGNAL ;
    PORT
      LAYER M5 ;
        RECT  83.088 0 83.112 0.084 ;
    END
  END q[19]
  PIN q[1]
    DIRECTION OUTPUT ;
    USE SIGNAL ;
    PORT
      LAYER M5 ;
        RECT  81.36 0 81.384 0.084 ;
    END
  END q[1]
  PIN q[200]
    DIRECTION OUTPUT ;
    USE SIGNAL ;
    PORT
      LAYER M5 ;
        RECT  68.976 0 69 0.084 ;
    END
  END q[200]
  PIN q[201]
    DIRECTION OUTPUT ;
    USE SIGNAL ;
    PORT
      LAYER M5 ;
        RECT  69.072 0 69.096 0.084 ;
    END
  END q[201]
  PIN q[202]
    DIRECTION OUTPUT ;
    USE SIGNAL ;
    PORT
      LAYER M5 ;
        RECT  69.168 0 69.192 0.084 ;
    END
  END q[202]
  PIN q[203]
    DIRECTION OUTPUT ;
    USE SIGNAL ;
    PORT
      LAYER M5 ;
        RECT  69.264 0 69.288 0.084 ;
    END
  END q[203]
  PIN q[204]
    DIRECTION OUTPUT ;
    USE SIGNAL ;
    PORT
      LAYER M5 ;
        RECT  69.36 0 69.384 0.084 ;
    END
  END q[204]
  PIN q[205]
    DIRECTION OUTPUT ;
    USE SIGNAL ;
    PORT
      LAYER M5 ;
        RECT  69.456 0 69.48 0.084 ;
    END
  END q[205]
  PIN q[206]
    DIRECTION OUTPUT ;
    USE SIGNAL ;
    PORT
      LAYER M5 ;
        RECT  69.552 0 69.576 0.084 ;
    END
  END q[206]
  PIN q[207]
    DIRECTION OUTPUT ;
    USE SIGNAL ;
    PORT
      LAYER M5 ;
        RECT  69.648 0 69.672 0.084 ;
    END
  END q[207]
  PIN q[208]
    DIRECTION OUTPUT ;
    USE SIGNAL ;
    PORT
      LAYER M5 ;
        RECT  69.744 0 69.768 0.084 ;
    END
  END q[208]
  PIN q[209]
    DIRECTION OUTPUT ;
    USE SIGNAL ;
    PORT
      LAYER M5 ;
        RECT  69.84 0 69.864 0.084 ;
    END
  END q[209]
  PIN q[20]
    DIRECTION OUTPUT ;
    USE SIGNAL ;
    PORT
      LAYER M5 ;
        RECT  83.184 0 83.208 0.084 ;
    END
  END q[20]
  PIN q[210]
    DIRECTION OUTPUT ;
    USE SIGNAL ;
    PORT
      LAYER M5 ;
        RECT  69.936 0 69.96 0.084 ;
    END
  END q[210]
  PIN q[211]
    DIRECTION OUTPUT ;
    USE SIGNAL ;
    PORT
      LAYER M5 ;
        RECT  70.032 0 70.056 0.084 ;
    END
  END q[211]
  PIN q[212]
    DIRECTION OUTPUT ;
    USE SIGNAL ;
    PORT
      LAYER M5 ;
        RECT  70.128 0 70.152 0.084 ;
    END
  END q[212]
  PIN q[213]
    DIRECTION OUTPUT ;
    USE SIGNAL ;
    PORT
      LAYER M5 ;
        RECT  70.224 0 70.248 0.084 ;
    END
  END q[213]
  PIN q[214]
    DIRECTION OUTPUT ;
    USE SIGNAL ;
    PORT
      LAYER M5 ;
        RECT  70.32 0 70.344 0.084 ;
    END
  END q[214]
  PIN q[215]
    DIRECTION OUTPUT ;
    USE SIGNAL ;
    PORT
      LAYER M5 ;
        RECT  70.416 0 70.44 0.084 ;
    END
  END q[215]
  PIN q[216]
    DIRECTION OUTPUT ;
    USE SIGNAL ;
    PORT
      LAYER M5 ;
        RECT  70.512 0 70.536 0.084 ;
    END
  END q[216]
  PIN q[217]
    DIRECTION OUTPUT ;
    USE SIGNAL ;
    PORT
      LAYER M5 ;
        RECT  83.664 0 83.688 0.084 ;
    END
  END q[217]
  PIN q[218]
    DIRECTION OUTPUT ;
    USE SIGNAL ;
    PORT
      LAYER M5 ;
        RECT  83.76 0 83.784 0.084 ;
    END
  END q[218]
  PIN q[219]
    DIRECTION OUTPUT ;
    USE SIGNAL ;
    PORT
      LAYER M5 ;
        RECT  83.856 0 83.88 0.084 ;
    END
  END q[219]
  PIN q[21]
    DIRECTION OUTPUT ;
    USE SIGNAL ;
    PORT
      LAYER M5 ;
        RECT  83.28 0 83.304 0.084 ;
    END
  END q[21]
  PIN q[220]
    DIRECTION OUTPUT ;
    USE SIGNAL ;
    PORT
      LAYER M5 ;
        RECT  83.952 0 83.976 0.084 ;
    END
  END q[220]
  PIN q[221]
    DIRECTION OUTPUT ;
    USE SIGNAL ;
    PORT
      LAYER M5 ;
        RECT  84.048 0 84.072 0.084 ;
    END
  END q[221]
  PIN q[222]
    DIRECTION OUTPUT ;
    USE SIGNAL ;
    PORT
      LAYER M5 ;
        RECT  84.144 0 84.168 0.084 ;
    END
  END q[222]
  PIN q[223]
    DIRECTION OUTPUT ;
    USE SIGNAL ;
    PORT
      LAYER M5 ;
        RECT  84.24 0 84.264 0.084 ;
    END
  END q[223]
  PIN q[224]
    DIRECTION OUTPUT ;
    USE SIGNAL ;
    PORT
      LAYER M5 ;
        RECT  84.336 0 84.36 0.084 ;
    END
  END q[224]
  PIN q[225]
    DIRECTION OUTPUT ;
    USE SIGNAL ;
    PORT
      LAYER M5 ;
        RECT  84.432 0 84.456 0.084 ;
    END
  END q[225]
  PIN q[226]
    DIRECTION OUTPUT ;
    USE SIGNAL ;
    PORT
      LAYER M5 ;
        RECT  84.528 0 84.552 0.084 ;
    END
  END q[226]
  PIN q[227]
    DIRECTION OUTPUT ;
    USE SIGNAL ;
    PORT
      LAYER M5 ;
        RECT  84.624 0 84.648 0.084 ;
    END
  END q[227]
  PIN q[228]
    DIRECTION OUTPUT ;
    USE SIGNAL ;
    PORT
      LAYER M5 ;
        RECT  84.72 0 84.744 0.084 ;
    END
  END q[228]
  PIN q[229]
    DIRECTION OUTPUT ;
    USE SIGNAL ;
    PORT
      LAYER M5 ;
        RECT  84.816 0 84.84 0.084 ;
    END
  END q[229]
  PIN q[22]
    DIRECTION OUTPUT ;
    USE SIGNAL ;
    PORT
      LAYER M5 ;
        RECT  83.376 0 83.4 0.084 ;
    END
  END q[22]
  PIN q[230]
    DIRECTION OUTPUT ;
    USE SIGNAL ;
    PORT
      LAYER M5 ;
        RECT  84.912 0 84.936 0.084 ;
    END
  END q[230]
  PIN q[231]
    DIRECTION OUTPUT ;
    USE SIGNAL ;
    PORT
      LAYER M5 ;
        RECT  85.008 0 85.032 0.084 ;
    END
  END q[231]
  PIN q[232]
    DIRECTION OUTPUT ;
    USE SIGNAL ;
    PORT
      LAYER M5 ;
        RECT  85.104 0 85.128 0.084 ;
    END
  END q[232]
  PIN q[233]
    DIRECTION OUTPUT ;
    USE SIGNAL ;
    PORT
      LAYER M5 ;
        RECT  85.2 0 85.224 0.084 ;
    END
  END q[233]
  PIN q[234]
    DIRECTION OUTPUT ;
    USE SIGNAL ;
    PORT
      LAYER M5 ;
        RECT  85.296 0 85.32 0.084 ;
    END
  END q[234]
  PIN q[235]
    DIRECTION OUTPUT ;
    USE SIGNAL ;
    PORT
      LAYER M5 ;
        RECT  85.392 0 85.416 0.084 ;
    END
  END q[235]
  PIN q[236]
    DIRECTION OUTPUT ;
    USE SIGNAL ;
    PORT
      LAYER M5 ;
        RECT  85.488 0 85.512 0.084 ;
    END
  END q[236]
  PIN q[237]
    DIRECTION OUTPUT ;
    USE SIGNAL ;
    PORT
      LAYER M5 ;
        RECT  85.584 0 85.608 0.084 ;
    END
  END q[237]
  PIN q[238]
    DIRECTION OUTPUT ;
    USE SIGNAL ;
    PORT
      LAYER M5 ;
        RECT  85.68 0 85.704 0.084 ;
    END
  END q[238]
  PIN q[239]
    DIRECTION OUTPUT ;
    USE SIGNAL ;
    PORT
      LAYER M5 ;
        RECT  85.776 0 85.8 0.084 ;
    END
  END q[239]
  PIN q[23]
    DIRECTION OUTPUT ;
    USE SIGNAL ;
    PORT
      LAYER M5 ;
        RECT  83.472 0 83.496 0.084 ;
    END
  END q[23]
  PIN q[240]
    DIRECTION OUTPUT ;
    USE SIGNAL ;
    PORT
      LAYER M5 ;
        RECT  85.872 0 85.896 0.084 ;
    END
  END q[240]
  PIN q[241]
    DIRECTION OUTPUT ;
    USE SIGNAL ;
    PORT
      LAYER M5 ;
        RECT  85.968 0 85.992 0.084 ;
    END
  END q[241]
  PIN q[242]
    DIRECTION OUTPUT ;
    USE SIGNAL ;
    PORT
      LAYER M5 ;
        RECT  86.064 0 86.088 0.084 ;
    END
  END q[242]
  PIN q[243]
    DIRECTION OUTPUT ;
    USE SIGNAL ;
    PORT
      LAYER M5 ;
        RECT  86.16 0 86.184 0.084 ;
    END
  END q[243]
  PIN q[244]
    DIRECTION OUTPUT ;
    USE SIGNAL ;
    PORT
      LAYER M5 ;
        RECT  86.256 0 86.28 0.084 ;
    END
  END q[244]
  PIN q[245]
    DIRECTION OUTPUT ;
    USE SIGNAL ;
    PORT
      LAYER M5 ;
        RECT  86.352 0 86.376 0.084 ;
    END
  END q[245]
  PIN q[246]
    DIRECTION OUTPUT ;
    USE SIGNAL ;
    PORT
      LAYER M5 ;
        RECT  86.448 0 86.472 0.084 ;
    END
  END q[246]
  PIN q[247]
    DIRECTION OUTPUT ;
    USE SIGNAL ;
    PORT
      LAYER M5 ;
        RECT  86.544 0 86.568 0.084 ;
    END
  END q[247]
  PIN q[248]
    DIRECTION OUTPUT ;
    USE SIGNAL ;
    PORT
      LAYER M5 ;
        RECT  86.64 0 86.664 0.084 ;
    END
  END q[248]
  PIN q[249]
    DIRECTION OUTPUT ;
    USE SIGNAL ;
    PORT
      LAYER M5 ;
        RECT  86.736 0 86.76 0.084 ;
    END
  END q[249]
  PIN q[24]
    DIRECTION OUTPUT ;
    USE SIGNAL ;
    PORT
      LAYER M5 ;
        RECT  83.568 0 83.592 0.084 ;
    END
  END q[24]
  PIN q[250]
    DIRECTION OUTPUT ;
    USE SIGNAL ;
    PORT
      LAYER M5 ;
        RECT  86.832 0 86.856 0.084 ;
    END
  END q[250]
  PIN q[251]
    DIRECTION OUTPUT ;
    USE SIGNAL ;
    PORT
      LAYER M5 ;
        RECT  86.928 0 86.952 0.084 ;
    END
  END q[251]
  PIN q[252]
    DIRECTION OUTPUT ;
    USE SIGNAL ;
    PORT
      LAYER M5 ;
        RECT  87.024 0 87.048 0.084 ;
    END
  END q[252]
  PIN q[253]
    DIRECTION OUTPUT ;
    USE SIGNAL ;
    PORT
      LAYER M5 ;
        RECT  87.12 0 87.144 0.084 ;
    END
  END q[253]
  PIN q[254]
    DIRECTION OUTPUT ;
    USE SIGNAL ;
    PORT
      LAYER M5 ;
        RECT  87.216 0 87.24 0.084 ;
    END
  END q[254]
  PIN q[255]
    DIRECTION OUTPUT ;
    USE SIGNAL ;
    PORT
      LAYER M5 ;
        RECT  87.312 0 87.336 0.084 ;
    END
  END q[255]
  PIN q[256]
    DIRECTION OUTPUT ;
    USE SIGNAL ;
    PORT
      LAYER M5 ;
        RECT  87.408 0 87.432 0.084 ;
    END
  END q[256]
  PIN q[257]
    DIRECTION OUTPUT ;
    USE SIGNAL ;
    PORT
      LAYER M5 ;
        RECT  87.504 0 87.528 0.084 ;
    END
  END q[257]
  PIN q[258]
    DIRECTION OUTPUT ;
    USE SIGNAL ;
    PORT
      LAYER M5 ;
        RECT  87.6 0 87.624 0.084 ;
    END
  END q[258]
  PIN q[259]
    DIRECTION OUTPUT ;
    USE SIGNAL ;
    PORT
      LAYER M5 ;
        RECT  87.696 0 87.72 0.084 ;
    END
  END q[259]
  PIN q[25]
    DIRECTION OUTPUT ;
    USE SIGNAL ;
    PORT
      LAYER M5 ;
        RECT  77.52 0 77.544 0.084 ;
    END
  END q[25]
  PIN q[260]
    DIRECTION OUTPUT ;
    USE SIGNAL ;
    PORT
      LAYER M5 ;
        RECT  87.792 0 87.816 0.084 ;
    END
  END q[260]
  PIN q[261]
    DIRECTION OUTPUT ;
    USE SIGNAL ;
    PORT
      LAYER M5 ;
        RECT  87.888 0 87.912 0.084 ;
    END
  END q[261]
  PIN q[262]
    DIRECTION OUTPUT ;
    USE SIGNAL ;
    PORT
      LAYER M5 ;
        RECT  87.984 0 88.008 0.084 ;
    END
  END q[262]
  PIN q[263]
    DIRECTION OUTPUT ;
    USE SIGNAL ;
    PORT
      LAYER M5 ;
        RECT  88.08 0 88.104 0.084 ;
    END
  END q[263]
  PIN q[264]
    DIRECTION OUTPUT ;
    USE SIGNAL ;
    PORT
      LAYER M5 ;
        RECT  88.176 0 88.2 0.084 ;
    END
  END q[264]
  PIN q[265]
    DIRECTION OUTPUT ;
    USE SIGNAL ;
    PORT
      LAYER M5 ;
        RECT  88.272 0 88.296 0.084 ;
    END
  END q[265]
  PIN q[266]
    DIRECTION OUTPUT ;
    USE SIGNAL ;
    PORT
      LAYER M5 ;
        RECT  88.368 0 88.392 0.084 ;
    END
  END q[266]
  PIN q[267]
    DIRECTION OUTPUT ;
    USE SIGNAL ;
    PORT
      LAYER M5 ;
        RECT  88.464 0 88.488 0.084 ;
    END
  END q[267]
  PIN q[268]
    DIRECTION OUTPUT ;
    USE SIGNAL ;
    PORT
      LAYER M5 ;
        RECT  88.56 0 88.584 0.084 ;
    END
  END q[268]
  PIN q[269]
    DIRECTION OUTPUT ;
    USE SIGNAL ;
    PORT
      LAYER M5 ;
        RECT  88.656 0 88.68 0.084 ;
    END
  END q[269]
  PIN q[26]
    DIRECTION OUTPUT ;
    USE SIGNAL ;
    PORT
      LAYER M5 ;
        RECT  77.616 0 77.64 0.084 ;
    END
  END q[26]
  PIN q[270]
    DIRECTION OUTPUT ;
    USE SIGNAL ;
    PORT
      LAYER M5 ;
        RECT  88.752 0 88.776 0.084 ;
    END
  END q[270]
  PIN q[271]
    DIRECTION OUTPUT ;
    USE SIGNAL ;
    PORT
      LAYER M5 ;
        RECT  88.848 0 88.872 0.084 ;
    END
  END q[271]
  PIN q[272]
    DIRECTION OUTPUT ;
    USE SIGNAL ;
    PORT
      LAYER M5 ;
        RECT  88.944 0 88.968 0.084 ;
    END
  END q[272]
  PIN q[273]
    DIRECTION OUTPUT ;
    USE SIGNAL ;
    PORT
      LAYER M5 ;
        RECT  89.04 0 89.064 0.084 ;
    END
  END q[273]
  PIN q[274]
    DIRECTION OUTPUT ;
    USE SIGNAL ;
    PORT
      LAYER M5 ;
        RECT  89.136 0 89.16 0.084 ;
    END
  END q[274]
  PIN q[275]
    DIRECTION OUTPUT ;
    USE SIGNAL ;
    PORT
      LAYER M5 ;
        RECT  89.232 0 89.256 0.084 ;
    END
  END q[275]
  PIN q[276]
    DIRECTION OUTPUT ;
    USE SIGNAL ;
    PORT
      LAYER M5 ;
        RECT  89.328 0 89.352 0.084 ;
    END
  END q[276]
  PIN q[277]
    DIRECTION OUTPUT ;
    USE SIGNAL ;
    PORT
      LAYER M5 ;
        RECT  89.424 0 89.448 0.084 ;
    END
  END q[277]
  PIN q[278]
    DIRECTION OUTPUT ;
    USE SIGNAL ;
    PORT
      LAYER M5 ;
        RECT  89.52 0 89.544 0.084 ;
    END
  END q[278]
  PIN q[279]
    DIRECTION OUTPUT ;
    USE SIGNAL ;
    PORT
      LAYER M5 ;
        RECT  89.616 0 89.64 0.084 ;
    END
  END q[279]
  PIN q[27]
    DIRECTION OUTPUT ;
    USE SIGNAL ;
    PORT
      LAYER M5 ;
        RECT  77.712 0 77.736 0.084 ;
    END
  END q[27]
  PIN q[280]
    DIRECTION OUTPUT ;
    USE SIGNAL ;
    PORT
      LAYER M5 ;
        RECT  89.712 0 89.736 0.084 ;
    END
  END q[280]
  PIN q[281]
    DIRECTION OUTPUT ;
    USE SIGNAL ;
    PORT
      LAYER M5 ;
        RECT  73.68 0 73.704 0.084 ;
    END
  END q[281]
  PIN q[282]
    DIRECTION OUTPUT ;
    USE SIGNAL ;
    PORT
      LAYER M5 ;
        RECT  73.776 0 73.8 0.084 ;
    END
  END q[282]
  PIN q[283]
    DIRECTION OUTPUT ;
    USE SIGNAL ;
    PORT
      LAYER M5 ;
        RECT  73.872 0 73.896 0.084 ;
    END
  END q[283]
  PIN q[284]
    DIRECTION OUTPUT ;
    USE SIGNAL ;
    PORT
      LAYER M5 ;
        RECT  73.968 0 73.992 0.084 ;
    END
  END q[284]
  PIN q[285]
    DIRECTION OUTPUT ;
    USE SIGNAL ;
    PORT
      LAYER M5 ;
        RECT  74.064 0 74.088 0.084 ;
    END
  END q[285]
  PIN q[286]
    DIRECTION OUTPUT ;
    USE SIGNAL ;
    PORT
      LAYER M5 ;
        RECT  74.16 0 74.184 0.084 ;
    END
  END q[286]
  PIN q[287]
    DIRECTION OUTPUT ;
    USE SIGNAL ;
    PORT
      LAYER M5 ;
        RECT  74.256 0 74.28 0.084 ;
    END
  END q[287]
  PIN q[288]
    DIRECTION OUTPUT ;
    USE SIGNAL ;
    PORT
      LAYER M5 ;
        RECT  74.352 0 74.376 0.084 ;
    END
  END q[288]
  PIN q[289]
    DIRECTION OUTPUT ;
    USE SIGNAL ;
    PORT
      LAYER M5 ;
        RECT  74.448 0 74.472 0.084 ;
    END
  END q[289]
  PIN q[28]
    DIRECTION OUTPUT ;
    USE SIGNAL ;
    PORT
      LAYER M5 ;
        RECT  77.808 0 77.832 0.084 ;
    END
  END q[28]
  PIN q[290]
    DIRECTION OUTPUT ;
    USE SIGNAL ;
    PORT
      LAYER M5 ;
        RECT  74.544 0 74.568 0.084 ;
    END
  END q[290]
  PIN q[291]
    DIRECTION OUTPUT ;
    USE SIGNAL ;
    PORT
      LAYER M5 ;
        RECT  74.64 0 74.664 0.084 ;
    END
  END q[291]
  PIN q[292]
    DIRECTION OUTPUT ;
    USE SIGNAL ;
    PORT
      LAYER M5 ;
        RECT  74.736 0 74.76 0.084 ;
    END
  END q[292]
  PIN q[293]
    DIRECTION OUTPUT ;
    USE SIGNAL ;
    PORT
      LAYER M5 ;
        RECT  74.832 0 74.856 0.084 ;
    END
  END q[293]
  PIN q[294]
    DIRECTION OUTPUT ;
    USE SIGNAL ;
    PORT
      LAYER M5 ;
        RECT  74.928 0 74.952 0.084 ;
    END
  END q[294]
  PIN q[295]
    DIRECTION OUTPUT ;
    USE SIGNAL ;
    PORT
      LAYER M5 ;
        RECT  75.024 0 75.048 0.084 ;
    END
  END q[295]
  PIN q[296]
    DIRECTION OUTPUT ;
    USE SIGNAL ;
    PORT
      LAYER M5 ;
        RECT  75.12 0 75.144 0.084 ;
    END
  END q[296]
  PIN q[297]
    DIRECTION OUTPUT ;
    USE SIGNAL ;
    PORT
      LAYER M5 ;
        RECT  75.216 0 75.24 0.084 ;
    END
  END q[297]
  PIN q[298]
    DIRECTION OUTPUT ;
    USE SIGNAL ;
    PORT
      LAYER M5 ;
        RECT  75.312 0 75.336 0.084 ;
    END
  END q[298]
  PIN q[299]
    DIRECTION OUTPUT ;
    USE SIGNAL ;
    PORT
      LAYER M5 ;
        RECT  75.408 0 75.432 0.084 ;
    END
  END q[299]
  PIN q[29]
    DIRECTION OUTPUT ;
    USE SIGNAL ;
    PORT
      LAYER M5 ;
        RECT  77.904 0 77.928 0.084 ;
    END
  END q[29]
  PIN q[2]
    DIRECTION OUTPUT ;
    USE SIGNAL ;
    PORT
      LAYER M5 ;
        RECT  81.456 0 81.48 0.084 ;
    END
  END q[2]
  PIN q[300]
    DIRECTION OUTPUT ;
    USE SIGNAL ;
    PORT
      LAYER M5 ;
        RECT  75.504 0 75.528 0.084 ;
    END
  END q[300]
  PIN q[301]
    DIRECTION OUTPUT ;
    USE SIGNAL ;
    PORT
      LAYER M5 ;
        RECT  75.6 0 75.624 0.084 ;
    END
  END q[301]
  PIN q[302]
    DIRECTION OUTPUT ;
    USE SIGNAL ;
    PORT
      LAYER M5 ;
        RECT  75.696 0 75.72 0.084 ;
    END
  END q[302]
  PIN q[303]
    DIRECTION OUTPUT ;
    USE SIGNAL ;
    PORT
      LAYER M5 ;
        RECT  75.792 0 75.816 0.084 ;
    END
  END q[303]
  PIN q[304]
    DIRECTION OUTPUT ;
    USE SIGNAL ;
    PORT
      LAYER M5 ;
        RECT  75.888 0 75.912 0.084 ;
    END
  END q[304]
  PIN q[305]
    DIRECTION OUTPUT ;
    USE SIGNAL ;
    PORT
      LAYER M5 ;
        RECT  75.984 0 76.008 0.084 ;
    END
  END q[305]
  PIN q[306]
    DIRECTION OUTPUT ;
    USE SIGNAL ;
    PORT
      LAYER M5 ;
        RECT  76.08 0 76.104 0.084 ;
    END
  END q[306]
  PIN q[307]
    DIRECTION OUTPUT ;
    USE SIGNAL ;
    PORT
      LAYER M5 ;
        RECT  76.176 0 76.2 0.084 ;
    END
  END q[307]
  PIN q[308]
    DIRECTION OUTPUT ;
    USE SIGNAL ;
    PORT
      LAYER M5 ;
        RECT  76.272 0 76.296 0.084 ;
    END
  END q[308]
  PIN q[309]
    DIRECTION OUTPUT ;
    USE SIGNAL ;
    PORT
      LAYER M5 ;
        RECT  76.368 0 76.392 0.084 ;
    END
  END q[309]
  PIN q[30]
    DIRECTION OUTPUT ;
    USE SIGNAL ;
    PORT
      LAYER M5 ;
        RECT  78 0 78.024 0.084 ;
    END
  END q[30]
  PIN q[310]
    DIRECTION OUTPUT ;
    USE SIGNAL ;
    PORT
      LAYER M5 ;
        RECT  76.464 0 76.488 0.084 ;
    END
  END q[310]
  PIN q[311]
    DIRECTION OUTPUT ;
    USE SIGNAL ;
    PORT
      LAYER M5 ;
        RECT  76.56 0 76.584 0.084 ;
    END
  END q[311]
  PIN q[312]
    DIRECTION OUTPUT ;
    USE SIGNAL ;
    PORT
      LAYER M5 ;
        RECT  76.656 0 76.68 0.084 ;
    END
  END q[312]
  PIN q[313]
    DIRECTION OUTPUT ;
    USE SIGNAL ;
    PORT
      LAYER M5 ;
        RECT  48.336 0 48.36 0.084 ;
    END
  END q[313]
  PIN q[314]
    DIRECTION OUTPUT ;
    USE SIGNAL ;
    PORT
      LAYER M5 ;
        RECT  48.432 0 48.456 0.084 ;
    END
  END q[314]
  PIN q[315]
    DIRECTION OUTPUT ;
    USE SIGNAL ;
    PORT
      LAYER M5 ;
        RECT  48.528 0 48.552 0.084 ;
    END
  END q[315]
  PIN q[316]
    DIRECTION OUTPUT ;
    USE SIGNAL ;
    PORT
      LAYER M5 ;
        RECT  48.624 0 48.648 0.084 ;
    END
  END q[316]
  PIN q[317]
    DIRECTION OUTPUT ;
    USE SIGNAL ;
    PORT
      LAYER M5 ;
        RECT  48.72 0 48.744 0.084 ;
    END
  END q[317]
  PIN q[318]
    DIRECTION OUTPUT ;
    USE SIGNAL ;
    PORT
      LAYER M5 ;
        RECT  48.816 0 48.84 0.084 ;
    END
  END q[318]
  PIN q[319]
    DIRECTION OUTPUT ;
    USE SIGNAL ;
    PORT
      LAYER M5 ;
        RECT  48.912 0 48.936 0.084 ;
    END
  END q[319]
  PIN q[31]
    DIRECTION OUTPUT ;
    USE SIGNAL ;
    PORT
      LAYER M5 ;
        RECT  78.096 0 78.12 0.084 ;
    END
  END q[31]
  PIN q[32]
    DIRECTION OUTPUT ;
    USE SIGNAL ;
    PORT
      LAYER M5 ;
        RECT  78.192 0 78.216 0.084 ;
    END
  END q[32]
  PIN q[33]
    DIRECTION OUTPUT ;
    USE SIGNAL ;
    PORT
      LAYER M5 ;
        RECT  78.288 0 78.312 0.084 ;
    END
  END q[33]
  PIN q[34]
    DIRECTION OUTPUT ;
    USE SIGNAL ;
    PORT
      LAYER M5 ;
        RECT  78.384 0 78.408 0.084 ;
    END
  END q[34]
  PIN q[35]
    DIRECTION OUTPUT ;
    USE SIGNAL ;
    PORT
      LAYER M5 ;
        RECT  78.48 0 78.504 0.084 ;
    END
  END q[35]
  PIN q[36]
    DIRECTION OUTPUT ;
    USE SIGNAL ;
    PORT
      LAYER M5 ;
        RECT  78.576 0 78.6 0.084 ;
    END
  END q[36]
  PIN q[37]
    DIRECTION OUTPUT ;
    USE SIGNAL ;
    PORT
      LAYER M5 ;
        RECT  78.672 0 78.696 0.084 ;
    END
  END q[37]
  PIN q[38]
    DIRECTION OUTPUT ;
    USE SIGNAL ;
    PORT
      LAYER M5 ;
        RECT  78.768 0 78.792 0.084 ;
    END
  END q[38]
  PIN q[39]
    DIRECTION OUTPUT ;
    USE SIGNAL ;
    PORT
      LAYER M5 ;
        RECT  78.864 0 78.888 0.084 ;
    END
  END q[39]
  PIN q[3]
    DIRECTION OUTPUT ;
    USE SIGNAL ;
    PORT
      LAYER M5 ;
        RECT  81.552 0 81.576 0.084 ;
    END
  END q[3]
  PIN q[40]
    DIRECTION OUTPUT ;
    USE SIGNAL ;
    PORT
      LAYER M5 ;
        RECT  78.96 0 78.984 0.084 ;
    END
  END q[40]
  PIN q[41]
    DIRECTION OUTPUT ;
    USE SIGNAL ;
    PORT
      LAYER M5 ;
        RECT  79.056 0 79.08 0.084 ;
    END
  END q[41]
  PIN q[42]
    DIRECTION OUTPUT ;
    USE SIGNAL ;
    PORT
      LAYER M5 ;
        RECT  79.152 0 79.176 0.084 ;
    END
  END q[42]
  PIN q[43]
    DIRECTION OUTPUT ;
    USE SIGNAL ;
    PORT
      LAYER M5 ;
        RECT  79.248 0 79.272 0.084 ;
    END
  END q[43]
  PIN q[44]
    DIRECTION OUTPUT ;
    USE SIGNAL ;
    PORT
      LAYER M5 ;
        RECT  79.344 0 79.368 0.084 ;
    END
  END q[44]
  PIN q[45]
    DIRECTION OUTPUT ;
    USE SIGNAL ;
    PORT
      LAYER M5 ;
        RECT  79.44 0 79.464 0.084 ;
    END
  END q[45]
  PIN q[46]
    DIRECTION OUTPUT ;
    USE SIGNAL ;
    PORT
      LAYER M5 ;
        RECT  79.536 0 79.56 0.084 ;
    END
  END q[46]
  PIN q[47]
    DIRECTION OUTPUT ;
    USE SIGNAL ;
    PORT
      LAYER M5 ;
        RECT  79.632 0 79.656 0.084 ;
    END
  END q[47]
  PIN q[48]
    DIRECTION OUTPUT ;
    USE SIGNAL ;
    PORT
      LAYER M5 ;
        RECT  79.728 0 79.752 0.084 ;
    END
  END q[48]
  PIN q[49]
    DIRECTION OUTPUT ;
    USE SIGNAL ;
    PORT
      LAYER M5 ;
        RECT  79.824 0 79.848 0.084 ;
    END
  END q[49]
  PIN q[4]
    DIRECTION OUTPUT ;
    USE SIGNAL ;
    PORT
      LAYER M5 ;
        RECT  81.648 0 81.672 0.084 ;
    END
  END q[4]
  PIN q[50]
    DIRECTION OUTPUT ;
    USE SIGNAL ;
    PORT
      LAYER M5 ;
        RECT  79.92 0 79.944 0.084 ;
    END
  END q[50]
  PIN q[51]
    DIRECTION OUTPUT ;
    USE SIGNAL ;
    PORT
      LAYER M5 ;
        RECT  80.016 0 80.04 0.084 ;
    END
  END q[51]
  PIN q[52]
    DIRECTION OUTPUT ;
    USE SIGNAL ;
    PORT
      LAYER M5 ;
        RECT  80.112 0 80.136 0.084 ;
    END
  END q[52]
  PIN q[53]
    DIRECTION OUTPUT ;
    USE SIGNAL ;
    PORT
      LAYER M5 ;
        RECT  80.208 0 80.232 0.084 ;
    END
  END q[53]
  PIN q[54]
    DIRECTION OUTPUT ;
    USE SIGNAL ;
    PORT
      LAYER M5 ;
        RECT  80.304 0 80.328 0.084 ;
    END
  END q[54]
  PIN q[55]
    DIRECTION OUTPUT ;
    USE SIGNAL ;
    PORT
      LAYER M5 ;
        RECT  80.4 0 80.424 0.084 ;
    END
  END q[55]
  PIN q[56]
    DIRECTION OUTPUT ;
    USE SIGNAL ;
    PORT
      LAYER M5 ;
        RECT  80.496 0 80.52 0.084 ;
    END
  END q[56]
  PIN q[57]
    DIRECTION OUTPUT ;
    USE SIGNAL ;
    PORT
      LAYER M5 ;
        RECT  9.936 0 9.96 0.084 ;
    END
  END q[57]
  PIN q[58]
    DIRECTION OUTPUT ;
    USE SIGNAL ;
    PORT
      LAYER M5 ;
        RECT  10.032 0 10.056 0.084 ;
    END
  END q[58]
  PIN q[59]
    DIRECTION OUTPUT ;
    USE SIGNAL ;
    PORT
      LAYER M5 ;
        RECT  10.128 0 10.152 0.084 ;
    END
  END q[59]
  PIN q[5]
    DIRECTION OUTPUT ;
    USE SIGNAL ;
    PORT
      LAYER M5 ;
        RECT  81.744 0 81.768 0.084 ;
    END
  END q[5]
  PIN q[60]
    DIRECTION OUTPUT ;
    USE SIGNAL ;
    PORT
      LAYER M5 ;
        RECT  10.224 0 10.248 0.084 ;
    END
  END q[60]
  PIN q[61]
    DIRECTION OUTPUT ;
    USE SIGNAL ;
    PORT
      LAYER M5 ;
        RECT  10.32 0 10.344 0.084 ;
    END
  END q[61]
  PIN q[62]
    DIRECTION OUTPUT ;
    USE SIGNAL ;
    PORT
      LAYER M5 ;
        RECT  10.416 0 10.44 0.084 ;
    END
  END q[62]
  PIN q[63]
    DIRECTION OUTPUT ;
    USE SIGNAL ;
    PORT
      LAYER M5 ;
        RECT  10.512 0 10.536 0.084 ;
    END
  END q[63]
  PIN q[64]
    DIRECTION OUTPUT ;
    USE SIGNAL ;
    PORT
      LAYER M5 ;
        RECT  10.608 0 10.632 0.084 ;
    END
  END q[64]
  PIN q[65]
    DIRECTION OUTPUT ;
    USE SIGNAL ;
    PORT
      LAYER M5 ;
        RECT  10.704 0 10.728 0.084 ;
    END
  END q[65]
  PIN q[66]
    DIRECTION OUTPUT ;
    USE SIGNAL ;
    PORT
      LAYER M5 ;
        RECT  10.8 0 10.824 0.084 ;
    END
  END q[66]
  PIN q[67]
    DIRECTION OUTPUT ;
    USE SIGNAL ;
    PORT
      LAYER M5 ;
        RECT  10.896 0 10.92 0.084 ;
    END
  END q[67]
  PIN q[68]
    DIRECTION OUTPUT ;
    USE SIGNAL ;
    PORT
      LAYER M5 ;
        RECT  10.992 0 11.016 0.084 ;
    END
  END q[68]
  PIN q[69]
    DIRECTION OUTPUT ;
    USE SIGNAL ;
    PORT
      LAYER M5 ;
        RECT  11.088 0 11.112 0.084 ;
    END
  END q[69]
  PIN q[6]
    DIRECTION OUTPUT ;
    USE SIGNAL ;
    PORT
      LAYER M5 ;
        RECT  81.84 0 81.864 0.084 ;
    END
  END q[6]
  PIN q[70]
    DIRECTION OUTPUT ;
    USE SIGNAL ;
    PORT
      LAYER M5 ;
        RECT  11.184 0 11.208 0.084 ;
    END
  END q[70]
  PIN q[71]
    DIRECTION OUTPUT ;
    USE SIGNAL ;
    PORT
      LAYER M5 ;
        RECT  11.28 0 11.304 0.084 ;
    END
  END q[71]
  PIN q[72]
    DIRECTION OUTPUT ;
    USE SIGNAL ;
    PORT
      LAYER M5 ;
        RECT  11.376 0 11.4 0.084 ;
    END
  END q[72]
  PIN q[73]
    DIRECTION OUTPUT ;
    USE SIGNAL ;
    PORT
      LAYER M5 ;
        RECT  11.472 0 11.496 0.084 ;
    END
  END q[73]
  PIN q[74]
    DIRECTION OUTPUT ;
    USE SIGNAL ;
    PORT
      LAYER M5 ;
        RECT  11.568 0 11.592 0.084 ;
    END
  END q[74]
  PIN q[75]
    DIRECTION OUTPUT ;
    USE SIGNAL ;
    PORT
      LAYER M5 ;
        RECT  11.664 0 11.688 0.084 ;
    END
  END q[75]
  PIN q[76]
    DIRECTION OUTPUT ;
    USE SIGNAL ;
    PORT
      LAYER M5 ;
        RECT  11.76 0 11.784 0.084 ;
    END
  END q[76]
  PIN q[77]
    DIRECTION OUTPUT ;
    USE SIGNAL ;
    PORT
      LAYER M5 ;
        RECT  11.856 0 11.88 0.084 ;
    END
  END q[77]
  PIN q[78]
    DIRECTION OUTPUT ;
    USE SIGNAL ;
    PORT
      LAYER M5 ;
        RECT  11.952 0 11.976 0.084 ;
    END
  END q[78]
  PIN q[79]
    DIRECTION OUTPUT ;
    USE SIGNAL ;
    PORT
      LAYER M5 ;
        RECT  12.048 0 12.072 0.084 ;
    END
  END q[79]
  PIN q[7]
    DIRECTION OUTPUT ;
    USE SIGNAL ;
    PORT
      LAYER M5 ;
        RECT  81.936 0 81.96 0.084 ;
    END
  END q[7]
  PIN q[80]
    DIRECTION OUTPUT ;
    USE SIGNAL ;
    PORT
      LAYER M5 ;
        RECT  12.144 0 12.168 0.084 ;
    END
  END q[80]
  PIN q[81]
    DIRECTION OUTPUT ;
    USE SIGNAL ;
    PORT
      LAYER M5 ;
        RECT  12.24 0 12.264 0.084 ;
    END
  END q[81]
  PIN q[82]
    DIRECTION OUTPUT ;
    USE SIGNAL ;
    PORT
      LAYER M5 ;
        RECT  12.336 0 12.36 0.084 ;
    END
  END q[82]
  PIN q[83]
    DIRECTION OUTPUT ;
    USE SIGNAL ;
    PORT
      LAYER M5 ;
        RECT  12.432 0 12.456 0.084 ;
    END
  END q[83]
  PIN q[84]
    DIRECTION OUTPUT ;
    USE SIGNAL ;
    PORT
      LAYER M5 ;
        RECT  12.528 0 12.552 0.084 ;
    END
  END q[84]
  PIN q[85]
    DIRECTION OUTPUT ;
    USE SIGNAL ;
    PORT
      LAYER M5 ;
        RECT  12.624 0 12.648 0.084 ;
    END
  END q[85]
  PIN q[86]
    DIRECTION OUTPUT ;
    USE SIGNAL ;
    PORT
      LAYER M5 ;
        RECT  12.72 0 12.744 0.084 ;
    END
  END q[86]
  PIN q[87]
    DIRECTION OUTPUT ;
    USE SIGNAL ;
    PORT
      LAYER M5 ;
        RECT  12.816 0 12.84 0.084 ;
    END
  END q[87]
  PIN q[88]
    DIRECTION OUTPUT ;
    USE SIGNAL ;
    PORT
      LAYER M5 ;
        RECT  12.912 0 12.936 0.084 ;
    END
  END q[88]
  PIN q[89]
    DIRECTION OUTPUT ;
    USE SIGNAL ;
    PORT
      LAYER M5 ;
        RECT  29.136 0 29.16 0.084 ;
    END
  END q[89]
  PIN q[8]
    DIRECTION OUTPUT ;
    USE SIGNAL ;
    PORT
      LAYER M5 ;
        RECT  82.032 0 82.056 0.084 ;
    END
  END q[8]
  PIN q[90]
    DIRECTION OUTPUT ;
    USE SIGNAL ;
    PORT
      LAYER M5 ;
        RECT  29.232 0 29.256 0.084 ;
    END
  END q[90]
  PIN q[91]
    DIRECTION OUTPUT ;
    USE SIGNAL ;
    PORT
      LAYER M5 ;
        RECT  29.328 0 29.352 0.084 ;
    END
  END q[91]
  PIN q[92]
    DIRECTION OUTPUT ;
    USE SIGNAL ;
    PORT
      LAYER M5 ;
        RECT  29.424 0 29.448 0.084 ;
    END
  END q[92]
  PIN q[93]
    DIRECTION OUTPUT ;
    USE SIGNAL ;
    PORT
      LAYER M5 ;
        RECT  29.52 0 29.544 0.084 ;
    END
  END q[93]
  PIN q[94]
    DIRECTION OUTPUT ;
    USE SIGNAL ;
    PORT
      LAYER M5 ;
        RECT  29.616 0 29.64 0.084 ;
    END
  END q[94]
  PIN q[95]
    DIRECTION OUTPUT ;
    USE SIGNAL ;
    PORT
      LAYER M5 ;
        RECT  29.712 0 29.736 0.084 ;
    END
  END q[95]
  PIN q[96]
    DIRECTION OUTPUT ;
    USE SIGNAL ;
    PORT
      LAYER M5 ;
        RECT  29.808 0 29.832 0.084 ;
    END
  END q[96]
  PIN q[97]
    DIRECTION OUTPUT ;
    USE SIGNAL ;
    PORT
      LAYER M5 ;
        RECT  29.904 0 29.928 0.084 ;
    END
  END q[97]
  PIN q[98]
    DIRECTION OUTPUT ;
    USE SIGNAL ;
    PORT
      LAYER M5 ;
        RECT  30 0 30.024 0.084 ;
    END
  END q[98]
  PIN q[99]
    DIRECTION OUTPUT ;
    USE SIGNAL ;
    PORT
      LAYER M5 ;
        RECT  30.096 0 30.12 0.084 ;
    END
  END q[99]
  PIN q[9]
    DIRECTION OUTPUT ;
    USE SIGNAL ;
    PORT
      LAYER M5 ;
        RECT  82.128 0 82.152 0.084 ;
    END
  END q[9]
  PIN rst_e
    DIRECTION INPUT ;
    USE SIGNAL ;
    PORT
      LAYER M5 ;
        RECT  49.008 0 49.032 0.084 ;
    END
  END rst_e
  PIN rst_p
    DIRECTION INPUT ;
    USE SIGNAL ;
    PORT
      LAYER M5 ;
        RECT  49.104 0 49.128 0.084 ;
    END
  END rst_p
  PIN v_bad
    DIRECTION OUTPUT ;
    USE SIGNAL ;
    PORT
      LAYER M5 ;
        RECT  49.2 0 49.224 0.084 ;
    END
  END v_bad
  PIN v_cbad
    DIRECTION OUTPUT ;
    USE SIGNAL ;
    PORT
      LAYER M5 ;
        RECT  49.296 0 49.32 0.084 ;
    END
  END v_cbad
  PIN v_ce
    DIRECTION OUTPUT ;
    USE SIGNAL ;
    PORT
      LAYER M5 ;
        RECT  49.392 0 49.416 0.084 ;
    END
  END v_ce
  PIN v_clean
    DIRECTION OUTPUT ;
    USE SIGNAL ;
    PORT
      LAYER M5 ;
        RECT  49.488 0 49.512 0.084 ;
    END
  END v_clean
  PIN v_same
    DIRECTION OUTPUT ;
    USE SIGNAL ;
    PORT
      LAYER M5 ;
        RECT  49.584 0 49.608 0.084 ;
    END
  END v_same
  PIN v_ue
    DIRECTION OUTPUT ;
    USE SIGNAL ;
    PORT
      LAYER M5 ;
        RECT  49.68 0 49.704 0.084 ;
    END
  END v_ue
  PIN VDD
    DIRECTION INOUT ;
    USE POWER ;
    PORT
      LAYER M5 ;
        RECT  83.592 2.151 83.712 56.169 ;
        RECT  78.192 2.151 78.312 56.169 ;
        RECT  72.792 2.151 72.912 56.169 ;
        RECT  67.392 2.151 67.512 56.169 ;
        RECT  61.992 2.151 62.112 56.169 ;
        RECT  56.592 2.151 56.712 56.169 ;
        RECT  51.192 2.151 51.312 56.169 ;
        RECT  45.792 2.151 45.912 56.169 ;
        RECT  40.392 2.151 40.512 56.169 ;
        RECT  34.992 2.151 35.112 56.169 ;
        RECT  29.592 2.151 29.712 56.169 ;
        RECT  24.192 2.151 24.312 56.169 ;
        RECT  18.792 2.151 18.912 56.169 ;
        RECT  13.392 2.151 13.512 56.169 ;
        RECT  7.992 2.151 8.112 56.169 ;
        RECT  2.592 2.151 2.712 56.169 ;
    END
  END VDD
  PIN VSS
    DIRECTION INOUT ;
    USE GROUND ;
    PORT
      LAYER M5 ;
        RECT  83.4 2.137 83.52 56.183 ;
        RECT  78 2.137 78.12 56.183 ;
        RECT  72.6 2.137 72.72 56.183 ;
        RECT  67.2 2.137 67.32 56.183 ;
        RECT  61.8 2.137 61.92 56.183 ;
        RECT  56.4 2.137 56.52 56.183 ;
        RECT  51 2.137 51.12 56.183 ;
        RECT  45.6 2.137 45.72 56.183 ;
        RECT  40.2 2.137 40.32 56.183 ;
        RECT  34.8 2.137 34.92 56.183 ;
        RECT  29.4 2.137 29.52 56.183 ;
        RECT  24 2.137 24.12 56.183 ;
        RECT  18.6 2.137 18.72 56.183 ;
        RECT  13.2 2.137 13.32 56.183 ;
        RECT  7.8 2.137 7.92 56.183 ;
        RECT  2.4 2.137 2.52 56.183 ;
    END
  END VSS
  OBS
    LAYER RVTN ;
     RECT  2.16 2.16 88.56 2.295 ;
     RECT  2.16 2.565 88.56 2.835 ;
     RECT  2.16 3.105 88.56 3.375 ;
     RECT  2.16 3.645 88.56 3.915 ;
     RECT  2.16 4.185 88.56 4.455 ;
     RECT  2.16 4.725 88.56 4.995 ;
     RECT  2.16 5.265 88.56 5.535 ;
     RECT  2.16 5.805 88.56 6.075 ;
     RECT  2.16 6.345 88.56 6.615 ;
     RECT  2.16 6.885 88.56 7.155 ;
     RECT  2.16 7.425 88.56 7.695 ;
     RECT  2.16 7.965 88.56 8.235 ;
     RECT  2.16 8.505 88.56 8.775 ;
     RECT  2.16 9.045 88.56 9.315 ;
     RECT  2.16 9.585 88.56 9.855 ;
     RECT  2.16 10.125 88.56 10.395 ;
     RECT  2.16 10.665 88.56 10.935 ;
     RECT  2.16 11.205 88.56 11.475 ;
     RECT  2.16 11.745 88.56 12.015 ;
     RECT  2.16 12.285 88.56 12.555 ;
     RECT  2.16 12.825 88.56 13.095 ;
     RECT  2.16 13.365 88.56 13.635 ;
     RECT  2.16 13.905 88.56 14.175 ;
     RECT  2.16 14.445 88.56 14.715 ;
     RECT  2.16 14.985 88.56 15.255 ;
     RECT  2.16 15.525 88.56 15.795 ;
     RECT  2.16 16.065 88.56 16.335 ;
     RECT  2.16 16.605 88.56 16.875 ;
     RECT  2.16 17.145 88.56 17.415 ;
     RECT  2.16 17.685 88.56 17.955 ;
     RECT  2.16 18.225 88.56 18.495 ;
     RECT  2.16 18.765 88.56 19.035 ;
     RECT  2.16 19.305 88.56 19.575 ;
     RECT  2.16 19.845 88.56 20.115 ;
     RECT  2.16 20.385 88.56 20.655 ;
     RECT  2.16 20.925 88.56 21.195 ;
     RECT  2.16 21.465 88.56 21.735 ;
     RECT  2.16 22.005 88.56 22.275 ;
     RECT  2.16 22.545 88.56 22.815 ;
     RECT  2.16 23.085 88.56 23.355 ;
     RECT  2.16 23.625 88.56 23.895 ;
     RECT  2.16 24.165 88.56 24.435 ;
     RECT  2.16 24.705 88.56 24.975 ;
     RECT  2.16 25.245 88.56 25.515 ;
     RECT  2.16 25.785 88.56 26.055 ;
     RECT  2.16 26.325 88.56 26.595 ;
     RECT  2.16 26.865 88.56 27.135 ;
     RECT  2.16 27.405 88.56 27.675 ;
     RECT  2.16 27.945 88.56 28.215 ;
     RECT  2.16 28.485 88.56 28.755 ;
     RECT  2.16 29.025 88.56 29.295 ;
     RECT  2.16 29.565 88.56 29.835 ;
     RECT  2.16 30.105 88.56 30.375 ;
     RECT  2.16 30.645 88.56 30.915 ;
     RECT  2.16 31.185 88.56 31.455 ;
     RECT  2.16 31.725 88.56 31.995 ;
     RECT  2.16 32.265 88.56 32.535 ;
     RECT  2.16 32.805 88.56 33.075 ;
     RECT  2.16 33.345 88.56 33.615 ;
     RECT  2.16 33.885 88.56 34.155 ;
     RECT  2.16 34.425 88.56 34.695 ;
     RECT  2.16 34.965 88.56 35.235 ;
     RECT  2.16 35.505 88.56 35.775 ;
     RECT  2.16 36.045 88.56 36.315 ;
     RECT  2.16 36.585 88.56 36.855 ;
     RECT  2.16 37.125 88.56 37.395 ;
     RECT  2.16 37.665 88.56 37.935 ;
     RECT  2.16 38.205 88.56 38.475 ;
     RECT  2.16 38.745 88.56 39.015 ;
     RECT  2.16 39.285 88.56 39.555 ;
     RECT  2.16 39.825 88.56 40.095 ;
     RECT  2.16 40.365 88.56 40.635 ;
     RECT  2.16 40.905 88.56 41.175 ;
     RECT  2.16 41.445 88.56 41.715 ;
     RECT  2.16 41.985 88.56 42.255 ;
     RECT  2.16 42.525 88.56 42.795 ;
     RECT  2.16 43.065 88.56 43.335 ;
     RECT  2.16 43.605 88.56 43.875 ;
     RECT  2.16 44.145 88.56 44.415 ;
     RECT  2.16 44.685 88.56 44.955 ;
     RECT  2.16 45.225 88.56 45.495 ;
     RECT  2.16 45.765 88.56 46.035 ;
     RECT  2.16 46.305 88.56 46.575 ;
     RECT  2.16 46.845 88.56 47.115 ;
     RECT  2.16 47.385 88.56 47.655 ;
     RECT  2.16 47.925 88.56 48.195 ;
     RECT  2.16 48.465 88.56 48.735 ;
     RECT  2.16 49.005 88.56 49.275 ;
     RECT  2.16 49.545 88.56 49.815 ;
     RECT  2.16 50.085 88.56 50.355 ;
     RECT  2.16 50.625 88.56 50.895 ;
     RECT  2.16 51.165 88.56 51.435 ;
     RECT  2.16 51.705 88.56 51.975 ;
     RECT  2.16 52.245 88.56 52.515 ;
     RECT  2.16 52.785 88.56 53.055 ;
     RECT  2.16 53.325 88.56 53.595 ;
     RECT  2.16 53.865 88.56 54.135 ;
     RECT  2.16 54.405 88.56 54.675 ;
     RECT  2.16 54.945 88.56 55.215 ;
     RECT  2.16 55.485 88.56 55.755 ;
     RECT  2.16 56.025 88.56 56.16 ;
    LAYER RVTP ;
     RECT  2.16 2.295 88.56 2.565 ;
     RECT  2.16 2.835 88.56 3.105 ;
     RECT  2.16 3.375 88.56 3.645 ;
     RECT  2.16 3.915 88.56 4.185 ;
     RECT  2.16 4.455 88.56 4.725 ;
     RECT  2.16 4.995 88.56 5.265 ;
     RECT  2.16 5.535 88.56 5.805 ;
     RECT  2.16 6.075 88.56 6.345 ;
     RECT  2.16 6.615 88.56 6.885 ;
     RECT  2.16 7.155 88.56 7.425 ;
     RECT  2.16 7.695 88.56 7.965 ;
     RECT  2.16 8.235 88.56 8.505 ;
     RECT  2.16 8.775 88.56 9.045 ;
     RECT  2.16 9.315 88.56 9.585 ;
     RECT  2.16 9.855 88.56 10.125 ;
     RECT  2.16 10.395 88.56 10.665 ;
     RECT  2.16 10.935 88.56 11.205 ;
     RECT  2.16 11.475 88.56 11.745 ;
     RECT  2.16 12.015 88.56 12.285 ;
     RECT  2.16 12.555 88.56 12.825 ;
     RECT  2.16 13.095 88.56 13.365 ;
     RECT  2.16 13.635 88.56 13.905 ;
     RECT  2.16 14.175 88.56 14.445 ;
     RECT  2.16 14.715 88.56 14.985 ;
     RECT  2.16 15.255 88.56 15.525 ;
     RECT  2.16 15.795 88.56 16.065 ;
     RECT  2.16 16.335 88.56 16.605 ;
     RECT  2.16 16.875 88.56 17.145 ;
     RECT  2.16 17.415 88.56 17.685 ;
     RECT  2.16 17.955 88.56 18.225 ;
     RECT  2.16 18.495 88.56 18.765 ;
     RECT  2.16 19.035 88.56 19.305 ;
     RECT  2.16 19.575 88.56 19.845 ;
     RECT  2.16 20.115 88.56 20.385 ;
     RECT  2.16 20.655 88.56 20.925 ;
     RECT  2.16 21.195 88.56 21.465 ;
     RECT  2.16 21.735 88.56 22.005 ;
     RECT  2.16 22.275 88.56 22.545 ;
     RECT  2.16 22.815 88.56 23.085 ;
     RECT  2.16 23.355 88.56 23.625 ;
     RECT  2.16 23.895 88.56 24.165 ;
     RECT  2.16 24.435 88.56 24.705 ;
     RECT  2.16 24.975 88.56 25.245 ;
     RECT  2.16 25.515 88.56 25.785 ;
     RECT  2.16 26.055 88.56 26.325 ;
     RECT  2.16 26.595 88.56 26.865 ;
     RECT  2.16 27.135 88.56 27.405 ;
     RECT  2.16 27.675 88.56 27.945 ;
     RECT  2.16 28.215 88.56 28.485 ;
     RECT  2.16 28.755 88.56 29.025 ;
     RECT  2.16 29.295 88.56 29.565 ;
     RECT  2.16 29.835 88.56 30.105 ;
     RECT  2.16 30.375 88.56 30.645 ;
     RECT  2.16 30.915 88.56 31.185 ;
     RECT  2.16 31.455 88.56 31.725 ;
     RECT  2.16 31.995 88.56 32.265 ;
     RECT  2.16 32.535 88.56 32.805 ;
     RECT  2.16 33.075 88.56 33.345 ;
     RECT  2.16 33.615 88.56 33.885 ;
     RECT  2.16 34.155 88.56 34.425 ;
     RECT  2.16 34.695 88.56 34.965 ;
     RECT  2.16 35.235 88.56 35.505 ;
     RECT  2.16 35.775 88.56 36.045 ;
     RECT  2.16 36.315 88.56 36.585 ;
     RECT  2.16 36.855 88.56 37.125 ;
     RECT  2.16 37.395 88.56 37.665 ;
     RECT  2.16 37.935 88.56 38.205 ;
     RECT  2.16 38.475 88.56 38.745 ;
     RECT  2.16 39.015 88.56 39.285 ;
     RECT  2.16 39.555 88.56 39.825 ;
     RECT  2.16 40.095 88.56 40.365 ;
     RECT  2.16 40.635 88.56 40.905 ;
     RECT  2.16 41.175 88.56 41.445 ;
     RECT  2.16 41.715 88.56 41.985 ;
     RECT  2.16 42.255 88.56 42.525 ;
     RECT  2.16 42.795 88.56 43.065 ;
     RECT  2.16 43.335 88.56 43.605 ;
     RECT  2.16 43.875 88.56 44.145 ;
     RECT  2.16 44.415 88.56 44.685 ;
     RECT  2.16 44.955 88.56 45.225 ;
     RECT  2.16 45.495 88.56 45.765 ;
     RECT  2.16 46.035 88.56 46.305 ;
     RECT  2.16 46.575 88.56 46.845 ;
     RECT  2.16 47.115 88.56 47.385 ;
     RECT  2.16 47.655 88.56 47.925 ;
     RECT  2.16 48.195 88.56 48.465 ;
     RECT  2.16 48.735 88.56 49.005 ;
     RECT  2.16 49.275 88.56 49.545 ;
     RECT  2.16 49.815 88.56 50.085 ;
     RECT  2.16 50.355 88.56 50.625 ;
     RECT  2.16 50.895 88.56 51.165 ;
     RECT  2.16 51.435 88.56 51.705 ;
     RECT  2.16 51.975 88.56 52.245 ;
     RECT  2.16 52.515 88.56 52.785 ;
     RECT  2.16 53.055 88.56 53.325 ;
     RECT  2.16 53.595 88.56 53.865 ;
     RECT  2.16 54.135 88.56 54.405 ;
     RECT  2.16 54.675 88.56 54.945 ;
     RECT  2.16 55.215 88.56 55.485 ;
     RECT  2.16 55.755 88.56 56.025 ;
    LAYER M1 ;
     RECT  2.16 2.151 88.56 56.169 ;
    LAYER M2 ;
     RECT  2.16 2.151 3.379 56.169 ;
     RECT  3.379 2.106 3.631 56.169 ;
     RECT  3.631 2.07 4.019 56.169 ;
     RECT  4.019 2.106 4.091 56.169 ;
     RECT  4.091 2.151 4.891 56.169 ;
     RECT  4.891 2.106 5.171 56.169 ;
     RECT  5.171 2.151 5.287 56.169 ;
     RECT  5.287 2.151 6.583 56.214 ;
     RECT  6.583 2.151 8.087 56.286 ;
     RECT  8.087 2.151 10.831 56.169 ;
     RECT  10.831 2.106 11.371 56.169 ;
     RECT  11.371 2.034 11.479 56.169 ;
     RECT  7.987 0.846 14.827 0.864 ;
     RECT  11.479 2.034 14.827 56.358 ;
     RECT  14.827 0.846 17.231 56.358 ;
     RECT  17.231 0.846 20.939 56.286 ;
     RECT  20.939 1.422 24.331 56.286 ;
     RECT  24.331 1.422 24.431 56.979 ;
     RECT  24.431 1.422 25.807 56.286 ;
     RECT  25.807 1.152 26.779 56.286 ;
     RECT  26.779 1.152 27.167 56.358 ;
     RECT  27.167 1.422 28.175 56.358 ;
     RECT  28.175 1.422 28.831 56.286 ;
     RECT  28.831 1.152 29.039 56.286 ;
     RECT  29.039 1.422 29.083 56.286 ;
     RECT  29.083 1.422 29.723 56.358 ;
     RECT  29.723 1.764 29.867 56.358 ;
     RECT  31.639 1.152 31.739 1.17 ;
     RECT  29.867 1.926 32.243 56.358 ;
     RECT  32.243 2.106 34.123 56.358 ;
     RECT  34.123 2.07 34.771 56.358 ;
     RECT  34.771 2.034 35.023 56.358 ;
     RECT  35.023 1.998 36.355 56.358 ;
     RECT  36.355 1.998 36.455 56.439 ;
     RECT  36.455 1.998 37.859 56.358 ;
     RECT  37.859 1.998 38.507 56.214 ;
     RECT  38.507 1.998 39.343 56.169 ;
     RECT  39.343 1.998 39.803 56.214 ;
     RECT  39.803 1.998 40.891 56.169 ;
     RECT  40.891 1.881 41.107 56.169 ;
     RECT  41.107 1.836 41.899 56.169 ;
     RECT  41.899 1.836 42.079 56.214 ;
     RECT  42.079 1.836 42.179 56.439 ;
     RECT  42.179 1.836 43.223 56.214 ;
     RECT  43.223 1.836 44.519 56.169 ;
     RECT  44.519 1.998 44.743 56.169 ;
     RECT  44.743 1.998 45.463 56.214 ;
     RECT  45.463 1.458 45.751 56.214 ;
     RECT  45.751 0.846 46.219 56.214 ;
     RECT  46.219 0.846 49.027 56.286 ;
     RECT  49.027 0.846 49.739 56.358 ;
     RECT  49.739 0.846 51.187 56.286 ;
     RECT  51.187 0.846 55.067 56.358 ;
     RECT  55.067 0.846 56.075 56.214 ;
     RECT  56.075 0.846 58.055 56.169 ;
     RECT  59.755 56.961 59.855 56.979 ;
     RECT  58.055 1.422 62.203 56.169 ;
     RECT  62.203 1.422 62.851 56.286 ;
     RECT  62.851 1.422 63.139 56.358 ;
     RECT  63.139 1.422 63.239 56.484 ;
     RECT  63.239 1.422 66.091 56.358 ;
     RECT  66.091 1.422 67.271 56.439 ;
     RECT  67.271 1.836 68.423 56.439 ;
     RECT  68.423 1.836 70.223 56.358 ;
     RECT  70.223 1.836 70.771 56.214 ;
     RECT  70.771 1.8 71.699 56.214 ;
     RECT  73.975 56.961 74.075 56.979 ;
     RECT  71.699 1.8 74.659 56.169 ;
     RECT  74.659 1.422 75.847 56.169 ;
     RECT  75.847 1.422 76.235 56.214 ;
     RECT  76.235 1.422 78.151 56.169 ;
     RECT  78.151 1.152 79.619 56.169 ;
     RECT  79.619 1.881 80.959 56.169 ;
     RECT  80.959 1.836 81.571 56.169 ;
     RECT  81.571 1.224 81.751 56.169 ;
     RECT  81.751 1.152 82.067 56.169 ;
     RECT  82.067 1.836 83.587 56.169 ;
     RECT  83.587 1.152 83.759 56.169 ;
     RECT  83.759 1.881 84.911 56.169 ;
     RECT  84.911 1.926 84.919 56.169 ;
     RECT  84.919 1.926 85.379 56.214 ;
     RECT  85.379 1.926 86.639 56.169 ;
     RECT  86.639 1.962 87.143 56.169 ;
     RECT  87.143 1.998 87.863 56.169 ;
     RECT  87.863 2.106 88.295 56.169 ;
     RECT  88.295 2.151 88.56 56.169 ;
     RECT  88.56 51.786 88.619 51.804 ;
     RECT  88.56 55.26 88.619 55.71 ;
     RECT  88.56 4.23 88.655 4.248 ;
     RECT  88.56 48.006 88.763 48.024 ;
     RECT  88.56 52.794 88.871 54.126 ;
     RECT  88.619 55.26 88.871 55.278 ;
     RECT  88.56 5.976 88.907 6.534 ;
     RECT  88.871 52.794 88.907 52.884 ;
     RECT  88.871 54.108 88.943 54.126 ;
     RECT  88.56 2.196 89.159 2.484 ;
     RECT  88.907 5.976 89.375 6.174 ;
     RECT  88.56 50.976 89.375 50.994 ;
     RECT  88.56 8.676 89.483 8.694 ;
     RECT  89.375 6.156 89.663 6.174 ;
     RECT  89.159 2.196 89.735 2.214 ;
     RECT  88.907 52.794 89.843 52.812 ;
    LAYER M3 ;
     RECT  10.548 0.043 10.566 0.091 ;
     RECT  29.7 0.043 29.718 0.091 ;
     RECT  52.056 0.043 52.074 0.091 ;
     RECT  58.032 0.043 58.05 0.091 ;
     RECT  68.112 0.043 68.13 0.091 ;
     RECT  75.924 0.043 75.942 0.091 ;
     RECT  81.396 0.043 81.414 0.091 ;
     RECT  42.804 0.091 42.822 0.139 ;
     RECT  77.508 0.091 78.174 0.139 ;
     RECT  78.948 0.091 80.154 0.139 ;
     RECT  84.204 0.091 85.302 0.139 ;
     RECT  10.548 0.091 11.862 0.173 ;
     RECT  68.112 0.091 70.326 0.173 ;
     RECT  62.712 0.091 62.73 0.221 ;
     RECT  87.408 0.091 87.426 0.379 ;
     RECT  88.38 0.091 89.658 0.379 ;
     RECT  28.368 0.091 34.614 0.475 ;
     RECT  47.52 0.379 47.538 0.475 ;
     RECT  86.544 0.091 86.562 0.475 ;
     RECT  87.408 0.379 89.658 0.475 ;
     RECT  4.392 0.091 4.41 0.523 ;
     RECT  13.104 0.091 13.698 0.523 ;
     RECT  23.292 0.091 23.31 0.523 ;
     RECT  47.52 0.475 47.574 0.523 ;
     RECT  68.148 0.173 70.326 0.523 ;
     RECT  74.664 0.091 76.266 0.523 ;
     RECT  77.508 0.139 80.154 0.523 ;
     RECT  81.396 0.091 82.818 0.523 ;
     RECT  83.844 0.139 85.302 0.523 ;
     RECT  86.544 0.475 89.658 0.523 ;
     RECT  4.392 0.523 4.77 0.571 ;
     RECT  5.688 0.091 5.706 0.571 ;
     RECT  10.62 0.173 11.862 0.571 ;
     RECT  13.032 0.523 13.698 0.571 ;
     RECT  23.292 0.523 23.49 0.571 ;
     RECT  26.172 0.091 27.63 0.571 ;
     RECT  28.368 0.475 35.262 0.571 ;
     RECT  43.92 0.475 43.938 0.571 ;
     RECT  47.52 0.523 48.186 0.571 ;
     RECT  51.984 0.091 52.758 0.571 ;
     RECT  54 0.091 54.414 0.571 ;
     RECT  55.62 0.091 55.638 0.571 ;
     RECT  74.664 0.523 80.154 0.571 ;
     RECT  86.472 0.523 89.658 0.571 ;
     RECT  4.068 0.571 6.282 0.619 ;
     RECT  43.92 0.571 44.406 0.619 ;
     RECT  51.3 0.571 56.034 0.619 ;
     RECT  74.664 0.571 80.442 0.619 ;
     RECT  86.472 0.571 89.73 0.619 ;
     RECT  73.764 0.571 73.782 0.763 ;
     RECT  81.396 0.523 85.302 0.811 ;
     RECT  20.484 0.043 20.502 0.841 ;
     RECT  46.404 0.811 46.422 0.841 ;
     RECT  7.992 0.091 8.01 0.869 ;
     RECT  58.032 0.091 58.122 0.869 ;
     RECT  50.508 0.043 50.526 0.955 ;
     RECT  51.3 0.619 56.106 0.955 ;
     RECT  73.44 0.763 73.782 0.955 ;
     RECT  74.664 0.619 80.514 0.955 ;
     RECT  23.076 0.571 24.714 1.051 ;
     RECT  81.324 0.811 85.302 1.051 ;
     RECT  22.932 1.051 24.714 1.099 ;
     RECT  26.172 0.571 35.262 1.099 ;
     RECT  43.884 0.619 44.406 1.099 ;
     RECT  45.756 0.841 46.422 1.099 ;
     RECT  50.508 0.955 56.106 1.099 ;
     RECT  63.576 0.091 63.594 1.099 ;
     RECT  73.44 0.955 80.514 1.099 ;
     RECT  81.324 1.051 85.374 1.099 ;
     RECT  86.112 0.619 89.73 1.099 ;
     RECT  3.996 0.619 6.282 1.147 ;
     RECT  25.992 1.099 35.262 1.147 ;
     RECT  42.732 0.139 42.822 1.147 ;
     RECT  47.52 0.571 49.122 1.147 ;
     RECT  47.268 1.147 49.122 1.195 ;
     RECT  59.724 0.859 59.742 1.387 ;
     RECT  22.932 1.099 25.038 1.483 ;
     RECT  25.812 1.147 35.262 1.483 ;
     RECT  47.268 1.195 49.158 1.483 ;
     RECT  42.192 1.147 42.822 1.627 ;
     RECT  47.16 1.483 49.158 1.675 ;
     RECT  50.508 1.099 56.826 1.675 ;
     RECT  3.456 1.147 6.282 1.723 ;
     RECT  7.956 1.147 7.974 1.723 ;
     RECT  10.62 0.571 13.698 1.723 ;
     RECT  14.832 0.043 14.85 1.723 ;
     RECT  22.932 1.483 35.262 1.723 ;
     RECT  42.192 1.627 42.894 1.723 ;
     RECT  43.884 1.099 46.422 1.723 ;
     RECT  58.104 0.869 58.122 1.723 ;
     RECT  60.912 1.531 60.93 1.723 ;
     RECT  63.108 1.099 63.594 1.723 ;
     RECT  68.148 0.523 70.398 1.723 ;
     RECT  72.756 1.099 80.514 1.723 ;
     RECT  81.324 1.099 89.73 1.723 ;
     RECT  20.484 0.841 20.934 1.759 ;
     RECT  57.708 1.723 58.122 1.759 ;
     RECT  59.364 1.387 59.742 1.759 ;
     RECT  3.456 1.723 9.234 1.771 ;
     RECT  9.972 1.723 14.85 1.771 ;
     RECT  47.16 1.675 56.826 1.771 ;
     RECT  68.148 1.723 70.506 1.795 ;
     RECT  47.16 1.771 56.97 1.819 ;
     RECT  57.708 1.759 59.742 1.819 ;
     RECT  41.364 0.043 41.382 1.831 ;
     RECT  60.912 1.723 66.51 1.831 ;
     RECT  67.248 0.091 67.266 1.831 ;
     RECT  16.992 1.723 17.01 1.876 ;
     RECT  41.112 1.831 41.382 1.876 ;
     RECT  72.756 1.723 89.73 1.876 ;
     RECT  16.956 1.876 17.01 1.915 ;
     RECT  20.484 1.759 21.114 1.921 ;
     RECT  16.956 1.915 17.046 1.957 ;
     RECT  20.484 1.921 21.186 1.957 ;
     RECT  40.896 1.876 41.382 1.957 ;
     RECT  42.192 1.723 46.422 1.957 ;
     RECT  47.16 1.819 59.742 1.957 ;
     RECT  68.148 1.795 70.794 1.957 ;
     RECT  16.956 1.957 17.298 1.993 ;
     RECT  18.756 1.876 18.846 2.029 ;
     RECT  19.584 1.993 19.602 2.029 ;
     RECT  20.484 1.957 21.222 2.029 ;
     RECT  22.608 1.723 35.262 2.029 ;
     RECT  38.484 0.811 38.502 2.029 ;
     RECT  16.956 1.993 17.946 2.065 ;
     RECT  18.756 2.029 19.602 2.065 ;
     RECT  20.484 2.029 21.258 2.065 ;
     RECT  38.484 2.029 38.97 2.065 ;
     RECT  47.16 1.957 59.814 2.065 ;
     RECT  60.912 1.831 67.266 2.065 ;
     RECT  68.148 1.957 70.83 2.065 ;
     RECT  3.456 1.771 16.038 2.101 ;
     RECT  16.956 2.065 19.602 2.101 ;
     RECT  22.284 2.029 35.622 2.101 ;
     RECT  38.124 2.065 38.97 2.101 ;
     RECT  40.896 1.957 46.422 2.143 ;
     RECT  2.415 2.143 2.505 2.191 ;
     RECT  3.384 2.101 16.038 2.191 ;
     RECT  16.776 2.101 19.602 2.191 ;
     RECT  20.34 2.065 21.258 2.191 ;
     RECT  22.176 2.101 35.622 2.191 ;
     RECT  38.124 2.101 39.042 2.191 ;
     RECT  72.324 1.876 89.73 2.219 ;
     RECT  2.415 2.191 19.602 2.227 ;
     RECT  20.34 2.191 35.622 2.227 ;
     RECT  47.16 2.065 70.83 2.293 ;
     RECT  40.215 2.143 46.422 2.299 ;
     RECT  47.16 2.293 70.974 2.299 ;
     RECT  72.324 2.219 89.658 2.299 ;
     RECT  40.215 2.299 89.658 2.335 ;
     RECT  38.124 2.191 39.114 2.533 ;
     RECT  2.415 2.227 35.622 2.731 ;
     RECT  38.016 2.533 39.114 2.767 ;
     RECT  39.888 2.335 89.658 2.767 ;
     RECT  2.415 2.731 36.09 2.839 ;
     RECT  37.224 2.605 37.242 2.911 ;
     RECT  38.016 2.767 89.658 2.911 ;
     RECT  2.415 2.839 36.126 3.181 ;
     RECT  37.224 2.911 89.658 3.181 ;
     RECT  2.34 3.181 89.658 4.415 ;
     RECT  2.415 4.415 89.658 5.755 ;
     RECT  2.376 5.755 89.658 6.179 ;
     RECT  2.376 6.179 89.478 6.269 ;
     RECT  2.415 6.269 89.478 6.539 ;
     RECT  89.46 6.539 89.478 8.699 ;
     RECT  2.415 6.539 88.326 9.625 ;
     RECT  2.415 9.625 88.434 10.201 ;
     RECT  2.376 10.201 88.434 10.499 ;
     RECT  2.376 10.499 88.29 11.551 ;
     RECT  2.376 11.551 88.434 11.669 ;
     RECT  2.376 11.669 88.29 12.479 ;
     RECT  2.415 12.479 88.29 13.405 ;
     RECT  2.415 13.405 88.326 13.559 ;
     RECT  2.415 13.559 88.29 18.301 ;
     RECT  2.415 18.301 88.434 18.797 ;
     RECT  2.415 18.797 88.29 18.967 ;
     RECT  2.376 18.967 88.29 19.813 ;
     RECT  2.376 19.813 88.434 19.901 ;
     RECT  2.415 19.901 88.434 20.309 ;
     RECT  2.415 20.309 88.29 22.235 ;
     RECT  3.456 22.235 88.29 22.253 ;
     RECT  3.456 22.253 58.086 22.739 ;
     RECT  58.932 22.253 88.29 23.053 ;
     RECT  2.415 22.235 2.697 23.161 ;
     RECT  3.456 22.739 57.69 23.161 ;
     RECT  58.536 23.053 88.29 23.315 ;
     RECT  58.536 23.315 88.254 23.657 ;
     RECT  2.376 23.161 57.69 23.701 ;
     RECT  58.536 23.657 88.218 23.701 ;
     RECT  2.376 23.701 88.218 23.981 ;
     RECT  2.376 23.981 54.126 24.089 ;
     RECT  55.08 23.981 88.218 24.475 ;
     RECT  55.08 24.475 88.326 24.629 ;
     RECT  2.415 24.089 54.126 24.781 ;
     RECT  55.08 24.629 88.254 24.781 ;
     RECT  2.415 24.781 88.254 25.169 ;
     RECT  2.415 25.169 88.218 25.205 ;
     RECT  2.415 25.205 88.146 25.531 ;
     RECT  2.376 25.531 88.146 25.619 ;
     RECT  2.376 25.619 20.79 25.709 ;
     RECT  21.6 25.619 88.146 26.131 ;
     RECT  21.6 26.131 88.434 26.365 ;
     RECT  2.415 25.709 20.79 26.491 ;
     RECT  21.528 26.365 88.434 26.491 ;
     RECT  2.415 26.491 88.434 26.663 ;
     RECT  2.415 26.663 88.146 27.751 ;
     RECT  2.376 27.751 88.146 27.941 ;
     RECT  2.376 27.941 23.202 28.891 ;
     RECT  23.94 27.941 88.146 28.891 ;
     RECT  2.376 28.891 88.146 28.949 ;
     RECT  2.415 28.949 88.146 30.451 ;
     RECT  2.415 30.451 88.326 30.713 ;
     RECT  2.415 30.713 88.146 32.269 ;
     RECT  2.376 32.269 88.146 32.495 ;
     RECT  2.415 32.495 88.146 32.729 ;
     RECT  2.415 32.729 45.954 33.817 ;
     RECT  46.728 32.729 88.146 33.817 ;
     RECT  2.415 33.817 88.146 34.888 ;
     RECT  2.412 34.888 88.146 34.925 ;
     RECT  2.415 34.925 88.146 35.005 ;
     RECT  2.415 35.005 88.434 35.699 ;
     RECT  2.415 35.699 88.146 36.523 ;
     RECT  2.376 36.523 88.146 36.815 ;
     RECT  2.415 36.815 88.146 36.931 ;
     RECT  2.415 36.931 88.434 37.049 ;
     RECT  2.415 37.049 88.146 39.091 ;
     RECT  2.415 39.091 88.362 39.209 ;
     RECT  2.415 39.209 88.146 40.441 ;
     RECT  2.415 40.441 88.434 40.559 ;
     RECT  2.415 40.559 88.074 40.981 ;
     RECT  2.376 40.981 88.074 42.179 ;
     RECT  2.376 42.179 68.382 43.069 ;
     RECT  69.192 42.179 88.074 43.069 ;
     RECT  2.376 43.069 88.074 44.249 ;
     RECT  2.415 44.249 88.074 45.149 ;
     RECT  2.415 45.149 68.238 45.841 ;
     RECT  2.376 45.841 68.238 46.003 ;
     RECT  69.012 45.149 88.074 46.003 ;
     RECT  2.376 46.003 88.074 46.499 ;
     RECT  2.415 46.499 88.074 47.281 ;
     RECT  2.415 47.281 88.254 47.309 ;
     RECT  2.415 47.309 2.862 47.453 ;
     RECT  3.708 47.309 88.254 47.453 ;
     RECT  3.708 47.453 4.878 47.615 ;
     RECT  5.616 47.453 88.254 47.695 ;
     RECT  5.616 47.695 88.398 47.731 ;
     RECT  5.616 47.731 88.434 48.001 ;
     RECT  5.616 48.001 88.758 48.119 ;
     RECT  5.616 48.119 8.154 48.155 ;
     RECT  8.892 48.119 88.758 48.695 ;
     RECT  8.892 48.695 49.014 48.937 ;
     RECT  8.82 48.937 49.014 48.989 ;
     RECT  9.072 48.989 49.014 49.441 ;
     RECT  49.752 48.695 88.758 49.441 ;
     RECT  5.616 48.155 8.097 49.621 ;
     RECT  5.616 49.621 8.298 49.891 ;
     RECT  9.072 49.441 88.758 49.891 ;
     RECT  5.616 49.891 88.758 50.971 ;
     RECT  4.212 47.615 4.878 52.555 ;
     RECT  5.616 50.971 89.37 52.555 ;
     RECT  4.212 52.555 89.37 52.789 ;
     RECT  4.212 52.789 89.838 54.211 ;
     RECT  4.14 54.211 89.838 54.329 ;
     RECT  4.212 54.329 89.838 55.291 ;
     RECT  3.816 55.291 89.838 55.381 ;
     RECT  3.6 55.381 89.838 55.525 ;
     RECT  2.415 47.453 2.697 55.561 ;
     RECT  3.42 55.525 89.838 55.561 ;
     RECT  2.415 55.561 89.838 55.679 ;
     RECT  3.816 55.679 89.838 55.729 ;
     RECT  2.415 55.679 2.898 55.859 ;
     RECT  2.415 55.859 2.754 55.949 ;
     RECT  4.284 55.729 89.838 55.949 ;
     RECT  4.284 55.949 17.262 55.985 ;
     RECT  4.572 55.985 17.262 56.021 ;
     RECT  18.036 55.949 89.838 56.057 ;
     RECT  2.415 55.949 2.574 56.093 ;
     RECT  4.572 56.021 17.226 56.129 ;
     RECT  18.072 56.057 89.838 56.141 ;
     RECT  2.415 56.093 2.505 56.177 ;
     RECT  6.588 56.129 17.226 56.177 ;
     RECT  5.292 56.129 5.31 56.219 ;
     RECT  18.072 56.141 59.994 56.219 ;
     RECT  60.912 56.141 89.838 56.219 ;
     RECT  6.588 56.177 12.834 56.291 ;
     RECT  18.072 56.219 44.334 56.327 ;
     RECT  13.644 56.177 17.226 56.333 ;
     RECT  14.148 56.333 17.226 56.363 ;
     RECT  45.072 56.219 59.994 56.381 ;
     RECT  14.148 56.363 17.19 56.429 ;
     RECT  18.072 56.327 32.274 56.429 ;
     RECT  33.048 56.327 44.334 56.429 ;
     RECT  45.072 56.381 48.186 56.429 ;
     RECT  48.96 56.381 59.994 56.429 ;
     RECT  60.912 56.219 66.114 56.429 ;
     RECT  67.068 56.219 89.838 56.429 ;
     RECT  6.768 56.291 12.834 56.477 ;
     RECT  14.184 56.429 17.19 56.477 ;
     RECT  18.072 56.429 32.238 56.477 ;
     RECT  48.96 56.429 55.422 56.477 ;
     RECT  60.912 56.429 63.234 56.477 ;
     RECT  74.916 56.429 89.838 56.477 ;
     RECT  74.916 56.477 88.47 56.573 ;
     RECT  56.556 56.429 59.994 56.909 ;
     RECT  31.068 56.477 32.238 56.957 ;
     RECT  50.292 56.477 55.422 56.957 ;
     RECT  6.912 56.477 12.834 57.005 ;
     RECT  14.184 56.477 16.866 57.005 ;
     RECT  18.072 56.477 30.15 57.005 ;
     RECT  31.068 56.957 31.482 57.005 ;
     RECT  36.252 56.429 44.334 57.005 ;
     RECT  52.848 56.957 55.422 57.005 ;
     RECT  56.736 56.909 59.994 57.005 ;
     RECT  67.068 56.429 74.07 57.005 ;
     RECT  74.916 56.573 83.358 57.005 ;
     RECT  6.912 57.005 10.17 57.053 ;
     RECT  33.048 56.429 35.01 57.053 ;
     RECT  42.156 57.005 44.298 57.053 ;
     RECT  53.244 57.005 55.422 57.053 ;
     RECT  74.916 57.005 76.41 57.053 ;
     RECT  77.256 57.005 83.358 57.053 ;
     RECT  50.292 56.957 52.038 57.149 ;
     RECT  36.36 57.005 41.418 57.293 ;
     RECT  6.912 57.053 10.062 57.533 ;
     RECT  11.268 57.005 12.834 57.533 ;
     RECT  14.508 57.005 16.866 57.533 ;
     RECT  28.296 57.005 30.15 57.533 ;
     RECT  31.068 57.005 31.23 57.533 ;
     RECT  43.74 57.053 44.298 57.533 ;
     RECT  45.072 56.429 47.79 57.533 ;
     RECT  84.168 56.573 88.47 57.533 ;
     RECT  6.912 57.533 9.81 57.581 ;
     RECT  11.268 57.533 12.474 57.581 ;
     RECT  14.508 57.533 14.958 57.581 ;
     RECT  15.732 57.533 16.866 57.581 ;
     RECT  18.54 57.005 27.558 57.581 ;
     RECT  28.296 57.533 30.042 57.581 ;
     RECT  33.048 57.053 34.974 57.581 ;
     RECT  38.52 57.293 41.418 57.581 ;
     RECT  42.156 57.053 42.858 57.581 ;
     RECT  43.74 57.533 44.154 57.581 ;
     RECT  45.072 57.533 47.574 57.581 ;
     RECT  48.96 56.477 49.446 57.581 ;
     RECT  50.292 57.149 51.678 57.581 ;
     RECT  53.244 57.053 53.73 57.581 ;
     RECT  56.736 57.005 56.754 57.581 ;
     RECT  57.708 57.005 59.994 57.581 ;
     RECT  61.2 56.477 63.234 57.581 ;
     RECT  64.692 56.429 66.114 57.581 ;
     RECT  67.068 57.005 72.306 57.581 ;
     RECT  73.44 57.005 74.07 57.581 ;
     RECT  74.916 57.053 76.338 57.581 ;
     RECT  77.256 57.053 83.07 57.581 ;
     RECT  86.544 57.533 88.47 57.581 ;
     RECT  6.912 57.581 8.55 57.629 ;
     RECT  18.54 57.581 19.89 57.629 ;
     RECT  25.452 57.581 26.73 57.629 ;
     RECT  33.048 57.581 33.066 57.629 ;
     RECT  36.36 57.293 37.458 57.629 ;
     RECT  45.072 57.581 45.594 57.629 ;
     RECT  61.308 57.581 61.686 57.629 ;
     RECT  64.8 57.581 66.114 57.629 ;
     RECT  74.052 57.581 74.07 57.629 ;
     RECT  86.724 57.581 86.85 57.629 ;
     RECT  87.696 57.581 88.47 57.629 ;
     RECT  6.948 57.629 7.614 57.677 ;
     RECT  62.532 57.581 63.234 57.677 ;
     RECT  6.948 57.677 7.074 57.725 ;
     RECT  72.288 57.581 72.306 57.979 ;
     RECT  21.384 57.581 24.354 58.061 ;
     RECT  67.068 57.581 67.194 58.075 ;
     RECT  14.508 57.581 14.562 58.109 ;
     RECT  84.168 57.533 85.77 58.109 ;
     RECT  9.468 57.581 9.63 58.157 ;
     RECT  15.732 57.581 16.83 58.157 ;
     RECT  21.384 58.061 23.922 58.157 ;
     RECT  46.548 57.581 46.674 58.157 ;
     RECT  54.576 57.053 55.314 58.157 ;
     RECT  58.896 57.581 58.986 58.157 ;
     RECT  61.308 57.629 61.326 58.157 ;
     RECT  64.8 57.629 65.97 58.157 ;
     RECT  68.688 57.581 68.706 58.157 ;
     RECT  69.624 57.581 69.822 58.157 ;
     RECT  81.756 57.581 82.494 58.157 ;
     RECT  85.5 58.109 85.77 58.157 ;
     RECT  7.056 57.725 7.074 58.205 ;
     RECT  8.532 57.629 8.55 58.205 ;
     RECT  9.468 58.157 9.486 58.205 ;
     RECT  11.7 57.581 12.366 58.205 ;
     RECT  14.544 58.109 14.562 58.205 ;
     RECT  15.912 58.157 16.83 58.205 ;
     RECT  18.54 57.629 19.854 58.205 ;
     RECT  20.628 57.581 20.646 58.205 ;
     RECT  21.384 58.157 23.094 58.205 ;
     RECT  23.904 58.157 23.922 58.205 ;
     RECT  25.452 57.629 26.658 58.205 ;
     RECT  28.296 57.581 29.862 58.205 ;
     RECT  30.924 57.979 30.942 58.205 ;
     RECT  32.22 56.957 32.238 58.205 ;
     RECT  34.416 57.581 34.434 58.205 ;
     RECT  35.28 57.979 35.298 58.205 ;
     RECT  36.756 57.629 37.458 58.205 ;
     RECT  38.52 57.581 39.618 58.205 ;
     RECT  40.896 57.581 41.238 58.205 ;
     RECT  46.656 58.157 46.674 58.205 ;
     RECT  49.428 57.581 49.446 58.205 ;
     RECT  55.044 58.157 55.314 58.205 ;
     RECT  57.708 57.581 58.086 58.205 ;
     RECT  58.896 58.157 58.914 58.205 ;
     RECT  59.976 57.581 59.994 58.205 ;
     RECT  63.216 57.677 63.234 58.205 ;
     RECT  65.952 58.157 65.97 58.205 ;
     RECT  66.996 58.075 67.194 58.205 ;
     RECT  69.804 58.157 69.822 58.205 ;
     RECT  70.776 57.581 71.082 58.205 ;
     RECT  72.288 57.979 72.81 58.205 ;
     RECT  75.492 57.581 76.338 58.205 ;
     RECT  77.976 57.581 78.894 58.205 ;
     RECT  79.632 57.581 80.694 58.205 ;
     RECT  81.756 58.157 82.134 58.205 ;
     RECT  84.168 58.109 84.762 58.205 ;
     RECT  85.752 58.157 85.77 58.205 ;
     RECT  87.768 57.629 88.434 58.205 ;
     RECT  89.352 56.477 89.838 58.205 ;
     RECT  42.588 57.581 42.606 58.301 ;
     RECT  45.36 57.629 45.378 58.301 ;
     RECT  50.292 57.581 50.31 58.301 ;
     RECT  55.044 58.205 55.062 58.301 ;
     RECT  66.996 58.205 67.014 58.301 ;
     RECT  71.064 58.205 71.082 58.301 ;
    LAYER M4 ;
     RECT  2.365 5.76 2.408 5.784 ;
     RECT  2.365 19.872 2.408 19.896 ;
     RECT  2.365 25.536 2.408 25.56 ;
     RECT  2.401 34.896 2.408 34.92 ;
     RECT  2.365 36.528 2.408 36.552 ;
     RECT  2.408 2.148 2.512 56.172 ;
     RECT  2.512 2.418 2.704 55.902 ;
     RECT  2.704 33.6 2.819 33.624 ;
     RECT  2.704 34.896 2.819 36.552 ;
     RECT  2.819 35.712 2.873 36.552 ;
     RECT  2.704 30.144 3.197 32.28 ;
     RECT  2.704 11.376 3.443 12.552 ;
     RECT  3.197 30.72 3.443 32.28 ;
     RECT  3.443 30.72 3.449 30.744 ;
     RECT  2.704 39.36 3.449 40.056 ;
     RECT  2.704 43.776 3.449 44.472 ;
     RECT  2.704 45.456 3.665 45.48 ;
     RECT  2.704 5.76 3.769 5.784 ;
     RECT  3.685 33.264 3.772 33.288 ;
     RECT  2.704 8.832 3.773 9.144 ;
     RECT  2.704 37.584 3.805 37.608 ;
     RECT  2.704 25.536 3.845 25.56 ;
     RECT  2.704 55.68 3.845 55.704 ;
     RECT  3.445 1.152 3.913 1.176 ;
     RECT  2.704 10.224 3.949 10.248 ;
     RECT  3.443 11.376 3.949 11.4 ;
     RECT  3.913 1.152 3.985 1.704 ;
     RECT  3.985 0.624 4.018 1.704 ;
     RECT  2.704 22.176 4.021 22.2 ;
     RECT  2.704 27.888 4.021 27.912 ;
     RECT  3.769 5.76 4.025 5.88 ;
     RECT  4.021 21.648 4.025 22.2 ;
     RECT  4.018 0.624 4.057 1.752 ;
     RECT  3.443 12.528 4.057 12.552 ;
     RECT  2.704 16.656 4.057 16.68 ;
     RECT  3.805 47.088 4.057 47.112 ;
     RECT  2.704 23.856 4.117 23.88 ;
     RECT  2.704 19.872 4.129 19.896 ;
     RECT  4.057 0.576 4.165 1.752 ;
     RECT  4.117 23.328 4.204 23.88 ;
     RECT  4.057 12.528 4.205 12.984 ;
     RECT  2.704 3.312 4.22 4.536 ;
     RECT  3.949 10.224 4.277 11.4 ;
     RECT  4.057 46.896 4.309 47.112 ;
     RECT  4.165 0.576 4.381 1.8 ;
     RECT  4.205 12.96 4.417 12.984 ;
     RECT  2.704 14.16 4.417 14.952 ;
     RECT  4.22 3.312 4.525 4.632 ;
     RECT  4.277 10.224 4.597 11.208 ;
     RECT  3.449 39.36 4.597 39.384 ;
     RECT  4.237 40.464 4.597 40.488 ;
     RECT  4.597 39.36 4.601 40.488 ;
     RECT  4.417 12.96 4.645 14.952 ;
     RECT  3.443 31.728 4.669 32.28 ;
     RECT  4.381 0.096 4.717 1.8 ;
     RECT  3.805 37.584 4.745 38.232 ;
     RECT  4.129 19.872 4.813 19.992 ;
     RECT  4.025 21.648 4.813 21.672 ;
     RECT  4.669 30.816 4.817 32.28 ;
     RECT  4.645 12.96 4.885 15.048 ;
     RECT  4.597 10.176 4.925 11.208 ;
     RECT  4.669 55.296 4.979 55.32 ;
     RECT  2.873 35.712 4.993 35.736 ;
     RECT  4.885 12.96 5.033 15.528 ;
     RECT  4.601 39.36 5.065 39.624 ;
     RECT  4.525 3.312 5.101 5.304 ;
     RECT  5.033 12.96 5.123 13.896 ;
     RECT  5.029 25.056 5.123 25.08 ;
     RECT  5.029 53.04 5.123 53.064 ;
     RECT  4.717 1.728 5.137 1.8 ;
     RECT  5.033 14.88 5.173 15.528 ;
     RECT  4.057 16.656 5.173 17.16 ;
     RECT  4.813 19.776 5.173 19.992 ;
     RECT  4.993 35.328 5.173 35.736 ;
     RECT  4.717 0.096 5.177 0.6 ;
     RECT  5.173 14.88 5.201 17.16 ;
     RECT  5.077 26.736 5.213 26.76 ;
     RECT  5.173 35.328 5.213 35.88 ;
     RECT  5.173 19.104 5.26 19.992 ;
     RECT  4.204 23.856 5.276 23.88 ;
     RECT  4.745 37.584 5.281 37.608 ;
     RECT  5.201 14.88 5.285 17.208 ;
     RECT  5.137 1.728 5.317 2.232 ;
     RECT  5.276 23.856 5.317 24.648 ;
     RECT  4.021 27.888 5.317 28.824 ;
     RECT  5.137 29.808 5.317 29.832 ;
     RECT  5.137 6.768 5.321 6.792 ;
     RECT  5.317 23.28 5.363 24.648 ;
     RECT  5.317 1.728 5.389 2.28 ;
     RECT  5.101 3.312 5.389 5.688 ;
     RECT  5.363 23.28 5.389 23.88 ;
     RECT  5.389 1.728 5.461 5.688 ;
     RECT  4.925 10.176 5.609 10.344 ;
     RECT  5.317 27.888 5.677 29.832 ;
     RECT  4.817 31.728 5.677 32.28 ;
     RECT  5.065 38.736 5.677 39.624 ;
     RECT  5.077 52.032 5.713 52.056 ;
     RECT  5.213 35.856 5.749 35.88 ;
     RECT  5.281 37.104 5.749 37.608 ;
     RECT  5.677 27.888 5.753 30.408 ;
     RECT  4.201 54.288 5.785 54.312 ;
     RECT  5.389 22.704 5.789 23.88 ;
     RECT  5.677 38.736 5.789 39.864 ;
     RECT  5.753 28.8 5.821 30.408 ;
     RECT  5.677 31.728 5.821 33.048 ;
     RECT  5.425 34.08 5.821 34.104 ;
     RECT  5.177 0.096 5.843 0.12 ;
     RECT  2.704 41.808 5.861 41.832 ;
     RECT  5.425 11.424 5.965 11.448 ;
     RECT  5.123 12.96 5.965 13.656 ;
     RECT  5.929 41.904 6.041 42.552 ;
     RECT  5.965 11.424 6.049 13.656 ;
     RECT  6.049 12.48 6.109 13.656 ;
     RECT  6.109 12.48 6.181 13.896 ;
     RECT  5.285 14.88 6.181 16.392 ;
     RECT  3.449 43.776 6.181 43.8 ;
     RECT  5.26 19.344 6.217 19.992 ;
     RECT  4.813 21.072 6.217 21.672 ;
     RECT  5.713 51.504 6.217 52.056 ;
     RECT  5.785 54.288 6.217 54.504 ;
     RECT  5.821 28.8 6.221 34.104 ;
     RECT  4.309 46.176 6.257 47.112 ;
     RECT  6.221 28.8 6.293 32.28 ;
     RECT  6.181 43.776 6.293 44.472 ;
     RECT  3.773 8.832 6.329 8.856 ;
     RECT  5.789 38.736 6.329 39.768 ;
     RECT  6.253 0.576 6.337 0.6 ;
     RECT  5.749 35.856 6.397 37.608 ;
     RECT  6.217 19.344 6.433 21.672 ;
     RECT  5.461 1.728 6.473 6.264 ;
     RECT  6.221 33.984 6.541 34.104 ;
     RECT  6.397 35.856 6.541 38.04 ;
     RECT  6.293 43.776 6.541 43.8 ;
     RECT  6.433 18.768 6.545 21.672 ;
     RECT  6.541 43.152 6.581 43.8 ;
     RECT  6.473 3.312 6.653 6.264 ;
     RECT  6.293 28.8 6.653 31.8 ;
     RECT  6.541 33.984 6.659 38.04 ;
     RECT  6.577 50.4 6.709 50.424 ;
     RECT  6.217 51.504 6.709 54.504 ;
     RECT  5.609 10.32 6.721 10.344 ;
     RECT  6.049 11.424 6.721 11.448 ;
     RECT  6.709 50.4 6.721 54.504 ;
     RECT  6.181 12.48 6.757 16.392 ;
     RECT  6.653 28.8 6.761 29.112 ;
     RECT  6.721 50.4 6.796 55.368 ;
     RECT  6.659 34.368 6.803 38.04 ;
     RECT  6.757 12.48 6.901 16.824 ;
     RECT  6.329 39.6 6.901 39.768 ;
     RECT  6.041 41.904 6.901 41.928 ;
     RECT  6.901 57.6 6.937 57.624 ;
     RECT  6.721 10.32 7.009 11.448 ;
     RECT  7.009 9.936 7.045 11.448 ;
     RECT  6.901 12.48 7.045 17.016 ;
     RECT  6.937 57.6 7.045 57.72 ;
     RECT  6.901 39.6 7.081 40.392 ;
     RECT  6.901 41.712 7.081 41.928 ;
     RECT  6.545 18.768 7.117 19.032 ;
     RECT  6.257 46.512 7.117 47.112 ;
     RECT  6.757 56.448 7.117 56.472 ;
     RECT  7.045 57.6 7.117 58.2 ;
     RECT  7.117 56.448 7.129 58.2 ;
     RECT  5.789 22.704 7.141 23.304 ;
     RECT  6.865 24.528 7.141 24.552 ;
     RECT  7.045 9.936 7.153 17.016 ;
     RECT  6.653 4.8 7.189 6.264 ;
     RECT  7.129 56.448 7.333 57.72 ;
     RECT  6.803 36.336 7.397 38.04 ;
     RECT  7.081 39.6 7.397 41.928 ;
     RECT  7.117 18 7.549 19.032 ;
     RECT  6.545 20.112 7.549 21.672 ;
     RECT  6.796 51.504 7.621 55.368 ;
     RECT  7.333 56.4 7.621 57.72 ;
     RECT  6.853 0.096 7.669 0.12 ;
     RECT  6.473 1.728 7.808 2.28 ;
     RECT  6.653 3.312 7.808 3.672 ;
     RECT  7.189 4.8 7.808 6.36 ;
     RECT  7.153 8.976 7.808 17.016 ;
     RECT  7.549 18 7.808 21.672 ;
     RECT  7.141 22.704 7.808 24.552 ;
     RECT  6.653 30.096 7.808 31.8 ;
     RECT  6.803 34.368 7.808 35.304 ;
     RECT  7.397 36.336 7.808 41.928 ;
     RECT  6.581 43.152 7.808 43.176 ;
     RECT  7.045 45.024 7.808 45.048 ;
     RECT  7.117 46.512 7.808 47.16 ;
     RECT  7.669 48.336 7.808 48.36 ;
     RECT  6.796 50.4 7.808 50.424 ;
     RECT  7.621 51.504 7.808 57.72 ;
     RECT  7.808 1.728 7.945 57.72 ;
     RECT  7.669 0.096 8.021 0.168 ;
     RECT  8.021 0.144 8.101 0.168 ;
     RECT  7.945 1.152 8.101 57.72 ;
     RECT  8.101 0.144 8.104 57.72 ;
     RECT  8.104 10.224 8.165 20.136 ;
     RECT  8.165 10.224 8.201 10.344 ;
     RECT  8.104 0.144 8.291 1.848 ;
     RECT  8.104 42.72 8.317 45.144 ;
     RECT  8.104 50.688 8.345 57.72 ;
     RECT  8.291 0.192 8.387 1.848 ;
     RECT  8.104 5.184 8.387 7.752 ;
     RECT  8.387 5.184 8.435 6.36 ;
     RECT  8.104 46.512 8.435 48.984 ;
     RECT  8.345 56.4 8.521 57.72 ;
     RECT  8.387 1.152 8.531 1.848 ;
     RECT  8.435 5.184 8.627 6.264 ;
     RECT  8.627 5.712 8.723 6.264 ;
     RECT  8.104 25.008 8.813 25.8 ;
     RECT  8.317 42.72 8.813 43.8 ;
     RECT  8.104 8.976 8.957 9.144 ;
     RECT  8.104 21.696 9.097 23.88 ;
     RECT  8.104 29.328 9.097 32.328 ;
     RECT  8.435 47.76 9.101 48.984 ;
     RECT  8.345 50.688 9.133 55.32 ;
     RECT  9.097 28.464 9.137 32.328 ;
     RECT  8.104 3.024 9.173 4.008 ;
     RECT  9.137 29.616 9.277 32.328 ;
     RECT  9.097 21.6 9.281 23.88 ;
     RECT  9.277 29.616 9.317 33 ;
     RECT  8.531 1.728 9.349 1.848 ;
     RECT  8.201 10.224 9.395 10.296 ;
     RECT  8.723 6.192 9.413 6.264 ;
     RECT  8.387 7.728 9.421 7.752 ;
     RECT  8.957 8.976 9.421 9 ;
     RECT  8.317 45.12 9.421 45.144 ;
     RECT  9.421 44.976 9.445 45.144 ;
     RECT  8.435 46.512 9.445 46.536 ;
     RECT  9.281 21.6 9.457 23.304 ;
     RECT  9.421 7.728 9.461 9 ;
     RECT  8.104 39.744 9.493 40.92 ;
     RECT  9.413 6.192 9.497 6.312 ;
     RECT  8.521 56.4 9.497 58.2 ;
     RECT  9.349 1.728 9.5 1.896 ;
     RECT  9.173 3.024 9.5 3.048 ;
     RECT  9.445 44.976 9.505 46.536 ;
     RECT  9.493 39.216 9.529 40.92 ;
     RECT  8.165 11.424 9.539 20.136 ;
     RECT  9.133 50.64 9.637 55.32 ;
     RECT  9.497 56.4 9.637 58.152 ;
     RECT  9.637 50.64 9.641 58.152 ;
     RECT  9.505 45.12 9.677 46.536 ;
     RECT  9.641 50.64 9.685 57.576 ;
     RECT  9.497 6.192 9.713 6.216 ;
     RECT  9.539 11.664 9.713 20.136 ;
     RECT  9.317 31.392 9.745 33 ;
     RECT  8.104 33.984 9.745 37.944 ;
     RECT  9.529 39.216 9.745 41.784 ;
     RECT  8.813 43.296 9.785 43.8 ;
     RECT  9.677 45.408 9.821 46.536 ;
     RECT  9.685 50.112 9.821 57.576 ;
     RECT  9.745 31.392 9.829 37.944 ;
     RECT  9.745 38.976 9.829 41.784 ;
     RECT  9.785 43.296 9.889 43.32 ;
     RECT  9.395 10.224 9.893 10.248 ;
     RECT  9.829 31.392 9.965 41.784 ;
     RECT  9.5 1.728 10.021 3.048 ;
     RECT  9.713 15.36 10.069 20.136 ;
     RECT  9.457 21.456 10.069 23.304 ;
     RECT  9.317 29.616 10.109 30.024 ;
     RECT  9.821 50.112 10.109 50.664 ;
     RECT  8.813 25.008 10.177 25.032 ;
     RECT  8.104 27.312 10.217 27.336 ;
     RECT  10.069 15.36 10.325 23.304 ;
     RECT  10.177 25.008 10.357 25.32 ;
     RECT  10.109 50.64 10.361 50.664 ;
     RECT  10.021 0.816 10.493 3.048 ;
     RECT  10.493 0.144 10.537 3.048 ;
     RECT  9.821 46.176 10.649 46.536 ;
     RECT  9.821 51.696 10.649 57.576 ;
     RECT  9.713 11.664 10.681 14.184 ;
     RECT  10.325 15.36 10.681 21.144 ;
     RECT  9.137 28.464 10.717 28.488 ;
     RECT  10.681 11.664 10.753 21.144 ;
     RECT  10.649 46.176 10.789 46.2 ;
     RECT  10.649 51.696 10.789 56.52 ;
     RECT  9.461 8.544 10.825 8.568 ;
     RECT  10.325 22.128 10.825 23.304 ;
     RECT  10.357 24.336 10.825 25.32 ;
     RECT  10.789 51.456 10.829 56.52 ;
     RECT  9.889 43.056 10.861 43.32 ;
     RECT  10.825 22.128 10.901 25.32 ;
     RECT  10.901 22.752 10.973 25.32 ;
     RECT  10.973 24.336 11.041 25.32 ;
     RECT  9.101 48.384 11.081 48.984 ;
     RECT  10.825 8.544 11.113 9.384 ;
     RECT  10.829 52.896 11.123 56.52 ;
     RECT  11.113 7.68 11.153 9.384 ;
     RECT  11.041 24.336 11.153 25.416 ;
     RECT  9.965 39.744 11.185 41.784 ;
     RECT  11.153 24.432 11.189 25.416 ;
     RECT  11.153 7.68 11.257 7.704 ;
     RECT  10.465 26.736 11.293 26.856 ;
     RECT  10.717 28.128 11.293 28.488 ;
     RECT  10.861 42.816 11.293 43.32 ;
     RECT  11.081 48.384 11.372 48.408 ;
     RECT  11.293 26.4 11.411 28.488 ;
     RECT  10.753 11.232 11.413 21.144 ;
     RECT  11.372 47.856 11.459 48.408 ;
     RECT  11.413 10.512 11.473 21.144 ;
     RECT  9.965 31.392 11.509 38.184 ;
     RECT  11.185 39.36 11.509 41.784 ;
     RECT  11.509 31.392 11.545 41.784 ;
     RECT  10.649 57.552 11.557 57.576 ;
     RECT  11.153 9.024 11.653 9.384 ;
     RECT  11.473 10.512 11.653 21.72 ;
     RECT  10.829 51.456 11.761 51.72 ;
     RECT  11.545 31.296 11.948 41.784 ;
     RECT  11.948 31.056 11.969 41.784 ;
     RECT  11.293 42.816 11.969 44.232 ;
     RECT  11.761 51.216 12.013 51.72 ;
     RECT  11.123 52.896 12.013 56.472 ;
     RECT  11.257 7.584 12.017 7.704 ;
     RECT  11.969 31.056 12.035 44.232 ;
     RECT  10.109 29.616 12.049 29.64 ;
     RECT  11.411 27.888 12.121 28.488 ;
     RECT  12.049 29.616 12.121 29.832 ;
     RECT  11.459 48.384 12.16 48.408 ;
     RECT  12.16 48.384 12.161 48.456 ;
     RECT  11.557 57.552 12.377 58.2 ;
     RECT  11.617 4.656 12.445 4.68 ;
     RECT  12.013 51.216 12.481 56.472 ;
     RECT  12.377 57.552 12.481 57.576 ;
     RECT  12.481 51.168 12.485 57.576 ;
     RECT  12.445 4.656 12.517 5.304 ;
     RECT  12.409 6.384 12.517 6.408 ;
     RECT  12.517 4.656 12.553 6.408 ;
     RECT  11.411 26.4 12.697 26.856 ;
     RECT  12.035 31.248 12.697 44.232 ;
     RECT  12.485 51.168 12.755 57.528 ;
     RECT  10.973 22.752 12.769 23.304 ;
     RECT  11.189 24.432 12.769 25.32 ;
     RECT  10.537 0.048 12.805 3.048 ;
     RECT  12.553 4.416 12.805 6.408 ;
     RECT  12.755 57.504 12.845 57.528 ;
     RECT  11.653 9.024 12.853 21.72 ;
     RECT  12.161 48.432 12.949 48.456 ;
     RECT  12.877 49.488 12.949 49.512 ;
     RECT  12.697 31.248 12.997 44.376 ;
     RECT  12.769 22.752 13.052 25.32 ;
     RECT  12.853 8.688 13.057 21.72 ;
     RECT  13.052 22.752 13.057 25.416 ;
     RECT  13.057 8.688 13.093 25.416 ;
     RECT  12.697 26.4 13.093 26.904 ;
     RECT  12.121 27.888 13.093 29.832 ;
     RECT  12.997 30.864 13.093 44.376 ;
     RECT  12.949 48.432 13.093 49.512 ;
     RECT  12.755 51.168 13.093 56.328 ;
     RECT  12.805 0.048 13.208 6.408 ;
     RECT  12.017 7.584 13.208 7.608 ;
     RECT  13.093 8.688 13.208 26.904 ;
     RECT  13.093 27.888 13.208 44.376 ;
     RECT  10.789 46.032 13.208 46.2 ;
     RECT  13.093 48.432 13.208 56.328 ;
     RECT  13.208 0.048 13.504 56.328 ;
     RECT  13.504 0.048 13.619 2.28 ;
     RECT  13.504 8.832 13.619 27.384 ;
     RECT  13.619 8.832 13.673 27.336 ;
     RECT  13.673 23.28 13.708 27.336 ;
     RECT  13.504 47.568 13.781 54.504 ;
     RECT  13.781 47.568 14.033 49.512 ;
     RECT  13.504 55.488 14.053 56.328 ;
     RECT  14.053 55.488 14.213 57 ;
     RECT  13.504 29.088 14.249 44.616 ;
     RECT  14.249 30.672 14.284 44.616 ;
     RECT  14.033 49.104 14.284 49.512 ;
     RECT  14.284 49.488 14.285 49.512 ;
     RECT  14.284 30.768 14.291 44.616 ;
     RECT  14.245 58.176 14.341 58.2 ;
     RECT  14.291 30.768 14.393 44.088 ;
     RECT  14.341 58.08 14.437 58.2 ;
     RECT  14.249 29.088 14.465 29.112 ;
     RECT  14.437 57.456 14.573 58.2 ;
     RECT  13.708 26.88 14.641 27.336 ;
     RECT  13.673 8.832 14.749 22.2 ;
     RECT  13.619 0.048 14.861 1.896 ;
     RECT  14.641 26.88 14.861 27.912 ;
     RECT  13.504 3.984 14.893 7.368 ;
     RECT  14.749 8.4 14.893 22.2 ;
     RECT  14.641 29.04 14.929 29.064 ;
     RECT  14.929 28.992 14.965 29.064 ;
     RECT  14.861 26.88 14.969 27.336 ;
     RECT  14.033 47.568 14.969 47.592 ;
     RECT  14.893 3.984 15.077 22.2 ;
     RECT  14.861 0.816 15.109 1.896 ;
     RECT  13.708 23.28 15.145 25.752 ;
     RECT  14.969 26.88 15.145 26.904 ;
     RECT  15.145 23.28 15.185 26.904 ;
     RECT  13.504 46.032 15.253 46.056 ;
     RECT  14.573 57.456 15.257 57.576 ;
     RECT  14.213 55.488 15.281 56.424 ;
     RECT  15.109 0.816 15.301 1.944 ;
     RECT  15.077 3.984 15.361 10.152 ;
     RECT  15.185 24.624 15.365 26.904 ;
     RECT  14.393 44.064 15.469 44.088 ;
     RECT  15.325 48.864 15.469 48.888 ;
     RECT  15.361 3.84 15.581 10.152 ;
     RECT  14.393 30.768 15.721 43.08 ;
     RECT  15.469 44.064 15.721 44.472 ;
     RECT  15.301 0.816 15.781 2.376 ;
     RECT  15.581 3.84 15.781 5.88 ;
     RECT  15.581 6.864 15.905 10.152 ;
     RECT  14.965 28.368 15.937 29.064 ;
     RECT  15.721 30.768 15.937 44.472 ;
     RECT  13.781 50.688 15.937 54.504 ;
     RECT  15.281 55.488 15.937 57 ;
     RECT  15.781 0.816 16.157 5.88 ;
     RECT  15.905 7.008 16.225 10.152 ;
     RECT  15.937 50.688 16.333 57 ;
     RECT  15.589 58.128 16.333 58.2 ;
     RECT  16.333 50.688 16.337 58.2 ;
     RECT  16.157 4.656 16.373 5.88 ;
     RECT  15.253 46.032 16.373 46.92 ;
     RECT  16.373 46.032 16.441 46.152 ;
     RECT  15.937 27.648 16.553 29.064 ;
     RECT  15.937 30.336 16.7 44.472 ;
     RECT  16.441 45.552 16.7 46.152 ;
     RECT  15.185 23.28 16.729 23.304 ;
     RECT  15.469 48.864 16.765 49.608 ;
     RECT  16.337 50.688 16.765 56.472 ;
     RECT  16.337 57.552 16.877 58.2 ;
     RECT  16.765 48.864 16.933 56.472 ;
     RECT  16.225 7.008 16.945 10.584 ;
     RECT  16.157 0.816 16.949 3.672 ;
     RECT  16.7 30.336 16.949 46.152 ;
     RECT  15.077 11.712 17.017 22.2 ;
     RECT  16.729 23.184 17.017 23.304 ;
     RECT  17.017 11.712 17.089 23.304 ;
     RECT  15.365 24.768 17.089 26.664 ;
     RECT  16.949 30.432 17.093 46.152 ;
     RECT  16.933 48.816 17.129 56.472 ;
     RECT  17.089 11.712 17.273 26.664 ;
     RECT  16.945 6.528 17.305 10.584 ;
     RECT  17.273 11.712 17.305 23.304 ;
     RECT  17.129 48.816 17.309 49.608 ;
     RECT  17.305 6.528 17.381 23.304 ;
     RECT  16.553 27.696 17.411 29.064 ;
     RECT  17.381 9.024 17.417 23.304 ;
     RECT  17.411 28.992 17.489 29.064 ;
     RECT  17.477 47.856 17.561 48.12 ;
     RECT  16.949 3.408 17.597 3.672 ;
     RECT  16.877 57.6 17.651 58.2 ;
     RECT  17.273 24.768 17.737 26.664 ;
     RECT  17.411 27.696 17.737 27.96 ;
     RECT  17.381 6.528 17.881 7.8 ;
     RECT  17.129 50.592 17.893 56.472 ;
     RECT  16.373 4.656 17.996 5.304 ;
     RECT  17.881 6.384 17.996 7.8 ;
     RECT  17.309 49.152 18.277 49.608 ;
     RECT  18.277 49.104 18.349 49.608 ;
     RECT  17.893 50.592 18.349 57 ;
     RECT  17.737 24.768 18.565 27.96 ;
     RECT  16.949 0.816 18.608 2.28 ;
     RECT  17.597 3.408 18.608 3.432 ;
     RECT  17.996 4.656 18.608 7.8 ;
     RECT  17.417 9.024 18.608 21.672 ;
     RECT  17.417 23.184 18.608 23.304 ;
     RECT  18.565 24.384 18.608 27.96 ;
     RECT  17.489 29.04 18.608 29.064 ;
     RECT  17.093 30.432 18.608 44.472 ;
     RECT  17.093 45.552 18.608 46.056 ;
     RECT  17.561 48.096 18.608 48.12 ;
     RECT  18.349 49.104 18.608 57 ;
     RECT  18.608 0.816 18.853 57 ;
     RECT  17.651 58.08 18.853 58.2 ;
     RECT  18.853 0.816 18.904 58.2 ;
     RECT  18.904 23.184 19.073 28.344 ;
     RECT  18.904 4.656 19.109 5.544 ;
     RECT  18.904 47.328 19.139 58.2 ;
     RECT  19.139 47.328 19.181 54.504 ;
     RECT  18.904 0.816 19.433 2.856 ;
     RECT  18.904 29.376 19.433 44.376 ;
     RECT  19.181 47.328 19.505 48.984 ;
     RECT  19.433 29.376 19.685 42.936 ;
     RECT  18.904 46.032 19.897 46.056 ;
     RECT  19.073 27.312 19.937 28.344 ;
     RECT  19.685 29.376 19.937 42.792 ;
     RECT  19.505 47.328 20.009 47.352 ;
     RECT  19.937 29.376 20.045 42.744 ;
     RECT  18.904 6.864 20.113 21.816 ;
     RECT  19.073 23.184 20.149 26.04 ;
     RECT  19.109 4.656 20.221 5.4 ;
     RECT  20.113 6.864 20.221 22.2 ;
     RECT  20.221 4.656 20.245 22.2 ;
     RECT  20.149 23.184 20.245 26.808 ;
     RECT  19.433 2.832 20.257 2.856 ;
     RECT  19.181 50.496 20.329 54.504 ;
     RECT  20.045 29.376 20.333 42.696 ;
     RECT  20.245 4.656 20.369 26.808 ;
     RECT  20.369 4.656 20.441 26.088 ;
     RECT  19.433 0.816 20.473 1.512 ;
     RECT  19.505 48.336 20.513 48.984 ;
     RECT  20.257 2.832 20.617 3.144 ;
     RECT  20.441 4.656 20.617 22.824 ;
     RECT  19.937 27.84 20.617 28.344 ;
     RECT  20.333 29.376 20.617 41.208 ;
     RECT  20.329 50.016 20.627 54.504 ;
     RECT  20.627 50.496 20.693 54.504 ;
     RECT  20.617 2.832 20.729 22.824 ;
     RECT  20.693 51.168 20.869 54.504 ;
     RECT  19.139 55.488 20.869 58.2 ;
     RECT  19.433 44.064 20.941 44.376 ;
     RECT  19.897 45.552 20.941 46.056 ;
     RECT  20.513 48.432 20.941 48.984 ;
     RECT  20.729 3.12 21.169 22.824 ;
     RECT  20.329 47.28 21.193 47.304 ;
     RECT  21.193 47.28 21.413 47.4 ;
     RECT  20.617 27.84 21.445 41.208 ;
     RECT  20.869 51.168 21.485 58.2 ;
     RECT  20.333 42.432 21.518 42.696 ;
     RECT  21.445 27.84 21.553 41.352 ;
     RECT  20.941 48.432 21.553 49.464 ;
     RECT  21.485 51.456 21.557 58.2 ;
     RECT  21.169 3.12 21.593 22.776 ;
     RECT  21.553 47.568 21.637 49.464 ;
     RECT  21.553 27.744 21.737 41.352 ;
     RECT  21.518 42.432 21.737 42.648 ;
     RECT  21.737 27.744 21.845 30.072 ;
     RECT  21.637 47.568 21.989 49.944 ;
     RECT  20.441 23.904 22.025 26.088 ;
     RECT  21.737 31.2 22.277 41.352 ;
     RECT  21.845 27.744 22.421 29.496 ;
     RECT  21.557 55.488 22.421 58.2 ;
     RECT  21.557 51.456 22.561 54.504 ;
     RECT  22.421 55.488 22.561 57 ;
     RECT  20.473 0.048 22.597 1.512 ;
     RECT  21.989 47.568 22.669 49.464 ;
     RECT  22.561 51.456 22.741 57 ;
     RECT  21.593 3.264 22.777 22.776 ;
     RECT  22.421 27.744 22.781 29.016 ;
     RECT  20.941 44.064 22.933 46.056 ;
     RECT  22.669 47.136 22.933 49.464 ;
     RECT  22.277 31.2 23.033 40.968 ;
     RECT  22.933 44.064 23.065 49.464 ;
     RECT  22.741 50.64 23.065 57 ;
     RECT  22.781 27.744 23.245 27.768 ;
     RECT  23.033 40.8 23.281 40.968 ;
     RECT  21.737 42.624 23.281 42.648 ;
     RECT  22.025 24.288 23.317 26.088 ;
     RECT  23.281 40.8 23.353 42.648 ;
     RECT  23.353 40.8 23.425 42.792 ;
     RECT  23.065 44.064 23.425 57 ;
     RECT  23.033 31.2 23.461 39.816 ;
     RECT  23.425 40.8 23.653 57 ;
     RECT  22.421 58.128 23.653 58.2 ;
     RECT  22.781 28.896 23.857 29.016 ;
     RECT  22.597 0.048 23.893 1.752 ;
     RECT  22.777 2.832 23.893 22.776 ;
     RECT  23.653 40.8 23.933 58.2 ;
     RECT  23.893 0.048 24.008 22.776 ;
     RECT  23.317 24.288 24.008 26.232 ;
     RECT  23.245 27.648 24.008 27.768 ;
     RECT  23.857 28.896 24.008 29.784 ;
     RECT  23.461 30.912 24.008 39.816 ;
     RECT  23.933 40.8 24.008 58.152 ;
     RECT  24.008 0.048 24.013 58.152 ;
     RECT  24.013 0.048 24.304 57.048 ;
     RECT  24.304 24.384 24.563 27.768 ;
     RECT  24.304 29.088 24.725 41.784 ;
     RECT  24.304 47.136 25.009 57.048 ;
     RECT  24.013 58.032 25.009 58.152 ;
     RECT  24.725 30.24 25.013 41.784 ;
     RECT  25.009 47.136 25.085 58.152 ;
     RECT  25.085 56.976 25.093 58.152 ;
     RECT  24.304 0.048 25.121 23.208 ;
     RECT  24.563 24.48 25.121 26.136 ;
     RECT  25.013 30.24 25.121 41.64 ;
     RECT  25.085 47.136 25.121 55.8 ;
     RECT  24.304 42.816 25.477 44.088 ;
     RECT  24.563 27.312 25.585 27.768 ;
     RECT  25.121 8.16 25.621 23.208 ;
     RECT  25.477 42.768 25.621 44.088 ;
     RECT  25.621 42.768 25.657 44.712 ;
     RECT  24.304 46.032 25.657 46.152 ;
     RECT  25.621 8.16 25.733 23.352 ;
     RECT  25.121 30.24 25.733 39.816 ;
     RECT  25.585 27.216 25.765 27.768 ;
     RECT  24.725 29.088 25.765 29.112 ;
     RECT  25.121 41.184 25.769 41.64 ;
     RECT  25.657 42.768 25.837 46.152 ;
     RECT  25.121 47.136 25.837 55.56 ;
     RECT  25.733 8.16 25.985 9.672 ;
     RECT  25.121 24.48 26.089 25.944 ;
     RECT  25.121 0.048 26.125 6.84 ;
     RECT  25.985 8.16 26.125 9.624 ;
     RECT  25.837 42.768 26.149 55.56 ;
     RECT  25.093 56.976 26.149 58.2 ;
     RECT  26.125 0.048 26.453 9.624 ;
     RECT  25.733 39.216 26.453 39.816 ;
     RECT  26.149 42.768 26.483 58.2 ;
     RECT  25.765 27.216 26.521 29.112 ;
     RECT  25.733 30.24 26.521 38.184 ;
     RECT  26.483 43.92 26.525 58.2 ;
     RECT  26.453 3.984 26.597 9.624 ;
     RECT  26.525 43.92 26.633 44.712 ;
     RECT  26.525 45.696 26.669 58.2 ;
     RECT  26.453 0.048 26.705 2.616 ;
     RECT  26.089 24.48 26.777 26.232 ;
     RECT  26.453 39.216 26.777 39.768 ;
     RECT  26.483 42.768 26.813 42.792 ;
     RECT  25.733 10.704 26.957 23.352 ;
     RECT  26.669 45.696 26.963 57.624 ;
     RECT  26.521 27.216 26.989 38.184 ;
     RECT  26.777 24.48 27.025 25.032 ;
     RECT  25.769 41.616 27.025 41.64 ;
     RECT  27.025 41.616 27.065 42.168 ;
     RECT  26.597 8.496 27.133 9.624 ;
     RECT  26.957 10.704 27.133 23.16 ;
     RECT  26.705 0.048 27.245 2.568 ;
     RECT  26.989 26.64 27.245 38.184 ;
     RECT  26.777 39.216 27.425 39.24 ;
     RECT  26.597 3.984 27.569 7.464 ;
     RECT  26.963 45.696 27.569 57.576 ;
     RECT  27.569 46.032 27.677 57.576 ;
     RECT  26.633 43.92 27.853 44.088 ;
     RECT  27.133 8.496 27.889 23.16 ;
     RECT  27.245 0.048 27.965 2.52 ;
     RECT  27.965 0.048 28.001 2.424 ;
     RECT  27.245 26.64 28.001 28.2 ;
     RECT  27.677 57.552 28.069 57.576 ;
     RECT  27.889 8.448 28.145 23.16 ;
     RECT  27.025 24.192 28.145 25.032 ;
     RECT  27.493 40.752 28.145 40.824 ;
     RECT  27.065 42.144 28.145 42.168 ;
     RECT  27.853 43.92 28.145 44.472 ;
     RECT  28.145 8.448 28.181 22.776 ;
     RECT  27.569 3.984 28.249 5.256 ;
     RECT  28.249 3.888 28.253 5.256 ;
     RECT  27.569 6.24 28.357 7.464 ;
     RECT  28.181 8.448 28.357 21.72 ;
     RECT  27.245 29.904 28.751 38.184 ;
     RECT  28.213 42.624 28.861 42.744 ;
     RECT  27.677 46.032 28.892 56.424 ;
     RECT  28.069 57.552 28.892 58.2 ;
     RECT  28.892 46.032 28.979 58.2 ;
     RECT  28.145 25.008 29.149 25.032 ;
     RECT  28.145 40.8 29.185 40.824 ;
     RECT  28.181 22.752 29.257 22.776 ;
     RECT  28.001 0.048 29.408 1.752 ;
     RECT  28.253 3.888 29.408 5.112 ;
     RECT  28.357 6.24 29.408 21.72 ;
     RECT  29.257 22.752 29.408 23.16 ;
     RECT  29.149 24.48 29.408 25.032 ;
     RECT  28.001 26.64 29.408 28.152 ;
     RECT  28.751 29.664 29.408 38.184 ;
     RECT  29.185 40.8 29.408 41.256 ;
     RECT  28.861 42.624 29.408 42.792 ;
     RECT  28.145 44.064 29.408 44.472 ;
     RECT  28.979 46.032 29.408 56.472 ;
     RECT  29.408 0.048 29.704 56.472 ;
     RECT  29.704 0.048 29.729 5.496 ;
     RECT  29.704 41.232 29.873 41.592 ;
     RECT  28.979 57.552 29.873 58.2 ;
     RECT  29.729 0.096 29.891 5.496 ;
     RECT  29.704 27.84 29.909 36.456 ;
     RECT  29.909 27.84 29.981 34.392 ;
     RECT  29.873 57.552 29.989 58.152 ;
     RECT  29.704 37.44 30.017 38.184 ;
     RECT  29.891 0.096 30.061 1.752 ;
     RECT  29.873 41.328 30.125 41.592 ;
     RECT  29.704 8.784 30.131 24.504 ;
     RECT  30.125 41.328 30.131 41.544 ;
     RECT  29.891 2.832 30.179 5.496 ;
     RECT  30.131 20.112 30.197 24.504 ;
     RECT  29.704 26.784 30.377 26.808 ;
     RECT  29.704 39.648 30.377 39.672 ;
     RECT  30.179 3.696 30.413 5.496 ;
     RECT  30.017 37.44 30.413 38.04 ;
     RECT  30.413 37.584 30.449 38.04 ;
     RECT  30.131 8.784 30.629 19.08 ;
     RECT  29.704 49.392 30.701 56.472 ;
     RECT  29.981 27.84 30.809 34.2 ;
     RECT  30.131 41.52 30.809 41.544 ;
     RECT  30.809 28.464 30.881 34.2 ;
     RECT  29.989 57.504 30.898 58.152 ;
     RECT  30.881 30.048 30.917 34.2 ;
     RECT  30.898 57.504 30.995 58.2 ;
     RECT  29.704 42.72 31.057 44.472 ;
     RECT  29.704 45.696 31.057 48.408 ;
     RECT  30.701 49.536 31.057 56.472 ;
     RECT  30.995 57.504 31.057 58.152 ;
     RECT  31.057 49.536 31.139 58.152 ;
     RECT  30.413 3.696 31.148 4.488 ;
     RECT  30.629 8.832 31.165 19.08 ;
     RECT  30.197 20.112 31.165 23.976 ;
     RECT  31.148 3.408 31.235 4.488 ;
     RECT  31.057 42.72 31.235 48.408 ;
     RECT  30.061 0.096 31.237 1.416 ;
     RECT  31.139 49.536 31.241 57.528 ;
     RECT  31.235 3.696 31.313 4.488 ;
     RECT  31.165 8.832 31.313 23.976 ;
     RECT  30.449 37.584 31.489 37.752 ;
     RECT  31.273 38.736 31.489 38.76 ;
     RECT  31.241 49.536 31.493 57 ;
     RECT  31.493 49.536 31.601 56.952 ;
     RECT  31.313 22.704 31.633 23.976 ;
     RECT  31.489 37.584 31.637 38.76 ;
     RECT  29.704 6.528 31.669 7.704 ;
     RECT  31.313 8.832 31.669 21.528 ;
     RECT  30.917 30.192 31.669 34.2 ;
     RECT  31.313 4.464 31.745 4.488 ;
     RECT  31.633 22.704 31.777 24.456 ;
     RECT  31.273 27.072 31.777 27.096 ;
     RECT  31.235 43.248 31.781 48.408 ;
     RECT  31.781 45.696 31.813 48.408 ;
     RECT  31.601 49.536 31.813 56.424 ;
     RECT  31.669 6.528 31.817 21.528 ;
     RECT  29.909 35.52 31.861 36.456 ;
     RECT  30.881 28.464 31.993 28.584 ;
     RECT  31.777 22.704 32.033 24.504 ;
     RECT  31.669 30.192 32.069 34.248 ;
     RECT  31.777 27.072 32.101 27.288 ;
     RECT  32.033 22.704 32.105 22.824 ;
     RECT  30.413 5.472 32.137 5.496 ;
     RECT  32.033 23.952 32.141 24.504 ;
     RECT  32.101 26.832 32.209 27.288 ;
     RECT  32.141 24.096 32.243 24.456 ;
     RECT  31.993 28.368 32.249 28.584 ;
     RECT  32.101 58.176 32.249 58.2 ;
     RECT  32.069 30.192 32.281 33.912 ;
     RECT  31.781 43.248 32.281 44.136 ;
     RECT  31.813 45.696 32.285 56.424 ;
     RECT  32.281 42.768 32.393 44.136 ;
     RECT  32.209 26.832 32.429 27.384 ;
     RECT  31.309 41.568 32.461 41.592 ;
     RECT  32.429 26.928 32.465 27.384 ;
     RECT  31.637 37.872 32.537 38.76 ;
     RECT  32.137 5.472 32.645 5.592 ;
     RECT  31.817 7.392 32.645 21.528 ;
     RECT  32.645 7.44 32.753 21.528 ;
     RECT  32.393 43.248 32.785 44.136 ;
     RECT  32.753 9.888 32.861 21.528 ;
     RECT  32.465 27.264 32.893 27.384 ;
     RECT  32.821 4.704 32.924 5.112 ;
     RECT  32.924 4.656 32.965 5.112 ;
     RECT  32.249 28.56 32.969 28.584 ;
     RECT  31.861 35.52 33.004 36.504 ;
     RECT  32.389 25.68 33.005 25.704 ;
     RECT  32.893 27.264 33.005 27.432 ;
     RECT  32.281 29.952 33.005 33.912 ;
     RECT  32.785 43.248 33.013 44.664 ;
     RECT  32.285 45.696 33.013 56.376 ;
     RECT  33.004 35.52 33.037 36.552 ;
     RECT  32.537 37.872 33.037 37.896 ;
     RECT  33.005 29.952 33.077 32.712 ;
     RECT  33.005 33.744 33.077 33.912 ;
     RECT  33.037 35.52 33.077 37.896 ;
     RECT  32.861 9.936 33.113 21.528 ;
     RECT  33.037 57.6 33.157 57.624 ;
     RECT  33.013 43.248 33.253 56.376 ;
     RECT  33.157 57.552 33.253 57.624 ;
     RECT  33.253 43.248 33.347 57.624 ;
     RECT  33.077 31.44 33.365 32.712 ;
     RECT  33.077 35.952 33.437 37.896 ;
     RECT  33.301 40.128 33.469 40.152 ;
     RECT  32.461 41.568 33.469 42.216 ;
     RECT  33.113 9.936 33.509 19.8 ;
     RECT  33.347 44.784 33.545 57.624 ;
     RECT  33.077 33.792 33.649 33.912 ;
     RECT  33.469 40.128 33.653 42.216 ;
     RECT  33.545 46.032 33.685 57.624 ;
     RECT  32.857 6.096 33.721 6.12 ;
     RECT  32.753 7.44 33.721 8.136 ;
     RECT  32.105 22.704 33.721 22.776 ;
     RECT  32.243 24.096 33.721 24.12 ;
     RECT  33.077 29.952 33.721 30.456 ;
     RECT  33.653 40.896 33.725 42.216 ;
     RECT  33.721 6.096 33.793 8.136 ;
     RECT  33.649 33.792 33.865 33.96 ;
     RECT  33.793 6.096 33.901 8.76 ;
     RECT  33.509 9.936 33.901 13.08 ;
     RECT  32.965 3.888 33.937 5.112 ;
     RECT  33.901 6.096 33.937 13.08 ;
     RECT  33.005 27.36 34.045 27.432 ;
     RECT  31.237 0.096 34.076 1.752 ;
     RECT  33.685 46.032 34.405 58.152 ;
     RECT  33.437 35.952 34.453 37.656 ;
     RECT  33.721 29.52 34.477 30.456 ;
     RECT  33.365 31.44 34.477 32.28 ;
     RECT  33.865 33.792 34.501 34.776 ;
     RECT  34.453 35.808 34.501 37.656 ;
     RECT  33.509 14.4 34.513 19.8 ;
     RECT  33.113 21.168 34.513 21.528 ;
     RECT  33.347 43.248 34.585 43.272 ;
     RECT  33.545 44.784 34.585 44.952 ;
     RECT  34.585 43.248 34.645 44.952 ;
     RECT  34.405 46.032 34.645 58.2 ;
     RECT  33.937 3.888 34.657 13.08 ;
     RECT  34.513 14.4 34.657 21.528 ;
     RECT  34.477 29.52 34.657 32.28 ;
     RECT  34.501 33.792 34.657 37.656 ;
     RECT  34.076 0.096 34.669 2.28 ;
     RECT  34.669 0.48 34.808 2.28 ;
     RECT  34.657 3.888 34.808 21.528 ;
     RECT  33.721 22.704 34.808 25.032 ;
     RECT  34.045 27.36 34.808 27.912 ;
     RECT  34.657 29.52 34.808 37.656 ;
     RECT  34.441 38.784 34.808 38.808 ;
     RECT  34.045 39.84 34.808 39.864 ;
     RECT  33.725 41.184 34.808 42.216 ;
     RECT  34.645 43.248 34.808 58.2 ;
     RECT  34.808 0.48 35.021 58.2 ;
     RECT  35.021 0.48 35.104 56.472 ;
     RECT  35.104 5.088 35.219 6.12 ;
     RECT  35.104 22.752 35.219 22.776 ;
     RECT  35.104 24.72 35.219 27.384 ;
     RECT  35.021 57.888 35.219 58.2 ;
     RECT  35.104 0.48 35.245 1.752 ;
     RECT  35.104 19.248 35.245 21.672 ;
     RECT  35.245 0.48 35.273 0.84 ;
     RECT  35.219 57.984 35.309 58.2 ;
     RECT  35.309 58.08 35.315 58.2 ;
     RECT  35.219 5.088 35.356 5.976 ;
     RECT  35.356 5.088 35.363 5.736 ;
     RECT  35.104 16.8 35.363 18.264 ;
     RECT  35.104 29.952 35.381 32.424 ;
     RECT  35.363 16.8 35.453 18.168 ;
     RECT  35.245 19.248 35.453 19.992 ;
     RECT  35.104 8.496 35.489 15.768 ;
     RECT  35.104 37.632 35.561 38.76 ;
     RECT  35.363 5.088 35.741 5.304 ;
     RECT  35.489 8.496 35.849 9.24 ;
     RECT  35.741 5.088 36.029 5.112 ;
     RECT  35.104 7.44 36.029 7.464 ;
     RECT  35.104 33.648 36.065 36.408 ;
     RECT  35.104 39.84 36.097 43.56 ;
     RECT  35.104 44.64 36.097 45.048 ;
     RECT  36.097 39.84 36.133 45.048 ;
     RECT  35.104 46.032 36.133 56.472 ;
     RECT  36.133 39.84 36.197 56.472 ;
     RECT  35.104 3.264 36.241 3.288 ;
     RECT  36.065 33.648 36.245 33.96 ;
     RECT  36.241 3.264 36.281 3.432 ;
     RECT  36.245 33.648 36.317 33.912 ;
     RECT  35.381 29.952 36.323 30.36 ;
     RECT  35.561 37.728 36.349 38.76 ;
     RECT  36.197 39.84 36.349 57 ;
     RECT  35.453 16.8 36.421 18.072 ;
     RECT  35.453 19.248 36.421 19.848 ;
     RECT  36.323 30.336 36.457 30.36 ;
     RECT  35.381 31.344 36.457 32.424 ;
     RECT  36.281 3.408 36.493 3.432 ;
     RECT  36.421 16.8 36.497 19.848 ;
     RECT  36.493 3.408 36.533 3.864 ;
     RECT  36.317 33.648 36.641 33.672 ;
     RECT  35.219 24.72 36.661 27.048 ;
     RECT  35.104 28.512 36.661 28.536 ;
     RECT  36.349 37.728 36.701 57.624 ;
     RECT  35.489 10.656 36.709 15.768 ;
     RECT  36.661 24.72 36.748 28.536 ;
     RECT  36.709 10.368 36.749 15.768 ;
     RECT  36.748 24.72 36.785 27.048 ;
     RECT  36.749 10.368 36.821 15.432 ;
     RECT  36.821 10.368 36.853 10.68 ;
     RECT  36.701 37.728 36.893 58.2 ;
     RECT  35.849 9.072 36.925 9.24 ;
     RECT  36.853 10.32 36.925 10.68 ;
     RECT  36.497 16.8 36.961 19.608 ;
     RECT  36.893 38.448 36.965 58.2 ;
     RECT  36.065 35.712 36.997 36.408 ;
     RECT  36.925 9.072 37.009 10.68 ;
     RECT  36.997 35.712 37.033 36.6 ;
     RECT  37.009 10.32 37.037 10.68 ;
     RECT  36.785 24.72 37.073 26.28 ;
     RECT  36.457 30.336 37.073 32.424 ;
     RECT  37.037 10.32 37.217 10.392 ;
     RECT  35.245 21.168 37.217 21.672 ;
     RECT  36.965 38.976 37.217 44.232 ;
     RECT  37.033 35.712 37.285 37.032 ;
     RECT  37.009 9.072 37.289 9.24 ;
     RECT  36.961 16.416 37.289 19.608 ;
     RECT  37.289 9.216 37.397 9.24 ;
     RECT  36.821 11.76 37.433 15.432 ;
     RECT  37.073 24.72 37.501 25.128 ;
     RECT  37.073 31.44 37.537 32.424 ;
     RECT  37.537 31.44 37.649 33.384 ;
     RECT  36.965 45.552 37.667 58.2 ;
     RECT  37.465 5.664 37.685 6.264 ;
     RECT  37.285 34.8 37.685 37.032 ;
     RECT  36.533 3.84 37.757 3.864 ;
     RECT  36.997 7.968 37.969 7.992 ;
     RECT  37.667 49.68 37.973 58.2 ;
     RECT  37.649 32.4 38.005 33.384 ;
     RECT  37.073 26.256 38.041 26.28 ;
     RECT  37.685 35.712 38.041 37.032 ;
     RECT  37.973 56.352 38.117 58.2 ;
     RECT  36.748 28.512 38.149 28.536 ;
     RECT  37.969 7.344 38.195 7.992 ;
     RECT  38.149 28.416 38.195 28.536 ;
     RECT  38.041 26.256 38.221 26.712 ;
     RECT  38.117 56.4 38.233 58.2 ;
     RECT  38.195 7.344 38.297 7.416 ;
     RECT  37.433 11.76 38.297 15.384 ;
     RECT  37.685 5.664 38.333 5.688 ;
     RECT  38.221 26.256 38.341 26.808 ;
     RECT  37.217 38.976 38.365 39.864 ;
     RECT  37.217 41.04 38.365 44.232 ;
     RECT  38.297 14.736 38.369 15.384 ;
     RECT  38.369 14.736 38.405 15.288 ;
     RECT  38.341 26.256 38.428 26.952 ;
     RECT  37.073 30.336 38.473 30.36 ;
     RECT  38.297 11.76 38.477 13.32 ;
     RECT  35.273 0.816 38.513 0.84 ;
     RECT  37.217 21.168 38.549 21.24 ;
     RECT  37.289 16.416 38.579 19.416 ;
     RECT  38.405 14.736 38.621 15.048 ;
     RECT  37.217 10.368 38.725 10.392 ;
     RECT  38.549 21.216 38.725 21.24 ;
     RECT  37.069 22.752 38.725 22.776 ;
     RECT  37.501 24.048 38.725 25.128 ;
     RECT  38.725 22.752 38.761 25.128 ;
     RECT  37.667 45.552 38.761 48.696 ;
     RECT  37.973 49.68 38.761 55.224 ;
     RECT  38.725 21.216 38.773 21.672 ;
     RECT  38.761 22.752 38.773 25.224 ;
     RECT  38.725 9.504 38.797 10.392 ;
     RECT  38.041 35.712 38.797 37.416 ;
     RECT  38.365 38.784 38.797 44.232 ;
     RECT  38.579 16.416 38.801 17.448 ;
     RECT  38.797 35.712 38.821 44.232 ;
     RECT  38.801 16.416 38.837 16.44 ;
     RECT  38.821 35.712 38.941 44.472 ;
     RECT  38.761 45.552 38.941 55.224 ;
     RECT  38.428 26.256 38.945 26.904 ;
     RECT  38.005 32.4 38.945 34.152 ;
     RECT  38.941 35.712 39.049 55.224 ;
     RECT  38.621 14.832 39.053 15.048 ;
     RECT  38.579 18.432 39.085 19.416 ;
     RECT  39.049 35.52 39.121 55.224 ;
     RECT  39.053 14.832 39.161 14.904 ;
     RECT  38.195 28.416 39.205 28.44 ;
     RECT  38.473 30.192 39.205 30.36 ;
     RECT  38.945 32.496 39.349 34.152 ;
     RECT  39.121 35.52 39.349 55.32 ;
     RECT  38.773 21.216 39.373 25.224 ;
     RECT  38.945 26.256 39.373 26.808 ;
     RECT  38.477 12.768 39.397 13.32 ;
     RECT  38.233 56.448 39.473 58.2 ;
     RECT  39.473 56.4 39.673 58.2 ;
     RECT  38.797 2.832 39.805 3.432 ;
     RECT  38.797 9.504 39.877 10.488 ;
     RECT  38.477 11.76 39.877 11.784 ;
     RECT  39.805 2.832 39.913 3.96 ;
     RECT  39.625 15.888 39.913 15.912 ;
     RECT  39.193 6.288 39.973 6.312 ;
     RECT  39.205 28.416 39.985 30.36 ;
     RECT  39.973 6.24 40.057 6.312 ;
     RECT  38.297 7.344 40.057 7.368 ;
     RECT  40.057 6.24 40.069 7.368 ;
     RECT  39.985 28.416 40.069 30.6 ;
     RECT  39.349 32.496 40.069 55.32 ;
     RECT  39.913 2.832 40.208 4.536 ;
     RECT  40.069 5.568 40.208 7.368 ;
     RECT  39.877 9.504 40.208 11.784 ;
     RECT  39.397 12.768 40.208 13.704 ;
     RECT  39.161 14.88 40.208 14.904 ;
     RECT  39.913 15.888 40.208 16.392 ;
     RECT  38.801 17.424 40.208 17.448 ;
     RECT  39.085 18.432 40.208 19.656 ;
     RECT  39.373 21.216 40.208 26.808 ;
     RECT  40.069 28.416 40.208 55.32 ;
     RECT  39.673 56.4 40.208 58.152 ;
     RECT  40.208 2.148 40.312 58.152 ;
     RECT  40.312 2.418 40.504 58.152 ;
     RECT  40.504 21.12 40.701 25.32 ;
     RECT  40.504 2.88 40.709 9 ;
     RECT  40.504 34.416 40.709 58.152 ;
     RECT  40.709 51.36 40.741 58.152 ;
     RECT  40.701 22.56 40.817 25.32 ;
     RECT  40.709 3.408 40.835 9 ;
     RECT  40.504 12.528 40.889 13.32 ;
     RECT  40.709 34.416 40.997 49.848 ;
     RECT  40.997 34.416 41.069 48.696 ;
     RECT  40.835 3.408 41.123 8.376 ;
     RECT  40.504 14.4 41.141 16.392 ;
     RECT  40.504 26.784 41.177 26.808 ;
     RECT  40.741 51.36 41.249 58.2 ;
     RECT  40.504 30.336 41.321 30.84 ;
     RECT  41.123 7.392 41.357 8.376 ;
     RECT  40.817 22.56 41.393 24.936 ;
     RECT  41.141 14.4 41.501 14.856 ;
     RECT  40.504 17.424 41.501 19.56 ;
     RECT  40.701 21.12 41.597 21.384 ;
     RECT  41.501 19.536 41.651 19.56 ;
     RECT  41.501 17.424 41.681 18.216 ;
     RECT  41.597 20.544 41.681 21.384 ;
     RECT  41.123 3.408 41.749 6.024 ;
     RECT  41.393 22.704 41.785 24.936 ;
     RECT  41.249 51.36 41.785 57.576 ;
     RECT  41.785 22.704 41.857 25.512 ;
     RECT  41.821 26.88 41.857 26.904 ;
     RECT  40.889 13.296 41.929 13.32 ;
     RECT  41.681 17.808 41.933 18.216 ;
     RECT  41.749 2.544 41.965 6.024 ;
     RECT  41.857 26.88 41.969 27.048 ;
     RECT  40.504 32.208 42.145 32.472 ;
     RECT  41.857 22.704 42.149 25.56 ;
     RECT  41.069 34.656 42.179 48.696 ;
     RECT  42.181 1.152 42.217 1.176 ;
     RECT  41.965 2.16 42.217 6.024 ;
     RECT  41.357 7.392 42.253 7.416 ;
     RECT  40.997 49.728 42.253 49.848 ;
     RECT  41.785 51.312 42.253 57.576 ;
     RECT  40.504 10.176 42.289 10.2 ;
     RECT  42.179 34.656 42.293 44.232 ;
     RECT  42.179 45.6 42.323 48.696 ;
     RECT  41.929 13.296 42.325 14.04 ;
     RECT  42.217 1.152 42.329 6.024 ;
     RECT  42.289 10.176 42.361 10.824 ;
     RECT  41.141 16.368 42.365 16.392 ;
     RECT  42.253 49.728 42.371 57.576 ;
     RECT  42.371 49.728 42.419 51.912 ;
     RECT  42.149 22.704 42.473 25.512 ;
     RECT  41.321 30.336 42.505 30.744 ;
     RECT  42.145 32.16 42.505 32.472 ;
     RECT  42.473 23.52 42.545 25.512 ;
     RECT  42.371 52.944 42.577 57.576 ;
     RECT  42.329 1.152 42.611 5.592 ;
     RECT  41.353 0.048 42.721 0.072 ;
     RECT  42.361 10.176 42.721 10.968 ;
     RECT  42.661 19.248 42.748 19.416 ;
     RECT  42.721 0.048 42.757 0.168 ;
     RECT  42.073 29.088 42.757 29.112 ;
     RECT  42.505 30.336 42.757 32.472 ;
     RECT  42.757 29.088 42.841 32.472 ;
     RECT  42.253 7.248 42.869 7.416 ;
     RECT  42.841 30.336 42.905 32.472 ;
     RECT  42.869 7.248 42.937 7.272 ;
     RECT  42.793 16.56 42.937 16.584 ;
     RECT  41.933 17.808 42.937 17.832 ;
     RECT  41.681 21.12 42.937 21.384 ;
     RECT  42.721 10.08 43.009 10.968 ;
     RECT  42.325 12.48 43.009 14.04 ;
     RECT  42.937 16.56 43.045 17.832 ;
     RECT  42.905 32.16 43.085 32.472 ;
     RECT  41.969 27.024 43.153 27.048 ;
     RECT  42.611 1.632 43.157 5.592 ;
     RECT  43.009 10.08 43.157 14.04 ;
     RECT  42.293 34.896 43.157 44.232 ;
     RECT  43.157 5.568 43.193 5.592 ;
     RECT  43.045 16.56 43.373 17.928 ;
     RECT  43.153 26.736 43.373 27.048 ;
     RECT  43.085 32.208 43.409 32.472 ;
     RECT  42.419 49.728 43.441 51.864 ;
     RECT  43.157 35.472 43.445 44.232 ;
     RECT  42.937 6.72 43.481 7.272 ;
     RECT  43.157 10.08 43.481 12.552 ;
     RECT  42.748 19.392 43.481 19.416 ;
     RECT  42.433 33.744 43.513 33.768 ;
     RECT  42.541 8.496 43.58 8.52 ;
     RECT  42.545 23.52 43.58 25.32 ;
     RECT  43.373 26.736 43.58 26.856 ;
     RECT  43.58 23.52 43.633 26.856 ;
     RECT  43.633 23.52 43.667 26.76 ;
     RECT  42.937 21.12 43.729 21.672 ;
     RECT  43.667 23.52 43.729 25.32 ;
     RECT  43.513 33.648 43.765 33.768 ;
     RECT  43.58 8.304 43.805 8.52 ;
     RECT  42.757 0.048 43.873 0.6 ;
     RECT  43.373 16.56 43.949 17.784 ;
     RECT  43.445 35.952 43.981 44.232 ;
     RECT  42.323 45.6 43.981 48.648 ;
     RECT  43.441 49.728 44.051 51.912 ;
     RECT  43.729 23.136 44.089 25.32 ;
     RECT  43.157 1.632 44.147 4.392 ;
     RECT  43.873 0.048 44.197 0.648 ;
     RECT  44.147 1.632 44.197 1.8 ;
     RECT  43.481 12 44.201 12.552 ;
     RECT  43.729 20.928 44.233 21.672 ;
     RECT  44.089 23.088 44.233 25.32 ;
     RECT  42.841 29.088 44.233 29.112 ;
     RECT  42.905 30.336 44.233 30.984 ;
     RECT  44.233 29.088 44.273 30.984 ;
     RECT  43.157 13.632 44.341 13.656 ;
     RECT  43.981 35.952 44.377 48.648 ;
     RECT  44.051 49.728 44.377 49.752 ;
     RECT  44.147 3.168 44.417 4.392 ;
     RECT  44.377 35.952 44.444 49.752 ;
     RECT  42.577 52.944 44.449 58.296 ;
     RECT  44.417 3.456 44.453 4.392 ;
     RECT  43.481 6.912 44.453 7.272 ;
     RECT  44.233 20.928 44.489 25.32 ;
     RECT  44.051 50.784 44.593 51.912 ;
     RECT  44.449 52.896 44.593 58.296 ;
     RECT  43.477 5.664 44.629 5.688 ;
     RECT  44.453 3.744 44.633 4.392 ;
     RECT  43.667 26.64 44.633 26.76 ;
     RECT  44.341 13.056 44.701 13.656 ;
     RECT  43.549 14.784 44.701 14.952 ;
     RECT  43.481 10.752 44.737 10.92 ;
     RECT  44.273 29.568 44.809 30.984 ;
     RECT  43.409 32.208 44.809 32.232 ;
     RECT  43.765 33.552 44.809 34.2 ;
     RECT  44.444 35.472 44.809 49.752 ;
     RECT  43.805 8.496 44.845 8.52 ;
     RECT  44.845 8.304 44.917 8.712 ;
     RECT  44.089 9.744 44.917 9.768 ;
     RECT  44.809 29.568 44.917 32.232 ;
     RECT  44.809 33.552 44.917 49.752 ;
     RECT  43.949 16.656 44.953 17.784 ;
     RECT  44.917 18.768 44.953 18.792 ;
     RECT  44.197 0.048 45.011 1.8 ;
     RECT  45.011 0.048 45.107 1.128 ;
     RECT  45.107 0.048 45.203 0.6 ;
     RECT  44.737 10.752 45.205 11.016 ;
     RECT  44.201 12 45.205 12.024 ;
     RECT  44.453 6.912 45.241 6.936 ;
     RECT  45.205 10.752 45.349 12.024 ;
     RECT  44.701 13.056 45.349 14.952 ;
     RECT  44.593 50.784 45.389 58.296 ;
     RECT  44.917 29.568 45.421 49.752 ;
     RECT  45.389 50.784 45.421 58.2 ;
     RECT  44.917 8.304 45.493 9.768 ;
     RECT  45.349 10.752 45.493 14.952 ;
     RECT  44.489 22.8 45.565 24.936 ;
     RECT  44.629 5.664 45.608 5.784 ;
     RECT  45.241 6.864 45.608 6.936 ;
     RECT  45.493 8.304 45.608 14.952 ;
     RECT  44.953 16.656 45.608 18.792 ;
     RECT  44.489 20.928 45.608 20.952 ;
     RECT  45.565 22.56 45.608 24.936 ;
     RECT  44.633 26.64 45.608 26.664 ;
     RECT  44.677 27.936 45.608 27.96 ;
     RECT  45.421 29.568 45.608 58.2 ;
     RECT  45.608 2.148 45.904 58.2 ;
     RECT  45.904 49.536 46.067 58.2 ;
     RECT  46.067 49.536 46.163 56.424 ;
     RECT  45.904 14.256 46.217 14.952 ;
     RECT  45.203 0.048 46.321 0.072 ;
     RECT  46.177 1.44 46.321 1.464 ;
     RECT  45.904 6.816 46.505 10.968 ;
     RECT  46.067 57.456 46.685 58.2 ;
     RECT  45.904 28.464 46.739 28.968 ;
     RECT  46.505 9.648 46.787 10.968 ;
     RECT  46.505 6.816 46.829 8.568 ;
     RECT  45.904 12.096 46.897 12.936 ;
     RECT  45.904 31.728 46.897 48.456 ;
     RECT  45.904 30.24 46.937 30.6 ;
     RECT  46.163 49.536 46.937 54.168 ;
     RECT  45.904 4.512 46.973 5.352 ;
     RECT  46.829 8.256 47.045 8.568 ;
     RECT  46.163 55.152 47.077 56.424 ;
     RECT  46.685 57.456 47.077 57.576 ;
     RECT  46.897 31.728 47.084 48.504 ;
     RECT  46.937 49.536 47.084 50.664 ;
     RECT  46.321 0.048 47.149 1.464 ;
     RECT  47.084 31.728 47.171 50.664 ;
     RECT  45.904 16.656 47.185 19.08 ;
     RECT  47.185 16.416 47.257 19.08 ;
     RECT  47.077 55.152 47.261 57.576 ;
     RECT  46.897 12.096 47.317 13.128 ;
     RECT  46.217 14.256 47.317 14.28 ;
     RECT  46.937 30.336 47.317 30.6 ;
     RECT  47.171 31.728 47.317 48.984 ;
     RECT  46.829 6.816 47.369 6.84 ;
     RECT  45.904 2.496 47.405 2.856 ;
     RECT  46.973 5.328 47.405 5.352 ;
     RECT  47.317 12.096 47.405 14.28 ;
     RECT  47.405 13.536 47.441 14.28 ;
     RECT  46.739 28.944 47.473 28.968 ;
     RECT  46.787 10.032 47.477 10.968 ;
     RECT  47.473 28.944 47.513 29.064 ;
     RECT  45.904 22.32 47.581 24.936 ;
     RECT  47.477 10.272 47.612 10.968 ;
     RECT  47.405 12.096 47.612 12.216 ;
     RECT  47.261 57.456 47.621 57.576 ;
     RECT  47.045 8.496 47.693 8.568 ;
     RECT  47.612 10.272 47.699 12.216 ;
     RECT  47.441 14.112 47.725 14.28 ;
     RECT  47.621 57.504 47.801 57.576 ;
     RECT  47.405 2.592 47.905 2.856 ;
     RECT  47.513 29.04 47.977 29.064 ;
     RECT  47.317 30.336 47.977 48.984 ;
     RECT  47.977 29.04 47.981 48.984 ;
     RECT  47.725 14.112 48.013 14.472 ;
     RECT  47.257 15.456 48.013 19.08 ;
     RECT  47.257 21.12 48.049 21.144 ;
     RECT  46.937 51.696 48.049 54.168 ;
     RECT  47.261 55.152 48.049 56.424 ;
     RECT  45.904 27.168 48.089 27.192 ;
     RECT  48.013 4.56 48.193 4.584 ;
     RECT  48.013 14.112 48.233 19.08 ;
     RECT  47.981 29.04 48.305 33.096 ;
     RECT  48.233 14.256 48.373 19.08 ;
     RECT  48.049 20.976 48.373 21.144 ;
     RECT  47.905 2.592 48.409 3.432 ;
     RECT  48.193 4.512 48.409 4.584 ;
     RECT  47.149 0.048 48.421 1.512 ;
     RECT  48.409 2.496 48.421 3.432 ;
     RECT  48.373 14.256 48.421 19.128 ;
     RECT  48.373 20.4 48.421 21.144 ;
     RECT  47.699 12.192 48.449 12.216 ;
     RECT  48.305 29.04 48.557 31.416 ;
     RECT  47.171 50.496 48.589 50.664 ;
     RECT  48.049 51.696 48.589 56.424 ;
     RECT  48.589 50.496 48.661 56.424 ;
     RECT  48.553 6.816 48.689 6.84 ;
     RECT  48.409 4.512 48.697 5.352 ;
     RECT  47.699 10.272 48.697 10.968 ;
     RECT  48.689 6.816 48.716 7.176 ;
     RECT  48.697 4.512 48.755 5.784 ;
     RECT  47.693 8.496 48.757 8.52 ;
     RECT  48.697 12.528 48.809 13.128 ;
     RECT  48.305 33.072 48.809 33.096 ;
     RECT  48.809 12.528 48.817 12.6 ;
     RECT  47.981 34.608 48.913 48.984 ;
     RECT  48.661 49.968 48.913 56.424 ;
     RECT  48.757 8.496 48.917 9.048 ;
     RECT  48.913 34.608 48.997 56.424 ;
     RECT  47.801 57.552 48.997 57.576 ;
     RECT  48.949 33.6 49.021 33.624 ;
     RECT  48.997 34.608 49.021 57.576 ;
     RECT  47.581 22.32 49.025 25.752 ;
     RECT  49.025 22.56 49.057 25.752 ;
     RECT  48.421 0.048 49.061 3.432 ;
     RECT  48.716 6.816 49.061 7.368 ;
     RECT  49.021 33.6 49.139 57.576 ;
     RECT  48.421 14.256 49.201 21.144 ;
     RECT  48.557 29.664 49.273 31.416 ;
     RECT  48.697 10.272 49.309 11.064 ;
     RECT  48.755 5.328 49.313 5.784 ;
     RECT  49.139 57.552 49.373 57.576 ;
     RECT  49.061 7.344 49.417 7.368 ;
     RECT  49.309 10.08 49.417 11.064 ;
     RECT  48.817 12.528 49.417 12.552 ;
     RECT  49.201 13.584 49.489 21.144 ;
     RECT  48.917 9.024 49.561 9.048 ;
     RECT  49.417 10.08 49.561 12.552 ;
     RECT  49.313 5.328 49.565 5.352 ;
     RECT  49.273 29.664 49.709 32.328 ;
     RECT  49.061 0.048 49.817 2.904 ;
     RECT  49.417 7.344 50.137 7.896 ;
     RECT  49.709 30.144 50.137 32.328 ;
     RECT  49.139 33.6 50.137 56.472 ;
     RECT  50.137 30.144 50.149 56.472 ;
     RECT  49.373 57.552 50.149 58.2 ;
     RECT  50.137 6.912 50.173 7.896 ;
     RECT  49.561 9.024 50.173 12.552 ;
     RECT  49.057 22.56 50.245 26.424 ;
     RECT  50.173 6.912 50.281 12.552 ;
     RECT  49.489 13.584 50.281 21.192 ;
     RECT  50.149 30.144 50.281 58.2 ;
     RECT  50.245 22.464 50.317 26.424 ;
     RECT  50.281 6.912 50.497 21.192 ;
     RECT  50.317 22.272 50.497 26.424 ;
     RECT  49.417 28.128 50.497 28.152 ;
     RECT  50.065 4.704 50.533 4.728 ;
     RECT  50.281 30.144 50.677 58.296 ;
     RECT  50.533 4.656 50.821 4.728 ;
     RECT  49.817 0.048 50.857 1.512 ;
     RECT  49.817 2.496 50.857 2.904 ;
     RECT  50.497 6.912 50.929 26.424 ;
     RECT  50.929 6.912 50.965 26.808 ;
     RECT  50.857 0.048 51.008 2.904 ;
     RECT  50.821 3.888 51.008 4.728 ;
     RECT  50.965 6.096 51.008 26.808 ;
     RECT  50.497 28.128 51.008 28.536 ;
     RECT  50.677 29.568 51.008 58.296 ;
     RECT  51.008 0.048 51.304 58.296 ;
     RECT  51.304 14.4 51.545 26.808 ;
     RECT  51.545 14.4 51.587 23.304 ;
     RECT  51.545 24.912 51.635 26.808 ;
     RECT  51.304 55.872 51.689 58.296 ;
     RECT  51.304 0.048 51.797 3.336 ;
     RECT  51.304 37.056 51.797 44.808 ;
     RECT  51.304 4.656 51.833 13.128 ;
     RECT  51.304 28.512 51.941 34.92 ;
     RECT  51.797 37.056 51.941 44.712 ;
     RECT  51.941 29.472 52.067 34.92 ;
     RECT  51.797 0.048 52.085 1.8 ;
     RECT  51.833 4.656 52.157 12.024 ;
     RECT  51.635 24.912 52.193 26.232 ;
     RECT  52.157 6.768 52.301 12.024 ;
     RECT  51.587 14.4 52.333 21.48 ;
     RECT  51.941 37.056 52.405 44.568 ;
     RECT  51.587 22.752 52.549 23.304 ;
     RECT  51.833 13.056 52.589 13.128 ;
     RECT  52.333 14.16 52.621 21.48 ;
     RECT  52.549 22.752 52.621 23.4 ;
     RECT  51.797 2.784 52.729 3.336 ;
     RECT  52.157 4.656 52.729 5.64 ;
     RECT  51.689 58.272 52.741 58.296 ;
     RECT  52.193 24.912 52.765 25.512 ;
     RECT  52.085 0.096 52.813 1.8 ;
     RECT  51.304 45.984 52.837 54.6 ;
     RECT  51.689 55.872 52.837 57.144 ;
     RECT  52.589 13.056 52.883 13.08 ;
     RECT  52.621 14.16 52.981 23.4 ;
     RECT  52.813 0.576 52.988 1.8 ;
     RECT  52.729 2.784 52.988 5.64 ;
     RECT  52.765 24.864 53.057 25.512 ;
     RECT  52.405 36.48 53.089 44.568 ;
     RECT  52.837 45.984 53.089 57.144 ;
     RECT  52.988 0.576 53.093 5.64 ;
     RECT  53.089 36.48 53.125 57.144 ;
     RECT  52.741 58.176 53.125 58.296 ;
     RECT  53.125 36.48 53.165 58.296 ;
     RECT  52.067 31.344 53.197 34.92 ;
     RECT  52.369 28.464 53.201 28.488 ;
     RECT  52.301 7.2 53.305 12.024 ;
     RECT  53.093 4.8 53.413 5.64 ;
     RECT  53.305 6.912 53.413 12.024 ;
     RECT  53.413 4.8 53.449 12.024 ;
     RECT  53.197 31.344 53.557 35.064 ;
     RECT  53.093 0.576 53.596 3.432 ;
     RECT  52.981 14.16 53.597 23.64 ;
     RECT  53.557 31.344 53.605 35.304 ;
     RECT  53.165 36.48 53.605 36.504 ;
     RECT  52.067 29.472 53.629 30.36 ;
     RECT  53.449 4.8 53.741 12.744 ;
     RECT  53.605 31.344 53.741 36.504 ;
     RECT  53.165 37.632 53.741 58.296 ;
     RECT  53.596 0.576 53.885 3.336 ;
     RECT  53.597 14.4 53.921 23.64 ;
     RECT  53.885 0.576 53.989 3.288 ;
     RECT  53.921 14.688 53.993 23.64 ;
     RECT  53.741 31.344 54.137 31.368 ;
     RECT  53.741 5.04 54.169 12.744 ;
     RECT  53.741 32.352 54.205 36.504 ;
     RECT  53.741 37.632 54.205 57.144 ;
     RECT  53.629 29.232 54.385 30.36 ;
     RECT  53.989 0.096 54.389 3.288 ;
     RECT  53.993 22.464 54.565 23.64 ;
     RECT  53.057 24.864 54.565 24.888 ;
     RECT  53.377 27.072 54.637 27.096 ;
     RECT  54.637 27.072 54.677 27.912 ;
     RECT  54.169 5.04 54.709 12.792 ;
     RECT  54.677 27.888 54.709 27.912 ;
     RECT  54.385 29.232 54.709 30.456 ;
     RECT  54.709 5.04 54.853 12.84 ;
     RECT  54.205 32.352 54.899 57.144 ;
     RECT  53.993 14.688 54.961 21.48 ;
     RECT  54.565 22.464 54.961 24.888 ;
     RECT  54.899 32.352 54.965 57.048 ;
     RECT  54.853 4.464 54.997 12.888 ;
     RECT  54.709 27.888 55.001 30.456 ;
     RECT  54.965 32.352 55.001 32.472 ;
     RECT  55.001 28.512 55.037 30.456 ;
     RECT  53.741 58.128 55.073 58.296 ;
     RECT  55.004 26.448 55.091 26.472 ;
     RECT  54.961 14.688 55.109 24.888 ;
     RECT  55.073 58.128 55.116 58.2 ;
     RECT  54.997 4.368 55.177 13.032 ;
     RECT  55.116 58.08 55.217 58.2 ;
     RECT  55.177 4.368 55.249 13.08 ;
     RECT  55.037 30.192 55.285 30.456 ;
     RECT  55.001 32.448 55.325 32.472 ;
     RECT  55.217 58.176 55.325 58.2 ;
     RECT  55.285 30.192 55.331 30.792 ;
     RECT  55.109 14.688 55.357 24.84 ;
     RECT  55.357 14.4 55.361 24.84 ;
     RECT  55.249 4.368 55.393 13.128 ;
     RECT  55.361 14.4 55.393 24.504 ;
     RECT  54.965 33.552 55.433 57.048 ;
     RECT  55.037 28.512 56.221 28.776 ;
     RECT  55.969 32.304 56.329 32.328 ;
     RECT  55.433 33.552 56.329 34.248 ;
     RECT  54.389 0.096 56.408 3.144 ;
     RECT  55.393 4.368 56.408 24.504 ;
     RECT  56.221 28.512 56.408 29.016 ;
     RECT  55.331 30.336 56.408 30.792 ;
     RECT  56.329 32.304 56.408 34.248 ;
     RECT  55.433 35.28 56.408 57.048 ;
     RECT  56.408 0.096 56.581 57.048 ;
     RECT  56.581 0.096 56.704 57.576 ;
     RECT  56.704 6.384 56.729 22.584 ;
     RECT  56.704 36.24 56.765 57.576 ;
     RECT  56.704 3.168 56.819 5.4 ;
     RECT  56.729 6.384 56.819 21.672 ;
     RECT  56.819 4.56 56.945 5.4 ;
     RECT  56.704 31.872 56.981 34.92 ;
     RECT  56.819 6.864 56.989 21.672 ;
     RECT  56.704 0.096 57.004 1.896 ;
     RECT  56.989 14.4 57.053 21.672 ;
     RECT  56.981 31.872 57.053 34.248 ;
     RECT  56.989 6.864 57.059 13.08 ;
     RECT  57.004 0.096 57.197 1.848 ;
     RECT  56.704 27.408 57.269 30.6 ;
     RECT  57.269 27.456 57.377 30.6 ;
     RECT  56.765 36.24 57.395 57 ;
     RECT  57.157 58.128 57.637 58.152 ;
     RECT  57.637 58.128 57.733 58.2 ;
     RECT  57.197 0.096 57.737 1.752 ;
     RECT  56.819 3.168 57.737 3.432 ;
     RECT  57.737 3.168 57.773 3.192 ;
     RECT  57.395 36.24 57.809 56.376 ;
     RECT  56.945 4.992 57.845 5.4 ;
     RECT  56.704 26.256 57.913 26.28 ;
     RECT  57.377 27.888 57.985 30.6 ;
     RECT  57.053 31.872 57.985 32.424 ;
     RECT  57.737 0.096 58.021 1.512 ;
     RECT  57.059 8.496 58.057 13.08 ;
     RECT  57.053 14.4 58.057 21.528 ;
     RECT  57.053 33.552 58.065 34.248 ;
     RECT  58.065 33.552 58.076 35.016 ;
     RECT  57.809 36.24 58.076 36.792 ;
     RECT  57.059 6.864 58.117 7.416 ;
     RECT  58.057 8.496 58.117 21.528 ;
     RECT  57.913 26.16 58.124 26.28 ;
     RECT  58.076 33.552 58.163 36.792 ;
     RECT  58.117 6.864 58.169 21.528 ;
     RECT  58.163 33.552 58.169 35.016 ;
     RECT  56.704 24.48 58.205 24.504 ;
     RECT  57.845 5.04 58.241 5.4 ;
     RECT  57.985 27.888 58.381 32.424 ;
     RECT  57.809 37.968 58.405 56.376 ;
     RECT  57.733 57.552 58.405 58.2 ;
     RECT  58.124 26.16 58.453 26.328 ;
     RECT  58.163 36.24 58.457 36.792 ;
     RECT  58.169 7.344 58.561 21.528 ;
     RECT  58.453 24.672 58.597 26.328 ;
     RECT  58.381 27.408 58.597 32.424 ;
     RECT  58.241 5.04 58.601 5.064 ;
     RECT  58.405 37.968 58.601 58.2 ;
     RECT  58.597 24.672 58.633 32.424 ;
     RECT  58.169 33.552 58.633 33.576 ;
     RECT  58.601 37.968 58.691 56.424 ;
     RECT  58.561 7.344 58.745 22.248 ;
     RECT  58.093 3.024 58.781 3.048 ;
     RECT  58.601 57.504 58.925 58.2 ;
     RECT  58.457 36.768 58.957 36.792 ;
     RECT  58.691 37.968 58.957 37.992 ;
     RECT  58.633 24.672 59.069 33.576 ;
     RECT  59.069 29.904 59.249 33.576 ;
     RECT  59.249 30.048 59.281 33.576 ;
     RECT  58.169 34.992 59.281 35.016 ;
     RECT  58.745 8.496 59.317 22.248 ;
     RECT  59.317 8.496 59.357 22.776 ;
     RECT  58.691 39.072 59.357 56.424 ;
     RECT  59.357 39.216 59.465 56.424 ;
     RECT  58.957 36.768 59.497 37.992 ;
     RECT  58.925 57.504 59.537 58.152 ;
     RECT  59.605 6.24 59.749 6.264 ;
     RECT  58.745 7.344 59.749 7.416 ;
     RECT  59.281 30.048 59.753 35.016 ;
     RECT  59.537 57.552 59.789 58.152 ;
     RECT  59.753 33.552 59.821 35.016 ;
     RECT  59.497 36.384 59.821 37.992 ;
     RECT  59.641 5.136 59.825 5.16 ;
     RECT  59.749 6.24 59.833 7.416 ;
     RECT  59.789 57.648 59.921 58.152 ;
     RECT  59.069 24.672 59.929 28.728 ;
     RECT  59.753 30.048 60.041 32.424 ;
     RECT  59.833 7.344 60.109 7.416 ;
     RECT  59.357 8.496 60.109 21.672 ;
     RECT  60.109 7.344 60.113 21.672 ;
     RECT  59.281 2.88 60.145 2.904 ;
     RECT  59.929 24.48 60.145 28.728 ;
     RECT  59.821 33.552 60.149 37.992 ;
     RECT  60.145 2.88 60.185 3.864 ;
     RECT  60.145 23.904 60.287 28.728 ;
     RECT  60.041 30.048 60.287 32.328 ;
     RECT  59.357 22.752 60.373 22.776 ;
     RECT  60.287 23.904 60.373 32.328 ;
     RECT  60.149 36.48 60.433 37.992 ;
     RECT  60.113 7.344 60.445 21.528 ;
     RECT  60.373 22.752 60.46 32.328 ;
     RECT  60.433 36.48 60.473 38.184 ;
     RECT  60.149 33.552 60.509 35.496 ;
     RECT  59.465 39.456 60.509 56.424 ;
     RECT  60.445 7.344 60.581 20.376 ;
     RECT  60.509 39.792 60.805 56.424 ;
     RECT  59.833 6.24 60.865 6.264 ;
     RECT  60.473 36.912 60.865 38.184 ;
     RECT  58.021 0.048 60.901 1.512 ;
     RECT  60.865 5.472 61.045 6.264 ;
     RECT  60.581 7.344 61.045 20.328 ;
     RECT  59.921 57.648 61.189 58.2 ;
     RECT  61.045 5.472 61.369 20.328 ;
     RECT  60.901 0.048 61.381 1.56 ;
     RECT  61.381 0.048 61.477 1.752 ;
     RECT  60.46 23.904 61.477 32.328 ;
     RECT  60.509 33.552 61.477 33.672 ;
     RECT  60.445 21.504 61.513 21.528 ;
     RECT  60.46 22.752 61.513 22.776 ;
     RECT  61.369 5.088 61.573 20.328 ;
     RECT  61.513 21.504 61.573 22.776 ;
     RECT  61.477 0.048 61.649 1.848 ;
     RECT  61.573 5.088 61.649 22.776 ;
     RECT  61.649 0.048 61.657 1.896 ;
     RECT  61.657 0.048 61.693 1.992 ;
     RECT  61.649 5.088 61.693 22.824 ;
     RECT  61.477 23.904 61.693 33.672 ;
     RECT  60.509 34.752 61.765 35.496 ;
     RECT  61.693 0.048 61.808 2.856 ;
     RECT  60.185 3.84 61.808 3.864 ;
     RECT  61.693 5.088 61.808 33.672 ;
     RECT  61.765 34.752 61.808 35.736 ;
     RECT  60.865 36.912 61.808 38.808 ;
     RECT  60.805 39.792 61.808 56.472 ;
     RECT  61.808 0.048 62.104 56.472 ;
     RECT  62.104 3.84 62.237 35.784 ;
     RECT  62.237 3.84 62.345 35.736 ;
     RECT  62.345 21.984 62.453 35.736 ;
     RECT  62.104 39.744 62.453 56.472 ;
     RECT  62.104 36.912 62.741 38.76 ;
     RECT  62.453 39.744 62.741 56.424 ;
     RECT  61.189 57.552 62.917 58.2 ;
     RECT  62.741 39.744 62.921 54.888 ;
     RECT  62.741 37.44 63.029 38.76 ;
     RECT  62.345 3.84 63.097 20.616 ;
     RECT  62.917 57.504 63.101 58.2 ;
     RECT  62.453 21.984 63.137 35.016 ;
     RECT  63.029 37.44 63.137 38.712 ;
     RECT  63.101 57.552 63.209 58.2 ;
     RECT  63.137 21.984 63.317 28.824 ;
     RECT  63.317 21.984 63.353 28.584 ;
     RECT  63.137 29.904 63.353 35.016 ;
     RECT  63.097 3.408 63.452 20.616 ;
     RECT  63.353 21.984 63.452 22.056 ;
     RECT  62.104 0.048 63.529 1.944 ;
     RECT  63.452 3.408 63.539 22.056 ;
     RECT  63.529 0.048 63.745 2.28 ;
     RECT  63.539 3.408 63.745 20.616 ;
     RECT  62.921 43.824 63.781 54.888 ;
     RECT  62.741 55.872 63.781 56.424 ;
     RECT  63.745 0.048 63.893 20.616 ;
     RECT  63.137 37.44 63.965 38.328 ;
     RECT  62.921 39.744 64.001 42.6 ;
     RECT  64.001 42.24 64.073 42.6 ;
     RECT  64.001 39.744 64.177 41.256 ;
     RECT  63.313 36.384 64.285 36.408 ;
     RECT  63.353 23.088 64.357 28.584 ;
     RECT  63.781 43.824 64.357 56.424 ;
     RECT  64.073 42.288 64.361 42.6 ;
     RECT  63.353 29.904 64.393 34.104 ;
     RECT  64.285 35.568 64.393 36.408 ;
     RECT  64.357 43.632 64.397 56.424 ;
     RECT  64.393 29.904 64.405 36.408 ;
     RECT  63.965 37.44 64.405 37.464 ;
     RECT  64.405 29.904 64.451 37.464 ;
     RECT  63.209 58.176 64.453 58.2 ;
     RECT  64.357 23.04 64.501 28.584 ;
     RECT  63.893 7.968 64.541 20.616 ;
     RECT  64.361 42.288 64.721 42.504 ;
     RECT  64.397 56.256 64.796 56.424 ;
     RECT  64.177 39.312 64.861 41.256 ;
     RECT  64.451 33.408 64.865 36.504 ;
     RECT  64.861 38.928 64.937 41.256 ;
     RECT  64.796 56.256 64.997 56.472 ;
     RECT  64.453 57.552 64.997 58.2 ;
     RECT  63.539 21.984 65.005 22.056 ;
     RECT  63.893 0.048 65.009 6.888 ;
     RECT  64.397 43.632 65.009 55.272 ;
     RECT  65.009 0.048 65.045 5.256 ;
     RECT  64.451 29.904 65.081 32.232 ;
     RECT  65.009 43.824 65.081 55.272 ;
     RECT  64.997 56.256 65.081 58.2 ;
     RECT  64.865 36.48 65.189 36.504 ;
     RECT  65.005 21.648 65.317 22.056 ;
     RECT  64.501 23.04 65.317 28.824 ;
     RECT  65.009 6.432 65.437 6.888 ;
     RECT  64.541 7.968 65.437 20.52 ;
     RECT  65.317 21.648 65.437 28.824 ;
     RECT  65.081 29.904 65.437 32.088 ;
     RECT  65.081 45.456 65.468 55.272 ;
     RECT  65.081 56.256 65.468 56.424 ;
     RECT  64.937 38.928 65.581 39.768 ;
     RECT  65.437 6.432 65.585 20.52 ;
     RECT  65.437 21.648 65.585 32.088 ;
     RECT  64.865 33.408 65.905 35.208 ;
     RECT  65.581 38.16 65.977 39.768 ;
     RECT  64.937 40.896 65.977 41.256 ;
     RECT  64.721 42.384 65.977 42.504 ;
     RECT  65.977 38.16 66.053 42.504 ;
     RECT  65.585 6.432 66.085 20.328 ;
     RECT  66.053 38.688 66.197 42.504 ;
     RECT  65.585 23.28 66.481 32.088 ;
     RECT  65.045 0.048 66.589 4.968 ;
     RECT  66.481 23.28 66.625 32.232 ;
     RECT  65.905 33.408 66.625 35.832 ;
     RECT  65.081 43.824 66.661 44.376 ;
     RECT  65.468 45.456 66.661 56.424 ;
     RECT  66.661 43.824 66.757 56.424 ;
     RECT  65.081 57.552 66.757 58.2 ;
     RECT  66.757 43.824 66.908 58.2 ;
     RECT  66.085 6.336 66.949 20.328 ;
     RECT  65.585 21.648 66.949 22.056 ;
     RECT  66.197 40.32 66.949 42.504 ;
     RECT  66.908 43.536 66.949 58.2 ;
     RECT  66.949 40.32 66.985 58.2 ;
     RECT  66.589 0.048 67.165 5.304 ;
     RECT  66.949 6.336 67.165 22.056 ;
     RECT  66.625 23.28 67.201 35.832 ;
     RECT  67.165 0.048 67.208 22.056 ;
     RECT  67.201 23.28 67.208 36.6 ;
     RECT  66.197 38.688 67.208 39.336 ;
     RECT  66.985 40.32 67.208 58.296 ;
     RECT  67.208 0.048 67.504 58.296 ;
     RECT  67.504 40.32 67.789 41.736 ;
     RECT  67.789 40.32 68.033 41.256 ;
     RECT  68.033 41.088 68.069 41.256 ;
     RECT  67.504 0.048 68.141 33.288 ;
     RECT  67.504 34.368 68.195 36.6 ;
     RECT  68.141 0.096 68.677 33.288 ;
     RECT  68.195 34.368 68.677 35.064 ;
     RECT  68.195 36.048 69.113 36.6 ;
     RECT  69.113 36.336 69.149 36.6 ;
     RECT  68.677 0.096 69.617 35.064 ;
     RECT  69.149 36.576 69.757 36.6 ;
     RECT  69.617 0.096 69.833 32.568 ;
     RECT  67.504 43.824 69.973 58.296 ;
     RECT  68.069 41.088 70.161 41.112 ;
     RECT  69.833 0.096 70.193 19.416 ;
     RECT  70.124 37.824 70.211 37.848 ;
     RECT  67.504 39.216 70.265 39.24 ;
     RECT  70.193 0.096 70.381 19.32 ;
     RECT  70.381 0.528 70.451 19.32 ;
     RECT  69.757 36.576 70.549 36.648 ;
     RECT  70.549 36.048 70.585 36.648 ;
     RECT  69.833 20.496 70.741 32.568 ;
     RECT  69.617 33.6 70.741 35.064 ;
     RECT  70.741 20.496 71.053 35.064 ;
     RECT  70.585 36.048 71.053 37.08 ;
     RECT  69.973 43.344 71.093 58.296 ;
     RECT  71.053 20.496 71.237 37.08 ;
     RECT  70.451 0.768 71.273 19.32 ;
     RECT  70.161 41.088 71.276 41.736 ;
     RECT  71.093 43.344 71.276 57.576 ;
     RECT  70.549 38.784 71.345 38.808 ;
     RECT  71.237 21.648 71.377 37.08 ;
     RECT  71.237 20.496 71.411 20.52 ;
     RECT  71.276 41.088 71.809 57.576 ;
     RECT  71.809 40.368 72.133 57.576 ;
     RECT  71.273 0.768 72.277 18.792 ;
     RECT  72.277 0.768 72.421 19.32 ;
     RECT  71.449 38.736 72.529 38.76 ;
     RECT  72.421 0.768 72.608 19.416 ;
     RECT  72.241 20.592 72.608 20.616 ;
     RECT  71.377 21.648 72.608 37.176 ;
     RECT  72.529 38.256 72.608 39 ;
     RECT  72.133 40.368 72.608 58.2 ;
     RECT  72.608 0.768 72.865 58.2 ;
     RECT  72.865 0.768 72.904 57.576 ;
     RECT  72.904 40.608 72.965 57.576 ;
     RECT  72.965 40.608 73.613 42.6 ;
     RECT  72.904 0.768 73.753 19.32 ;
     RECT  72.965 43.632 74.041 57.576 ;
     RECT  72.904 20.496 74.045 37.176 ;
     RECT  74.045 20.928 74.113 37.176 ;
     RECT  74.113 20.928 74.185 37.272 ;
     RECT  72.904 38.448 74.185 39.384 ;
     RECT  74.185 20.928 74.189 39.384 ;
     RECT  74.041 43.632 74.291 57.624 ;
     RECT  73.753 0.576 74.341 19.32 ;
     RECT  74.291 43.632 74.369 57.576 ;
     RECT  74.189 20.928 74.387 38.808 ;
     RECT  74.341 0.096 74.441 19.32 ;
     RECT  74.441 0.096 74.693 19.272 ;
     RECT  74.387 38.448 74.693 38.808 ;
     RECT  73.613 40.896 74.801 42.6 ;
     RECT  74.693 38.784 75.157 38.808 ;
     RECT  74.693 0.096 75.269 18.84 ;
     RECT  74.387 20.928 75.269 37.128 ;
     RECT  74.369 43.824 75.397 57.576 ;
     RECT  75.269 34.08 75.485 37.128 ;
     RECT  75.269 20.928 75.521 33.048 ;
     RECT  75.521 20.928 75.589 20.952 ;
     RECT  75.269 17.28 75.841 18.84 ;
     RECT  75.841 17.28 75.877 19.272 ;
     RECT  75.589 20.304 75.877 20.952 ;
     RECT  75.269 0.096 75.913 15.912 ;
     RECT  75.397 43.824 75.971 58.2 ;
     RECT  75.521 21.984 75.989 33.048 ;
     RECT  75.157 38.784 76.069 39.48 ;
     RECT  76.069 38.784 76.093 39.912 ;
     RECT  75.485 34.08 76.097 36.936 ;
     RECT  75.913 0.048 76.115 15.912 ;
     RECT  76.093 38.64 76.237 39.912 ;
     RECT  76.237 38.064 76.313 39.912 ;
     RECT  75.989 32.496 76.417 33.048 ;
     RECT  76.097 34.08 76.417 36.6 ;
     RECT  76.313 38.064 76.745 38.184 ;
     RECT  74.801 41.04 76.813 42.6 ;
     RECT  75.971 43.824 76.813 54.696 ;
     RECT  75.877 17.28 76.889 20.952 ;
     RECT  76.889 18.672 76.921 20.952 ;
     RECT  75.989 21.984 76.921 31.512 ;
     RECT  76.813 41.04 76.957 54.696 ;
     RECT  75.971 55.872 76.957 58.2 ;
     RECT  76.957 41.04 76.961 58.2 ;
     RECT  76.961 56.112 76.997 58.2 ;
     RECT  76.889 17.28 77.065 17.688 ;
     RECT  76.921 18.672 77.137 31.512 ;
     RECT  76.417 32.496 77.137 36.6 ;
     RECT  76.961 41.04 77.137 54.984 ;
     RECT  76.115 0.048 77.425 15.624 ;
     RECT  77.425 0.048 77.509 15.96 ;
     RECT  77.065 16.992 77.509 17.688 ;
     RECT  77.137 18.672 77.533 36.6 ;
     RECT  76.997 56.304 77.747 58.2 ;
     RECT  77.509 0.048 78.008 17.688 ;
     RECT  77.533 18.672 78.008 36.984 ;
     RECT  76.745 38.112 78.008 38.184 ;
     RECT  76.313 39.216 78.008 39.912 ;
     RECT  77.137 40.944 78.008 54.984 ;
     RECT  77.747 56.304 78.008 56.328 ;
     RECT  78.008 0.048 78.304 56.328 ;
     RECT  78.304 22.56 78.365 39.816 ;
     RECT  78.304 43.104 78.401 56.328 ;
     RECT  78.365 22.56 78.617 34.728 ;
     RECT  78.365 35.856 78.659 39.816 ;
     RECT  78.617 22.56 78.689 34.44 ;
     RECT  78.401 43.728 78.689 56.328 ;
     RECT  78.304 41.088 78.707 42.024 ;
     RECT  78.707 41.088 78.725 41.16 ;
     RECT  78.304 18.816 78.761 21.48 ;
     RECT  78.689 46.848 78.761 56.328 ;
     RECT  78.304 17.04 78.833 17.352 ;
     RECT  78.761 47.04 78.949 56.328 ;
     RECT  77.747 57.552 78.949 58.2 ;
     RECT  78.659 36.096 79.049 39.816 ;
     RECT  78.304 0.048 79.265 16.008 ;
     RECT  78.689 22.56 79.265 33.384 ;
     RECT  79.265 24.384 79.337 33.384 ;
     RECT  79.265 22.56 79.369 23.208 ;
     RECT  79.049 39.072 79.513 39.816 ;
     RECT  78.689 43.728 79.549 45.576 ;
     RECT  78.761 19.2 79.693 21.48 ;
     RECT  79.369 22.464 79.693 23.208 ;
     RECT  79.549 43.632 79.765 45.576 ;
     RECT  78.833 17.328 79.793 17.352 ;
     RECT  79.793 17.328 79.804 18.216 ;
     RECT  79.693 19.2 79.804 23.208 ;
     RECT  79.337 24.624 79.837 33.384 ;
     RECT  78.689 34.368 79.837 34.44 ;
     RECT  79.804 17.328 79.877 23.208 ;
     RECT  79.049 36.096 79.985 38.04 ;
     RECT  79.877 17.328 80.021 17.352 ;
     RECT  79.513 39.072 80.089 39.912 ;
     RECT  79.877 18.768 80.093 23.208 ;
     RECT  79.265 0.048 80.129 15.96 ;
     RECT  78.725 41.088 80.156 41.112 ;
     RECT  79.765 43.632 80.204 46.056 ;
     RECT  80.156 41.088 80.243 41.304 ;
     RECT  80.089 38.784 80.269 39.912 ;
     RECT  80.243 41.088 80.269 41.112 ;
     RECT  80.093 19.2 80.273 23.208 ;
     RECT  80.204 42.72 80.291 46.056 ;
     RECT  79.837 24.624 80.305 34.44 ;
     RECT  79.985 36.096 80.305 37.128 ;
     RECT  80.273 19.248 80.341 23.208 ;
     RECT  78.949 47.04 80.345 58.2 ;
     RECT  80.305 24.624 80.453 37.128 ;
     RECT  80.341 19.248 80.593 23.592 ;
     RECT  80.453 24.624 80.593 26.088 ;
     RECT  80.291 42.768 80.665 46.056 ;
     RECT  80.345 47.04 80.665 55.944 ;
     RECT  80.453 27.168 80.813 37.128 ;
     RECT  80.665 42.768 80.849 55.944 ;
     RECT  80.813 33.648 80.993 37.128 ;
     RECT  80.813 27.168 81.101 32.28 ;
     RECT  80.917 17.088 81.169 17.208 ;
     RECT  80.993 33.696 81.173 37.128 ;
     RECT  80.269 38.784 81.253 41.112 ;
     RECT  81.173 33.696 81.281 34.68 ;
     RECT  80.593 19.248 81.313 26.088 ;
     RECT  80.129 0.048 81.353 13.416 ;
     RECT  80.849 44.16 81.389 55.944 ;
     RECT  81.389 55.872 81.404 55.944 ;
     RECT  81.353 0.048 81.425 0.552 ;
     RECT  81.253 38.784 81.443 41.544 ;
     RECT  80.129 14.4 81.457 15.96 ;
     RECT  81.169 17.04 81.457 17.208 ;
     RECT  81.443 38.784 81.457 39.912 ;
     RECT  81.457 38.688 81.491 39.912 ;
     RECT  81.404 55.872 81.491 55.992 ;
     RECT  81.491 38.688 81.497 39.096 ;
     RECT  81.101 27.36 81.533 32.28 ;
     RECT  81.313 19.2 81.673 26.088 ;
     RECT  81.353 1.728 81.709 13.416 ;
     RECT  81.457 14.4 81.709 17.208 ;
     RECT  80.345 56.976 81.709 58.2 ;
     RECT  81.443 41.04 81.781 41.544 ;
     RECT  81.533 30.816 81.817 32.28 ;
     RECT  81.781 41.04 81.821 41.592 ;
     RECT  81.389 44.16 81.821 54.744 ;
     RECT  81.709 1.728 81.853 17.208 ;
     RECT  81.853 1.728 81.857 17.64 ;
     RECT  81.673 19.2 81.857 26.328 ;
     RECT  81.425 0.096 81.875 0.552 ;
     RECT  81.281 33.696 81.961 33.96 ;
     RECT  81.857 12.336 82.037 17.64 ;
     RECT  81.817 30.816 82.069 32.424 ;
     RECT  81.173 36.096 82.073 37.128 ;
     RECT  81.821 44.976 82.181 54.744 ;
     RECT  81.709 56.88 82.189 58.2 ;
     RECT  80.849 42.768 82.217 42.792 ;
     RECT  81.857 20.592 82.253 26.328 ;
     RECT  82.037 16.512 82.309 17.64 ;
     RECT  81.857 19.2 82.309 19.464 ;
     RECT  82.309 16.512 82.396 19.464 ;
     RECT  82.396 19.2 82.397 19.464 ;
     RECT  81.857 1.728 82.405 11.256 ;
     RECT  81.491 55.872 82.501 55.896 ;
     RECT  82.189 56.88 82.501 58.152 ;
     RECT  82.501 55.872 82.505 58.152 ;
     RECT  82.253 26.304 82.508 26.328 ;
     RECT  81.533 27.36 82.508 29.784 ;
     RECT  82.508 26.304 82.681 29.784 ;
     RECT  82.069 30.816 82.681 32.52 ;
     RECT  82.405 1.68 82.853 11.256 ;
     RECT  81.875 0.096 82.873 0.12 ;
     RECT  82.681 26.304 82.933 32.52 ;
     RECT  81.961 33.648 82.933 33.96 ;
     RECT  82.505 55.872 83.005 57.576 ;
     RECT  82.037 12.336 83.041 15.528 ;
     RECT  82.396 16.512 83.041 18.024 ;
     RECT  82.397 19.248 83.077 19.464 ;
     RECT  82.253 20.592 83.077 25.32 ;
     RECT  83.005 55.68 83.081 57.576 ;
     RECT  82.933 26.304 83.125 33.96 ;
     RECT  81.497 38.688 83.185 38.712 ;
     RECT  82.181 44.976 83.221 54.696 ;
     RECT  83.081 55.68 83.221 57.048 ;
     RECT  83.221 0.144 83.365 0.168 ;
     RECT  82.853 1.152 83.365 11.256 ;
     RECT  83.041 12.336 83.365 18.024 ;
     RECT  83.365 0.144 83.408 11.256 ;
     RECT  83.365 12.336 83.408 18.216 ;
     RECT  83.077 19.248 83.408 25.32 ;
     RECT  83.125 26.304 83.408 35.496 ;
     RECT  82.073 36.48 83.408 37.128 ;
     RECT  83.185 38.688 83.408 39.336 ;
     RECT  81.821 41.088 83.408 41.592 ;
     RECT  83.185 43.344 83.408 43.368 ;
     RECT  83.221 44.976 83.408 57.048 ;
     RECT  83.408 0.144 83.603 57.048 ;
     RECT  83.603 0.144 83.704 56.568 ;
     RECT  83.704 24.72 83.729 34.248 ;
     RECT  83.704 35.472 83.981 37.032 ;
     RECT  83.704 39.312 83.981 43.368 ;
     RECT  83.704 55.872 83.987 56.568 ;
     RECT  83.704 12.336 84.017 12.84 ;
     RECT  83.704 45.264 84.083 45.288 ;
     RECT  83.704 18.192 84.125 18.888 ;
     RECT  83.981 42.672 84.125 43.368 ;
     RECT  83.704 47.04 84.125 54.696 ;
     RECT  83.704 0.144 84.133 7.128 ;
     RECT  83.729 25.008 84.161 34.248 ;
     RECT  84.125 47.424 84.161 54.696 ;
     RECT  83.704 14.16 84.341 15.864 ;
     RECT  84.161 25.008 84.377 30.696 ;
     RECT  84.161 31.728 84.385 34.248 ;
     RECT  84.133 0.096 84.412 7.128 ;
     RECT  84.341 15.84 84.413 15.864 ;
     RECT  83.704 20.592 84.557 23.304 ;
     RECT  83.981 36.288 84.557 37.032 ;
     RECT  84.037 58.176 84.613 58.2 ;
     RECT  84.377 29.664 84.659 30.696 ;
     RECT  84.412 0.096 84.665 5.064 ;
     RECT  84.557 20.592 84.697 22.776 ;
     RECT  84.125 18.72 84.769 18.888 ;
     RECT  84.697 20.544 84.769 22.776 ;
     RECT  83.981 39.312 84.773 41.64 ;
     RECT  83.704 16.896 84.805 17.112 ;
     RECT  84.557 37.008 84.812 37.032 ;
     RECT  83.704 38.112 84.812 38.136 ;
     RECT  84.341 14.16 84.845 14.76 ;
     RECT  84.412 6.384 84.877 7.128 ;
     RECT  84.812 37.008 84.881 38.136 ;
     RECT  84.881 37.008 84.899 37.464 ;
     RECT  83.987 55.872 84.917 56.376 ;
     RECT  84.665 0.096 84.947 3.432 ;
     RECT  84.917 55.968 84.947 56.376 ;
     RECT  84.805 16.176 84.953 17.112 ;
     RECT  84.659 29.664 84.953 30.072 ;
     RECT  84.773 39.6 84.953 41.64 ;
     RECT  84.377 25.008 84.985 27.912 ;
     RECT  84.845 14.208 84.989 14.76 ;
     RECT  84.947 56.352 84.989 56.376 ;
     RECT  84.877 6.384 85.021 7.176 ;
     RECT  83.704 8.16 85.021 11.256 ;
     RECT  84.769 18.72 85.043 22.776 ;
     RECT  84.985 24.816 85.061 27.912 ;
     RECT  84.385 31.728 85.061 32.424 ;
     RECT  84.997 56.4 85.093 57 ;
     RECT  84.613 58.08 85.093 58.2 ;
     RECT  84.989 14.4 85.169 14.76 ;
     RECT  85.043 18.72 85.277 18.744 ;
     RECT  84.161 47.424 85.309 54.648 ;
     RECT  85.309 47.424 85.313 54.696 ;
     RECT  85.061 31.728 85.345 32.04 ;
     RECT  85.021 6.384 85.349 11.256 ;
     RECT  84.947 0.096 85.357 1.704 ;
     RECT  85.061 24.816 85.427 27.336 ;
     RECT  85.427 24.816 85.465 27.144 ;
     RECT  84.953 29.664 85.493 29.784 ;
     RECT  84.953 39.6 85.516 40.296 ;
     RECT  85.349 6.384 85.529 7.176 ;
     RECT  85.169 14.64 85.597 14.76 ;
     RECT  84.385 33.6 85.633 34.248 ;
     RECT  84.899 37.008 85.705 37.032 ;
     RECT  85.705 36.336 85.741 37.032 ;
     RECT  84.665 5.04 85.777 5.064 ;
     RECT  85.093 56.4 85.781 58.2 ;
     RECT  85.043 19.728 85.813 22.776 ;
     RECT  85.349 8.16 85.885 11.256 ;
     RECT  85.357 0.624 85.957 1.704 ;
     RECT  84.947 2.736 85.957 3.432 ;
     RECT  85.313 47.424 85.957 47.592 ;
     RECT  85.313 48.576 85.957 54.696 ;
     RECT  84.125 42.672 85.961 42.744 ;
     RECT  85.529 6.384 85.997 7.128 ;
     RECT  85.813 19.728 86.037 22.92 ;
     RECT  85.777 5.04 86.053 5.16 ;
     RECT  86.037 19.728 86.053 23.112 ;
     RECT  85.345 31.536 86.053 32.04 ;
     RECT  85.633 33.6 86.053 34.584 ;
     RECT  85.465 24.816 86.069 26.856 ;
     RECT  86.053 33.024 86.069 34.584 ;
     RECT  85.957 48.576 86.069 55.032 ;
     RECT  86.053 18.816 86.099 23.112 ;
     RECT  85.781 56.4 86.101 58.152 ;
     RECT  86.099 18.816 86.105 22.008 ;
     RECT  86.053 4.512 86.141 5.16 ;
     RECT  84.953 41.616 86.141 41.64 ;
     RECT  85.957 0.624 86.195 3.432 ;
     RECT  86.105 18.816 86.195 21.48 ;
     RECT  86.053 30.816 86.195 32.04 ;
     RECT  86.069 33.024 86.195 33.768 ;
     RECT  86.101 55.824 86.195 58.152 ;
     RECT  86.195 19.584 86.213 21.48 ;
     RECT  85.885 8.16 86.245 11.304 ;
     RECT  85.957 47.28 86.249 47.592 ;
     RECT  86.141 5.136 86.281 5.16 ;
     RECT  85.997 6.384 86.281 6.84 ;
     RECT  84.017 12.528 86.285 12.84 ;
     RECT  85.597 14.64 86.285 14.856 ;
     RECT  85.741 36.24 86.285 37.032 ;
     RECT  86.249 47.568 86.293 47.592 ;
     RECT  86.069 48.576 86.293 54.072 ;
     RECT  86.285 14.736 86.321 14.856 ;
     RECT  86.281 5.136 86.339 6.84 ;
     RECT  86.213 19.584 86.357 19.752 ;
     RECT  86.069 24.816 86.357 26.808 ;
     RECT  86.195 1.68 86.387 3.432 ;
     RECT  86.339 5.712 86.387 6.84 ;
     RECT  86.245 8.16 86.387 11.496 ;
     RECT  86.387 1.68 86.393 2.376 ;
     RECT  86.195 0.624 86.461 0.696 ;
     RECT  86.387 8.16 86.465 11.4 ;
     RECT  84.953 16.176 86.497 16.2 ;
     RECT  86.285 12.528 86.501 12.552 ;
     RECT  86.293 47.568 86.531 54.072 ;
     RECT  86.461 0.528 86.533 0.696 ;
     RECT  85.961 42.672 86.533 42.696 ;
     RECT  86.195 31.2 86.605 32.04 ;
     RECT  86.531 48.576 86.609 54.072 ;
     RECT  86.357 24.816 86.717 26.424 ;
     RECT  86.609 49.776 86.789 54.072 ;
     RECT  85.516 39.6 86.821 39.672 ;
     RECT  86.717 24.816 86.825 26.328 ;
     RECT  86.357 19.728 86.897 19.752 ;
     RECT  86.099 23.088 86.933 23.112 ;
     RECT  86.825 24.816 86.933 25.704 ;
     RECT  86.789 49.776 86.933 52.056 ;
     RECT  86.387 3.408 86.969 3.432 ;
     RECT  86.605 31.2 86.969 33 ;
     RECT  86.465 9.072 87.005 11.4 ;
     RECT  86.065 38.16 87.005 38.184 ;
     RECT  86.213 20.832 87.077 21.48 ;
     RECT  85.493 29.76 87.113 29.784 ;
     RECT  86.969 31.2 87.113 31.896 ;
     RECT  86.531 47.568 87.113 47.592 ;
     RECT  86.789 53.04 87.113 54.072 ;
     RECT  87.113 31.536 87.149 31.896 ;
     RECT  86.933 49.776 87.149 51.192 ;
     RECT  86.393 1.68 87.155 2.28 ;
     RECT  86.195 55.824 87.205 57.624 ;
     RECT  86.821 39.6 87.221 40.584 ;
     RECT  86.533 41.76 87.257 42.696 ;
     RECT  87.149 49.776 87.257 50.808 ;
     RECT  86.609 48.576 87.329 48.792 ;
     RECT  86.933 24.816 87.365 24.84 ;
     RECT  87.005 9.072 87.395 10.248 ;
     RECT  86.387 6.576 87.397 6.84 ;
     RECT  86.497 15.408 87.401 16.2 ;
     RECT  87.077 20.832 87.401 20.952 ;
     RECT  87.395 9.072 87.437 9.096 ;
     RECT  87.401 15.408 87.437 15.432 ;
     RECT  86.533 0.096 87.469 0.696 ;
     RECT  87.155 1.68 87.469 1.752 ;
     RECT  86.461 27.84 87.473 27.864 ;
     RECT  87.149 31.536 87.473 31.56 ;
     RECT  87.221 39.648 87.473 40.584 ;
     RECT  87.257 41.76 87.473 41.784 ;
     RECT  87.397 6.576 87.481 7.464 ;
     RECT  87.005 11.376 87.509 11.4 ;
     RECT  86.101 17.616 87.509 17.64 ;
     RECT  86.969 32.976 87.509 33 ;
     RECT  86.285 37.008 87.509 37.032 ;
     RECT  87.473 39.648 87.509 39.672 ;
     RECT  87.395 10.224 87.532 10.248 ;
     RECT  87.452 20.256 87.539 20.28 ;
     RECT  87.469 18.768 87.553 18.792 ;
     RECT  87.329 48.576 87.617 48.6 ;
     RECT  87.317 54.336 87.649 54.696 ;
     RECT  87.205 55.824 87.649 58.152 ;
     RECT  87.541 14.784 87.689 14.808 ;
     RECT  87.649 54.336 87.757 58.152 ;
     RECT  87.113 53.04 87.833 53.064 ;
     RECT  87.481 6.576 87.869 6.6 ;
     RECT  87.257 50.064 87.905 50.808 ;
     RECT  87.469 0.096 88.019 1.752 ;
     RECT  88.019 1.68 88.115 1.752 ;
     RECT  88.117 22.8 88.229 22.824 ;
     RECT  87.905 50.064 88.259 50.136 ;
     RECT  87.757 54.336 88.273 58.2 ;
     RECT  88.259 50.112 88.301 50.136 ;
     RECT  87.685 5.136 88.405 5.16 ;
     RECT  88.273 54.336 88.405 54.696 ;
     RECT  88.405 54.096 88.499 54.696 ;
     RECT  88.405 4.56 88.595 5.16 ;
     RECT  88.273 55.872 88.595 58.2 ;
     RECT  88.405 2.88 88.705 2.904 ;
     RECT  88.595 55.92 88.787 58.2 ;
     RECT  88.787 55.968 88.883 58.2 ;
     RECT  88.115 1.68 88.979 1.704 ;
     RECT  88.499 54.528 89.075 54.696 ;
     RECT  88.019 0.096 89.125 0.6 ;
     RECT  88.883 55.968 89.171 56.952 ;
     RECT  89.125 0.096 89.209 1.176 ;
     RECT  88.595 5.136 89.267 5.16 ;
     RECT  89.171 55.968 89.267 56.472 ;
     RECT  89.075 54.528 89.459 54.648 ;
     RECT  89.267 55.968 89.555 56.424 ;
     RECT  89.555 56.4 89.651 56.424 ;
     RECT  89.209 0.096 89.669 0.6 ;
     RECT  89.459 54.528 89.747 54.6 ;
     RECT  89.669 0.576 89.785 0.6 ;
     RECT  88.883 58.176 89.849 58.2 ;
     RECT  89.747 54.528 89.939 54.552 ;
    LAYER M5 ;
     RECT  48.336 0.016 49.704 0.037 ;
     RECT  51.408 0.016 57.48 0.133 ;
     RECT  48.336 0.037 49.8 0.179 ;
     RECT  51.312 0.133 57.48 0.275 ;
     RECT  42.192 0.016 45.192 0.611 ;
     RECT  73.68 0.016 89.736 0.611 ;
     RECT  42.192 0.611 45.096 1.139 ;
     RECT  51.456 0.275 57.48 1.139 ;
     RECT  22.992 0.016 35.208 1.187 ;
     RECT  42.192 1.139 45 1.187 ;
     RECT  48.336 0.179 49.608 1.187 ;
     RECT  48.432 1.187 49.608 1.715 ;
     RECT  73.68 0.611 89.256 1.715 ;
     RECT  22.992 1.187 30.024 1.763 ;
     RECT  31.248 1.187 35.208 1.763 ;
     RECT  61.392 0.016 70.536 1.763 ;
     RECT  85.968 1.715 89.256 1.763 ;
     RECT  3.792 0.016 16.008 1.811 ;
     RECT  42.288 1.187 45 1.811 ;
     RECT  48.432 1.715 49.32 1.811 ;
     RECT  51.456 1.139 57.192 1.811 ;
     RECT  61.488 1.763 69.384 1.811 ;
     RECT  73.68 1.715 84.936 1.811 ;
     RECT  48.432 1.811 48.552 1.859 ;
     RECT  61.488 1.811 67.704 1.859 ;
     RECT  5.232 1.811 15.912 1.907 ;
     RECT  24 1.763 25.896 1.907 ;
     RECT  61.68 1.859 63.816 1.907 ;
     RECT  15.12 1.907 15.912 1.955 ;
     RECT  53.04 1.811 57.192 1.955 ;
     RECT  61.776 1.907 63.624 1.955 ;
     RECT  61.776 1.955 62.112 2.051 ;
     RECT  74.064 1.811 84.936 2.051 ;
     RECT  51.456 1.811 51.48 2.137 ;
     RECT  2.4 2.137 2.52 2.151 ;
     RECT  18.6 2.137 18.72 2.151 ;
     RECT  40.2 2.137 40.32 2.151 ;
     RECT  45.6 2.137 45.72 2.151 ;
     RECT  5.232 1.907 13.608 2.243 ;
     RECT  74.064 2.051 84.312 2.243 ;
     RECT  5.424 2.243 13.608 2.291 ;
     RECT  25.296 1.907 25.896 2.291 ;
     RECT  34.128 1.763 35.112 2.291 ;
     RECT  42.288 1.811 44.136 2.291 ;
     RECT  53.04 1.955 55.176 2.291 ;
     RECT  63.6 1.955 63.624 2.291 ;
     RECT  64.848 1.859 67.704 2.291 ;
     RECT  74.064 2.243 76.296 2.291 ;
     RECT  85.968 1.763 87.144 2.291 ;
     RECT  42.864 2.291 44.136 2.339 ;
     RECT  69.264 1.811 69.384 2.339 ;
     RECT  77.616 2.243 84.312 2.339 ;
     RECT  15.312 1.955 15.816 2.387 ;
     RECT  74.064 2.291 76.2 2.387 ;
     RECT  77.616 2.339 80.04 2.387 ;
     RECT  26.928 1.763 27.24 2.483 ;
     RECT  7.056 2.291 13.512 2.579 ;
     RECT  26.928 2.483 26.952 2.773 ;
     RECT  29.4 1.763 29.88 2.821 ;
     RECT  85.968 2.291 86.952 2.821 ;
     RECT  24 1.907 24.312 2.869 ;
     RECT  15.792 2.387 15.816 2.915 ;
     RECT  66.576 2.291 67.608 2.915 ;
     RECT  74.16 2.387 76.2 2.915 ;
     RECT  77.856 2.387 80.04 2.915 ;
     RECT  82.224 2.339 84.312 2.915 ;
     RECT  88.464 1.763 89.256 2.915 ;
     RECT  12.048 2.579 13.512 2.963 ;
     RECT  42.864 2.339 44.04 2.963 ;
     RECT  64.944 2.291 65.592 2.963 ;
     RECT  77.856 2.915 79.56 2.963 ;
     RECT  82.32 2.915 84.312 2.963 ;
     RECT  66.576 2.915 67.512 3.059 ;
     RECT  54.576 2.291 54.6 3.155 ;
     RECT  51 2.137 51.48 3.205 ;
     RECT  78 2.963 79.56 3.299 ;
     RECT  3.792 1.811 3.816 3.301 ;
     RECT  75.024 2.915 75.864 3.347 ;
     RECT  85.584 2.821 86.952 3.349 ;
     RECT  42.864 2.963 43.464 3.397 ;
     RECT  3.792 3.301 4.296 3.443 ;
     RECT  47.952 2.677 47.976 3.443 ;
     RECT  56.4 1.955 57.192 3.443 ;
     RECT  85.344 3.349 86.952 3.443 ;
     RECT  42.768 3.397 43.464 3.491 ;
     RECT  29.4 2.821 30.168 3.685 ;
     RECT  31.2 3.397 31.224 3.685 ;
     RECT  24 2.869 24.408 3.829 ;
     RECT  26.064 2.773 26.952 3.829 ;
     RECT  51 3.205 52.056 3.877 ;
     RECT  40.2 2.151 40.512 3.925 ;
     RECT  69.264 2.339 69.288 3.971 ;
     RECT  29.4 3.685 31.224 4.019 ;
     RECT  42.768 3.491 42.792 4.019 ;
     RECT  75.408 3.347 75.864 4.019 ;
     RECT  21.216 3.973 21.24 4.261 ;
     RECT  82.992 2.963 84.312 4.261 ;
     RECT  65.568 2.963 65.592 4.355 ;
     RECT  75.84 4.019 75.864 4.405 ;
     RECT  40.08 3.925 40.512 4.501 ;
     RECT  45.6 2.151 45.912 4.501 ;
     RECT  72.6 2.137 72.912 4.549 ;
     RECT  24 3.829 26.952 4.595 ;
     RECT  88.56 2.915 89.256 4.595 ;
     RECT  32.976 3.877 33 4.691 ;
     RECT  20.736 4.261 21.24 4.931 ;
     RECT  34.8 2.291 35.112 5.077 ;
     RECT  61.8 2.051 62.112 5.077 ;
     RECT  72.096 4.549 72.912 5.171 ;
     RECT  89.232 4.595 89.256 5.171 ;
     RECT  26.064 4.595 26.952 5.363 ;
     RECT  45.6 4.501 46.728 5.363 ;
     RECT  53.52 3.397 53.544 5.605 ;
     RECT  54.672 5.029 54.696 5.605 ;
     RECT  82.704 4.261 84.312 5.605 ;
     RECT  81.168 2.339 81.192 5.653 ;
     RECT  14.832 4.645 14.856 5.701 ;
     RECT  34.8 5.077 35.352 5.747 ;
     RECT  53.52 5.605 54.696 5.747 ;
     RECT  75.84 4.405 76.008 5.747 ;
     RECT  7.056 2.579 10.584 5.893 ;
     RECT  34.8 5.747 35.304 5.987 ;
     RECT  6.336 5.893 10.584 6.181 ;
     RECT  6 6.181 10.584 6.229 ;
     RECT  18.6 2.151 18.912 6.229 ;
     RECT  29.4 4.019 30.168 6.229 ;
     RECT  20.736 4.931 20.76 6.323 ;
     RECT  39.936 4.501 40.512 6.517 ;
     RECT  78 3.299 78.888 6.517 ;
     RECT  24 4.595 24.312 6.613 ;
     RECT  85.344 3.443 86.376 6.757 ;
     RECT  26.064 5.363 26.088 6.805 ;
     RECT  28.608 6.229 30.168 6.805 ;
     RECT  34.8 5.987 35.208 6.805 ;
     RECT  85.344 6.757 86.52 6.805 ;
     RECT  56.4 3.443 56.952 6.853 ;
     RECT  67.2 3.059 67.512 6.901 ;
     RECT  74.688 5.653 74.712 7.091 ;
     RECT  48.72 4.501 48.744 7.187 ;
     RECT  53.52 5.747 54.168 7.235 ;
     RECT  67.2 6.901 67.704 7.237 ;
     RECT  68.88 6.949 68.904 7.237 ;
     RECT  78 6.517 78.936 7.333 ;
     RECT  14.688 5.701 14.856 7.379 ;
     RECT  53.52 7.235 53.544 7.379 ;
     RECT  59.76 6.805 59.784 7.379 ;
     RECT  77.472 7.333 78.936 7.379 ;
     RECT  18.048 6.229 18.912 7.475 ;
     RECT  55.344 6.373 55.368 7.475 ;
     RECT  85.344 6.805 87.432 7.475 ;
     RECT  82.704 5.605 84.36 7.621 ;
     RECT  85.344 7.475 86.52 7.621 ;
     RECT  56.4 6.853 57.048 7.859 ;
     RECT  70.656 4.885 70.68 7.861 ;
     RECT  82.704 7.621 86.52 7.907 ;
     RECT  58.08 7.381 58.104 7.909 ;
     RECT  34.224 6.805 35.208 8.003 ;
     RECT  38.16 7.381 38.184 8.003 ;
     RECT  63.792 7.189 63.816 8.003 ;
     RECT  61.68 5.077 62.112 8.053 ;
     RECT  61.68 8.053 62.232 8.195 ;
     RECT  81.168 5.653 81.432 8.197 ;
     RECT  39.936 6.517 41.112 8.341 ;
     RECT  34.8 8.003 35.208 8.485 ;
     RECT  43.632 8.293 43.656 8.485 ;
     RECT  69.936 7.861 70.68 8.627 ;
     RECT  12.864 2.963 13.512 8.723 ;
     RECT  77.472 7.379 78.888 8.723 ;
     RECT  26.064 6.805 26.328 8.773 ;
     RECT  50.832 3.877 52.056 8.821 ;
     RECT  18.6 7.475 18.912 8.917 ;
     RECT  50.832 8.821 52.296 9.061 ;
     RECT  61.8 8.195 62.232 9.061 ;
     RECT  72.6 5.171 72.912 9.061 ;
     RECT  85.344 7.907 86.52 9.061 ;
     RECT  18.6 8.917 19.224 9.107 ;
     RECT  23.328 6.613 24.312 9.109 ;
     RECT  26.064 8.773 26.472 9.109 ;
     RECT  80.976 8.197 81.432 9.109 ;
     RECT  72.384 9.061 72.912 9.203 ;
     RECT  34.8 8.485 35.592 9.251 ;
     RECT  22.944 9.109 26.472 9.445 ;
     RECT  28.224 6.805 30.168 9.445 ;
     RECT  61.8 9.061 62.424 9.589 ;
     RECT  45.6 5.363 45.912 9.637 ;
     RECT  36.96 9.205 36.984 9.731 ;
     RECT  60.816 9.589 62.424 9.731 ;
     RECT  70.32 8.627 70.68 9.731 ;
     RECT  74.016 8.965 74.04 9.779 ;
     RECT  13.2 8.723 13.512 9.781 ;
     RECT  67.2 7.237 68.904 9.925 ;
     RECT  22.944 9.445 30.168 10.067 ;
     RECT  75.84 5.747 75.96 10.069 ;
     RECT  82.704 7.907 84.312 10.117 ;
     RECT  85.344 9.061 87.384 10.117 ;
     RECT  80.928 9.109 81.432 10.163 ;
     RECT  18.6 9.107 19.032 10.213 ;
     RECT  82.704 10.117 87.384 10.213 ;
     RECT  4.272 3.443 4.296 10.307 ;
     RECT  23.328 10.067 30.168 10.307 ;
     RECT  45.6 9.637 46.776 10.307 ;
     RECT  70.656 9.731 70.68 10.307 ;
     RECT  31.2 4.019 31.224 10.309 ;
     RECT  26.064 10.307 30.168 10.355 ;
     RECT  50.16 9.061 52.296 10.357 ;
     RECT  21.072 10.309 21.096 10.451 ;
     RECT  5.472 6.229 10.584 10.501 ;
     RECT  34.8 9.251 35.208 10.501 ;
     RECT  58.08 7.909 58.152 10.547 ;
     RECT  60.816 9.731 62.376 10.597 ;
     RECT  75.84 10.069 76.488 10.597 ;
     RECT  56.4 7.859 56.952 10.645 ;
     RECT  60.48 10.597 62.376 10.787 ;
     RECT  39.936 8.341 41.256 10.789 ;
     RECT  55.2 9.637 55.224 10.883 ;
     RECT  56.304 10.645 56.952 10.883 ;
     RECT  60.816 10.787 62.376 10.931 ;
     RECT  13.104 9.781 13.512 11.029 ;
     RECT  14.832 7.379 14.856 11.029 ;
     RECT  26.064 10.355 27.384 11.123 ;
     RECT  82.704 10.213 87.48 11.171 ;
     RECT  72.48 9.203 72.912 11.173 ;
     RECT  5.472 10.501 11.448 11.267 ;
     RECT  47.664 10.597 47.688 11.267 ;
     RECT  2.4 2.151 2.712 11.365 ;
     RECT  56.4 10.883 56.952 11.365 ;
     RECT  58.08 10.547 58.104 11.365 ;
     RECT  18.6 10.213 19.368 11.411 ;
     RECT  20.496 10.597 20.52 11.411 ;
     RECT  85.344 11.171 87.48 11.411 ;
     RECT  5.472 11.267 10.584 11.459 ;
     RECT  61.8 10.931 62.376 11.507 ;
     RECT  67.2 9.925 69.48 11.507 ;
     RECT  70.896 10.789 70.92 11.507 ;
     RECT  72.048 11.173 72.912 11.555 ;
     RECT  7.296 11.459 8.112 11.603 ;
     RECT  75.84 10.597 76.968 11.699 ;
     RECT  9.36 11.459 10.584 11.795 ;
     RECT  13.104 11.029 14.856 11.797 ;
     RECT  50.16 10.357 52.44 11.891 ;
     RECT  23.328 10.307 24.312 11.893 ;
     RECT  31.2 10.309 31.704 11.941 ;
     RECT  56.4 11.365 58.104 11.941 ;
     RECT  6 11.459 6.024 12.035 ;
     RECT  23.328 11.893 24.744 12.083 ;
     RECT  56.4 11.941 58.68 12.179 ;
     RECT  78 8.723 78.888 12.277 ;
     RECT  81.168 10.163 81.432 12.325 ;
     RECT  82.704 11.171 84.312 12.325 ;
     RECT  12.528 11.797 14.856 12.517 ;
     RECT  26.064 11.123 26.472 12.517 ;
     RECT  75.84 11.699 76.488 12.517 ;
     RECT  2.4 11.365 3.432 12.563 ;
     RECT  75.792 12.517 76.488 12.563 ;
     RECT  77.904 12.277 78.888 12.563 ;
     RECT  48.768 7.333 48.792 12.611 ;
     RECT  56.4 12.179 58.344 12.659 ;
     RECT  18.6 11.411 18.912 12.709 ;
     RECT  36.432 11.221 36.456 12.755 ;
     RECT  12.528 12.517 14.904 12.757 ;
     RECT  17.616 12.709 18.912 12.757 ;
     RECT  20.976 12.757 21.672 12.899 ;
     RECT  9.36 11.795 9.384 12.901 ;
     RECT  39.888 10.789 41.256 12.901 ;
     RECT  17.616 12.757 19.656 12.947 ;
     RECT  71.088 12.901 71.112 12.949 ;
     RECT  31.2 11.941 32.472 13.043 ;
     RECT  64.032 12.853 64.056 13.043 ;
     RECT  7.536 11.603 8.112 13.045 ;
     RECT  11.904 12.757 14.904 13.045 ;
     RECT  50.832 11.891 52.44 13.045 ;
     RECT  53.76 8.245 53.784 13.045 ;
     RECT  70.848 12.949 71.112 13.091 ;
     RECT  18.6 12.947 19.656 13.093 ;
     RECT  20.976 12.899 21 13.093 ;
     RECT  26.064 12.517 26.616 13.187 ;
     RECT  9.36 12.901 9.432 13.235 ;
     RECT  18.6 13.093 21 13.235 ;
     RECT  67.2 11.507 68.904 13.235 ;
     RECT  6.24 13.045 8.112 13.283 ;
     RECT  34.56 10.501 35.208 13.283 ;
     RECT  50.832 13.045 53.784 13.381 ;
     RECT  70.848 13.091 70.872 13.523 ;
     RECT  47.328 12.181 47.352 13.571 ;
     RECT  79.968 13.093 79.992 13.619 ;
     RECT  45.6 10.307 45.912 13.621 ;
     RECT  64.992 13.333 65.112 13.667 ;
     RECT  75.792 12.563 76.296 13.669 ;
     RECT  39.408 12.901 41.256 13.715 ;
     RECT  11.904 13.045 15.72 13.763 ;
     RECT  56.4 12.659 57.864 13.763 ;
     RECT  72.48 11.555 72.912 13.765 ;
     RECT  75.792 13.669 76.392 13.811 ;
     RECT  10.56 11.795 10.584 13.813 ;
     RECT  12.528 13.763 15.72 13.859 ;
     RECT  5.088 13.429 5.112 13.907 ;
     RECT  72.48 13.765 73.032 13.907 ;
     RECT  31.2 13.043 31.944 14.243 ;
     RECT  73.92 14.197 73.944 14.245 ;
     RECT  13.2 13.859 15.72 14.291 ;
     RECT  18.6 13.235 20.04 14.339 ;
     RECT  57.744 13.763 57.864 14.341 ;
     RECT  13.2 14.291 14.568 14.387 ;
     RECT  44.928 13.621 45.912 14.387 ;
     RECT  64.992 13.667 65.016 14.435 ;
     RECT  70.704 14.245 70.728 14.435 ;
     RECT  73.92 14.245 74.136 14.435 ;
     RECT  57.744 14.341 58.824 14.483 ;
     RECT  73.92 14.435 74.04 14.531 ;
     RECT  23.328 12.083 24.312 14.533 ;
     RECT  26.064 13.187 26.472 14.533 ;
     RECT  61.8 11.507 62.112 14.581 ;
     RECT  78 12.563 78.888 14.581 ;
     RECT  50.784 13.381 53.784 14.627 ;
     RECT  70.656 14.485 70.68 14.627 ;
     RECT  75.792 13.811 76.056 14.627 ;
     RECT  6.816 13.283 8.112 14.629 ;
     RECT  57.744 14.483 58.728 14.723 ;
     RECT  61.8 14.581 62.424 14.771 ;
     RECT  9.36 13.235 9.384 14.867 ;
     RECT  23.328 14.533 26.472 14.867 ;
     RECT  75.84 14.627 76.056 14.867 ;
     RECT  50.784 14.627 52.056 14.965 ;
     RECT  73.92 14.531 73.944 15.011 ;
     RECT  4.656 14.917 4.68 15.059 ;
     RECT  70.56 14.869 70.584 15.059 ;
     RECT  67.2 13.235 68.808 15.157 ;
     RECT  10.56 13.813 10.872 15.203 ;
     RECT  32.496 14.965 32.52 15.203 ;
     RECT  72.48 13.907 72.912 15.253 ;
     RECT  67.104 15.157 68.808 15.301 ;
     RECT  49.056 15.157 49.08 15.347 ;
     RECT  6.192 14.629 8.112 15.395 ;
     RECT  6.192 15.395 6.216 15.443 ;
     RECT  15.696 14.291 15.72 15.443 ;
     RECT  37.392 14.245 37.416 15.443 ;
     RECT  60.72 12.469 60.744 15.443 ;
     RECT  81.168 12.325 84.312 15.539 ;
     RECT  21.12 15.445 21.144 15.589 ;
     RECT  21.12 15.589 21.24 15.779 ;
     RECT  53.76 14.627 53.784 15.781 ;
     RECT  53.76 15.781 54.216 15.827 ;
     RECT  31.2 14.243 31.224 15.877 ;
     RECT  54.192 15.827 54.216 15.877 ;
     RECT  61.8 14.771 62.112 15.877 ;
     RECT  75.936 14.867 76.056 15.877 ;
     RECT  67.104 15.301 68.904 16.021 ;
     RECT  72.48 15.253 73.848 16.069 ;
     RECT  54.192 15.877 54.792 16.115 ;
     RECT  72.432 16.069 73.848 16.115 ;
     RECT  72.432 16.115 72.912 16.259 ;
     RECT  61.8 15.877 62.568 16.261 ;
     RECT  13.2 14.387 13.8 16.405 ;
     RECT  57.744 14.723 57.864 16.501 ;
     RECT  64.464 15.877 64.488 16.549 ;
     RECT  70.368 16.453 70.68 16.549 ;
     RECT  70.368 16.549 71.448 16.595 ;
     RECT  77.52 14.581 78.888 16.595 ;
     RECT  23.328 14.867 24.312 16.597 ;
     RECT  26.064 14.867 26.472 16.597 ;
     RECT  61.8 16.261 62.712 16.597 ;
     RECT  20.592 16.261 20.616 16.741 ;
     RECT  10.56 15.203 10.584 16.837 ;
     RECT  64.464 16.549 64.68 16.837 ;
     RECT  66.336 16.021 68.904 16.883 ;
     RECT  82.704 15.539 84.312 16.885 ;
     RECT  85.344 11.411 86.52 16.885 ;
     RECT  64.176 16.837 64.68 16.933 ;
     RECT  67.2 16.883 68.904 16.933 ;
     RECT  10.56 16.837 11.592 17.075 ;
     RECT  16.224 15.925 16.584 17.077 ;
     RECT  23.328 16.597 26.472 17.077 ;
     RECT  27.456 14.197 27.48 17.077 ;
     RECT  31.2 15.877 32.136 17.077 ;
     RECT  43.584 8.485 43.656 17.077 ;
     RECT  81.168 15.539 81.432 17.077 ;
     RECT  20.592 16.741 21 17.123 ;
     RECT  23.328 17.077 27.48 17.123 ;
     RECT  60.912 16.597 62.712 17.123 ;
     RECT  64.176 16.933 65.016 17.123 ;
     RECT  67.2 16.933 68.952 17.123 ;
     RECT  82.704 16.885 86.52 17.123 ;
     RECT  5.232 16.021 5.4 17.219 ;
     RECT  80.928 17.077 81.432 17.219 ;
     RECT  26.064 17.123 27.48 17.267 ;
     RECT  70.368 16.595 70.392 17.267 ;
     RECT  34.56 13.283 35.112 17.317 ;
     RECT  15.984 17.077 16.584 17.507 ;
     RECT  31.2 17.077 32.952 17.603 ;
     RECT  81.168 17.219 81.432 17.605 ;
     RECT  82.704 17.123 84.312 17.605 ;
     RECT  75.936 15.877 76.104 17.699 ;
     RECT  43.584 17.077 43.896 17.795 ;
     RECT  43.584 17.795 43.656 17.797 ;
     RECT  34.56 17.317 35.208 18.037 ;
     RECT  54.192 16.115 54.216 18.037 ;
     RECT  13.2 16.405 14.76 18.131 ;
     RECT  75.936 17.699 76.056 18.133 ;
     RECT  31.2 17.603 32.088 18.179 ;
     RECT  54.192 18.037 54.408 18.179 ;
     RECT  71.424 16.595 71.448 18.179 ;
     RECT  77.616 16.595 78.888 18.181 ;
     RECT  57.744 16.501 58.056 18.229 ;
     RECT  34.56 18.037 35.352 18.275 ;
     RECT  57.744 18.229 58.152 18.275 ;
     RECT  81.168 17.605 84.312 18.419 ;
     RECT  13.2 18.131 13.8 18.421 ;
     RECT  38.544 16.645 38.568 18.467 ;
     RECT  75.264 18.133 76.056 18.467 ;
     RECT  65.424 18.421 65.448 18.563 ;
     RECT  60.912 17.123 62.112 18.661 ;
     RECT  67.2 17.123 68.904 18.661 ;
     RECT  77.616 18.181 79.848 18.661 ;
     RECT  82.704 18.419 84.312 18.709 ;
     RECT  85.344 17.123 86.52 18.709 ;
     RECT  49.536 17.029 49.56 18.755 ;
     RECT  37.104 18.037 37.128 18.851 ;
     RECT  60.816 18.661 62.112 18.851 ;
     RECT  58.032 18.275 58.152 18.899 ;
     RECT  71.04 18.805 71.064 18.947 ;
     RECT  54.384 18.179 54.408 18.949 ;
     RECT  9.12 18.901 9.144 19.043 ;
     RECT  5.376 17.219 5.4 19.093 ;
     RECT  10.56 17.075 11.448 19.139 ;
     RECT  54.384 18.949 55.08 19.189 ;
     RECT  54.384 19.189 55.128 19.235 ;
     RECT  77.472 18.661 79.848 19.235 ;
     RECT  23.328 17.123 24.456 19.237 ;
     RECT  34.56 18.275 35.208 19.237 ;
     RECT  64.176 17.123 64.2 19.333 ;
     RECT  64.176 19.333 64.296 19.379 ;
     RECT  77.472 19.235 78.888 19.381 ;
     RECT  13.104 18.421 13.8 19.427 ;
     RECT  20.592 18.757 20.616 19.427 ;
     RECT  33.504 18.133 33.528 19.427 ;
     RECT  42.672 17.797 43.656 19.427 ;
     RECT  58.128 18.899 58.152 19.427 ;
     RECT  72.48 16.259 72.912 19.427 ;
     RECT  39.888 13.715 41.256 19.525 ;
     RECT  18.6 14.339 19.464 19.621 ;
     RECT  26.064 17.267 26.472 19.621 ;
     RECT  13.104 19.427 13.656 19.667 ;
     RECT  48.432 18.517 48.456 19.763 ;
     RECT  5.184 19.093 5.4 19.811 ;
     RECT  16.56 17.507 16.584 19.811 ;
     RECT  64.272 19.379 64.296 19.907 ;
     RECT  5.376 19.811 5.4 20.003 ;
     RECT  34.56 19.237 35.352 20.003 ;
     RECT  60.912 18.851 62.112 20.003 ;
     RECT  77.328 19.381 78.888 20.003 ;
     RECT  87.504 18.757 87.528 20.291 ;
     RECT  50.736 14.965 52.056 20.435 ;
     RECT  34.56 20.003 35.208 20.579 ;
     RECT  39.888 19.525 41.64 20.579 ;
     RECT  61.584 20.003 62.112 20.627 ;
     RECT  67.008 18.661 68.904 20.675 ;
     RECT  61.632 20.627 62.112 20.723 ;
     RECT  13.2 19.667 13.656 21.061 ;
     RECT  17.088 21.013 17.112 21.109 ;
     RECT  17.088 21.109 17.208 21.155 ;
     RECT  55.056 19.235 55.128 21.155 ;
     RECT  60.384 20.341 60.408 21.155 ;
     RECT  81.168 18.419 81.432 21.155 ;
     RECT  22.752 19.237 24.456 21.157 ;
     RECT  25.632 19.621 26.472 21.157 ;
     RECT  22.752 21.157 26.472 21.203 ;
     RECT  81.408 21.155 81.432 21.541 ;
     RECT  82.704 18.709 86.52 21.541 ;
     RECT  23.328 21.203 26.472 21.587 ;
     RECT  17.184 21.155 17.208 21.683 ;
     RECT  18.6 19.621 19.608 21.683 ;
     RECT  7.8 15.395 8.112 21.685 ;
     RECT  67.008 20.675 67.8 21.731 ;
     RECT  63.504 21.253 63.528 22.019 ;
     RECT  28.608 10.355 30.168 22.165 ;
     RECT  75.264 18.467 75.96 22.213 ;
     RECT  7.8 21.685 9 22.499 ;
     RECT  71.376 20.485 71.4 22.501 ;
     RECT  25.632 21.587 26.472 22.597 ;
     RECT  53.568 21.541 53.592 22.643 ;
     RECT  21.12 22.165 21.144 22.741 ;
     RECT  56.4 13.763 56.712 22.741 ;
     RECT  38.784 22.453 38.808 22.787 ;
     RECT  20.256 22.741 21.144 22.835 ;
     RECT  27.744 22.165 30.168 22.835 ;
     RECT  61.68 20.723 62.112 22.835 ;
     RECT  78 20.003 78.888 22.885 ;
     RECT  25.584 22.597 26.472 23.171 ;
     RECT  77.088 22.885 78.888 23.171 ;
     RECT  18.6 21.683 18.912 23.173 ;
     RECT  20.256 22.835 20.28 23.173 ;
     RECT  75.072 22.213 75.96 23.267 ;
     RECT  7.8 22.499 8.112 23.317 ;
     RECT  18.6 23.173 20.28 23.363 ;
     RECT  70.56 22.501 71.4 23.795 ;
     RECT  4.128 23.317 4.152 23.891 ;
     RECT  72.6 19.427 72.912 23.941 ;
     RECT  70.56 23.795 70.584 24.131 ;
     RECT  45.6 14.387 45.912 24.133 ;
     RECT  39.888 20.579 41.256 24.181 ;
     RECT  63.312 23.317 63.336 24.323 ;
     RECT  81.408 21.541 86.52 24.371 ;
     RECT  23.328 21.587 24.456 24.373 ;
     RECT  50.832 20.435 52.056 24.373 ;
     RECT  77.424 23.171 78.888 24.373 ;
     RECT  48.192 23.893 48.216 24.419 ;
     RECT  38.736 23.653 38.76 24.467 ;
     RECT  44.976 24.133 45.912 24.469 ;
     RECT  77.424 24.373 79.32 24.469 ;
     RECT  56.304 22.741 56.712 24.515 ;
     RECT  60.384 22.741 60.408 24.515 ;
     RECT  7.152 23.317 8.112 24.563 ;
     RECT  21.648 23.893 21.672 24.563 ;
     RECT  75.264 23.267 75.96 24.611 ;
     RECT  81.408 24.371 81.432 24.613 ;
     RECT  67.008 21.731 67.512 24.661 ;
     RECT  68.88 20.675 68.904 24.661 ;
     RECT  26.064 23.171 26.472 24.755 ;
     RECT  80.592 24.613 81.432 24.755 ;
     RECT  61.8 22.835 62.112 24.901 ;
     RECT  67.008 24.661 68.904 24.947 ;
     RECT  5.328 23.701 5.352 25.045 ;
     RECT  68.88 24.947 68.904 25.093 ;
     RECT  75.648 24.611 75.96 25.093 ;
     RECT  76.992 24.469 79.32 25.093 ;
     RECT  65.328 22.741 65.352 25.139 ;
     RECT  49.92 24.373 52.056 25.187 ;
     RECT  74.304 25.045 74.328 25.187 ;
     RECT  68.88 25.093 69.096 25.235 ;
     RECT  72.6 23.941 73.032 25.429 ;
     RECT  75.648 25.093 79.32 25.523 ;
     RECT  72.6 25.429 73.128 25.571 ;
     RECT  75.648 25.523 79.176 25.667 ;
     RECT  80.64 24.755 81.432 25.715 ;
     RECT  76.848 25.667 79.176 25.859 ;
     RECT  72.6 25.571 73.08 25.907 ;
     RECT  75.648 25.667 75.864 25.909 ;
     RECT  76.848 25.859 78.984 26.099 ;
     RECT  61.8 24.901 63.048 26.147 ;
     RECT  58.128 24.469 58.152 26.195 ;
     RECT  26.112 24.755 26.472 26.243 ;
     RECT  50.832 25.187 52.056 26.243 ;
     RECT  43.584 19.427 43.656 26.291 ;
     RECT  23.328 24.373 24.552 26.387 ;
     RECT  61.8 26.147 62.112 26.437 ;
     RECT  82.704 24.371 86.52 26.629 ;
     RECT  5.088 25.045 5.352 26.771 ;
     RECT  61.488 26.437 62.112 26.771 ;
     RECT  10.56 19.139 10.584 26.821 ;
     RECT  43.584 26.291 43.608 26.867 ;
     RECT  76.944 26.099 78.984 26.915 ;
     RECT  72.6 25.907 73.032 27.011 ;
     RECT  67.008 24.947 67.608 27.013 ;
     RECT  68.88 25.235 68.904 27.013 ;
     RECT  10.56 26.821 11.4 27.395 ;
     RECT  18.6 23.363 19.752 27.395 ;
     RECT  34.8 20.579 35.208 27.395 ;
     RECT  75.168 25.909 75.864 27.443 ;
     RECT  72.6 27.011 72.912 27.493 ;
     RECT  82.56 26.629 86.52 27.875 ;
     RECT  58.176 26.293 58.2 27.877 ;
     RECT  81.36 25.715 81.432 27.877 ;
     RECT  57.936 27.877 58.2 27.923 ;
     RECT  82.56 27.875 84.312 27.923 ;
     RECT  67.008 27.013 68.904 27.925 ;
     RECT  44.688 24.469 45.912 27.971 ;
     RECT  66.624 27.925 68.904 28.115 ;
     RECT  71.856 27.493 72.912 28.309 ;
     RECT  17.376 26.629 17.4 28.403 ;
     RECT  60.384 27.301 60.408 28.403 ;
     RECT  38.352 26.917 38.376 28.405 ;
     RECT  38.16 28.405 38.376 28.451 ;
     RECT  45.6 27.971 45.912 28.453 ;
     RECT  36.672 27.877 36.696 28.547 ;
     RECT  38.16 28.451 38.184 28.547 ;
     RECT  57.936 27.923 57.96 28.643 ;
     RECT  55.056 21.155 55.08 28.741 ;
     RECT  54.72 28.741 55.08 28.787 ;
     RECT  81.312 27.877 81.432 28.835 ;
     RECT  77.616 26.915 78.984 28.885 ;
     RECT  75.84 27.443 75.864 28.933 ;
     RECT  77.088 28.885 78.984 28.933 ;
     RECT  45.6 28.453 46.728 28.979 ;
     RECT  71.376 28.309 72.912 29.027 ;
     RECT  81.36 28.835 81.432 29.029 ;
     RECT  67.008 28.115 68.904 29.075 ;
     RECT  75.84 28.933 78.984 29.075 ;
     RECT  81.36 29.029 81.48 29.075 ;
     RECT  5.328 26.771 5.352 29.171 ;
     RECT  18.6 27.395 18.912 29.365 ;
     RECT  23.328 26.387 24.456 29.365 ;
     RECT  39.84 24.181 41.256 29.365 ;
     RECT  54.72 28.787 54.744 29.507 ;
     RECT  12.96 21.061 13.656 29.605 ;
     RECT  26.448 26.243 26.472 29.605 ;
     RECT  12 29.605 13.656 29.893 ;
     RECT  75.84 29.075 76.392 29.939 ;
     RECT  74.16 29.557 74.184 29.989 ;
     RECT  42.768 29.077 42.792 30.035 ;
     RECT  39.216 29.365 41.256 30.227 ;
     RECT  74.16 29.989 74.712 30.227 ;
     RECT  81.408 29.075 81.48 30.229 ;
     RECT  45.6 28.979 45.912 30.325 ;
     RECT  45.6 30.325 46.776 30.611 ;
     RECT  21.12 29.365 21.144 30.661 ;
     RECT  82.704 27.923 84.312 30.661 ;
     RECT  85.344 27.875 86.52 30.661 ;
     RECT  12 29.893 14.232 30.707 ;
     RECT  2.4 12.563 2.712 30.709 ;
     RECT  51 26.243 51.816 30.709 ;
     RECT  77.376 29.075 78.984 30.709 ;
     RECT  67.008 29.075 67.512 30.757 ;
     RECT  71.856 29.027 72.912 30.757 ;
     RECT  55.296 30.181 55.32 30.803 ;
     RECT  23.328 29.365 24.6 30.851 ;
     RECT  70.224 30.661 70.248 30.853 ;
     RECT  71.664 30.757 72.912 30.853 ;
     RECT  21.072 30.661 21.144 30.899 ;
     RECT  26.448 29.605 26.808 30.899 ;
     RECT  70.224 30.853 72.912 30.899 ;
     RECT  7.8 24.563 8.112 30.949 ;
     RECT  44.4 30.037 44.424 30.995 ;
     RECT  51 30.709 52.056 30.997 ;
     RECT  12 30.707 13.704 31.091 ;
     RECT  18.6 29.365 19.032 31.091 ;
     RECT  28.608 22.835 30.168 31.189 ;
     RECT  31.2 18.179 31.224 31.189 ;
     RECT  26.448 30.899 26.472 31.237 ;
     RECT  60.336 29.365 60.36 31.237 ;
     RECT  28.608 31.189 31.224 31.285 ;
     RECT  2.4 30.709 3.432 31.379 ;
     RECT  27.936 31.285 31.224 31.379 ;
     RECT  70.224 30.899 71.16 31.381 ;
     RECT  7.8 30.949 8.232 31.475 ;
     RECT  59.856 31.237 60.36 31.477 ;
     RECT  36.288 29.941 36.312 31.523 ;
     RECT  59.04 31.477 60.36 31.523 ;
     RECT  70.176 31.381 71.16 31.571 ;
     RECT  81.36 30.229 81.48 31.619 ;
     RECT  21.168 31.141 21.672 31.811 ;
     RECT  50.4 30.997 52.056 31.811 ;
     RECT  34.8 27.395 35.112 31.861 ;
     RECT  31.2 31.379 31.224 31.909 ;
     RECT  32.208 24.085 32.232 31.909 ;
     RECT  59.04 31.523 59.88 31.909 ;
     RECT  21.648 31.811 21.672 31.955 ;
     RECT  47.328 31.189 47.352 31.955 ;
     RECT  58.656 31.909 59.88 31.955 ;
     RECT  67.008 30.757 67.848 31.955 ;
     RECT  14.88 30.757 14.904 32.195 ;
     RECT  77.232 30.709 78.984 32.195 ;
     RECT  20.256 32.005 20.28 32.339 ;
     RECT  74.688 30.227 74.712 32.483 ;
     RECT  27.936 31.379 30.168 32.485 ;
     RECT  31.2 31.909 32.232 32.485 ;
     RECT  26.208 31.237 26.472 32.531 ;
     RECT  77.76 32.195 78.984 32.531 ;
     RECT  67.008 31.955 67.512 32.533 ;
     RECT  12.96 31.091 13.704 32.725 ;
     RECT  58.656 31.955 58.68 32.771 ;
     RECT  12.96 32.725 13.8 32.821 ;
     RECT  45.6 30.611 45.912 32.917 ;
     RECT  70.176 31.571 70.2 33.013 ;
     RECT  78 32.531 78.984 33.059 ;
     RECT  47.856 32.437 47.88 33.107 ;
     RECT  38.4 33.013 38.424 33.205 ;
     RECT  3.696 32.245 3.72 33.299 ;
     RECT  18.6 31.091 18.912 33.301 ;
     RECT  17.136 32.917 17.16 33.347 ;
     RECT  38.016 33.205 38.424 33.395 ;
     RECT  66.864 32.533 67.512 33.397 ;
     RECT  61.8 26.771 62.112 33.493 ;
     RECT  53.04 31.909 53.064 33.539 ;
     RECT  61.8 33.493 63.096 33.541 ;
     RECT  59.856 31.955 59.88 33.587 ;
     RECT  2.4 31.379 2.712 33.589 ;
     RECT  26.448 32.531 26.472 33.589 ;
     RECT  27.936 32.485 32.232 33.589 ;
     RECT  12.96 32.821 14.232 33.635 ;
     RECT  12.96 33.635 14.136 33.637 ;
     RECT  50.4 31.811 51.768 33.637 ;
     RECT  64.416 31.669 64.44 33.827 ;
     RECT  76.944 33.493 76.968 33.827 ;
     RECT  12.768 33.637 14.136 33.829 ;
     RECT  18.6 33.301 19.368 33.875 ;
     RECT  26.448 33.589 32.232 33.875 ;
     RECT  6.336 30.181 6.36 33.973 ;
     RECT  23.328 30.851 24.456 34.021 ;
     RECT  38.016 33.395 38.04 34.067 ;
     RECT  34.512 31.861 35.112 34.117 ;
     RECT  39.888 30.227 41.256 34.117 ;
     RECT  50.208 33.637 51.768 34.117 ;
     RECT  50.208 34.117 51.864 34.165 ;
     RECT  26.448 33.875 30.168 34.259 ;
     RECT  31.2 33.875 32.232 34.259 ;
     RECT  12.624 33.829 14.136 34.357 ;
     RECT  16.176 34.357 16.2 34.499 ;
     RECT  34.512 34.117 35.208 34.547 ;
     RECT  12.192 34.357 14.136 34.787 ;
     RECT  61.296 33.541 63.096 34.787 ;
     RECT  64.512 34.117 64.536 34.835 ;
     RECT  66.144 33.397 67.512 34.835 ;
     RECT  12.768 34.787 14.136 34.883 ;
     RECT  39.36 34.117 41.256 34.931 ;
     RECT  49.248 34.165 51.864 34.931 ;
     RECT  66.96 34.835 67.512 34.933 ;
     RECT  68.88 29.075 68.904 34.933 ;
     RECT  66.96 34.933 68.904 35.123 ;
     RECT  49.248 34.931 51.768 35.363 ;
     RECT  18.6 33.875 18.912 35.461 ;
     RECT  44.976 32.917 45.912 35.461 ;
     RECT  18.6 35.461 19.416 35.699 ;
     RECT  2.4 33.589 2.808 35.747 ;
     RECT  34.512 34.547 35.112 35.797 ;
     RECT  31.2 34.259 31.224 35.893 ;
     RECT  32.208 34.259 32.232 35.893 ;
     RECT  58.128 34.981 58.152 35.939 ;
     RECT  60.048 34.981 60.072 35.987 ;
     RECT  6.336 33.973 6.648 36.085 ;
     RECT  27.936 34.259 30.168 36.227 ;
     RECT  6.336 36.085 6.792 36.515 ;
     RECT  31.2 35.893 32.232 36.515 ;
     RECT  53.616 35.845 53.64 36.515 ;
     RECT  72.6 30.899 72.912 36.517 ;
     RECT  26.448 34.259 26.472 36.661 ;
     RECT  72 36.517 72.912 36.899 ;
     RECT  6.72 36.515 6.792 36.901 ;
     RECT  7.8 31.475 8.112 36.901 ;
     RECT  18.6 35.699 18.912 36.901 ;
     RECT  44.496 35.461 45.912 36.901 ;
     RECT  61.296 34.787 62.112 36.901 ;
     RECT  16.56 36.901 16.584 37.043 ;
     RECT  50.208 35.363 51.768 37.091 ;
     RECT  70.176 33.013 70.776 37.091 ;
     RECT  9.216 36.997 9.24 37.187 ;
     RECT  23.328 34.021 24.552 37.427 ;
     RECT  39.888 34.931 41.256 37.429 ;
     RECT  64.416 36.469 64.44 37.475 ;
     RECT  28.608 36.227 30.168 37.477 ;
     RECT  31.2 36.515 31.224 37.477 ;
     RECT  18.6 36.901 19.032 37.573 ;
     RECT  61.104 36.901 62.112 37.573 ;
     RECT  39.12 37.429 41.256 37.813 ;
     RECT  74.352 36.901 74.376 37.859 ;
     RECT  28.608 37.477 31.224 38.051 ;
     RECT  26.448 36.661 26.76 38.101 ;
     RECT  44.496 36.901 46.152 38.147 ;
     RECT  47.184 37.573 47.208 38.147 ;
     RECT  78 33.059 78.888 38.149 ;
     RECT  39.12 37.813 41.352 38.243 ;
     RECT  20.4 33.541 20.424 38.291 ;
     RECT  57.696 38.149 57.72 38.389 ;
     RECT  44.496 38.147 46.104 38.675 ;
     RECT  10.56 27.395 10.584 38.677 ;
     RECT  18.6 37.573 19.176 38.723 ;
     RECT  6.72 36.901 8.112 38.819 ;
     RECT  34.464 35.797 35.112 38.819 ;
     RECT  61.056 37.573 62.112 38.819 ;
     RECT  26.448 38.101 27.336 39.251 ;
     RECT  77.184 38.149 78.888 39.251 ;
     RECT  21.36 38.677 21.384 39.395 ;
     RECT  51 37.091 51.768 39.637 ;
     RECT  82.704 30.661 86.52 39.683 ;
     RECT  7.8 38.819 8.112 39.733 ;
     RECT  61.248 38.819 62.112 39.733 ;
     RECT  6.72 38.819 6.744 39.779 ;
     RECT  48.864 39.493 48.888 39.827 ;
     RECT  12.96 34.883 14.136 39.877 ;
     RECT  56.4 24.515 56.712 39.877 ;
     RECT  57.696 38.389 58.68 39.877 ;
     RECT  75.84 29.939 75.864 39.877 ;
     RECT  81.408 31.619 81.48 39.877 ;
     RECT  9.84 38.677 10.584 39.923 ;
     RECT  56.4 39.877 58.68 39.923 ;
     RECT  81.12 39.877 81.48 39.923 ;
     RECT  39.888 38.243 41.352 40.019 ;
     RECT  61.248 39.733 62.52 40.067 ;
     RECT  7.8 39.733 8.28 40.309 ;
     RECT  18.6 38.723 18.912 40.309 ;
     RECT  72.6 36.899 72.912 40.357 ;
     RECT  72.24 40.357 72.912 40.405 ;
     RECT  12 39.877 14.136 40.499 ;
     RECT  44.496 38.675 45.912 40.501 ;
     RECT  10.56 39.923 10.584 40.549 ;
     RECT  12 40.499 13.992 40.549 ;
     RECT  72.048 40.405 72.912 40.597 ;
     RECT  58.368 39.923 58.68 40.691 ;
     RECT  50.544 39.637 51.768 40.739 ;
     RECT  10.56 40.549 13.992 40.787 ;
     RECT  66.96 35.123 67.512 40.885 ;
     RECT  56.4 39.923 57.048 41.027 ;
     RECT  39.888 40.019 41.256 41.029 ;
     RECT  7.68 40.309 8.28 41.075 ;
     RECT  75.84 39.877 76.104 41.075 ;
     RECT  66.96 40.885 67.752 41.171 ;
     RECT  82.704 39.683 85.464 41.219 ;
     RECT  81.12 39.923 81.432 41.269 ;
     RECT  16.08 40.981 16.104 41.605 ;
     RECT  44.496 40.501 46.152 41.651 ;
     RECT  37.008 41.605 37.032 41.747 ;
     RECT  67.2 41.171 67.752 41.747 ;
     RECT  70.176 37.091 70.2 41.747 ;
     RECT  15.792 41.605 16.104 41.891 ;
     RECT  39.408 41.029 41.256 41.891 ;
     RECT  37.056 41.893 37.08 42.035 ;
     RECT  54.576 37.429 54.6 42.037 ;
     RECT  54.576 42.037 54.696 42.083 ;
     RECT  18.288 40.309 18.912 42.131 ;
     RECT  42.72 41.029 42.744 42.227 ;
     RECT  12 40.787 13.992 42.323 ;
     RECT  44.496 41.651 46.008 42.419 ;
     RECT  72.048 40.597 73.272 42.469 ;
     RECT  54.672 42.083 54.696 42.515 ;
     RECT  82.704 41.219 84.312 42.707 ;
     RECT  51 40.739 51.768 42.709 ;
     RECT  67.2 41.747 67.512 42.709 ;
     RECT  31.2 38.051 31.224 42.755 ;
     RECT  59.424 42.181 59.448 42.851 ;
     RECT  39.888 41.891 41.256 42.997 ;
     RECT  44.496 42.419 45.912 43.283 ;
     RECT  12.96 42.323 13.992 43.285 ;
     RECT  55.392 43.189 55.416 43.331 ;
     RECT  71.328 42.469 73.272 43.331 ;
     RECT  61.8 40.067 62.52 43.379 ;
     RECT  60.72 42.997 60.744 43.525 ;
     RECT  61.8 43.379 62.112 43.525 ;
     RECT  44.496 43.283 44.52 43.619 ;
     RECT  26.448 39.251 26.472 43.667 ;
     RECT  60.72 43.525 62.112 43.763 ;
     RECT  12.048 43.285 13.992 43.861 ;
     RECT  23.328 37.427 24.456 43.955 ;
     RECT  60.72 43.763 60.744 43.955 ;
     RECT  12.048 43.861 14.28 44.051 ;
     RECT  50.88 42.709 51.768 44.053 ;
     RECT  66.96 42.709 67.512 44.099 ;
     RECT  50.736 44.053 51.768 44.101 ;
     RECT  75.84 41.075 75.912 44.341 ;
     RECT  16.08 41.891 16.104 44.437 ;
     RECT  32.208 36.515 32.232 44.437 ;
     RECT  33.312 40.117 33.336 44.437 ;
     RECT  45.6 43.283 45.912 44.437 ;
     RECT  7.8 41.075 8.28 44.483 ;
     RECT  38.832 42.997 38.856 44.483 ;
     RECT  12.96 44.051 14.28 44.627 ;
     RECT  78 39.251 78.888 45.011 ;
     RECT  78 45.011 78.6 45.061 ;
     RECT  16.08 44.437 16.776 45.155 ;
     RECT  82.704 42.707 84.072 45.299 ;
     RECT  44.112 43.909 44.136 45.301 ;
     RECT  36.144 43.861 36.168 45.347 ;
     RECT  23.328 43.955 24.312 45.541 ;
     RECT  68.88 35.123 68.904 45.541 ;
     RECT  32.208 44.437 33.336 45.635 ;
     RECT  45.6 44.437 46.728 45.635 ;
     RECT  75.072 44.341 75.912 45.635 ;
     RECT  32.208 45.635 33.048 45.731 ;
     RECT  34.8 38.819 35.112 45.829 ;
     RECT  23.232 45.541 24.312 45.877 ;
     RECT  9.456 44.965 9.48 45.971 ;
     RECT  64.608 43.861 64.632 45.971 ;
     RECT  44.064 45.301 44.136 46.021 ;
     RECT  80.208 41.269 81.432 46.067 ;
     RECT  10.56 40.787 10.584 46.211 ;
     RECT  16.08 45.155 16.104 46.211 ;
     RECT  68.88 45.541 69.528 46.499 ;
     RECT  34.656 45.829 35.112 46.693 ;
     RECT  39.888 42.997 42.168 46.693 ;
     RECT  77.568 45.061 78.6 46.693 ;
     RECT  39.888 46.693 42.312 46.787 ;
     RECT  7.8 44.483 8.112 46.885 ;
     RECT  45.6 45.635 45.912 46.885 ;
     RECT  7.68 46.885 8.112 46.933 ;
     RECT  36.336 45.685 36.36 46.981 ;
     RECT  44.016 46.021 44.136 47.075 ;
     RECT  36.336 46.981 37.128 47.123 ;
     RECT  32.208 45.731 32.52 47.219 ;
     RECT  28.608 38.051 30.168 47.315 ;
     RECT  26.16 46.117 26.184 47.363 ;
     RECT  85.44 41.219 85.464 47.413 ;
     RECT  86.496 39.683 86.52 47.413 ;
     RECT  71.952 43.331 73.272 47.461 ;
     RECT  56.4 41.027 56.712 47.701 ;
     RECT  58.368 40.691 58.392 47.797 ;
     RECT  34.176 46.693 35.112 47.845 ;
     RECT  36.336 47.123 36.36 47.845 ;
     RECT  61.8 43.763 62.112 47.845 ;
     RECT  63.168 46.645 63.192 47.845 ;
     RECT  34.176 47.845 36.36 47.891 ;
     RECT  61.8 47.845 63.192 47.891 ;
     RECT  77.472 46.693 78.6 47.891 ;
     RECT  57.792 47.797 58.392 47.939 ;
     RECT  71.376 47.461 73.272 47.989 ;
     RECT  82.704 45.299 83.712 47.989 ;
     RECT  22.944 45.877 24.312 48.083 ;
     RECT  45.6 46.885 46.008 48.083 ;
     RECT  47.856 47.845 47.88 48.083 ;
     RECT  54.528 47.365 54.552 48.083 ;
     RECT  32.208 47.219 32.472 48.131 ;
     RECT  61.8 47.891 63 48.133 ;
     RECT  44.016 47.075 44.04 48.325 ;
     RECT  26.208 47.845 26.232 48.373 ;
     RECT  34.176 47.891 35.448 48.373 ;
     RECT  56.4 47.701 56.808 48.373 ;
     RECT  57.792 47.939 57.816 48.373 ;
     RECT  11.424 47.845 11.448 48.419 ;
     RECT  26.208 48.373 26.568 48.419 ;
     RECT  56.4 48.373 57.816 48.419 ;
     RECT  60.384 47.845 60.408 48.419 ;
     RECT  71.376 47.989 73.32 48.419 ;
     RECT  85.44 47.413 86.52 48.419 ;
     RECT  24 48.083 24.312 48.421 ;
     RECT  26.544 48.419 26.568 48.421 ;
     RECT  68.88 46.499 68.904 48.421 ;
     RECT  69.984 47.845 70.008 48.421 ;
     RECT  81.12 46.067 81.432 48.421 ;
     RECT  82.656 47.989 83.712 48.421 ;
     RECT  75.408 45.635 75.912 48.469 ;
     RECT  33.552 48.373 35.448 48.659 ;
     RECT  75.168 48.469 75.912 48.709 ;
     RECT  77.472 47.891 78.312 48.709 ;
     RECT  85.44 48.419 86.472 48.755 ;
     RECT  17.52 47.845 17.544 48.805 ;
     RECT  50.208 44.101 51.768 48.899 ;
     RECT  37.632 48.469 37.656 48.901 ;
     RECT  86.304 48.755 86.472 48.947 ;
     RECT  68.88 48.421 70.008 48.995 ;
     RECT  75.168 48.709 78.312 48.995 ;
     RECT  37.008 48.901 37.656 48.997 ;
     RECT  81.12 48.421 83.712 48.997 ;
     RECT  36.912 48.997 37.656 49.043 ;
     RECT  60.096 48.421 60.12 49.045 ;
     RECT  67.2 44.099 67.512 49.045 ;
     RECT  68.88 48.995 69.624 49.045 ;
     RECT  71.52 48.419 73.32 49.045 ;
     RECT  12.96 44.627 13.848 49.091 ;
     RECT  66.048 48.421 66.072 49.091 ;
     RECT  79.536 48.229 79.56 49.091 ;
     RECT  13.056 49.091 13.848 49.093 ;
     RECT  36.912 49.043 37.032 49.139 ;
     RECT  49.008 48.853 49.032 49.139 ;
     RECT  24 48.421 25.224 49.379 ;
     RECT  61.536 48.133 63 49.429 ;
     RECT  22.944 48.083 22.968 49.475 ;
     RECT  51 48.899 51.768 49.477 ;
     RECT  47.136 48.997 47.16 49.571 ;
     RECT  61.536 49.429 63.816 49.571 ;
     RECT  67.2 49.045 69.624 49.571 ;
     RECT  76.944 48.995 78.312 49.571 ;
     RECT  16.944 48.805 17.544 49.619 ;
     RECT  32.208 48.131 32.232 49.619 ;
     RECT  33.552 48.659 35.256 49.619 ;
     RECT  55.248 48.421 55.272 49.619 ;
     RECT  71.52 49.045 73.368 49.669 ;
     RECT  43.92 48.325 44.04 49.861 ;
     RECT  85.2 50.005 85.224 50.053 ;
     RECT  86.304 48.947 86.328 50.053 ;
     RECT  33.6 49.619 35.256 50.099 ;
     RECT  39.888 46.787 41.256 50.099 ;
     RECT  88.224 50.053 88.248 50.101 ;
     RECT  59.76 49.045 60.12 50.197 ;
     RECT  26.544 48.421 27.336 50.243 ;
     RECT  59.28 50.197 60.12 50.243 ;
     RECT  51 49.477 51.816 50.291 ;
     RECT  61.536 49.571 63.672 50.291 ;
     RECT  75.168 48.995 75.864 50.341 ;
     RECT  42.288 46.787 42.312 50.389 ;
     RECT  49.248 49.957 49.272 50.389 ;
     RECT  51 50.291 51.768 50.389 ;
     RECT  81.12 48.997 83.832 50.389 ;
     RECT  81.12 50.389 83.928 50.437 ;
     RECT  74.4 50.341 75.864 50.531 ;
     RECT  85.2 50.053 86.328 50.533 ;
     RECT  64.992 50.437 65.016 50.579 ;
     RECT  7.68 46.933 8.424 50.677 ;
     RECT  85.2 50.533 86.616 50.723 ;
     RECT  45.6 48.083 45.912 50.725 ;
     RECT  47.328 50.629 47.352 50.725 ;
     RECT  33.6 50.099 35.208 50.963 ;
     RECT  42.288 50.389 42.36 50.965 ;
     RECT  42.288 50.965 42.408 51.011 ;
     RECT  70.896 49.669 73.368 51.059 ;
     RECT  63.648 50.291 63.672 51.061 ;
     RECT  13.056 49.093 14.232 51.107 ;
     RECT  71.52 51.059 73.368 51.109 ;
     RECT  54.576 50.917 54.6 51.203 ;
     RECT  24 49.379 24.936 51.253 ;
     RECT  67.2 49.571 67.752 51.253 ;
     RECT  68.88 49.571 69.624 51.253 ;
     RECT  33.6 50.963 35.112 51.301 ;
     RECT  75.168 50.531 75.864 51.301 ;
     RECT  45.6 50.725 47.352 51.347 ;
     RECT  80.88 50.437 83.928 51.347 ;
     RECT  85.2 50.723 85.224 51.347 ;
     RECT  75.168 51.301 75.96 51.443 ;
     RECT  6.72 50.677 8.424 51.539 ;
     RECT  21.648 48.277 21.672 51.635 ;
     RECT  61.536 50.291 62.472 51.635 ;
     RECT  75.168 51.443 75.864 51.635 ;
     RECT  16.944 49.619 16.968 51.685 ;
     RECT  59.28 50.243 59.64 51.685 ;
     RECT  61.536 51.635 62.112 51.685 ;
     RECT  7.68 51.539 8.424 51.733 ;
     RECT  9.696 50.101 9.72 51.733 ;
     RECT  67.008 51.253 70.536 51.779 ;
     RECT  59.28 51.685 62.112 51.827 ;
     RECT  55.008 51.733 55.032 51.875 ;
     RECT  69.312 51.779 70.536 51.875 ;
     RECT  47.328 51.347 47.352 51.877 ;
     RECT  16.944 51.685 17.016 51.923 ;
     RECT  20.592 48.949 20.616 51.923 ;
     RECT  42.336 51.011 42.408 51.923 ;
     RECT  43.68 49.861 44.04 51.923 ;
     RECT  47.328 51.877 47.688 51.923 ;
     RECT  49.248 50.389 51.768 51.923 ;
     RECT  67.008 51.779 68.088 51.923 ;
     RECT  71.52 51.109 73.512 51.923 ;
     RECT  13.056 51.107 13.656 51.971 ;
     RECT  39.936 50.099 41.256 51.971 ;
     RECT  4.944 46.501 4.968 52.021 ;
     RECT  16.944 51.923 16.968 52.021 ;
     RECT  70.512 51.875 70.536 52.021 ;
     RECT  71.52 51.923 73.368 52.021 ;
     RECT  16.416 52.021 16.968 52.163 ;
     RECT  38.88 51.253 38.904 52.163 ;
     RECT  70.512 52.021 73.368 52.163 ;
     RECT  56.4 48.419 57.336 52.165 ;
     RECT  7.68 51.733 9.72 52.211 ;
     RECT  63.648 51.061 64.2 52.211 ;
     RECT  75.168 51.635 75.576 52.213 ;
     RECT  18.6 42.131 18.912 52.405 ;
     RECT  59.28 51.827 59.784 52.499 ;
     RECT  28.608 47.315 29.928 52.549 ;
     RECT  13.104 51.971 13.656 52.595 ;
     RECT  81.12 51.347 83.712 52.645 ;
     RECT  42.336 51.923 42.36 52.691 ;
     RECT  24 51.253 25.08 52.693 ;
     RECT  26.544 50.243 26.568 52.693 ;
     RECT  56.4 52.165 57.624 52.693 ;
     RECT  24 52.693 26.568 52.739 ;
     RECT  33.072 51.301 35.112 52.739 ;
     RECT  25.968 52.739 26.568 52.835 ;
     RECT  55.68 52.693 57.624 52.835 ;
     RECT  79.824 52.405 79.848 52.837 ;
     RECT  34.8 52.739 35.112 52.933 ;
     RECT  7.8 52.211 9.24 52.979 ;
     RECT  39.984 51.971 41.256 52.979 ;
     RECT  79.584 52.837 79.848 52.979 ;
     RECT  44.016 51.923 44.04 52.981 ;
     RECT  45.6 51.347 45.912 52.981 ;
     RECT  63.648 52.211 63.672 52.981 ;
     RECT  67.2 51.923 68.088 52.981 ;
     RECT  66.72 52.981 68.088 53.027 ;
     RECT  79.824 52.979 79.848 53.027 ;
     RECT  80.832 52.645 83.712 53.027 ;
     RECT  18.6 52.405 19.512 53.029 ;
     RECT  28.464 52.549 29.928 53.029 ;
     RECT  44.016 52.981 45.912 53.029 ;
     RECT  87.744 50.101 88.248 53.029 ;
     RECT  4.944 52.021 5.112 53.075 ;
     RECT  16.416 52.163 16.44 53.075 ;
     RECT  27.696 53.029 29.928 53.075 ;
     RECT  49.248 51.923 49.272 53.125 ;
     RECT  29.04 53.075 29.928 53.173 ;
     RECT  24 52.739 24.936 53.219 ;
     RECT  71.52 52.163 73.368 53.267 ;
     RECT  70.512 52.163 70.536 53.317 ;
     RECT  80.832 53.027 81.528 53.365 ;
     RECT  50.832 51.923 51.768 53.411 ;
     RECT  59.76 52.499 59.784 53.411 ;
     RECT  72.24 53.267 73.368 53.459 ;
     RECT  70.512 53.317 71.208 53.507 ;
     RECT  80.736 53.365 81.528 53.507 ;
     RECT  72.6 53.459 73.368 53.509 ;
     RECT  13.104 52.595 13.512 53.557 ;
     RECT  44.016 53.029 46.008 53.557 ;
     RECT  63.264 52.981 63.672 53.557 ;
     RECT  77.568 49.571 78.312 53.557 ;
     RECT  82.992 53.027 83.712 53.557 ;
     RECT  56.4 52.835 57.624 53.603 ;
     RECT  63.264 53.557 63.816 53.603 ;
     RECT  70.512 53.507 71.016 53.603 ;
     RECT  86.688 51.781 86.712 53.603 ;
     RECT  44.016 53.557 46.152 53.653 ;
     RECT  47.664 51.923 47.688 53.653 ;
     RECT  29.04 53.173 30.024 53.699 ;
     RECT  44.016 53.653 47.688 53.699 ;
     RECT  44.016 53.699 47.112 53.795 ;
     RECT  40.08 52.979 41.256 53.845 ;
     RECT  64.944 53.749 64.968 53.891 ;
     RECT  40.08 53.845 41.592 53.941 ;
     RECT  82.992 53.557 84.36 53.941 ;
     RECT  69.312 51.875 69.336 53.989 ;
     RECT  18.48 53.029 19.512 54.037 ;
     RECT  69.264 53.989 69.336 54.037 ;
     RECT  33.072 52.739 33.816 54.085 ;
     RECT  34.8 52.933 35.592 54.085 ;
     RECT  72.6 53.509 73.416 54.085 ;
     RECT  74.496 52.213 75.576 54.085 ;
     RECT  87.696 53.029 88.248 54.085 ;
     RECT  27.696 53.075 27.864 54.133 ;
     RECT  29.04 53.699 29.712 54.133 ;
     RECT  61.008 51.827 62.112 54.133 ;
     RECT  9.216 52.979 9.24 54.179 ;
     RECT  72.6 54.085 75.576 54.179 ;
     RECT  77.568 53.557 78.408 54.179 ;
     RECT  81.12 53.507 81.528 54.179 ;
     RECT  18.48 54.037 19.944 54.181 ;
     RECT  33.072 54.085 35.592 54.227 ;
     RECT  26.544 52.835 26.568 54.229 ;
     RECT  27.696 54.133 29.712 54.229 ;
     RECT  82.992 53.941 84.744 54.277 ;
     RECT  6.288 53.557 6.312 54.323 ;
     RECT  24 53.219 24.456 54.325 ;
     RECT  69.264 54.037 69.384 54.325 ;
     RECT  87.696 54.085 88.488 54.325 ;
     RECT  49.248 53.125 49.512 54.371 ;
     RECT  13.104 53.557 13.608 54.419 ;
     RECT  66.72 53.027 67.656 54.421 ;
     RECT  72.6 54.179 74.52 54.421 ;
     RECT  24 54.325 25.08 54.467 ;
     RECT  26.544 54.229 29.712 54.563 ;
     RECT  66.288 54.421 67.656 54.565 ;
     RECT  68.688 54.325 69.384 54.565 ;
     RECT  89.904 54.517 89.928 54.565 ;
     RECT  50.832 53.411 51.576 54.611 ;
     RECT  87.648 54.325 88.488 54.613 ;
     RECT  89.712 54.565 89.928 54.613 ;
     RECT  22.752 53.557 22.776 54.659 ;
     RECT  45.6 53.795 47.112 54.659 ;
     RECT  56.4 53.603 57.432 54.661 ;
     RECT  78 54.179 78.408 54.661 ;
     RECT  87.648 54.613 89.928 54.661 ;
     RECT  82.56 54.277 84.744 54.707 ;
     RECT  18.432 54.181 19.944 54.709 ;
     RECT  26.544 54.563 26.568 54.755 ;
     RECT  63.648 53.603 63.816 54.755 ;
     RECT  72.48 54.421 74.52 54.755 ;
     RECT  39.312 53.941 41.592 54.851 ;
     RECT  39.312 54.851 41.256 54.947 ;
     RECT  11.376 54.085 11.4 54.949 ;
     RECT  17.712 54.709 19.944 54.949 ;
     RECT  85.968 54.037 85.992 55.043 ;
     RECT  66.288 54.565 69.384 55.045 ;
     RECT  70.512 53.603 70.536 55.045 ;
     RECT  60.528 54.133 62.112 55.189 ;
     RECT  72.48 54.755 74.088 55.189 ;
     RECT  7.8 52.979 8.112 55.237 ;
     RECT  13.104 54.419 13.512 55.237 ;
     RECT  47.088 54.659 47.112 55.237 ;
     RECT  50.832 54.611 51.312 55.237 ;
     RECT  59.424 53.893 59.448 55.237 ;
     RECT  63.792 54.755 63.816 55.237 ;
     RECT  72.336 55.189 74.088 55.237 ;
     RECT  10.896 54.949 11.4 55.285 ;
     RECT  17.328 54.949 19.944 55.285 ;
     RECT  33.792 54.227 35.592 55.285 ;
     RECT  37.008 54.517 37.032 55.285 ;
     RECT  44.016 53.795 44.424 55.285 ;
     RECT  4.944 53.075 4.968 55.331 ;
     RECT  39.312 54.947 40.632 55.331 ;
     RECT  44.016 55.285 44.52 55.333 ;
     RECT  45.6 54.659 46.104 55.333 ;
     RECT  53.232 52.357 53.256 55.477 ;
     RECT  75.936 54.181 75.96 55.477 ;
     RECT  36.816 55.285 37.032 55.669 ;
     RECT  66.288 55.045 70.536 55.717 ;
     RECT  71.664 55.237 74.088 55.717 ;
     RECT  33.456 55.285 35.592 55.765 ;
     RECT  36.816 55.669 37.896 55.765 ;
     RECT  66.288 55.717 74.088 55.765 ;
     RECT  26.256 55.237 26.28 55.813 ;
     RECT  44.016 55.333 46.104 55.813 ;
     RECT  47.088 55.237 47.208 55.813 ;
     RECT  49.488 54.371 49.512 55.813 ;
     RECT  50.736 55.237 51.312 55.813 ;
     RECT  56.208 54.661 57.432 55.813 ;
     RECT  59.088 55.237 59.448 55.813 ;
     RECT  87.36 54.661 89.928 55.813 ;
     RECT  10.128 55.285 11.4 55.861 ;
     RECT  12.624 55.237 13.512 55.861 ;
     RECT  14.544 55.813 15.528 55.861 ;
     RECT  16.656 55.285 19.944 55.861 ;
     RECT  20.928 53.557 20.952 55.861 ;
     RECT  24 54.467 25.032 55.861 ;
     RECT  26.256 55.813 26.376 55.861 ;
     RECT  27.696 54.563 29.712 55.861 ;
     RECT  33.456 55.765 37.896 55.861 ;
     RECT  42.768 55.813 42.792 55.861 ;
     RECT  44.016 55.813 47.208 55.861 ;
     RECT  48.336 55.813 48.36 55.861 ;
     RECT  49.488 55.813 51.312 55.861 ;
     RECT  52.848 55.477 53.256 55.861 ;
     RECT  56.208 55.813 59.448 55.861 ;
     RECT  60.432 55.189 62.112 55.861 ;
     RECT  63.792 55.237 64.392 55.861 ;
     RECT  66.096 55.765 74.088 55.861 ;
     RECT  75.12 55.477 75.96 55.861 ;
     RECT  78 54.661 78.504 55.861 ;
     RECT  81.12 54.179 81.144 55.861 ;
     RECT  83.232 54.707 84.744 55.861 ;
     RECT  87.024 55.813 89.928 55.861 ;
     RECT  9.936 55.861 20.952 55.909 ;
     RECT  55.92 55.861 64.392 55.909 ;
     RECT  42.096 55.861 54.312 55.957 ;
     RECT  55.344 55.909 64.392 55.957 ;
     RECT  66.096 55.861 76.488 55.957 ;
     RECT  78 55.861 84.84 55.957 ;
     RECT  26.256 55.861 31.656 56.005 ;
     RECT  66.096 55.957 76.584 56.053 ;
     RECT  9.936 55.909 21.096 56.101 ;
     RECT  26.256 56.005 31.944 56.101 ;
     RECT  39.792 55.331 40.632 56.101 ;
     RECT  42.096 55.957 64.392 56.101 ;
     RECT  66.096 56.053 76.872 56.101 ;
     RECT  2.4 35.747 2.712 56.169 ;
     RECT  2.4 56.169 2.52 56.183 ;
     RECT  39.792 56.101 64.392 56.245 ;
     RECT  65.52 56.101 76.872 56.245 ;
     RECT  33.36 55.861 37.896 56.341 ;
     RECT  7.632 55.237 8.52 56.389 ;
     RECT  9.648 56.101 21.48 56.389 ;
     RECT  22.608 55.861 25.032 56.389 ;
     RECT  26.256 56.101 32.328 56.389 ;
     RECT  33.36 56.341 38.088 56.389 ;
     RECT  39.792 56.245 76.872 56.389 ;
     RECT  78 55.957 84.936 56.389 ;
     RECT  86.256 55.861 89.928 56.389 ;
     RECT  7.344 56.389 25.032 56.437 ;
     RECT  33.36 56.389 38.184 56.437 ;
     RECT  39.504 56.389 76.872 56.437 ;
     RECT  33.36 56.437 76.872 56.677 ;
     RECT  78 56.389 89.928 56.677 ;
     RECT  7.248 56.437 25.032 56.965 ;
     RECT  26.16 56.389 32.328 56.965 ;
     RECT  33.36 56.677 89.928 56.965 ;
     RECT  7.248 56.965 89.928 57.589 ;
     RECT  7.152 57.589 89.928 58.165 ;
     RECT  7.056 58.165 89.928 58.256 ;
  END
END ot_hbm_w2_stn_slice5
END LIBRARY
